VERSION 5.8 ;
BUSBITCHARS "[]" ;
DIVIDERCHAR "/" ;
UNITS
    DATABASE MICRONS 1000 ;
END UNITS

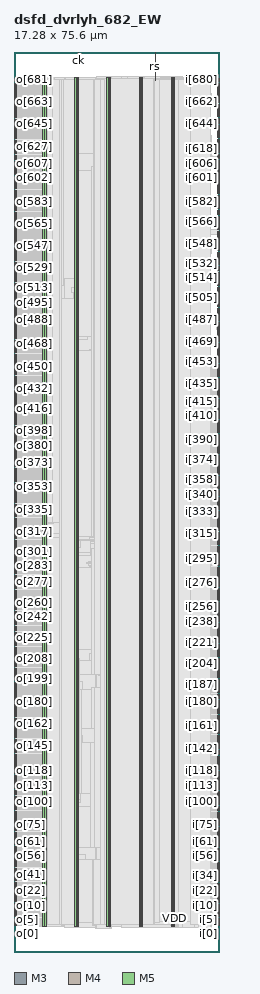
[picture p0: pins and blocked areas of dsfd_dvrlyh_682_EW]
MACRO dsfd_dvrlyh_682_EW
  FOREIGN dsfd_dvrlyh_682_EW 0 0 ;
  CLASS BLOCK ;
  SIZE 17.28 BY 75.6 ;
  PIN ck
    DIRECTION INPUT ;
    USE SIGNAL ;
    PORT
      LAYER M3 ;
        RECT  5.4 75.456 5.418 75.6 ;
    END
    PORT
      LAYER M3 ;
        RECT  5.4 74.683 5.418 75.468 ;
    END
  END ck
  PIN ck_o
    DIRECTION OUTPUT ;
    USE SIGNAL ;
    PORT
      LAYER M4 ;
        RECT  0 73.392 0.192 73.416 ;
    END
  END ck_o
  PIN i[0]
    DIRECTION INPUT ;
    USE SIGNAL ;
    PORT
      LAYER M4 ;
        RECT  17.088 2.208 17.28 2.232 ;
    END
  END i[0]
  PIN i[100]
    DIRECTION INPUT ;
    USE SIGNAL ;
    PORT
      LAYER M4 ;
        RECT  17.088 12.672 17.28 12.696 ;
    END
  END i[100]
  PIN i[101]
    DIRECTION INPUT ;
    USE SIGNAL ;
    PORT
      LAYER M4 ;
        RECT  17.088 12.768 17.28 12.792 ;
    END
  END i[101]
  PIN i[102]
    DIRECTION INPUT ;
    USE SIGNAL ;
    PORT
      LAYER M4 ;
        RECT  17.088 12.864 17.28 12.888 ;
    END
  END i[102]
  PIN i[103]
    DIRECTION INPUT ;
    USE SIGNAL ;
    PORT
      LAYER M4 ;
        RECT  17.088 13.008 17.28 13.032 ;
    END
  END i[103]
  PIN i[104]
    DIRECTION INPUT ;
    USE SIGNAL ;
    PORT
      LAYER M4 ;
        RECT  17.088 13.104 17.28 13.128 ;
    END
  END i[104]
  PIN i[105]
    DIRECTION INPUT ;
    USE SIGNAL ;
    PORT
      LAYER M4 ;
        RECT  17.088 13.2 17.28 13.224 ;
    END
  END i[105]
  PIN i[106]
    DIRECTION INPUT ;
    USE SIGNAL ;
    PORT
      LAYER M4 ;
        RECT  17.088 13.296 17.28 13.32 ;
    END
  END i[106]
  PIN i[107]
    DIRECTION INPUT ;
    USE SIGNAL ;
    PORT
      LAYER M4 ;
        RECT  17.088 13.392 17.28 13.416 ;
    END
  END i[107]
  PIN i[108]
    DIRECTION INPUT ;
    USE SIGNAL ;
    PORT
      LAYER M4 ;
        RECT  17.088 13.488 17.28 13.512 ;
    END
  END i[108]
  PIN i[109]
    DIRECTION INPUT ;
    USE SIGNAL ;
    PORT
      LAYER M4 ;
        RECT  17.088 13.632 17.28 13.656 ;
    END
  END i[109]
  PIN i[10]
    DIRECTION INPUT ;
    USE SIGNAL ;
    PORT
      LAYER M4 ;
        RECT  17.088 3.264 17.28 3.288 ;
    END
  END i[10]
  PIN i[110]
    DIRECTION INPUT ;
    USE SIGNAL ;
    PORT
      LAYER M4 ;
        RECT  17.088 13.728 17.28 13.752 ;
    END
  END i[110]
  PIN i[111]
    DIRECTION INPUT ;
    USE SIGNAL ;
    PORT
      LAYER M4 ;
        RECT  17.088 13.824 17.28 13.848 ;
    END
  END i[111]
  PIN i[112]
    DIRECTION INPUT ;
    USE SIGNAL ;
    PORT
      LAYER M4 ;
        RECT  17.088 13.92 17.28 13.944 ;
    END
  END i[112]
  PIN i[113]
    DIRECTION INPUT ;
    USE SIGNAL ;
    PORT
      LAYER M4 ;
        RECT  17.088 14.016 17.28 14.04 ;
    END
  END i[113]
  PIN i[114]
    DIRECTION INPUT ;
    USE SIGNAL ;
    PORT
      LAYER M4 ;
        RECT  17.088 14.16 17.28 14.184 ;
    END
  END i[114]
  PIN i[115]
    DIRECTION INPUT ;
    USE SIGNAL ;
    PORT
      LAYER M4 ;
        RECT  17.088 14.256 17.28 14.28 ;
    END
  END i[115]
  PIN i[116]
    DIRECTION INPUT ;
    USE SIGNAL ;
    PORT
      LAYER M4 ;
        RECT  17.088 14.352 17.28 14.376 ;
    END
  END i[116]
  PIN i[117]
    DIRECTION INPUT ;
    USE SIGNAL ;
    PORT
      LAYER M4 ;
        RECT  17.088 14.448 17.28 14.472 ;
    END
  END i[117]
  PIN i[118]
    DIRECTION INPUT ;
    USE SIGNAL ;
    PORT
      LAYER M4 ;
        RECT  17.088 14.544 17.28 14.568 ;
    END
  END i[118]
  PIN i[119]
    DIRECTION INPUT ;
    USE SIGNAL ;
    PORT
      LAYER M4 ;
        RECT  17.088 14.64 17.28 14.664 ;
    END
  END i[119]
  PIN i[11]
    DIRECTION INPUT ;
    USE SIGNAL ;
    PORT
      LAYER M4 ;
        RECT  17.088 3.36 17.28 3.384 ;
    END
  END i[11]
  PIN i[120]
    DIRECTION INPUT ;
    USE SIGNAL ;
    PORT
      LAYER M4 ;
        RECT  17.088 14.784 17.28 14.808 ;
    END
  END i[120]
  PIN i[121]
    DIRECTION INPUT ;
    USE SIGNAL ;
    PORT
      LAYER M4 ;
        RECT  17.088 14.88 17.28 14.904 ;
    END
  END i[121]
  PIN i[122]
    DIRECTION INPUT ;
    USE SIGNAL ;
    PORT
      LAYER M4 ;
        RECT  17.088 14.976 17.28 15 ;
    END
  END i[122]
  PIN i[123]
    DIRECTION INPUT ;
    USE SIGNAL ;
    PORT
      LAYER M4 ;
        RECT  17.088 15.072 17.28 15.096 ;
    END
  END i[123]
  PIN i[124]
    DIRECTION INPUT ;
    USE SIGNAL ;
    PORT
      LAYER M4 ;
        RECT  17.088 15.168 17.28 15.192 ;
    END
  END i[124]
  PIN i[125]
    DIRECTION INPUT ;
    USE SIGNAL ;
    PORT
      LAYER M4 ;
        RECT  17.088 15.312 17.28 15.336 ;
    END
  END i[125]
  PIN i[126]
    DIRECTION INPUT ;
    USE SIGNAL ;
    PORT
      LAYER M4 ;
        RECT  17.088 15.408 17.28 15.432 ;
    END
  END i[126]
  PIN i[127]
    DIRECTION INPUT ;
    USE SIGNAL ;
    PORT
      LAYER M4 ;
        RECT  17.088 15.504 17.28 15.528 ;
    END
  END i[127]
  PIN i[128]
    DIRECTION INPUT ;
    USE SIGNAL ;
    PORT
      LAYER M4 ;
        RECT  17.088 15.6 17.28 15.624 ;
    END
  END i[128]
  PIN i[129]
    DIRECTION INPUT ;
    USE SIGNAL ;
    PORT
      LAYER M4 ;
        RECT  17.088 15.696 17.28 15.72 ;
    END
  END i[129]
  PIN i[12]
    DIRECTION INPUT ;
    USE SIGNAL ;
    PORT
      LAYER M4 ;
        RECT  17.088 3.456 17.28 3.48 ;
    END
  END i[12]
  PIN i[130]
    DIRECTION INPUT ;
    USE SIGNAL ;
    PORT
      LAYER M4 ;
        RECT  17.088 15.792 17.28 15.816 ;
    END
  END i[130]
  PIN i[131]
    DIRECTION INPUT ;
    USE SIGNAL ;
    PORT
      LAYER M4 ;
        RECT  17.088 15.936 17.28 15.96 ;
    END
  END i[131]
  PIN i[132]
    DIRECTION INPUT ;
    USE SIGNAL ;
    PORT
      LAYER M4 ;
        RECT  17.088 16.032 17.28 16.056 ;
    END
  END i[132]
  PIN i[133]
    DIRECTION INPUT ;
    USE SIGNAL ;
    PORT
      LAYER M4 ;
        RECT  17.088 16.128 17.28 16.152 ;
    END
  END i[133]
  PIN i[134]
    DIRECTION INPUT ;
    USE SIGNAL ;
    PORT
      LAYER M4 ;
        RECT  17.088 16.224 17.28 16.248 ;
    END
  END i[134]
  PIN i[135]
    DIRECTION INPUT ;
    USE SIGNAL ;
    PORT
      LAYER M4 ;
        RECT  17.088 16.32 17.28 16.344 ;
    END
  END i[135]
  PIN i[136]
    DIRECTION INPUT ;
    USE SIGNAL ;
    PORT
      LAYER M4 ;
        RECT  17.088 16.416 17.28 16.44 ;
    END
  END i[136]
  PIN i[137]
    DIRECTION INPUT ;
    USE SIGNAL ;
    PORT
      LAYER M4 ;
        RECT  17.088 16.56 17.28 16.584 ;
    END
  END i[137]
  PIN i[138]
    DIRECTION INPUT ;
    USE SIGNAL ;
    PORT
      LAYER M4 ;
        RECT  17.088 16.656 17.28 16.68 ;
    END
  END i[138]
  PIN i[139]
    DIRECTION INPUT ;
    USE SIGNAL ;
    PORT
      LAYER M4 ;
        RECT  17.088 16.752 17.28 16.776 ;
    END
  END i[139]
  PIN i[13]
    DIRECTION INPUT ;
    USE SIGNAL ;
    PORT
      LAYER M4 ;
        RECT  17.088 3.6 17.28 3.624 ;
    END
  END i[13]
  PIN i[140]
    DIRECTION INPUT ;
    USE SIGNAL ;
    PORT
      LAYER M4 ;
        RECT  17.088 16.848 17.28 16.872 ;
    END
  END i[140]
  PIN i[141]
    DIRECTION INPUT ;
    USE SIGNAL ;
    PORT
      LAYER M4 ;
        RECT  17.088 16.944 17.28 16.968 ;
    END
  END i[141]
  PIN i[142]
    DIRECTION INPUT ;
    USE SIGNAL ;
    PORT
      LAYER M4 ;
        RECT  17.088 17.088 17.28 17.112 ;
    END
  END i[142]
  PIN i[143]
    DIRECTION INPUT ;
    USE SIGNAL ;
    PORT
      LAYER M4 ;
        RECT  17.088 17.184 17.28 17.208 ;
    END
  END i[143]
  PIN i[144]
    DIRECTION INPUT ;
    USE SIGNAL ;
    PORT
      LAYER M4 ;
        RECT  17.088 17.28 17.28 17.304 ;
    END
  END i[144]
  PIN i[145]
    DIRECTION INPUT ;
    USE SIGNAL ;
    PORT
      LAYER M4 ;
        RECT  17.088 17.376 17.28 17.4 ;
    END
  END i[145]
  PIN i[146]
    DIRECTION INPUT ;
    USE SIGNAL ;
    PORT
      LAYER M4 ;
        RECT  17.088 17.472 17.28 17.496 ;
    END
  END i[146]
  PIN i[147]
    DIRECTION INPUT ;
    USE SIGNAL ;
    PORT
      LAYER M4 ;
        RECT  17.088 17.568 17.28 17.592 ;
    END
  END i[147]
  PIN i[148]
    DIRECTION INPUT ;
    USE SIGNAL ;
    PORT
      LAYER M4 ;
        RECT  17.088 17.712 17.28 17.736 ;
    END
  END i[148]
  PIN i[149]
    DIRECTION INPUT ;
    USE SIGNAL ;
    PORT
      LAYER M4 ;
        RECT  17.088 17.808 17.28 17.832 ;
    END
  END i[149]
  PIN i[14]
    DIRECTION INPUT ;
    USE SIGNAL ;
    PORT
      LAYER M4 ;
        RECT  17.088 3.696 17.28 3.72 ;
    END
  END i[14]
  PIN i[150]
    DIRECTION INPUT ;
    USE SIGNAL ;
    PORT
      LAYER M4 ;
        RECT  17.088 17.904 17.28 17.928 ;
    END
  END i[150]
  PIN i[151]
    DIRECTION INPUT ;
    USE SIGNAL ;
    PORT
      LAYER M4 ;
        RECT  17.088 18 17.28 18.024 ;
    END
  END i[151]
  PIN i[152]
    DIRECTION INPUT ;
    USE SIGNAL ;
    PORT
      LAYER M4 ;
        RECT  17.088 18.096 17.28 18.12 ;
    END
  END i[152]
  PIN i[153]
    DIRECTION INPUT ;
    USE SIGNAL ;
    PORT
      LAYER M4 ;
        RECT  17.088 18.192 17.28 18.216 ;
    END
  END i[153]
  PIN i[154]
    DIRECTION INPUT ;
    USE SIGNAL ;
    PORT
      LAYER M4 ;
        RECT  17.088 18.336 17.28 18.36 ;
    END
  END i[154]
  PIN i[155]
    DIRECTION INPUT ;
    USE SIGNAL ;
    PORT
      LAYER M4 ;
        RECT  17.088 18.432 17.28 18.456 ;
    END
  END i[155]
  PIN i[156]
    DIRECTION INPUT ;
    USE SIGNAL ;
    PORT
      LAYER M4 ;
        RECT  17.088 18.528 17.28 18.552 ;
    END
  END i[156]
  PIN i[157]
    DIRECTION INPUT ;
    USE SIGNAL ;
    PORT
      LAYER M4 ;
        RECT  17.088 18.624 17.28 18.648 ;
    END
  END i[157]
  PIN i[158]
    DIRECTION INPUT ;
    USE SIGNAL ;
    PORT
      LAYER M4 ;
        RECT  17.088 18.72 17.28 18.744 ;
    END
  END i[158]
  PIN i[159]
    DIRECTION INPUT ;
    USE SIGNAL ;
    PORT
      LAYER M4 ;
        RECT  17.088 18.864 17.28 18.888 ;
    END
  END i[159]
  PIN i[15]
    DIRECTION INPUT ;
    USE SIGNAL ;
    PORT
      LAYER M4 ;
        RECT  17.088 3.792 17.28 3.816 ;
    END
  END i[15]
  PIN i[160]
    DIRECTION INPUT ;
    USE SIGNAL ;
    PORT
      LAYER M4 ;
        RECT  17.088 18.96 17.28 18.984 ;
    END
  END i[160]
  PIN i[161]
    DIRECTION INPUT ;
    USE SIGNAL ;
    PORT
      LAYER M4 ;
        RECT  17.088 19.056 17.28 19.08 ;
    END
  END i[161]
  PIN i[162]
    DIRECTION INPUT ;
    USE SIGNAL ;
    PORT
      LAYER M4 ;
        RECT  17.088 19.152 17.28 19.176 ;
    END
  END i[162]
  PIN i[163]
    DIRECTION INPUT ;
    USE SIGNAL ;
    PORT
      LAYER M4 ;
        RECT  17.088 19.248 17.28 19.272 ;
    END
  END i[163]
  PIN i[164]
    DIRECTION INPUT ;
    USE SIGNAL ;
    PORT
      LAYER M4 ;
        RECT  17.088 19.344 17.28 19.368 ;
    END
  END i[164]
  PIN i[165]
    DIRECTION INPUT ;
    USE SIGNAL ;
    PORT
      LAYER M4 ;
        RECT  17.088 19.488 17.28 19.512 ;
    END
  END i[165]
  PIN i[166]
    DIRECTION INPUT ;
    USE SIGNAL ;
    PORT
      LAYER M4 ;
        RECT  17.088 19.584 17.28 19.608 ;
    END
  END i[166]
  PIN i[167]
    DIRECTION INPUT ;
    USE SIGNAL ;
    PORT
      LAYER M4 ;
        RECT  17.088 19.68 17.28 19.704 ;
    END
  END i[167]
  PIN i[168]
    DIRECTION INPUT ;
    USE SIGNAL ;
    PORT
      LAYER M4 ;
        RECT  17.088 19.776 17.28 19.8 ;
    END
  END i[168]
  PIN i[169]
    DIRECTION INPUT ;
    USE SIGNAL ;
    PORT
      LAYER M4 ;
        RECT  17.088 19.872 17.28 19.896 ;
    END
  END i[169]
  PIN i[16]
    DIRECTION INPUT ;
    USE SIGNAL ;
    PORT
      LAYER M4 ;
        RECT  17.088 3.888 17.28 3.912 ;
    END
  END i[16]
  PIN i[170]
    DIRECTION INPUT ;
    USE SIGNAL ;
    PORT
      LAYER M4 ;
        RECT  17.088 20.016 17.28 20.04 ;
    END
  END i[170]
  PIN i[171]
    DIRECTION INPUT ;
    USE SIGNAL ;
    PORT
      LAYER M4 ;
        RECT  17.088 20.112 17.28 20.136 ;
    END
  END i[171]
  PIN i[172]
    DIRECTION INPUT ;
    USE SIGNAL ;
    PORT
      LAYER M4 ;
        RECT  17.088 20.208 17.28 20.232 ;
    END
  END i[172]
  PIN i[173]
    DIRECTION INPUT ;
    USE SIGNAL ;
    PORT
      LAYER M4 ;
        RECT  17.088 20.304 17.28 20.328 ;
    END
  END i[173]
  PIN i[174]
    DIRECTION INPUT ;
    USE SIGNAL ;
    PORT
      LAYER M4 ;
        RECT  17.088 20.4 17.28 20.424 ;
    END
  END i[174]
  PIN i[175]
    DIRECTION INPUT ;
    USE SIGNAL ;
    PORT
      LAYER M4 ;
        RECT  17.088 20.496 17.28 20.52 ;
    END
  END i[175]
  PIN i[176]
    DIRECTION INPUT ;
    USE SIGNAL ;
    PORT
      LAYER M4 ;
        RECT  17.088 20.64 17.28 20.664 ;
    END
  END i[176]
  PIN i[177]
    DIRECTION INPUT ;
    USE SIGNAL ;
    PORT
      LAYER M4 ;
        RECT  17.088 20.736 17.28 20.76 ;
    END
  END i[177]
  PIN i[178]
    DIRECTION INPUT ;
    USE SIGNAL ;
    PORT
      LAYER M4 ;
        RECT  17.088 20.832 17.28 20.856 ;
    END
  END i[178]
  PIN i[179]
    DIRECTION INPUT ;
    USE SIGNAL ;
    PORT
      LAYER M4 ;
        RECT  17.088 20.928 17.28 20.952 ;
    END
  END i[179]
  PIN i[17]
    DIRECTION INPUT ;
    USE SIGNAL ;
    PORT
      LAYER M4 ;
        RECT  17.088 3.984 17.28 4.008 ;
    END
  END i[17]
  PIN i[180]
    DIRECTION INPUT ;
    USE SIGNAL ;
    PORT
      LAYER M4 ;
        RECT  17.088 21.024 17.28 21.048 ;
    END
  END i[180]
  PIN i[181]
    DIRECTION INPUT ;
    USE SIGNAL ;
    PORT
      LAYER M4 ;
        RECT  17.088 21.12 17.28 21.144 ;
    END
  END i[181]
  PIN i[182]
    DIRECTION INPUT ;
    USE SIGNAL ;
    PORT
      LAYER M4 ;
        RECT  17.088 21.264 17.28 21.288 ;
    END
  END i[182]
  PIN i[183]
    DIRECTION INPUT ;
    USE SIGNAL ;
    PORT
      LAYER M4 ;
        RECT  17.088 21.36 17.28 21.384 ;
    END
  END i[183]
  PIN i[184]
    DIRECTION INPUT ;
    USE SIGNAL ;
    PORT
      LAYER M4 ;
        RECT  17.088 21.456 17.28 21.48 ;
    END
  END i[184]
  PIN i[185]
    DIRECTION INPUT ;
    USE SIGNAL ;
    PORT
      LAYER M4 ;
        RECT  17.088 21.552 17.28 21.576 ;
    END
  END i[185]
  PIN i[186]
    DIRECTION INPUT ;
    USE SIGNAL ;
    PORT
      LAYER M4 ;
        RECT  17.088 21.648 17.28 21.672 ;
    END
  END i[186]
  PIN i[187]
    DIRECTION INPUT ;
    USE SIGNAL ;
    PORT
      LAYER M4 ;
        RECT  17.088 21.792 17.28 21.816 ;
    END
  END i[187]
  PIN i[188]
    DIRECTION INPUT ;
    USE SIGNAL ;
    PORT
      LAYER M4 ;
        RECT  17.088 21.888 17.28 21.912 ;
    END
  END i[188]
  PIN i[189]
    DIRECTION INPUT ;
    USE SIGNAL ;
    PORT
      LAYER M4 ;
        RECT  17.088 21.984 17.28 22.008 ;
    END
  END i[189]
  PIN i[18]
    DIRECTION INPUT ;
    USE SIGNAL ;
    PORT
      LAYER M4 ;
        RECT  17.088 4.128 17.28 4.152 ;
    END
  END i[18]
  PIN i[190]
    DIRECTION INPUT ;
    USE SIGNAL ;
    PORT
      LAYER M4 ;
        RECT  17.088 22.08 17.28 22.104 ;
    END
  END i[190]
  PIN i[191]
    DIRECTION INPUT ;
    USE SIGNAL ;
    PORT
      LAYER M4 ;
        RECT  17.088 22.176 17.28 22.2 ;
    END
  END i[191]
  PIN i[192]
    DIRECTION INPUT ;
    USE SIGNAL ;
    PORT
      LAYER M4 ;
        RECT  17.088 22.272 17.28 22.296 ;
    END
  END i[192]
  PIN i[193]
    DIRECTION INPUT ;
    USE SIGNAL ;
    PORT
      LAYER M4 ;
        RECT  17.088 22.416 17.28 22.44 ;
    END
  END i[193]
  PIN i[194]
    DIRECTION INPUT ;
    USE SIGNAL ;
    PORT
      LAYER M4 ;
        RECT  17.088 22.512 17.28 22.536 ;
    END
  END i[194]
  PIN i[195]
    DIRECTION INPUT ;
    USE SIGNAL ;
    PORT
      LAYER M4 ;
        RECT  17.088 22.608 17.28 22.632 ;
    END
  END i[195]
  PIN i[196]
    DIRECTION INPUT ;
    USE SIGNAL ;
    PORT
      LAYER M4 ;
        RECT  17.088 22.704 17.28 22.728 ;
    END
  END i[196]
  PIN i[197]
    DIRECTION INPUT ;
    USE SIGNAL ;
    PORT
      LAYER M4 ;
        RECT  17.088 22.8 17.28 22.824 ;
    END
  END i[197]
  PIN i[198]
    DIRECTION INPUT ;
    USE SIGNAL ;
    PORT
      LAYER M4 ;
        RECT  17.088 22.896 17.28 22.92 ;
    END
  END i[198]
  PIN i[199]
    DIRECTION INPUT ;
    USE SIGNAL ;
    PORT
      LAYER M4 ;
        RECT  17.088 23.04 17.28 23.064 ;
    END
  END i[199]
  PIN i[19]
    DIRECTION INPUT ;
    USE SIGNAL ;
    PORT
      LAYER M4 ;
        RECT  17.088 4.224 17.28 4.248 ;
    END
  END i[19]
  PIN i[1]
    DIRECTION INPUT ;
    USE SIGNAL ;
    PORT
      LAYER M4 ;
        RECT  17.088 2.352 17.28 2.376 ;
    END
  END i[1]
  PIN i[200]
    DIRECTION INPUT ;
    USE SIGNAL ;
    PORT
      LAYER M4 ;
        RECT  17.088 23.136 17.28 23.16 ;
    END
  END i[200]
  PIN i[201]
    DIRECTION INPUT ;
    USE SIGNAL ;
    PORT
      LAYER M4 ;
        RECT  17.088 23.232 17.28 23.256 ;
    END
  END i[201]
  PIN i[202]
    DIRECTION INPUT ;
    USE SIGNAL ;
    PORT
      LAYER M4 ;
        RECT  17.088 23.328 17.28 23.352 ;
    END
  END i[202]
  PIN i[203]
    DIRECTION INPUT ;
    USE SIGNAL ;
    PORT
      LAYER M4 ;
        RECT  17.088 23.424 17.28 23.448 ;
    END
  END i[203]
  PIN i[204]
    DIRECTION INPUT ;
    USE SIGNAL ;
    PORT
      LAYER M4 ;
        RECT  17.088 23.568 17.28 23.592 ;
    END
  END i[204]
  PIN i[205]
    DIRECTION INPUT ;
    USE SIGNAL ;
    PORT
      LAYER M4 ;
        RECT  17.088 23.664 17.28 23.688 ;
    END
  END i[205]
  PIN i[206]
    DIRECTION INPUT ;
    USE SIGNAL ;
    PORT
      LAYER M4 ;
        RECT  17.088 23.76 17.28 23.784 ;
    END
  END i[206]
  PIN i[207]
    DIRECTION INPUT ;
    USE SIGNAL ;
    PORT
      LAYER M4 ;
        RECT  17.088 23.856 17.28 23.88 ;
    END
  END i[207]
  PIN i[208]
    DIRECTION INPUT ;
    USE SIGNAL ;
    PORT
      LAYER M4 ;
        RECT  17.088 23.952 17.28 23.976 ;
    END
  END i[208]
  PIN i[209]
    DIRECTION INPUT ;
    USE SIGNAL ;
    PORT
      LAYER M4 ;
        RECT  17.088 24.048 17.28 24.072 ;
    END
  END i[209]
  PIN i[20]
    DIRECTION INPUT ;
    USE SIGNAL ;
    PORT
      LAYER M4 ;
        RECT  17.088 4.32 17.28 4.344 ;
    END
  END i[20]
  PIN i[210]
    DIRECTION INPUT ;
    USE SIGNAL ;
    PORT
      LAYER M4 ;
        RECT  17.088 24.192 17.28 24.216 ;
    END
  END i[210]
  PIN i[211]
    DIRECTION INPUT ;
    USE SIGNAL ;
    PORT
      LAYER M4 ;
        RECT  17.088 24.288 17.28 24.312 ;
    END
  END i[211]
  PIN i[212]
    DIRECTION INPUT ;
    USE SIGNAL ;
    PORT
      LAYER M4 ;
        RECT  17.088 24.384 17.28 24.408 ;
    END
  END i[212]
  PIN i[213]
    DIRECTION INPUT ;
    USE SIGNAL ;
    PORT
      LAYER M4 ;
        RECT  17.088 24.48 17.28 24.504 ;
    END
  END i[213]
  PIN i[214]
    DIRECTION INPUT ;
    USE SIGNAL ;
    PORT
      LAYER M4 ;
        RECT  17.088 24.576 17.28 24.6 ;
    END
  END i[214]
  PIN i[215]
    DIRECTION INPUT ;
    USE SIGNAL ;
    PORT
      LAYER M4 ;
        RECT  17.088 24.672 17.28 24.696 ;
    END
  END i[215]
  PIN i[216]
    DIRECTION INPUT ;
    USE SIGNAL ;
    PORT
      LAYER M4 ;
        RECT  17.088 24.816 17.28 24.84 ;
    END
  END i[216]
  PIN i[217]
    DIRECTION INPUT ;
    USE SIGNAL ;
    PORT
      LAYER M4 ;
        RECT  17.088 24.912 17.28 24.936 ;
    END
  END i[217]
  PIN i[218]
    DIRECTION INPUT ;
    USE SIGNAL ;
    PORT
      LAYER M4 ;
        RECT  17.088 25.008 17.28 25.032 ;
    END
  END i[218]
  PIN i[219]
    DIRECTION INPUT ;
    USE SIGNAL ;
    PORT
      LAYER M4 ;
        RECT  17.088 25.104 17.28 25.128 ;
    END
  END i[219]
  PIN i[21]
    DIRECTION INPUT ;
    USE SIGNAL ;
    PORT
      LAYER M4 ;
        RECT  17.088 4.416 17.28 4.44 ;
    END
  END i[21]
  PIN i[220]
    DIRECTION INPUT ;
    USE SIGNAL ;
    PORT
      LAYER M4 ;
        RECT  17.088 25.2 17.28 25.224 ;
    END
  END i[220]
  PIN i[221]
    DIRECTION INPUT ;
    USE SIGNAL ;
    PORT
      LAYER M4 ;
        RECT  17.088 25.344 17.28 25.368 ;
    END
  END i[221]
  PIN i[222]
    DIRECTION INPUT ;
    USE SIGNAL ;
    PORT
      LAYER M4 ;
        RECT  17.088 25.44 17.28 25.464 ;
    END
  END i[222]
  PIN i[223]
    DIRECTION INPUT ;
    USE SIGNAL ;
    PORT
      LAYER M4 ;
        RECT  17.088 25.536 17.28 25.56 ;
    END
  END i[223]
  PIN i[224]
    DIRECTION INPUT ;
    USE SIGNAL ;
    PORT
      LAYER M4 ;
        RECT  17.088 25.632 17.28 25.656 ;
    END
  END i[224]
  PIN i[225]
    DIRECTION INPUT ;
    USE SIGNAL ;
    PORT
      LAYER M4 ;
        RECT  17.088 25.728 17.28 25.752 ;
    END
  END i[225]
  PIN i[226]
    DIRECTION INPUT ;
    USE SIGNAL ;
    PORT
      LAYER M4 ;
        RECT  17.088 25.824 17.28 25.848 ;
    END
  END i[226]
  PIN i[227]
    DIRECTION INPUT ;
    USE SIGNAL ;
    PORT
      LAYER M4 ;
        RECT  17.088 25.968 17.28 25.992 ;
    END
  END i[227]
  PIN i[228]
    DIRECTION INPUT ;
    USE SIGNAL ;
    PORT
      LAYER M4 ;
        RECT  17.088 26.064 17.28 26.088 ;
    END
  END i[228]
  PIN i[229]
    DIRECTION INPUT ;
    USE SIGNAL ;
    PORT
      LAYER M4 ;
        RECT  17.088 26.16 17.28 26.184 ;
    END
  END i[229]
  PIN i[22]
    DIRECTION INPUT ;
    USE SIGNAL ;
    PORT
      LAYER M4 ;
        RECT  17.088 4.512 17.28 4.536 ;
    END
  END i[22]
  PIN i[230]
    DIRECTION INPUT ;
    USE SIGNAL ;
    PORT
      LAYER M4 ;
        RECT  17.088 26.256 17.28 26.28 ;
    END
  END i[230]
  PIN i[231]
    DIRECTION INPUT ;
    USE SIGNAL ;
    PORT
      LAYER M4 ;
        RECT  17.088 26.352 17.28 26.376 ;
    END
  END i[231]
  PIN i[232]
    DIRECTION INPUT ;
    USE SIGNAL ;
    PORT
      LAYER M4 ;
        RECT  17.088 26.448 17.28 26.472 ;
    END
  END i[232]
  PIN i[233]
    DIRECTION INPUT ;
    USE SIGNAL ;
    PORT
      LAYER M4 ;
        RECT  17.088 26.592 17.28 26.616 ;
    END
  END i[233]
  PIN i[234]
    DIRECTION INPUT ;
    USE SIGNAL ;
    PORT
      LAYER M4 ;
        RECT  17.088 26.688 17.28 26.712 ;
    END
  END i[234]
  PIN i[235]
    DIRECTION INPUT ;
    USE SIGNAL ;
    PORT
      LAYER M4 ;
        RECT  17.088 26.784 17.28 26.808 ;
    END
  END i[235]
  PIN i[236]
    DIRECTION INPUT ;
    USE SIGNAL ;
    PORT
      LAYER M4 ;
        RECT  17.088 26.88 17.28 26.904 ;
    END
  END i[236]
  PIN i[237]
    DIRECTION INPUT ;
    USE SIGNAL ;
    PORT
      LAYER M4 ;
        RECT  17.088 26.976 17.28 27 ;
    END
  END i[237]
  PIN i[238]
    DIRECTION INPUT ;
    USE SIGNAL ;
    PORT
      LAYER M4 ;
        RECT  17.088 27.12 17.28 27.144 ;
    END
  END i[238]
  PIN i[239]
    DIRECTION INPUT ;
    USE SIGNAL ;
    PORT
      LAYER M4 ;
        RECT  17.088 27.216 17.28 27.24 ;
    END
  END i[239]
  PIN i[23]
    DIRECTION INPUT ;
    USE SIGNAL ;
    PORT
      LAYER M4 ;
        RECT  17.088 4.608 17.28 4.632 ;
    END
  END i[23]
  PIN i[240]
    DIRECTION INPUT ;
    USE SIGNAL ;
    PORT
      LAYER M4 ;
        RECT  17.088 27.312 17.28 27.336 ;
    END
  END i[240]
  PIN i[241]
    DIRECTION INPUT ;
    USE SIGNAL ;
    PORT
      LAYER M4 ;
        RECT  17.088 27.408 17.28 27.432 ;
    END
  END i[241]
  PIN i[242]
    DIRECTION INPUT ;
    USE SIGNAL ;
    PORT
      LAYER M4 ;
        RECT  17.088 27.504 17.28 27.528 ;
    END
  END i[242]
  PIN i[243]
    DIRECTION INPUT ;
    USE SIGNAL ;
    PORT
      LAYER M4 ;
        RECT  17.088 27.6 17.28 27.624 ;
    END
  END i[243]
  PIN i[244]
    DIRECTION INPUT ;
    USE SIGNAL ;
    PORT
      LAYER M4 ;
        RECT  17.088 27.744 17.28 27.768 ;
    END
  END i[244]
  PIN i[245]
    DIRECTION INPUT ;
    USE SIGNAL ;
    PORT
      LAYER M4 ;
        RECT  17.088 27.84 17.28 27.864 ;
    END
  END i[245]
  PIN i[246]
    DIRECTION INPUT ;
    USE SIGNAL ;
    PORT
      LAYER M4 ;
        RECT  17.088 27.936 17.28 27.96 ;
    END
  END i[246]
  PIN i[247]
    DIRECTION INPUT ;
    USE SIGNAL ;
    PORT
      LAYER M4 ;
        RECT  17.088 28.032 17.28 28.056 ;
    END
  END i[247]
  PIN i[248]
    DIRECTION INPUT ;
    USE SIGNAL ;
    PORT
      LAYER M4 ;
        RECT  17.088 28.128 17.28 28.152 ;
    END
  END i[248]
  PIN i[249]
    DIRECTION INPUT ;
    USE SIGNAL ;
    PORT
      LAYER M4 ;
        RECT  17.088 28.272 17.28 28.296 ;
    END
  END i[249]
  PIN i[24]
    DIRECTION INPUT ;
    USE SIGNAL ;
    PORT
      LAYER M4 ;
        RECT  17.088 4.752 17.28 4.776 ;
    END
  END i[24]
  PIN i[250]
    DIRECTION INPUT ;
    USE SIGNAL ;
    PORT
      LAYER M4 ;
        RECT  17.088 28.368 17.28 28.392 ;
    END
  END i[250]
  PIN i[251]
    DIRECTION INPUT ;
    USE SIGNAL ;
    PORT
      LAYER M4 ;
        RECT  17.088 28.464 17.28 28.488 ;
    END
  END i[251]
  PIN i[252]
    DIRECTION INPUT ;
    USE SIGNAL ;
    PORT
      LAYER M4 ;
        RECT  17.088 28.56 17.28 28.584 ;
    END
  END i[252]
  PIN i[253]
    DIRECTION INPUT ;
    USE SIGNAL ;
    PORT
      LAYER M4 ;
        RECT  17.088 28.656 17.28 28.68 ;
    END
  END i[253]
  PIN i[254]
    DIRECTION INPUT ;
    USE SIGNAL ;
    PORT
      LAYER M4 ;
        RECT  17.088 28.752 17.28 28.776 ;
    END
  END i[254]
  PIN i[255]
    DIRECTION INPUT ;
    USE SIGNAL ;
    PORT
      LAYER M4 ;
        RECT  17.088 28.896 17.28 28.92 ;
    END
  END i[255]
  PIN i[256]
    DIRECTION INPUT ;
    USE SIGNAL ;
    PORT
      LAYER M4 ;
        RECT  17.088 28.992 17.28 29.016 ;
    END
  END i[256]
  PIN i[257]
    DIRECTION INPUT ;
    USE SIGNAL ;
    PORT
      LAYER M4 ;
        RECT  17.088 29.088 17.28 29.112 ;
    END
  END i[257]
  PIN i[258]
    DIRECTION INPUT ;
    USE SIGNAL ;
    PORT
      LAYER M4 ;
        RECT  17.088 29.184 17.28 29.208 ;
    END
  END i[258]
  PIN i[259]
    DIRECTION INPUT ;
    USE SIGNAL ;
    PORT
      LAYER M4 ;
        RECT  17.088 29.28 17.28 29.304 ;
    END
  END i[259]
  PIN i[25]
    DIRECTION INPUT ;
    USE SIGNAL ;
    PORT
      LAYER M4 ;
        RECT  17.088 4.848 17.28 4.872 ;
    END
  END i[25]
  PIN i[260]
    DIRECTION INPUT ;
    USE SIGNAL ;
    PORT
      LAYER M4 ;
        RECT  17.088 29.376 17.28 29.4 ;
    END
  END i[260]
  PIN i[261]
    DIRECTION INPUT ;
    USE SIGNAL ;
    PORT
      LAYER M4 ;
        RECT  17.088 29.52 17.28 29.544 ;
    END
  END i[261]
  PIN i[262]
    DIRECTION INPUT ;
    USE SIGNAL ;
    PORT
      LAYER M4 ;
        RECT  17.088 29.616 17.28 29.64 ;
    END
  END i[262]
  PIN i[263]
    DIRECTION INPUT ;
    USE SIGNAL ;
    PORT
      LAYER M4 ;
        RECT  17.088 29.712 17.28 29.736 ;
    END
  END i[263]
  PIN i[264]
    DIRECTION INPUT ;
    USE SIGNAL ;
    PORT
      LAYER M4 ;
        RECT  17.088 29.808 17.28 29.832 ;
    END
  END i[264]
  PIN i[265]
    DIRECTION INPUT ;
    USE SIGNAL ;
    PORT
      LAYER M4 ;
        RECT  17.088 29.904 17.28 29.928 ;
    END
  END i[265]
  PIN i[266]
    DIRECTION INPUT ;
    USE SIGNAL ;
    PORT
      LAYER M4 ;
        RECT  17.088 30.048 17.28 30.072 ;
    END
  END i[266]
  PIN i[267]
    DIRECTION INPUT ;
    USE SIGNAL ;
    PORT
      LAYER M4 ;
        RECT  17.088 30.144 17.28 30.168 ;
    END
  END i[267]
  PIN i[268]
    DIRECTION INPUT ;
    USE SIGNAL ;
    PORT
      LAYER M4 ;
        RECT  17.088 30.24 17.28 30.264 ;
    END
  END i[268]
  PIN i[269]
    DIRECTION INPUT ;
    USE SIGNAL ;
    PORT
      LAYER M4 ;
        RECT  17.088 30.336 17.28 30.36 ;
    END
  END i[269]
  PIN i[26]
    DIRECTION INPUT ;
    USE SIGNAL ;
    PORT
      LAYER M4 ;
        RECT  17.088 4.944 17.28 4.968 ;
    END
  END i[26]
  PIN i[270]
    DIRECTION INPUT ;
    USE SIGNAL ;
    PORT
      LAYER M4 ;
        RECT  17.088 30.432 17.28 30.456 ;
    END
  END i[270]
  PIN i[271]
    DIRECTION INPUT ;
    USE SIGNAL ;
    PORT
      LAYER M4 ;
        RECT  17.088 30.528 17.28 30.552 ;
    END
  END i[271]
  PIN i[272]
    DIRECTION INPUT ;
    USE SIGNAL ;
    PORT
      LAYER M4 ;
        RECT  17.088 30.672 17.28 30.696 ;
    END
  END i[272]
  PIN i[273]
    DIRECTION INPUT ;
    USE SIGNAL ;
    PORT
      LAYER M4 ;
        RECT  17.088 30.768 17.28 30.792 ;
    END
  END i[273]
  PIN i[274]
    DIRECTION INPUT ;
    USE SIGNAL ;
    PORT
      LAYER M4 ;
        RECT  17.088 30.864 17.28 30.888 ;
    END
  END i[274]
  PIN i[275]
    DIRECTION INPUT ;
    USE SIGNAL ;
    PORT
      LAYER M4 ;
        RECT  17.088 30.96 17.28 30.984 ;
    END
  END i[275]
  PIN i[276]
    DIRECTION INPUT ;
    USE SIGNAL ;
    PORT
      LAYER M4 ;
        RECT  17.088 31.056 17.28 31.08 ;
    END
  END i[276]
  PIN i[277]
    DIRECTION INPUT ;
    USE SIGNAL ;
    PORT
      LAYER M4 ;
        RECT  17.088 31.152 17.28 31.176 ;
    END
  END i[277]
  PIN i[278]
    DIRECTION INPUT ;
    USE SIGNAL ;
    PORT
      LAYER M4 ;
        RECT  17.088 31.296 17.28 31.32 ;
    END
  END i[278]
  PIN i[279]
    DIRECTION INPUT ;
    USE SIGNAL ;
    PORT
      LAYER M4 ;
        RECT  17.088 31.392 17.28 31.416 ;
    END
  END i[279]
  PIN i[27]
    DIRECTION INPUT ;
    USE SIGNAL ;
    PORT
      LAYER M4 ;
        RECT  17.088 5.04 17.28 5.064 ;
    END
  END i[27]
  PIN i[280]
    DIRECTION INPUT ;
    USE SIGNAL ;
    PORT
      LAYER M4 ;
        RECT  17.088 31.488 17.28 31.512 ;
    END
  END i[280]
  PIN i[281]
    DIRECTION INPUT ;
    USE SIGNAL ;
    PORT
      LAYER M4 ;
        RECT  17.088 31.584 17.28 31.608 ;
    END
  END i[281]
  PIN i[282]
    DIRECTION INPUT ;
    USE SIGNAL ;
    PORT
      LAYER M4 ;
        RECT  17.088 31.68 17.28 31.704 ;
    END
  END i[282]
  PIN i[283]
    DIRECTION INPUT ;
    USE SIGNAL ;
    PORT
      LAYER M4 ;
        RECT  17.088 31.824 17.28 31.848 ;
    END
  END i[283]
  PIN i[284]
    DIRECTION INPUT ;
    USE SIGNAL ;
    PORT
      LAYER M4 ;
        RECT  17.088 31.92 17.28 31.944 ;
    END
  END i[284]
  PIN i[285]
    DIRECTION INPUT ;
    USE SIGNAL ;
    PORT
      LAYER M4 ;
        RECT  17.088 32.016 17.28 32.04 ;
    END
  END i[285]
  PIN i[286]
    DIRECTION INPUT ;
    USE SIGNAL ;
    PORT
      LAYER M4 ;
        RECT  17.088 32.112 17.28 32.136 ;
    END
  END i[286]
  PIN i[287]
    DIRECTION INPUT ;
    USE SIGNAL ;
    PORT
      LAYER M4 ;
        RECT  17.088 32.208 17.28 32.232 ;
    END
  END i[287]
  PIN i[288]
    DIRECTION INPUT ;
    USE SIGNAL ;
    PORT
      LAYER M4 ;
        RECT  17.088 32.304 17.28 32.328 ;
    END
  END i[288]
  PIN i[289]
    DIRECTION INPUT ;
    USE SIGNAL ;
    PORT
      LAYER M4 ;
        RECT  17.088 32.448 17.28 32.472 ;
    END
  END i[289]
  PIN i[28]
    DIRECTION INPUT ;
    USE SIGNAL ;
    PORT
      LAYER M4 ;
        RECT  17.088 5.136 17.28 5.16 ;
    END
  END i[28]
  PIN i[290]
    DIRECTION INPUT ;
    USE SIGNAL ;
    PORT
      LAYER M4 ;
        RECT  17.088 32.544 17.28 32.568 ;
    END
  END i[290]
  PIN i[291]
    DIRECTION INPUT ;
    USE SIGNAL ;
    PORT
      LAYER M4 ;
        RECT  17.088 32.64 17.28 32.664 ;
    END
  END i[291]
  PIN i[292]
    DIRECTION INPUT ;
    USE SIGNAL ;
    PORT
      LAYER M4 ;
        RECT  17.088 32.736 17.28 32.76 ;
    END
  END i[292]
  PIN i[293]
    DIRECTION INPUT ;
    USE SIGNAL ;
    PORT
      LAYER M4 ;
        RECT  17.088 32.832 17.28 32.856 ;
    END
  END i[293]
  PIN i[294]
    DIRECTION INPUT ;
    USE SIGNAL ;
    PORT
      LAYER M4 ;
        RECT  17.088 32.928 17.28 32.952 ;
    END
  END i[294]
  PIN i[295]
    DIRECTION INPUT ;
    USE SIGNAL ;
    PORT
      LAYER M4 ;
        RECT  17.088 33.072 17.28 33.096 ;
    END
  END i[295]
  PIN i[296]
    DIRECTION INPUT ;
    USE SIGNAL ;
    PORT
      LAYER M4 ;
        RECT  17.088 33.168 17.28 33.192 ;
    END
  END i[296]
  PIN i[297]
    DIRECTION INPUT ;
    USE SIGNAL ;
    PORT
      LAYER M4 ;
        RECT  17.088 33.264 17.28 33.288 ;
    END
  END i[297]
  PIN i[298]
    DIRECTION INPUT ;
    USE SIGNAL ;
    PORT
      LAYER M4 ;
        RECT  17.088 33.36 17.28 33.384 ;
    END
  END i[298]
  PIN i[299]
    DIRECTION INPUT ;
    USE SIGNAL ;
    PORT
      LAYER M4 ;
        RECT  17.088 33.456 17.28 33.48 ;
    END
  END i[299]
  PIN i[29]
    DIRECTION INPUT ;
    USE SIGNAL ;
    PORT
      LAYER M4 ;
        RECT  17.088 5.232 17.28 5.256 ;
    END
  END i[29]
  PIN i[2]
    DIRECTION INPUT ;
    USE SIGNAL ;
    PORT
      LAYER M4 ;
        RECT  17.088 2.448 17.28 2.472 ;
    END
  END i[2]
  PIN i[300]
    DIRECTION INPUT ;
    USE SIGNAL ;
    PORT
      LAYER M4 ;
        RECT  17.088 33.6 17.28 33.624 ;
    END
  END i[300]
  PIN i[301]
    DIRECTION INPUT ;
    USE SIGNAL ;
    PORT
      LAYER M4 ;
        RECT  17.088 33.696 17.28 33.72 ;
    END
  END i[301]
  PIN i[302]
    DIRECTION INPUT ;
    USE SIGNAL ;
    PORT
      LAYER M4 ;
        RECT  17.088 33.792 17.28 33.816 ;
    END
  END i[302]
  PIN i[303]
    DIRECTION INPUT ;
    USE SIGNAL ;
    PORT
      LAYER M4 ;
        RECT  17.088 33.888 17.28 33.912 ;
    END
  END i[303]
  PIN i[304]
    DIRECTION INPUT ;
    USE SIGNAL ;
    PORT
      LAYER M4 ;
        RECT  17.088 33.984 17.28 34.008 ;
    END
  END i[304]
  PIN i[305]
    DIRECTION INPUT ;
    USE SIGNAL ;
    PORT
      LAYER M4 ;
        RECT  17.088 34.08 17.28 34.104 ;
    END
  END i[305]
  PIN i[306]
    DIRECTION INPUT ;
    USE SIGNAL ;
    PORT
      LAYER M4 ;
        RECT  17.088 34.224 17.28 34.248 ;
    END
  END i[306]
  PIN i[307]
    DIRECTION INPUT ;
    USE SIGNAL ;
    PORT
      LAYER M4 ;
        RECT  17.088 34.32 17.28 34.344 ;
    END
  END i[307]
  PIN i[308]
    DIRECTION INPUT ;
    USE SIGNAL ;
    PORT
      LAYER M4 ;
        RECT  17.088 34.416 17.28 34.44 ;
    END
  END i[308]
  PIN i[309]
    DIRECTION INPUT ;
    USE SIGNAL ;
    PORT
      LAYER M4 ;
        RECT  17.088 34.512 17.28 34.536 ;
    END
  END i[309]
  PIN i[30]
    DIRECTION INPUT ;
    USE SIGNAL ;
    PORT
      LAYER M4 ;
        RECT  17.088 5.376 17.28 5.4 ;
    END
  END i[30]
  PIN i[310]
    DIRECTION INPUT ;
    USE SIGNAL ;
    PORT
      LAYER M4 ;
        RECT  17.088 34.608 17.28 34.632 ;
    END
  END i[310]
  PIN i[311]
    DIRECTION INPUT ;
    USE SIGNAL ;
    PORT
      LAYER M4 ;
        RECT  17.088 34.752 17.28 34.776 ;
    END
  END i[311]
  PIN i[312]
    DIRECTION INPUT ;
    USE SIGNAL ;
    PORT
      LAYER M4 ;
        RECT  17.088 34.848 17.28 34.872 ;
    END
  END i[312]
  PIN i[313]
    DIRECTION INPUT ;
    USE SIGNAL ;
    PORT
      LAYER M4 ;
        RECT  17.088 34.944 17.28 34.968 ;
    END
  END i[313]
  PIN i[314]
    DIRECTION INPUT ;
    USE SIGNAL ;
    PORT
      LAYER M4 ;
        RECT  17.088 35.04 17.28 35.064 ;
    END
  END i[314]
  PIN i[315]
    DIRECTION INPUT ;
    USE SIGNAL ;
    PORT
      LAYER M4 ;
        RECT  17.088 35.136 17.28 35.16 ;
    END
  END i[315]
  PIN i[316]
    DIRECTION INPUT ;
    USE SIGNAL ;
    PORT
      LAYER M4 ;
        RECT  17.088 35.232 17.28 35.256 ;
    END
  END i[316]
  PIN i[317]
    DIRECTION INPUT ;
    USE SIGNAL ;
    PORT
      LAYER M4 ;
        RECT  17.088 35.376 17.28 35.4 ;
    END
  END i[317]
  PIN i[318]
    DIRECTION INPUT ;
    USE SIGNAL ;
    PORT
      LAYER M4 ;
        RECT  17.088 35.472 17.28 35.496 ;
    END
  END i[318]
  PIN i[319]
    DIRECTION INPUT ;
    USE SIGNAL ;
    PORT
      LAYER M4 ;
        RECT  17.088 35.568 17.28 35.592 ;
    END
  END i[319]
  PIN i[31]
    DIRECTION INPUT ;
    USE SIGNAL ;
    PORT
      LAYER M4 ;
        RECT  17.088 5.472 17.28 5.496 ;
    END
  END i[31]
  PIN i[320]
    DIRECTION INPUT ;
    USE SIGNAL ;
    PORT
      LAYER M4 ;
        RECT  17.088 35.664 17.28 35.688 ;
    END
  END i[320]
  PIN i[321]
    DIRECTION INPUT ;
    USE SIGNAL ;
    PORT
      LAYER M4 ;
        RECT  17.088 35.76 17.28 35.784 ;
    END
  END i[321]
  PIN i[322]
    DIRECTION INPUT ;
    USE SIGNAL ;
    PORT
      LAYER M4 ;
        RECT  17.088 35.856 17.28 35.88 ;
    END
  END i[322]
  PIN i[323]
    DIRECTION INPUT ;
    USE SIGNAL ;
    PORT
      LAYER M4 ;
        RECT  17.088 36 17.28 36.024 ;
    END
  END i[323]
  PIN i[324]
    DIRECTION INPUT ;
    USE SIGNAL ;
    PORT
      LAYER M4 ;
        RECT  17.088 36.096 17.28 36.12 ;
    END
  END i[324]
  PIN i[325]
    DIRECTION INPUT ;
    USE SIGNAL ;
    PORT
      LAYER M4 ;
        RECT  17.088 36.192 17.28 36.216 ;
    END
  END i[325]
  PIN i[326]
    DIRECTION INPUT ;
    USE SIGNAL ;
    PORT
      LAYER M4 ;
        RECT  17.088 36.288 17.28 36.312 ;
    END
  END i[326]
  PIN i[327]
    DIRECTION INPUT ;
    USE SIGNAL ;
    PORT
      LAYER M4 ;
        RECT  17.088 36.384 17.28 36.408 ;
    END
  END i[327]
  PIN i[328]
    DIRECTION INPUT ;
    USE SIGNAL ;
    PORT
      LAYER M4 ;
        RECT  17.088 36.528 17.28 36.552 ;
    END
  END i[328]
  PIN i[329]
    DIRECTION INPUT ;
    USE SIGNAL ;
    PORT
      LAYER M4 ;
        RECT  17.088 36.624 17.28 36.648 ;
    END
  END i[329]
  PIN i[32]
    DIRECTION INPUT ;
    USE SIGNAL ;
    PORT
      LAYER M4 ;
        RECT  17.088 5.568 17.28 5.592 ;
    END
  END i[32]
  PIN i[330]
    DIRECTION INPUT ;
    USE SIGNAL ;
    PORT
      LAYER M4 ;
        RECT  17.088 36.72 17.28 36.744 ;
    END
  END i[330]
  PIN i[331]
    DIRECTION INPUT ;
    USE SIGNAL ;
    PORT
      LAYER M4 ;
        RECT  17.088 36.816 17.28 36.84 ;
    END
  END i[331]
  PIN i[332]
    DIRECTION INPUT ;
    USE SIGNAL ;
    PORT
      LAYER M4 ;
        RECT  17.088 36.912 17.28 36.936 ;
    END
  END i[332]
  PIN i[333]
    DIRECTION INPUT ;
    USE SIGNAL ;
    PORT
      LAYER M4 ;
        RECT  17.088 37.008 17.28 37.032 ;
    END
  END i[333]
  PIN i[334]
    DIRECTION INPUT ;
    USE SIGNAL ;
    PORT
      LAYER M4 ;
        RECT  17.088 37.152 17.28 37.176 ;
    END
  END i[334]
  PIN i[335]
    DIRECTION INPUT ;
    USE SIGNAL ;
    PORT
      LAYER M4 ;
        RECT  17.088 37.248 17.28 37.272 ;
    END
  END i[335]
  PIN i[336]
    DIRECTION INPUT ;
    USE SIGNAL ;
    PORT
      LAYER M4 ;
        RECT  17.088 37.344 17.28 37.368 ;
    END
  END i[336]
  PIN i[337]
    DIRECTION INPUT ;
    USE SIGNAL ;
    PORT
      LAYER M4 ;
        RECT  17.088 37.44 17.28 37.464 ;
    END
  END i[337]
  PIN i[338]
    DIRECTION INPUT ;
    USE SIGNAL ;
    PORT
      LAYER M4 ;
        RECT  17.088 37.536 17.28 37.56 ;
    END
  END i[338]
  PIN i[339]
    DIRECTION INPUT ;
    USE SIGNAL ;
    PORT
      LAYER M4 ;
        RECT  17.088 37.632 17.28 37.656 ;
    END
  END i[339]
  PIN i[33]
    DIRECTION INPUT ;
    USE SIGNAL ;
    PORT
      LAYER M4 ;
        RECT  17.088 5.664 17.28 5.688 ;
    END
  END i[33]
  PIN i[340]
    DIRECTION INPUT ;
    USE SIGNAL ;
    PORT
      LAYER M4 ;
        RECT  17.088 37.776 17.28 37.8 ;
    END
  END i[340]
  PIN i[341]
    DIRECTION INPUT ;
    USE SIGNAL ;
    PORT
      LAYER M4 ;
        RECT  17.088 37.872 17.28 37.896 ;
    END
  END i[341]
  PIN i[342]
    DIRECTION INPUT ;
    USE SIGNAL ;
    PORT
      LAYER M4 ;
        RECT  17.088 37.968 17.28 37.992 ;
    END
  END i[342]
  PIN i[343]
    DIRECTION INPUT ;
    USE SIGNAL ;
    PORT
      LAYER M4 ;
        RECT  17.088 38.064 17.28 38.088 ;
    END
  END i[343]
  PIN i[344]
    DIRECTION INPUT ;
    USE SIGNAL ;
    PORT
      LAYER M4 ;
        RECT  17.088 38.16 17.28 38.184 ;
    END
  END i[344]
  PIN i[345]
    DIRECTION INPUT ;
    USE SIGNAL ;
    PORT
      LAYER M4 ;
        RECT  17.088 38.304 17.28 38.328 ;
    END
  END i[345]
  PIN i[346]
    DIRECTION INPUT ;
    USE SIGNAL ;
    PORT
      LAYER M4 ;
        RECT  17.088 38.4 17.28 38.424 ;
    END
  END i[346]
  PIN i[347]
    DIRECTION INPUT ;
    USE SIGNAL ;
    PORT
      LAYER M4 ;
        RECT  17.088 38.496 17.28 38.52 ;
    END
  END i[347]
  PIN i[348]
    DIRECTION INPUT ;
    USE SIGNAL ;
    PORT
      LAYER M4 ;
        RECT  17.088 38.592 17.28 38.616 ;
    END
  END i[348]
  PIN i[349]
    DIRECTION INPUT ;
    USE SIGNAL ;
    PORT
      LAYER M4 ;
        RECT  17.088 38.688 17.28 38.712 ;
    END
  END i[349]
  PIN i[34]
    DIRECTION INPUT ;
    USE SIGNAL ;
    PORT
      LAYER M4 ;
        RECT  17.088 5.76 17.28 5.784 ;
    END
  END i[34]
  PIN i[350]
    DIRECTION INPUT ;
    USE SIGNAL ;
    PORT
      LAYER M4 ;
        RECT  17.088 38.784 17.28 38.808 ;
    END
  END i[350]
  PIN i[351]
    DIRECTION INPUT ;
    USE SIGNAL ;
    PORT
      LAYER M4 ;
        RECT  17.088 38.928 17.28 38.952 ;
    END
  END i[351]
  PIN i[352]
    DIRECTION INPUT ;
    USE SIGNAL ;
    PORT
      LAYER M4 ;
        RECT  17.088 39.024 17.28 39.048 ;
    END
  END i[352]
  PIN i[353]
    DIRECTION INPUT ;
    USE SIGNAL ;
    PORT
      LAYER M4 ;
        RECT  17.088 39.12 17.28 39.144 ;
    END
  END i[353]
  PIN i[354]
    DIRECTION INPUT ;
    USE SIGNAL ;
    PORT
      LAYER M4 ;
        RECT  17.088 39.216 17.28 39.24 ;
    END
  END i[354]
  PIN i[355]
    DIRECTION INPUT ;
    USE SIGNAL ;
    PORT
      LAYER M4 ;
        RECT  17.088 39.312 17.28 39.336 ;
    END
  END i[355]
  PIN i[356]
    DIRECTION INPUT ;
    USE SIGNAL ;
    PORT
      LAYER M4 ;
        RECT  17.088 39.408 17.28 39.432 ;
    END
  END i[356]
  PIN i[357]
    DIRECTION INPUT ;
    USE SIGNAL ;
    PORT
      LAYER M4 ;
        RECT  17.088 39.552 17.28 39.576 ;
    END
  END i[357]
  PIN i[358]
    DIRECTION INPUT ;
    USE SIGNAL ;
    PORT
      LAYER M4 ;
        RECT  17.088 39.648 17.28 39.672 ;
    END
  END i[358]
  PIN i[359]
    DIRECTION INPUT ;
    USE SIGNAL ;
    PORT
      LAYER M4 ;
        RECT  17.088 39.744 17.28 39.768 ;
    END
  END i[359]
  PIN i[35]
    DIRECTION INPUT ;
    USE SIGNAL ;
    PORT
      LAYER M4 ;
        RECT  17.088 5.904 17.28 5.928 ;
    END
  END i[35]
  PIN i[360]
    DIRECTION INPUT ;
    USE SIGNAL ;
    PORT
      LAYER M4 ;
        RECT  17.088 39.84 17.28 39.864 ;
    END
  END i[360]
  PIN i[361]
    DIRECTION INPUT ;
    USE SIGNAL ;
    PORT
      LAYER M4 ;
        RECT  17.088 39.936 17.28 39.96 ;
    END
  END i[361]
  PIN i[362]
    DIRECTION INPUT ;
    USE SIGNAL ;
    PORT
      LAYER M4 ;
        RECT  17.088 40.08 17.28 40.104 ;
    END
  END i[362]
  PIN i[363]
    DIRECTION INPUT ;
    USE SIGNAL ;
    PORT
      LAYER M4 ;
        RECT  17.088 40.176 17.28 40.2 ;
    END
  END i[363]
  PIN i[364]
    DIRECTION INPUT ;
    USE SIGNAL ;
    PORT
      LAYER M4 ;
        RECT  17.088 40.272 17.28 40.296 ;
    END
  END i[364]
  PIN i[365]
    DIRECTION INPUT ;
    USE SIGNAL ;
    PORT
      LAYER M4 ;
        RECT  17.088 40.368 17.28 40.392 ;
    END
  END i[365]
  PIN i[366]
    DIRECTION INPUT ;
    USE SIGNAL ;
    PORT
      LAYER M4 ;
        RECT  17.088 40.464 17.28 40.488 ;
    END
  END i[366]
  PIN i[367]
    DIRECTION INPUT ;
    USE SIGNAL ;
    PORT
      LAYER M4 ;
        RECT  17.088 40.56 17.28 40.584 ;
    END
  END i[367]
  PIN i[368]
    DIRECTION INPUT ;
    USE SIGNAL ;
    PORT
      LAYER M4 ;
        RECT  17.088 40.704 17.28 40.728 ;
    END
  END i[368]
  PIN i[369]
    DIRECTION INPUT ;
    USE SIGNAL ;
    PORT
      LAYER M4 ;
        RECT  17.088 40.8 17.28 40.824 ;
    END
  END i[369]
  PIN i[36]
    DIRECTION INPUT ;
    USE SIGNAL ;
    PORT
      LAYER M4 ;
        RECT  17.088 6 17.28 6.024 ;
    END
  END i[36]
  PIN i[370]
    DIRECTION INPUT ;
    USE SIGNAL ;
    PORT
      LAYER M4 ;
        RECT  17.088 40.896 17.28 40.92 ;
    END
  END i[370]
  PIN i[371]
    DIRECTION INPUT ;
    USE SIGNAL ;
    PORT
      LAYER M4 ;
        RECT  17.088 40.992 17.28 41.016 ;
    END
  END i[371]
  PIN i[372]
    DIRECTION INPUT ;
    USE SIGNAL ;
    PORT
      LAYER M4 ;
        RECT  17.088 41.088 17.28 41.112 ;
    END
  END i[372]
  PIN i[373]
    DIRECTION INPUT ;
    USE SIGNAL ;
    PORT
      LAYER M4 ;
        RECT  17.088 41.232 17.28 41.256 ;
    END
  END i[373]
  PIN i[374]
    DIRECTION INPUT ;
    USE SIGNAL ;
    PORT
      LAYER M4 ;
        RECT  17.088 41.328 17.28 41.352 ;
    END
  END i[374]
  PIN i[375]
    DIRECTION INPUT ;
    USE SIGNAL ;
    PORT
      LAYER M4 ;
        RECT  17.088 41.424 17.28 41.448 ;
    END
  END i[375]
  PIN i[376]
    DIRECTION INPUT ;
    USE SIGNAL ;
    PORT
      LAYER M4 ;
        RECT  17.088 41.52 17.28 41.544 ;
    END
  END i[376]
  PIN i[377]
    DIRECTION INPUT ;
    USE SIGNAL ;
    PORT
      LAYER M4 ;
        RECT  17.088 41.616 17.28 41.64 ;
    END
  END i[377]
  PIN i[378]
    DIRECTION INPUT ;
    USE SIGNAL ;
    PORT
      LAYER M4 ;
        RECT  17.088 41.712 17.28 41.736 ;
    END
  END i[378]
  PIN i[379]
    DIRECTION INPUT ;
    USE SIGNAL ;
    PORT
      LAYER M4 ;
        RECT  17.088 41.856 17.28 41.88 ;
    END
  END i[379]
  PIN i[37]
    DIRECTION INPUT ;
    USE SIGNAL ;
    PORT
      LAYER M4 ;
        RECT  17.088 6.096 17.28 6.12 ;
    END
  END i[37]
  PIN i[380]
    DIRECTION INPUT ;
    USE SIGNAL ;
    PORT
      LAYER M4 ;
        RECT  17.088 41.952 17.28 41.976 ;
    END
  END i[380]
  PIN i[381]
    DIRECTION INPUT ;
    USE SIGNAL ;
    PORT
      LAYER M4 ;
        RECT  17.088 42.048 17.28 42.072 ;
    END
  END i[381]
  PIN i[382]
    DIRECTION INPUT ;
    USE SIGNAL ;
    PORT
      LAYER M4 ;
        RECT  17.088 42.144 17.28 42.168 ;
    END
  END i[382]
  PIN i[383]
    DIRECTION INPUT ;
    USE SIGNAL ;
    PORT
      LAYER M4 ;
        RECT  17.088 42.24 17.28 42.264 ;
    END
  END i[383]
  PIN i[384]
    DIRECTION INPUT ;
    USE SIGNAL ;
    PORT
      LAYER M4 ;
        RECT  17.088 42.336 17.28 42.36 ;
    END
  END i[384]
  PIN i[385]
    DIRECTION INPUT ;
    USE SIGNAL ;
    PORT
      LAYER M4 ;
        RECT  17.088 42.48 17.28 42.504 ;
    END
  END i[385]
  PIN i[386]
    DIRECTION INPUT ;
    USE SIGNAL ;
    PORT
      LAYER M4 ;
        RECT  17.088 42.576 17.28 42.6 ;
    END
  END i[386]
  PIN i[387]
    DIRECTION INPUT ;
    USE SIGNAL ;
    PORT
      LAYER M4 ;
        RECT  17.088 42.672 17.28 42.696 ;
    END
  END i[387]
  PIN i[388]
    DIRECTION INPUT ;
    USE SIGNAL ;
    PORT
      LAYER M4 ;
        RECT  17.088 42.768 17.28 42.792 ;
    END
  END i[388]
  PIN i[389]
    DIRECTION INPUT ;
    USE SIGNAL ;
    PORT
      LAYER M4 ;
        RECT  17.088 42.864 17.28 42.888 ;
    END
  END i[389]
  PIN i[38]
    DIRECTION INPUT ;
    USE SIGNAL ;
    PORT
      LAYER M4 ;
        RECT  17.088 6.192 17.28 6.216 ;
    END
  END i[38]
  PIN i[390]
    DIRECTION INPUT ;
    USE SIGNAL ;
    PORT
      LAYER M4 ;
        RECT  17.088 43.008 17.28 43.032 ;
    END
  END i[390]
  PIN i[391]
    DIRECTION INPUT ;
    USE SIGNAL ;
    PORT
      LAYER M4 ;
        RECT  17.088 43.104 17.28 43.128 ;
    END
  END i[391]
  PIN i[392]
    DIRECTION INPUT ;
    USE SIGNAL ;
    PORT
      LAYER M4 ;
        RECT  17.088 43.2 17.28 43.224 ;
    END
  END i[392]
  PIN i[393]
    DIRECTION INPUT ;
    USE SIGNAL ;
    PORT
      LAYER M4 ;
        RECT  17.088 43.296 17.28 43.32 ;
    END
  END i[393]
  PIN i[394]
    DIRECTION INPUT ;
    USE SIGNAL ;
    PORT
      LAYER M4 ;
        RECT  17.088 43.392 17.28 43.416 ;
    END
  END i[394]
  PIN i[395]
    DIRECTION INPUT ;
    USE SIGNAL ;
    PORT
      LAYER M4 ;
        RECT  17.088 43.488 17.28 43.512 ;
    END
  END i[395]
  PIN i[396]
    DIRECTION INPUT ;
    USE SIGNAL ;
    PORT
      LAYER M4 ;
        RECT  17.088 43.632 17.28 43.656 ;
    END
  END i[396]
  PIN i[397]
    DIRECTION INPUT ;
    USE SIGNAL ;
    PORT
      LAYER M4 ;
        RECT  17.088 43.728 17.28 43.752 ;
    END
  END i[397]
  PIN i[398]
    DIRECTION INPUT ;
    USE SIGNAL ;
    PORT
      LAYER M4 ;
        RECT  17.088 43.824 17.28 43.848 ;
    END
  END i[398]
  PIN i[399]
    DIRECTION INPUT ;
    USE SIGNAL ;
    PORT
      LAYER M4 ;
        RECT  17.088 43.92 17.28 43.944 ;
    END
  END i[399]
  PIN i[39]
    DIRECTION INPUT ;
    USE SIGNAL ;
    PORT
      LAYER M4 ;
        RECT  17.088 6.288 17.28 6.312 ;
    END
  END i[39]
  PIN i[3]
    DIRECTION INPUT ;
    USE SIGNAL ;
    PORT
      LAYER M4 ;
        RECT  17.088 2.544 17.28 2.568 ;
    END
  END i[3]
  PIN i[400]
    DIRECTION INPUT ;
    USE SIGNAL ;
    PORT
      LAYER M4 ;
        RECT  17.088 44.016 17.28 44.04 ;
    END
  END i[400]
  PIN i[401]
    DIRECTION INPUT ;
    USE SIGNAL ;
    PORT
      LAYER M4 ;
        RECT  17.088 44.112 17.28 44.136 ;
    END
  END i[401]
  PIN i[402]
    DIRECTION INPUT ;
    USE SIGNAL ;
    PORT
      LAYER M4 ;
        RECT  17.088 44.256 17.28 44.28 ;
    END
  END i[402]
  PIN i[403]
    DIRECTION INPUT ;
    USE SIGNAL ;
    PORT
      LAYER M4 ;
        RECT  17.088 44.352 17.28 44.376 ;
    END
  END i[403]
  PIN i[404]
    DIRECTION INPUT ;
    USE SIGNAL ;
    PORT
      LAYER M4 ;
        RECT  17.088 44.448 17.28 44.472 ;
    END
  END i[404]
  PIN i[405]
    DIRECTION INPUT ;
    USE SIGNAL ;
    PORT
      LAYER M4 ;
        RECT  17.088 44.544 17.28 44.568 ;
    END
  END i[405]
  PIN i[406]
    DIRECTION INPUT ;
    USE SIGNAL ;
    PORT
      LAYER M4 ;
        RECT  17.088 44.64 17.28 44.664 ;
    END
  END i[406]
  PIN i[407]
    DIRECTION INPUT ;
    USE SIGNAL ;
    PORT
      LAYER M4 ;
        RECT  17.088 44.784 17.28 44.808 ;
    END
  END i[407]
  PIN i[408]
    DIRECTION INPUT ;
    USE SIGNAL ;
    PORT
      LAYER M4 ;
        RECT  17.088 44.88 17.28 44.904 ;
    END
  END i[408]
  PIN i[409]
    DIRECTION INPUT ;
    USE SIGNAL ;
    PORT
      LAYER M4 ;
        RECT  17.088 44.976 17.28 45 ;
    END
  END i[409]
  PIN i[40]
    DIRECTION INPUT ;
    USE SIGNAL ;
    PORT
      LAYER M4 ;
        RECT  17.088 6.384 17.28 6.408 ;
    END
  END i[40]
  PIN i[410]
    DIRECTION INPUT ;
    USE SIGNAL ;
    PORT
      LAYER M4 ;
        RECT  17.088 45.072 17.28 45.096 ;
    END
  END i[410]
  PIN i[411]
    DIRECTION INPUT ;
    USE SIGNAL ;
    PORT
      LAYER M4 ;
        RECT  17.088 45.168 17.28 45.192 ;
    END
  END i[411]
  PIN i[412]
    DIRECTION INPUT ;
    USE SIGNAL ;
    PORT
      LAYER M4 ;
        RECT  17.088 45.264 17.28 45.288 ;
    END
  END i[412]
  PIN i[413]
    DIRECTION INPUT ;
    USE SIGNAL ;
    PORT
      LAYER M4 ;
        RECT  17.088 45.408 17.28 45.432 ;
    END
  END i[413]
  PIN i[414]
    DIRECTION INPUT ;
    USE SIGNAL ;
    PORT
      LAYER M4 ;
        RECT  17.088 45.504 17.28 45.528 ;
    END
  END i[414]
  PIN i[415]
    DIRECTION INPUT ;
    USE SIGNAL ;
    PORT
      LAYER M4 ;
        RECT  17.088 45.6 17.28 45.624 ;
    END
  END i[415]
  PIN i[416]
    DIRECTION INPUT ;
    USE SIGNAL ;
    PORT
      LAYER M4 ;
        RECT  17.088 45.696 17.28 45.72 ;
    END
  END i[416]
  PIN i[417]
    DIRECTION INPUT ;
    USE SIGNAL ;
    PORT
      LAYER M4 ;
        RECT  17.088 45.792 17.28 45.816 ;
    END
  END i[417]
  PIN i[418]
    DIRECTION INPUT ;
    USE SIGNAL ;
    PORT
      LAYER M4 ;
        RECT  17.088 45.936 17.28 45.96 ;
    END
  END i[418]
  PIN i[419]
    DIRECTION INPUT ;
    USE SIGNAL ;
    PORT
      LAYER M4 ;
        RECT  17.088 46.032 17.28 46.056 ;
    END
  END i[419]
  PIN i[41]
    DIRECTION INPUT ;
    USE SIGNAL ;
    PORT
      LAYER M4 ;
        RECT  17.088 6.528 17.28 6.552 ;
    END
  END i[41]
  PIN i[420]
    DIRECTION INPUT ;
    USE SIGNAL ;
    PORT
      LAYER M4 ;
        RECT  17.088 46.128 17.28 46.152 ;
    END
  END i[420]
  PIN i[421]
    DIRECTION INPUT ;
    USE SIGNAL ;
    PORT
      LAYER M4 ;
        RECT  17.088 46.224 17.28 46.248 ;
    END
  END i[421]
  PIN i[422]
    DIRECTION INPUT ;
    USE SIGNAL ;
    PORT
      LAYER M4 ;
        RECT  17.088 46.32 17.28 46.344 ;
    END
  END i[422]
  PIN i[423]
    DIRECTION INPUT ;
    USE SIGNAL ;
    PORT
      LAYER M4 ;
        RECT  17.088 46.416 17.28 46.44 ;
    END
  END i[423]
  PIN i[424]
    DIRECTION INPUT ;
    USE SIGNAL ;
    PORT
      LAYER M4 ;
        RECT  17.088 46.56 17.28 46.584 ;
    END
  END i[424]
  PIN i[425]
    DIRECTION INPUT ;
    USE SIGNAL ;
    PORT
      LAYER M4 ;
        RECT  17.088 46.656 17.28 46.68 ;
    END
  END i[425]
  PIN i[426]
    DIRECTION INPUT ;
    USE SIGNAL ;
    PORT
      LAYER M4 ;
        RECT  17.088 46.752 17.28 46.776 ;
    END
  END i[426]
  PIN i[427]
    DIRECTION INPUT ;
    USE SIGNAL ;
    PORT
      LAYER M4 ;
        RECT  17.088 46.848 17.28 46.872 ;
    END
  END i[427]
  PIN i[428]
    DIRECTION INPUT ;
    USE SIGNAL ;
    PORT
      LAYER M4 ;
        RECT  17.088 46.944 17.28 46.968 ;
    END
  END i[428]
  PIN i[429]
    DIRECTION INPUT ;
    USE SIGNAL ;
    PORT
      LAYER M4 ;
        RECT  17.088 47.04 17.28 47.064 ;
    END
  END i[429]
  PIN i[42]
    DIRECTION INPUT ;
    USE SIGNAL ;
    PORT
      LAYER M4 ;
        RECT  17.088 6.624 17.28 6.648 ;
    END
  END i[42]
  PIN i[430]
    DIRECTION INPUT ;
    USE SIGNAL ;
    PORT
      LAYER M4 ;
        RECT  17.088 47.184 17.28 47.208 ;
    END
  END i[430]
  PIN i[431]
    DIRECTION INPUT ;
    USE SIGNAL ;
    PORT
      LAYER M4 ;
        RECT  17.088 47.28 17.28 47.304 ;
    END
  END i[431]
  PIN i[432]
    DIRECTION INPUT ;
    USE SIGNAL ;
    PORT
      LAYER M4 ;
        RECT  17.088 47.376 17.28 47.4 ;
    END
  END i[432]
  PIN i[433]
    DIRECTION INPUT ;
    USE SIGNAL ;
    PORT
      LAYER M4 ;
        RECT  17.088 47.472 17.28 47.496 ;
    END
  END i[433]
  PIN i[434]
    DIRECTION INPUT ;
    USE SIGNAL ;
    PORT
      LAYER M4 ;
        RECT  17.088 47.568 17.28 47.592 ;
    END
  END i[434]
  PIN i[435]
    DIRECTION INPUT ;
    USE SIGNAL ;
    PORT
      LAYER M4 ;
        RECT  17.088 47.712 17.28 47.736 ;
    END
  END i[435]
  PIN i[436]
    DIRECTION INPUT ;
    USE SIGNAL ;
    PORT
      LAYER M4 ;
        RECT  17.088 47.808 17.28 47.832 ;
    END
  END i[436]
  PIN i[437]
    DIRECTION INPUT ;
    USE SIGNAL ;
    PORT
      LAYER M4 ;
        RECT  17.088 47.904 17.28 47.928 ;
    END
  END i[437]
  PIN i[438]
    DIRECTION INPUT ;
    USE SIGNAL ;
    PORT
      LAYER M4 ;
        RECT  17.088 48 17.28 48.024 ;
    END
  END i[438]
  PIN i[439]
    DIRECTION INPUT ;
    USE SIGNAL ;
    PORT
      LAYER M4 ;
        RECT  17.088 48.096 17.28 48.12 ;
    END
  END i[439]
  PIN i[43]
    DIRECTION INPUT ;
    USE SIGNAL ;
    PORT
      LAYER M4 ;
        RECT  17.088 6.72 17.28 6.744 ;
    END
  END i[43]
  PIN i[440]
    DIRECTION INPUT ;
    USE SIGNAL ;
    PORT
      LAYER M4 ;
        RECT  17.088 48.192 17.28 48.216 ;
    END
  END i[440]
  PIN i[441]
    DIRECTION INPUT ;
    USE SIGNAL ;
    PORT
      LAYER M4 ;
        RECT  17.088 48.336 17.28 48.36 ;
    END
  END i[441]
  PIN i[442]
    DIRECTION INPUT ;
    USE SIGNAL ;
    PORT
      LAYER M4 ;
        RECT  17.088 48.432 17.28 48.456 ;
    END
  END i[442]
  PIN i[443]
    DIRECTION INPUT ;
    USE SIGNAL ;
    PORT
      LAYER M4 ;
        RECT  17.088 48.528 17.28 48.552 ;
    END
  END i[443]
  PIN i[444]
    DIRECTION INPUT ;
    USE SIGNAL ;
    PORT
      LAYER M4 ;
        RECT  17.088 48.624 17.28 48.648 ;
    END
  END i[444]
  PIN i[445]
    DIRECTION INPUT ;
    USE SIGNAL ;
    PORT
      LAYER M4 ;
        RECT  17.088 48.72 17.28 48.744 ;
    END
  END i[445]
  PIN i[446]
    DIRECTION INPUT ;
    USE SIGNAL ;
    PORT
      LAYER M4 ;
        RECT  17.088 48.816 17.28 48.84 ;
    END
  END i[446]
  PIN i[447]
    DIRECTION INPUT ;
    USE SIGNAL ;
    PORT
      LAYER M4 ;
        RECT  17.088 48.96 17.28 48.984 ;
    END
  END i[447]
  PIN i[448]
    DIRECTION INPUT ;
    USE SIGNAL ;
    PORT
      LAYER M4 ;
        RECT  17.088 49.056 17.28 49.08 ;
    END
  END i[448]
  PIN i[449]
    DIRECTION INPUT ;
    USE SIGNAL ;
    PORT
      LAYER M4 ;
        RECT  17.088 49.152 17.28 49.176 ;
    END
  END i[449]
  PIN i[44]
    DIRECTION INPUT ;
    USE SIGNAL ;
    PORT
      LAYER M4 ;
        RECT  17.088 6.816 17.28 6.84 ;
    END
  END i[44]
  PIN i[450]
    DIRECTION INPUT ;
    USE SIGNAL ;
    PORT
      LAYER M4 ;
        RECT  17.088 49.248 17.28 49.272 ;
    END
  END i[450]
  PIN i[451]
    DIRECTION INPUT ;
    USE SIGNAL ;
    PORT
      LAYER M4 ;
        RECT  17.088 49.344 17.28 49.368 ;
    END
  END i[451]
  PIN i[452]
    DIRECTION INPUT ;
    USE SIGNAL ;
    PORT
      LAYER M4 ;
        RECT  17.088 49.488 17.28 49.512 ;
    END
  END i[452]
  PIN i[453]
    DIRECTION INPUT ;
    USE SIGNAL ;
    PORT
      LAYER M4 ;
        RECT  17.088 49.584 17.28 49.608 ;
    END
  END i[453]
  PIN i[454]
    DIRECTION INPUT ;
    USE SIGNAL ;
    PORT
      LAYER M4 ;
        RECT  17.088 49.68 17.28 49.704 ;
    END
  END i[454]
  PIN i[455]
    DIRECTION INPUT ;
    USE SIGNAL ;
    PORT
      LAYER M4 ;
        RECT  17.088 49.776 17.28 49.8 ;
    END
  END i[455]
  PIN i[456]
    DIRECTION INPUT ;
    USE SIGNAL ;
    PORT
      LAYER M4 ;
        RECT  17.088 49.872 17.28 49.896 ;
    END
  END i[456]
  PIN i[457]
    DIRECTION INPUT ;
    USE SIGNAL ;
    PORT
      LAYER M4 ;
        RECT  17.088 49.968 17.28 49.992 ;
    END
  END i[457]
  PIN i[458]
    DIRECTION INPUT ;
    USE SIGNAL ;
    PORT
      LAYER M4 ;
        RECT  17.088 50.112 17.28 50.136 ;
    END
  END i[458]
  PIN i[459]
    DIRECTION INPUT ;
    USE SIGNAL ;
    PORT
      LAYER M4 ;
        RECT  17.088 50.208 17.28 50.232 ;
    END
  END i[459]
  PIN i[45]
    DIRECTION INPUT ;
    USE SIGNAL ;
    PORT
      LAYER M4 ;
        RECT  17.088 6.912 17.28 6.936 ;
    END
  END i[45]
  PIN i[460]
    DIRECTION INPUT ;
    USE SIGNAL ;
    PORT
      LAYER M4 ;
        RECT  17.088 50.304 17.28 50.328 ;
    END
  END i[460]
  PIN i[461]
    DIRECTION INPUT ;
    USE SIGNAL ;
    PORT
      LAYER M4 ;
        RECT  17.088 50.4 17.28 50.424 ;
    END
  END i[461]
  PIN i[462]
    DIRECTION INPUT ;
    USE SIGNAL ;
    PORT
      LAYER M4 ;
        RECT  17.088 50.496 17.28 50.52 ;
    END
  END i[462]
  PIN i[463]
    DIRECTION INPUT ;
    USE SIGNAL ;
    PORT
      LAYER M4 ;
        RECT  17.088 50.592 17.28 50.616 ;
    END
  END i[463]
  PIN i[464]
    DIRECTION INPUT ;
    USE SIGNAL ;
    PORT
      LAYER M4 ;
        RECT  17.088 50.736 17.28 50.76 ;
    END
  END i[464]
  PIN i[465]
    DIRECTION INPUT ;
    USE SIGNAL ;
    PORT
      LAYER M4 ;
        RECT  17.088 50.832 17.28 50.856 ;
    END
  END i[465]
  PIN i[466]
    DIRECTION INPUT ;
    USE SIGNAL ;
    PORT
      LAYER M4 ;
        RECT  17.088 50.928 17.28 50.952 ;
    END
  END i[466]
  PIN i[467]
    DIRECTION INPUT ;
    USE SIGNAL ;
    PORT
      LAYER M4 ;
        RECT  17.088 51.024 17.28 51.048 ;
    END
  END i[467]
  PIN i[468]
    DIRECTION INPUT ;
    USE SIGNAL ;
    PORT
      LAYER M4 ;
        RECT  17.088 51.12 17.28 51.144 ;
    END
  END i[468]
  PIN i[469]
    DIRECTION INPUT ;
    USE SIGNAL ;
    PORT
      LAYER M4 ;
        RECT  17.088 51.264 17.28 51.288 ;
    END
  END i[469]
  PIN i[46]
    DIRECTION INPUT ;
    USE SIGNAL ;
    PORT
      LAYER M4 ;
        RECT  17.088 7.056 17.28 7.08 ;
    END
  END i[46]
  PIN i[470]
    DIRECTION INPUT ;
    USE SIGNAL ;
    PORT
      LAYER M4 ;
        RECT  17.088 51.36 17.28 51.384 ;
    END
  END i[470]
  PIN i[471]
    DIRECTION INPUT ;
    USE SIGNAL ;
    PORT
      LAYER M4 ;
        RECT  17.088 51.456 17.28 51.48 ;
    END
  END i[471]
  PIN i[472]
    DIRECTION INPUT ;
    USE SIGNAL ;
    PORT
      LAYER M4 ;
        RECT  17.088 51.552 17.28 51.576 ;
    END
  END i[472]
  PIN i[473]
    DIRECTION INPUT ;
    USE SIGNAL ;
    PORT
      LAYER M4 ;
        RECT  17.088 51.648 17.28 51.672 ;
    END
  END i[473]
  PIN i[474]
    DIRECTION INPUT ;
    USE SIGNAL ;
    PORT
      LAYER M4 ;
        RECT  17.088 51.744 17.28 51.768 ;
    END
  END i[474]
  PIN i[475]
    DIRECTION INPUT ;
    USE SIGNAL ;
    PORT
      LAYER M4 ;
        RECT  17.088 51.888 17.28 51.912 ;
    END
  END i[475]
  PIN i[476]
    DIRECTION INPUT ;
    USE SIGNAL ;
    PORT
      LAYER M4 ;
        RECT  17.088 51.984 17.28 52.008 ;
    END
  END i[476]
  PIN i[477]
    DIRECTION INPUT ;
    USE SIGNAL ;
    PORT
      LAYER M4 ;
        RECT  17.088 52.08 17.28 52.104 ;
    END
  END i[477]
  PIN i[478]
    DIRECTION INPUT ;
    USE SIGNAL ;
    PORT
      LAYER M4 ;
        RECT  17.088 52.176 17.28 52.2 ;
    END
  END i[478]
  PIN i[479]
    DIRECTION INPUT ;
    USE SIGNAL ;
    PORT
      LAYER M4 ;
        RECT  17.088 52.272 17.28 52.296 ;
    END
  END i[479]
  PIN i[47]
    DIRECTION INPUT ;
    USE SIGNAL ;
    PORT
      LAYER M4 ;
        RECT  17.088 7.152 17.28 7.176 ;
    END
  END i[47]
  PIN i[480]
    DIRECTION INPUT ;
    USE SIGNAL ;
    PORT
      LAYER M4 ;
        RECT  17.088 52.416 17.28 52.44 ;
    END
  END i[480]
  PIN i[481]
    DIRECTION INPUT ;
    USE SIGNAL ;
    PORT
      LAYER M4 ;
        RECT  17.088 52.512 17.28 52.536 ;
    END
  END i[481]
  PIN i[482]
    DIRECTION INPUT ;
    USE SIGNAL ;
    PORT
      LAYER M4 ;
        RECT  17.088 52.608 17.28 52.632 ;
    END
  END i[482]
  PIN i[483]
    DIRECTION INPUT ;
    USE SIGNAL ;
    PORT
      LAYER M4 ;
        RECT  17.088 52.704 17.28 52.728 ;
    END
  END i[483]
  PIN i[484]
    DIRECTION INPUT ;
    USE SIGNAL ;
    PORT
      LAYER M4 ;
        RECT  17.088 52.8 17.28 52.824 ;
    END
  END i[484]
  PIN i[485]
    DIRECTION INPUT ;
    USE SIGNAL ;
    PORT
      LAYER M4 ;
        RECT  17.088 52.896 17.28 52.92 ;
    END
  END i[485]
  PIN i[486]
    DIRECTION INPUT ;
    USE SIGNAL ;
    PORT
      LAYER M4 ;
        RECT  17.088 53.04 17.28 53.064 ;
    END
  END i[486]
  PIN i[487]
    DIRECTION INPUT ;
    USE SIGNAL ;
    PORT
      LAYER M4 ;
        RECT  17.088 53.136 17.28 53.16 ;
    END
  END i[487]
  PIN i[488]
    DIRECTION INPUT ;
    USE SIGNAL ;
    PORT
      LAYER M4 ;
        RECT  17.088 53.232 17.28 53.256 ;
    END
  END i[488]
  PIN i[489]
    DIRECTION INPUT ;
    USE SIGNAL ;
    PORT
      LAYER M4 ;
        RECT  17.088 53.328 17.28 53.352 ;
    END
  END i[489]
  PIN i[48]
    DIRECTION INPUT ;
    USE SIGNAL ;
    PORT
      LAYER M4 ;
        RECT  17.088 7.248 17.28 7.272 ;
    END
  END i[48]
  PIN i[490]
    DIRECTION INPUT ;
    USE SIGNAL ;
    PORT
      LAYER M4 ;
        RECT  17.088 53.424 17.28 53.448 ;
    END
  END i[490]
  PIN i[491]
    DIRECTION INPUT ;
    USE SIGNAL ;
    PORT
      LAYER M4 ;
        RECT  17.088 53.52 17.28 53.544 ;
    END
  END i[491]
  PIN i[492]
    DIRECTION INPUT ;
    USE SIGNAL ;
    PORT
      LAYER M4 ;
        RECT  17.088 53.664 17.28 53.688 ;
    END
  END i[492]
  PIN i[493]
    DIRECTION INPUT ;
    USE SIGNAL ;
    PORT
      LAYER M4 ;
        RECT  17.088 53.76 17.28 53.784 ;
    END
  END i[493]
  PIN i[494]
    DIRECTION INPUT ;
    USE SIGNAL ;
    PORT
      LAYER M4 ;
        RECT  17.088 53.856 17.28 53.88 ;
    END
  END i[494]
  PIN i[495]
    DIRECTION INPUT ;
    USE SIGNAL ;
    PORT
      LAYER M4 ;
        RECT  17.088 53.952 17.28 53.976 ;
    END
  END i[495]
  PIN i[496]
    DIRECTION INPUT ;
    USE SIGNAL ;
    PORT
      LAYER M4 ;
        RECT  17.088 54.048 17.28 54.072 ;
    END
  END i[496]
  PIN i[497]
    DIRECTION INPUT ;
    USE SIGNAL ;
    PORT
      LAYER M4 ;
        RECT  17.088 54.192 17.28 54.216 ;
    END
  END i[497]
  PIN i[498]
    DIRECTION INPUT ;
    USE SIGNAL ;
    PORT
      LAYER M4 ;
        RECT  17.088 54.288 17.28 54.312 ;
    END
  END i[498]
  PIN i[499]
    DIRECTION INPUT ;
    USE SIGNAL ;
    PORT
      LAYER M4 ;
        RECT  17.088 54.384 17.28 54.408 ;
    END
  END i[499]
  PIN i[49]
    DIRECTION INPUT ;
    USE SIGNAL ;
    PORT
      LAYER M4 ;
        RECT  17.088 7.344 17.28 7.368 ;
    END
  END i[49]
  PIN i[4]
    DIRECTION INPUT ;
    USE SIGNAL ;
    PORT
      LAYER M4 ;
        RECT  17.088 2.64 17.28 2.664 ;
    END
  END i[4]
  PIN i[500]
    DIRECTION INPUT ;
    USE SIGNAL ;
    PORT
      LAYER M4 ;
        RECT  17.088 54.48 17.28 54.504 ;
    END
  END i[500]
  PIN i[501]
    DIRECTION INPUT ;
    USE SIGNAL ;
    PORT
      LAYER M4 ;
        RECT  17.088 54.576 17.28 54.6 ;
    END
  END i[501]
  PIN i[502]
    DIRECTION INPUT ;
    USE SIGNAL ;
    PORT
      LAYER M4 ;
        RECT  17.088 54.672 17.28 54.696 ;
    END
  END i[502]
  PIN i[503]
    DIRECTION INPUT ;
    USE SIGNAL ;
    PORT
      LAYER M4 ;
        RECT  17.088 54.816 17.28 54.84 ;
    END
  END i[503]
  PIN i[504]
    DIRECTION INPUT ;
    USE SIGNAL ;
    PORT
      LAYER M4 ;
        RECT  17.088 54.912 17.28 54.936 ;
    END
  END i[504]
  PIN i[505]
    DIRECTION INPUT ;
    USE SIGNAL ;
    PORT
      LAYER M4 ;
        RECT  17.088 55.008 17.28 55.032 ;
    END
  END i[505]
  PIN i[506]
    DIRECTION INPUT ;
    USE SIGNAL ;
    PORT
      LAYER M4 ;
        RECT  17.088 55.104 17.28 55.128 ;
    END
  END i[506]
  PIN i[507]
    DIRECTION INPUT ;
    USE SIGNAL ;
    PORT
      LAYER M4 ;
        RECT  17.088 55.2 17.28 55.224 ;
    END
  END i[507]
  PIN i[508]
    DIRECTION INPUT ;
    USE SIGNAL ;
    PORT
      LAYER M4 ;
        RECT  17.088 55.296 17.28 55.32 ;
    END
  END i[508]
  PIN i[509]
    DIRECTION INPUT ;
    USE SIGNAL ;
    PORT
      LAYER M4 ;
        RECT  17.088 55.44 17.28 55.464 ;
    END
  END i[509]
  PIN i[50]
    DIRECTION INPUT ;
    USE SIGNAL ;
    PORT
      LAYER M4 ;
        RECT  17.088 7.44 17.28 7.464 ;
    END
  END i[50]
  PIN i[510]
    DIRECTION INPUT ;
    USE SIGNAL ;
    PORT
      LAYER M4 ;
        RECT  17.088 55.536 17.28 55.56 ;
    END
  END i[510]
  PIN i[511]
    DIRECTION INPUT ;
    USE SIGNAL ;
    PORT
      LAYER M4 ;
        RECT  17.088 55.632 17.28 55.656 ;
    END
  END i[511]
  PIN i[512]
    DIRECTION INPUT ;
    USE SIGNAL ;
    PORT
      LAYER M4 ;
        RECT  17.088 55.728 17.28 55.752 ;
    END
  END i[512]
  PIN i[513]
    DIRECTION INPUT ;
    USE SIGNAL ;
    PORT
      LAYER M4 ;
        RECT  17.088 55.824 17.28 55.848 ;
    END
  END i[513]
  PIN i[514]
    DIRECTION INPUT ;
    USE SIGNAL ;
    PORT
      LAYER M4 ;
        RECT  17.088 55.968 17.28 55.992 ;
    END
  END i[514]
  PIN i[515]
    DIRECTION INPUT ;
    USE SIGNAL ;
    PORT
      LAYER M4 ;
        RECT  17.088 56.064 17.28 56.088 ;
    END
  END i[515]
  PIN i[516]
    DIRECTION INPUT ;
    USE SIGNAL ;
    PORT
      LAYER M4 ;
        RECT  17.088 56.16 17.28 56.184 ;
    END
  END i[516]
  PIN i[517]
    DIRECTION INPUT ;
    USE SIGNAL ;
    PORT
      LAYER M4 ;
        RECT  17.088 56.256 17.28 56.28 ;
    END
  END i[517]
  PIN i[518]
    DIRECTION INPUT ;
    USE SIGNAL ;
    PORT
      LAYER M4 ;
        RECT  17.088 56.352 17.28 56.376 ;
    END
  END i[518]
  PIN i[519]
    DIRECTION INPUT ;
    USE SIGNAL ;
    PORT
      LAYER M4 ;
        RECT  17.088 56.448 17.28 56.472 ;
    END
  END i[519]
  PIN i[51]
    DIRECTION INPUT ;
    USE SIGNAL ;
    PORT
      LAYER M4 ;
        RECT  17.088 7.536 17.28 7.56 ;
    END
  END i[51]
  PIN i[520]
    DIRECTION INPUT ;
    USE SIGNAL ;
    PORT
      LAYER M4 ;
        RECT  17.088 56.592 17.28 56.616 ;
    END
  END i[520]
  PIN i[521]
    DIRECTION INPUT ;
    USE SIGNAL ;
    PORT
      LAYER M4 ;
        RECT  17.088 56.688 17.28 56.712 ;
    END
  END i[521]
  PIN i[522]
    DIRECTION INPUT ;
    USE SIGNAL ;
    PORT
      LAYER M4 ;
        RECT  17.088 56.784 17.28 56.808 ;
    END
  END i[522]
  PIN i[523]
    DIRECTION INPUT ;
    USE SIGNAL ;
    PORT
      LAYER M4 ;
        RECT  17.088 56.88 17.28 56.904 ;
    END
  END i[523]
  PIN i[524]
    DIRECTION INPUT ;
    USE SIGNAL ;
    PORT
      LAYER M4 ;
        RECT  17.088 56.976 17.28 57 ;
    END
  END i[524]
  PIN i[525]
    DIRECTION INPUT ;
    USE SIGNAL ;
    PORT
      LAYER M4 ;
        RECT  17.088 57.072 17.28 57.096 ;
    END
  END i[525]
  PIN i[526]
    DIRECTION INPUT ;
    USE SIGNAL ;
    PORT
      LAYER M4 ;
        RECT  17.088 57.216 17.28 57.24 ;
    END
  END i[526]
  PIN i[527]
    DIRECTION INPUT ;
    USE SIGNAL ;
    PORT
      LAYER M4 ;
        RECT  17.088 57.312 17.28 57.336 ;
    END
  END i[527]
  PIN i[528]
    DIRECTION INPUT ;
    USE SIGNAL ;
    PORT
      LAYER M4 ;
        RECT  17.088 57.408 17.28 57.432 ;
    END
  END i[528]
  PIN i[529]
    DIRECTION INPUT ;
    USE SIGNAL ;
    PORT
      LAYER M4 ;
        RECT  17.088 57.504 17.28 57.528 ;
    END
  END i[529]
  PIN i[52]
    DIRECTION INPUT ;
    USE SIGNAL ;
    PORT
      LAYER M4 ;
        RECT  17.088 7.68 17.28 7.704 ;
    END
  END i[52]
  PIN i[530]
    DIRECTION INPUT ;
    USE SIGNAL ;
    PORT
      LAYER M4 ;
        RECT  17.088 57.6 17.28 57.624 ;
    END
  END i[530]
  PIN i[531]
    DIRECTION INPUT ;
    USE SIGNAL ;
    PORT
      LAYER M4 ;
        RECT  17.088 57.744 17.28 57.768 ;
    END
  END i[531]
  PIN i[532]
    DIRECTION INPUT ;
    USE SIGNAL ;
    PORT
      LAYER M4 ;
        RECT  17.088 57.84 17.28 57.864 ;
    END
  END i[532]
  PIN i[533]
    DIRECTION INPUT ;
    USE SIGNAL ;
    PORT
      LAYER M4 ;
        RECT  17.088 57.936 17.28 57.96 ;
    END
  END i[533]
  PIN i[534]
    DIRECTION INPUT ;
    USE SIGNAL ;
    PORT
      LAYER M4 ;
        RECT  17.088 58.032 17.28 58.056 ;
    END
  END i[534]
  PIN i[535]
    DIRECTION INPUT ;
    USE SIGNAL ;
    PORT
      LAYER M4 ;
        RECT  17.088 58.128 17.28 58.152 ;
    END
  END i[535]
  PIN i[536]
    DIRECTION INPUT ;
    USE SIGNAL ;
    PORT
      LAYER M4 ;
        RECT  17.088 58.224 17.28 58.248 ;
    END
  END i[536]
  PIN i[537]
    DIRECTION INPUT ;
    USE SIGNAL ;
    PORT
      LAYER M4 ;
        RECT  17.088 58.368 17.28 58.392 ;
    END
  END i[537]
  PIN i[538]
    DIRECTION INPUT ;
    USE SIGNAL ;
    PORT
      LAYER M4 ;
        RECT  17.088 58.464 17.28 58.488 ;
    END
  END i[538]
  PIN i[539]
    DIRECTION INPUT ;
    USE SIGNAL ;
    PORT
      LAYER M4 ;
        RECT  17.088 58.56 17.28 58.584 ;
    END
  END i[539]
  PIN i[53]
    DIRECTION INPUT ;
    USE SIGNAL ;
    PORT
      LAYER M4 ;
        RECT  17.088 7.776 17.28 7.8 ;
    END
  END i[53]
  PIN i[540]
    DIRECTION INPUT ;
    USE SIGNAL ;
    PORT
      LAYER M4 ;
        RECT  17.088 58.656 17.28 58.68 ;
    END
  END i[540]
  PIN i[541]
    DIRECTION INPUT ;
    USE SIGNAL ;
    PORT
      LAYER M4 ;
        RECT  17.088 58.752 17.28 58.776 ;
    END
  END i[541]
  PIN i[542]
    DIRECTION INPUT ;
    USE SIGNAL ;
    PORT
      LAYER M4 ;
        RECT  17.088 58.896 17.28 58.92 ;
    END
  END i[542]
  PIN i[543]
    DIRECTION INPUT ;
    USE SIGNAL ;
    PORT
      LAYER M4 ;
        RECT  17.088 58.992 17.28 59.016 ;
    END
  END i[543]
  PIN i[544]
    DIRECTION INPUT ;
    USE SIGNAL ;
    PORT
      LAYER M4 ;
        RECT  17.088 59.088 17.28 59.112 ;
    END
  END i[544]
  PIN i[545]
    DIRECTION INPUT ;
    USE SIGNAL ;
    PORT
      LAYER M4 ;
        RECT  17.088 59.184 17.28 59.208 ;
    END
  END i[545]
  PIN i[546]
    DIRECTION INPUT ;
    USE SIGNAL ;
    PORT
      LAYER M4 ;
        RECT  17.088 59.28 17.28 59.304 ;
    END
  END i[546]
  PIN i[547]
    DIRECTION INPUT ;
    USE SIGNAL ;
    PORT
      LAYER M4 ;
        RECT  17.088 59.376 17.28 59.4 ;
    END
  END i[547]
  PIN i[548]
    DIRECTION INPUT ;
    USE SIGNAL ;
    PORT
      LAYER M4 ;
        RECT  17.088 59.52 17.28 59.544 ;
    END
  END i[548]
  PIN i[549]
    DIRECTION INPUT ;
    USE SIGNAL ;
    PORT
      LAYER M4 ;
        RECT  17.088 59.616 17.28 59.64 ;
    END
  END i[549]
  PIN i[54]
    DIRECTION INPUT ;
    USE SIGNAL ;
    PORT
      LAYER M4 ;
        RECT  17.088 7.872 17.28 7.896 ;
    END
  END i[54]
  PIN i[550]
    DIRECTION INPUT ;
    USE SIGNAL ;
    PORT
      LAYER M4 ;
        RECT  17.088 59.712 17.28 59.736 ;
    END
  END i[550]
  PIN i[551]
    DIRECTION INPUT ;
    USE SIGNAL ;
    PORT
      LAYER M4 ;
        RECT  17.088 59.808 17.28 59.832 ;
    END
  END i[551]
  PIN i[552]
    DIRECTION INPUT ;
    USE SIGNAL ;
    PORT
      LAYER M4 ;
        RECT  17.088 59.904 17.28 59.928 ;
    END
  END i[552]
  PIN i[553]
    DIRECTION INPUT ;
    USE SIGNAL ;
    PORT
      LAYER M4 ;
        RECT  17.088 60 17.28 60.024 ;
    END
  END i[553]
  PIN i[554]
    DIRECTION INPUT ;
    USE SIGNAL ;
    PORT
      LAYER M4 ;
        RECT  17.088 60.144 17.28 60.168 ;
    END
  END i[554]
  PIN i[555]
    DIRECTION INPUT ;
    USE SIGNAL ;
    PORT
      LAYER M4 ;
        RECT  17.088 60.24 17.28 60.264 ;
    END
  END i[555]
  PIN i[556]
    DIRECTION INPUT ;
    USE SIGNAL ;
    PORT
      LAYER M4 ;
        RECT  17.088 60.336 17.28 60.36 ;
    END
  END i[556]
  PIN i[557]
    DIRECTION INPUT ;
    USE SIGNAL ;
    PORT
      LAYER M4 ;
        RECT  17.088 60.432 17.28 60.456 ;
    END
  END i[557]
  PIN i[558]
    DIRECTION INPUT ;
    USE SIGNAL ;
    PORT
      LAYER M4 ;
        RECT  17.088 60.528 17.28 60.552 ;
    END
  END i[558]
  PIN i[559]
    DIRECTION INPUT ;
    USE SIGNAL ;
    PORT
      LAYER M4 ;
        RECT  17.088 60.672 17.28 60.696 ;
    END
  END i[559]
  PIN i[55]
    DIRECTION INPUT ;
    USE SIGNAL ;
    PORT
      LAYER M4 ;
        RECT  17.088 7.968 17.28 7.992 ;
    END
  END i[55]
  PIN i[560]
    DIRECTION INPUT ;
    USE SIGNAL ;
    PORT
      LAYER M4 ;
        RECT  17.088 60.768 17.28 60.792 ;
    END
  END i[560]
  PIN i[561]
    DIRECTION INPUT ;
    USE SIGNAL ;
    PORT
      LAYER M4 ;
        RECT  17.088 60.864 17.28 60.888 ;
    END
  END i[561]
  PIN i[562]
    DIRECTION INPUT ;
    USE SIGNAL ;
    PORT
      LAYER M4 ;
        RECT  17.088 60.96 17.28 60.984 ;
    END
  END i[562]
  PIN i[563]
    DIRECTION INPUT ;
    USE SIGNAL ;
    PORT
      LAYER M4 ;
        RECT  17.088 61.056 17.28 61.08 ;
    END
  END i[563]
  PIN i[564]
    DIRECTION INPUT ;
    USE SIGNAL ;
    PORT
      LAYER M4 ;
        RECT  17.088 61.152 17.28 61.176 ;
    END
  END i[564]
  PIN i[565]
    DIRECTION INPUT ;
    USE SIGNAL ;
    PORT
      LAYER M4 ;
        RECT  17.088 61.296 17.28 61.32 ;
    END
  END i[565]
  PIN i[566]
    DIRECTION INPUT ;
    USE SIGNAL ;
    PORT
      LAYER M4 ;
        RECT  17.088 61.392 17.28 61.416 ;
    END
  END i[566]
  PIN i[567]
    DIRECTION INPUT ;
    USE SIGNAL ;
    PORT
      LAYER M4 ;
        RECT  17.088 61.488 17.28 61.512 ;
    END
  END i[567]
  PIN i[568]
    DIRECTION INPUT ;
    USE SIGNAL ;
    PORT
      LAYER M4 ;
        RECT  17.088 61.584 17.28 61.608 ;
    END
  END i[568]
  PIN i[569]
    DIRECTION INPUT ;
    USE SIGNAL ;
    PORT
      LAYER M4 ;
        RECT  17.088 61.68 17.28 61.704 ;
    END
  END i[569]
  PIN i[56]
    DIRECTION INPUT ;
    USE SIGNAL ;
    PORT
      LAYER M4 ;
        RECT  17.088 8.064 17.28 8.088 ;
    END
  END i[56]
  PIN i[570]
    DIRECTION INPUT ;
    USE SIGNAL ;
    PORT
      LAYER M4 ;
        RECT  17.088 61.776 17.28 61.8 ;
    END
  END i[570]
  PIN i[571]
    DIRECTION INPUT ;
    USE SIGNAL ;
    PORT
      LAYER M4 ;
        RECT  17.088 61.92 17.28 61.944 ;
    END
  END i[571]
  PIN i[572]
    DIRECTION INPUT ;
    USE SIGNAL ;
    PORT
      LAYER M4 ;
        RECT  17.088 62.016 17.28 62.04 ;
    END
  END i[572]
  PIN i[573]
    DIRECTION INPUT ;
    USE SIGNAL ;
    PORT
      LAYER M4 ;
        RECT  17.088 62.112 17.28 62.136 ;
    END
  END i[573]
  PIN i[574]
    DIRECTION INPUT ;
    USE SIGNAL ;
    PORT
      LAYER M4 ;
        RECT  17.088 62.208 17.28 62.232 ;
    END
  END i[574]
  PIN i[575]
    DIRECTION INPUT ;
    USE SIGNAL ;
    PORT
      LAYER M4 ;
        RECT  17.088 62.304 17.28 62.328 ;
    END
  END i[575]
  PIN i[576]
    DIRECTION INPUT ;
    USE SIGNAL ;
    PORT
      LAYER M4 ;
        RECT  17.088 62.448 17.28 62.472 ;
    END
  END i[576]
  PIN i[577]
    DIRECTION INPUT ;
    USE SIGNAL ;
    PORT
      LAYER M4 ;
        RECT  17.088 62.544 17.28 62.568 ;
    END
  END i[577]
  PIN i[578]
    DIRECTION INPUT ;
    USE SIGNAL ;
    PORT
      LAYER M4 ;
        RECT  17.088 62.64 17.28 62.664 ;
    END
  END i[578]
  PIN i[579]
    DIRECTION INPUT ;
    USE SIGNAL ;
    PORT
      LAYER M4 ;
        RECT  17.088 62.736 17.28 62.76 ;
    END
  END i[579]
  PIN i[57]
    DIRECTION INPUT ;
    USE SIGNAL ;
    PORT
      LAYER M4 ;
        RECT  17.088 8.16 17.28 8.184 ;
    END
  END i[57]
  PIN i[580]
    DIRECTION INPUT ;
    USE SIGNAL ;
    PORT
      LAYER M4 ;
        RECT  17.088 62.832 17.28 62.856 ;
    END
  END i[580]
  PIN i[581]
    DIRECTION INPUT ;
    USE SIGNAL ;
    PORT
      LAYER M4 ;
        RECT  17.088 62.928 17.28 62.952 ;
    END
  END i[581]
  PIN i[582]
    DIRECTION INPUT ;
    USE SIGNAL ;
    PORT
      LAYER M4 ;
        RECT  17.088 63.072 17.28 63.096 ;
    END
  END i[582]
  PIN i[583]
    DIRECTION INPUT ;
    USE SIGNAL ;
    PORT
      LAYER M4 ;
        RECT  17.088 63.168 17.28 63.192 ;
    END
  END i[583]
  PIN i[584]
    DIRECTION INPUT ;
    USE SIGNAL ;
    PORT
      LAYER M4 ;
        RECT  17.088 63.264 17.28 63.288 ;
    END
  END i[584]
  PIN i[585]
    DIRECTION INPUT ;
    USE SIGNAL ;
    PORT
      LAYER M4 ;
        RECT  17.088 63.36 17.28 63.384 ;
    END
  END i[585]
  PIN i[586]
    DIRECTION INPUT ;
    USE SIGNAL ;
    PORT
      LAYER M4 ;
        RECT  17.088 63.456 17.28 63.48 ;
    END
  END i[586]
  PIN i[587]
    DIRECTION INPUT ;
    USE SIGNAL ;
    PORT
      LAYER M4 ;
        RECT  17.088 63.552 17.28 63.576 ;
    END
  END i[587]
  PIN i[588]
    DIRECTION INPUT ;
    USE SIGNAL ;
    PORT
      LAYER M4 ;
        RECT  17.088 63.696 17.28 63.72 ;
    END
  END i[588]
  PIN i[589]
    DIRECTION INPUT ;
    USE SIGNAL ;
    PORT
      LAYER M4 ;
        RECT  17.088 63.792 17.28 63.816 ;
    END
  END i[589]
  PIN i[58]
    DIRECTION INPUT ;
    USE SIGNAL ;
    PORT
      LAYER M4 ;
        RECT  17.088 8.304 17.28 8.328 ;
    END
  END i[58]
  PIN i[590]
    DIRECTION INPUT ;
    USE SIGNAL ;
    PORT
      LAYER M4 ;
        RECT  17.088 63.888 17.28 63.912 ;
    END
  END i[590]
  PIN i[591]
    DIRECTION INPUT ;
    USE SIGNAL ;
    PORT
      LAYER M4 ;
        RECT  17.088 63.984 17.28 64.008 ;
    END
  END i[591]
  PIN i[592]
    DIRECTION INPUT ;
    USE SIGNAL ;
    PORT
      LAYER M4 ;
        RECT  17.088 64.08 17.28 64.104 ;
    END
  END i[592]
  PIN i[593]
    DIRECTION INPUT ;
    USE SIGNAL ;
    PORT
      LAYER M4 ;
        RECT  17.088 64.224 17.28 64.248 ;
    END
  END i[593]
  PIN i[594]
    DIRECTION INPUT ;
    USE SIGNAL ;
    PORT
      LAYER M4 ;
        RECT  17.088 64.32 17.28 64.344 ;
    END
  END i[594]
  PIN i[595]
    DIRECTION INPUT ;
    USE SIGNAL ;
    PORT
      LAYER M4 ;
        RECT  17.088 64.416 17.28 64.44 ;
    END
  END i[595]
  PIN i[596]
    DIRECTION INPUT ;
    USE SIGNAL ;
    PORT
      LAYER M4 ;
        RECT  17.088 64.512 17.28 64.536 ;
    END
  END i[596]
  PIN i[597]
    DIRECTION INPUT ;
    USE SIGNAL ;
    PORT
      LAYER M4 ;
        RECT  17.088 64.608 17.28 64.632 ;
    END
  END i[597]
  PIN i[598]
    DIRECTION INPUT ;
    USE SIGNAL ;
    PORT
      LAYER M4 ;
        RECT  17.088 64.704 17.28 64.728 ;
    END
  END i[598]
  PIN i[599]
    DIRECTION INPUT ;
    USE SIGNAL ;
    PORT
      LAYER M4 ;
        RECT  17.088 64.848 17.28 64.872 ;
    END
  END i[599]
  PIN i[59]
    DIRECTION INPUT ;
    USE SIGNAL ;
    PORT
      LAYER M4 ;
        RECT  17.088 8.4 17.28 8.424 ;
    END
  END i[59]
  PIN i[5]
    DIRECTION INPUT ;
    USE SIGNAL ;
    PORT
      LAYER M4 ;
        RECT  17.088 2.736 17.28 2.76 ;
    END
  END i[5]
  PIN i[600]
    DIRECTION INPUT ;
    USE SIGNAL ;
    PORT
      LAYER M4 ;
        RECT  17.088 64.944 17.28 64.968 ;
    END
  END i[600]
  PIN i[601]
    DIRECTION INPUT ;
    USE SIGNAL ;
    PORT
      LAYER M4 ;
        RECT  17.088 65.04 17.28 65.064 ;
    END
  END i[601]
  PIN i[602]
    DIRECTION INPUT ;
    USE SIGNAL ;
    PORT
      LAYER M4 ;
        RECT  17.088 65.136 17.28 65.16 ;
    END
  END i[602]
  PIN i[603]
    DIRECTION INPUT ;
    USE SIGNAL ;
    PORT
      LAYER M4 ;
        RECT  17.088 65.232 17.28 65.256 ;
    END
  END i[603]
  PIN i[604]
    DIRECTION INPUT ;
    USE SIGNAL ;
    PORT
      LAYER M4 ;
        RECT  17.088 65.328 17.28 65.352 ;
    END
  END i[604]
  PIN i[605]
    DIRECTION INPUT ;
    USE SIGNAL ;
    PORT
      LAYER M4 ;
        RECT  17.088 65.472 17.28 65.496 ;
    END
  END i[605]
  PIN i[606]
    DIRECTION INPUT ;
    USE SIGNAL ;
    PORT
      LAYER M4 ;
        RECT  17.088 65.568 17.28 65.592 ;
    END
  END i[606]
  PIN i[607]
    DIRECTION INPUT ;
    USE SIGNAL ;
    PORT
      LAYER M4 ;
        RECT  17.088 65.664 17.28 65.688 ;
    END
  END i[607]
  PIN i[608]
    DIRECTION INPUT ;
    USE SIGNAL ;
    PORT
      LAYER M4 ;
        RECT  17.088 65.76 17.28 65.784 ;
    END
  END i[608]
  PIN i[609]
    DIRECTION INPUT ;
    USE SIGNAL ;
    PORT
      LAYER M4 ;
        RECT  17.088 65.856 17.28 65.88 ;
    END
  END i[609]
  PIN i[60]
    DIRECTION INPUT ;
    USE SIGNAL ;
    PORT
      LAYER M4 ;
        RECT  17.088 8.496 17.28 8.52 ;
    END
  END i[60]
  PIN i[610]
    DIRECTION INPUT ;
    USE SIGNAL ;
    PORT
      LAYER M4 ;
        RECT  17.088 66 17.28 66.024 ;
    END
  END i[610]
  PIN i[611]
    DIRECTION INPUT ;
    USE SIGNAL ;
    PORT
      LAYER M4 ;
        RECT  17.088 66.096 17.28 66.12 ;
    END
  END i[611]
  PIN i[612]
    DIRECTION INPUT ;
    USE SIGNAL ;
    PORT
      LAYER M4 ;
        RECT  17.088 66.192 17.28 66.216 ;
    END
  END i[612]
  PIN i[613]
    DIRECTION INPUT ;
    USE SIGNAL ;
    PORT
      LAYER M4 ;
        RECT  17.088 66.288 17.28 66.312 ;
    END
  END i[613]
  PIN i[614]
    DIRECTION INPUT ;
    USE SIGNAL ;
    PORT
      LAYER M4 ;
        RECT  17.088 66.384 17.28 66.408 ;
    END
  END i[614]
  PIN i[615]
    DIRECTION INPUT ;
    USE SIGNAL ;
    PORT
      LAYER M4 ;
        RECT  17.088 66.48 17.28 66.504 ;
    END
  END i[615]
  PIN i[616]
    DIRECTION INPUT ;
    USE SIGNAL ;
    PORT
      LAYER M4 ;
        RECT  17.088 66.624 17.28 66.648 ;
    END
  END i[616]
  PIN i[617]
    DIRECTION INPUT ;
    USE SIGNAL ;
    PORT
      LAYER M4 ;
        RECT  17.088 66.72 17.28 66.744 ;
    END
  END i[617]
  PIN i[618]
    DIRECTION INPUT ;
    USE SIGNAL ;
    PORT
      LAYER M4 ;
        RECT  17.088 66.816 17.28 66.84 ;
    END
  END i[618]
  PIN i[619]
    DIRECTION INPUT ;
    USE SIGNAL ;
    PORT
      LAYER M4 ;
        RECT  17.088 66.912 17.28 66.936 ;
    END
  END i[619]
  PIN i[61]
    DIRECTION INPUT ;
    USE SIGNAL ;
    PORT
      LAYER M4 ;
        RECT  17.088 8.592 17.28 8.616 ;
    END
  END i[61]
  PIN i[620]
    DIRECTION INPUT ;
    USE SIGNAL ;
    PORT
      LAYER M4 ;
        RECT  17.088 67.008 17.28 67.032 ;
    END
  END i[620]
  PIN i[621]
    DIRECTION INPUT ;
    USE SIGNAL ;
    PORT
      LAYER M4 ;
        RECT  17.088 67.152 17.28 67.176 ;
    END
  END i[621]
  PIN i[622]
    DIRECTION INPUT ;
    USE SIGNAL ;
    PORT
      LAYER M4 ;
        RECT  17.088 67.248 17.28 67.272 ;
    END
  END i[622]
  PIN i[623]
    DIRECTION INPUT ;
    USE SIGNAL ;
    PORT
      LAYER M4 ;
        RECT  17.088 67.344 17.28 67.368 ;
    END
  END i[623]
  PIN i[624]
    DIRECTION INPUT ;
    USE SIGNAL ;
    PORT
      LAYER M4 ;
        RECT  17.088 67.44 17.28 67.464 ;
    END
  END i[624]
  PIN i[625]
    DIRECTION INPUT ;
    USE SIGNAL ;
    PORT
      LAYER M4 ;
        RECT  17.088 67.536 17.28 67.56 ;
    END
  END i[625]
  PIN i[626]
    DIRECTION INPUT ;
    USE SIGNAL ;
    PORT
      LAYER M4 ;
        RECT  17.088 67.632 17.28 67.656 ;
    END
  END i[626]
  PIN i[627]
    DIRECTION INPUT ;
    USE SIGNAL ;
    PORT
      LAYER M4 ;
        RECT  17.088 67.776 17.28 67.8 ;
    END
  END i[627]
  PIN i[628]
    DIRECTION INPUT ;
    USE SIGNAL ;
    PORT
      LAYER M4 ;
        RECT  17.088 67.872 17.28 67.896 ;
    END
  END i[628]
  PIN i[629]
    DIRECTION INPUT ;
    USE SIGNAL ;
    PORT
      LAYER M4 ;
        RECT  17.088 67.968 17.28 67.992 ;
    END
  END i[629]
  PIN i[62]
    DIRECTION INPUT ;
    USE SIGNAL ;
    PORT
      LAYER M4 ;
        RECT  17.088 8.688 17.28 8.712 ;
    END
  END i[62]
  PIN i[630]
    DIRECTION INPUT ;
    USE SIGNAL ;
    PORT
      LAYER M4 ;
        RECT  17.088 68.064 17.28 68.088 ;
    END
  END i[630]
  PIN i[631]
    DIRECTION INPUT ;
    USE SIGNAL ;
    PORT
      LAYER M4 ;
        RECT  17.088 68.16 17.28 68.184 ;
    END
  END i[631]
  PIN i[632]
    DIRECTION INPUT ;
    USE SIGNAL ;
    PORT
      LAYER M4 ;
        RECT  17.088 68.256 17.28 68.28 ;
    END
  END i[632]
  PIN i[633]
    DIRECTION INPUT ;
    USE SIGNAL ;
    PORT
      LAYER M4 ;
        RECT  17.088 68.4 17.28 68.424 ;
    END
  END i[633]
  PIN i[634]
    DIRECTION INPUT ;
    USE SIGNAL ;
    PORT
      LAYER M4 ;
        RECT  17.088 68.496 17.28 68.52 ;
    END
  END i[634]
  PIN i[635]
    DIRECTION INPUT ;
    USE SIGNAL ;
    PORT
      LAYER M4 ;
        RECT  17.088 68.592 17.28 68.616 ;
    END
  END i[635]
  PIN i[636]
    DIRECTION INPUT ;
    USE SIGNAL ;
    PORT
      LAYER M4 ;
        RECT  17.088 68.688 17.28 68.712 ;
    END
  END i[636]
  PIN i[637]
    DIRECTION INPUT ;
    USE SIGNAL ;
    PORT
      LAYER M4 ;
        RECT  17.088 68.784 17.28 68.808 ;
    END
  END i[637]
  PIN i[638]
    DIRECTION INPUT ;
    USE SIGNAL ;
    PORT
      LAYER M4 ;
        RECT  17.088 68.928 17.28 68.952 ;
    END
  END i[638]
  PIN i[639]
    DIRECTION INPUT ;
    USE SIGNAL ;
    PORT
      LAYER M4 ;
        RECT  17.088 69.024 17.28 69.048 ;
    END
  END i[639]
  PIN i[63]
    DIRECTION INPUT ;
    USE SIGNAL ;
    PORT
      LAYER M4 ;
        RECT  17.088 8.832 17.28 8.856 ;
    END
  END i[63]
  PIN i[640]
    DIRECTION INPUT ;
    USE SIGNAL ;
    PORT
      LAYER M4 ;
        RECT  17.088 69.12 17.28 69.144 ;
    END
  END i[640]
  PIN i[641]
    DIRECTION INPUT ;
    USE SIGNAL ;
    PORT
      LAYER M4 ;
        RECT  17.088 69.216 17.28 69.24 ;
    END
  END i[641]
  PIN i[642]
    DIRECTION INPUT ;
    USE SIGNAL ;
    PORT
      LAYER M4 ;
        RECT  17.088 69.312 17.28 69.336 ;
    END
  END i[642]
  PIN i[643]
    DIRECTION INPUT ;
    USE SIGNAL ;
    PORT
      LAYER M4 ;
        RECT  17.088 69.408 17.28 69.432 ;
    END
  END i[643]
  PIN i[644]
    DIRECTION INPUT ;
    USE SIGNAL ;
    PORT
      LAYER M4 ;
        RECT  17.088 69.552 17.28 69.576 ;
    END
  END i[644]
  PIN i[645]
    DIRECTION INPUT ;
    USE SIGNAL ;
    PORT
      LAYER M4 ;
        RECT  17.088 69.648 17.28 69.672 ;
    END
  END i[645]
  PIN i[646]
    DIRECTION INPUT ;
    USE SIGNAL ;
    PORT
      LAYER M4 ;
        RECT  17.088 69.744 17.28 69.768 ;
    END
  END i[646]
  PIN i[647]
    DIRECTION INPUT ;
    USE SIGNAL ;
    PORT
      LAYER M4 ;
        RECT  17.088 69.84 17.28 69.864 ;
    END
  END i[647]
  PIN i[648]
    DIRECTION INPUT ;
    USE SIGNAL ;
    PORT
      LAYER M4 ;
        RECT  17.088 69.936 17.28 69.96 ;
    END
  END i[648]
  PIN i[649]
    DIRECTION INPUT ;
    USE SIGNAL ;
    PORT
      LAYER M4 ;
        RECT  17.088 70.032 17.28 70.056 ;
    END
  END i[649]
  PIN i[64]
    DIRECTION INPUT ;
    USE SIGNAL ;
    PORT
      LAYER M4 ;
        RECT  17.088 8.928 17.28 8.952 ;
    END
  END i[64]
  PIN i[650]
    DIRECTION INPUT ;
    USE SIGNAL ;
    PORT
      LAYER M4 ;
        RECT  17.088 70.176 17.28 70.2 ;
    END
  END i[650]
  PIN i[651]
    DIRECTION INPUT ;
    USE SIGNAL ;
    PORT
      LAYER M4 ;
        RECT  17.088 70.272 17.28 70.296 ;
    END
  END i[651]
  PIN i[652]
    DIRECTION INPUT ;
    USE SIGNAL ;
    PORT
      LAYER M4 ;
        RECT  17.088 70.368 17.28 70.392 ;
    END
  END i[652]
  PIN i[653]
    DIRECTION INPUT ;
    USE SIGNAL ;
    PORT
      LAYER M4 ;
        RECT  17.088 70.464 17.28 70.488 ;
    END
  END i[653]
  PIN i[654]
    DIRECTION INPUT ;
    USE SIGNAL ;
    PORT
      LAYER M4 ;
        RECT  17.088 70.56 17.28 70.584 ;
    END
  END i[654]
  PIN i[655]
    DIRECTION INPUT ;
    USE SIGNAL ;
    PORT
      LAYER M4 ;
        RECT  17.088 70.704 17.28 70.728 ;
    END
  END i[655]
  PIN i[656]
    DIRECTION INPUT ;
    USE SIGNAL ;
    PORT
      LAYER M4 ;
        RECT  17.088 70.8 17.28 70.824 ;
    END
  END i[656]
  PIN i[657]
    DIRECTION INPUT ;
    USE SIGNAL ;
    PORT
      LAYER M4 ;
        RECT  17.088 70.896 17.28 70.92 ;
    END
  END i[657]
  PIN i[658]
    DIRECTION INPUT ;
    USE SIGNAL ;
    PORT
      LAYER M4 ;
        RECT  17.088 70.992 17.28 71.016 ;
    END
  END i[658]
  PIN i[659]
    DIRECTION INPUT ;
    USE SIGNAL ;
    PORT
      LAYER M4 ;
        RECT  17.088 71.088 17.28 71.112 ;
    END
  END i[659]
  PIN i[65]
    DIRECTION INPUT ;
    USE SIGNAL ;
    PORT
      LAYER M4 ;
        RECT  17.088 9.024 17.28 9.048 ;
    END
  END i[65]
  PIN i[660]
    DIRECTION INPUT ;
    USE SIGNAL ;
    PORT
      LAYER M4 ;
        RECT  17.088 71.184 17.28 71.208 ;
    END
  END i[660]
  PIN i[661]
    DIRECTION INPUT ;
    USE SIGNAL ;
    PORT
      LAYER M4 ;
        RECT  17.088 71.328 17.28 71.352 ;
    END
  END i[661]
  PIN i[662]
    DIRECTION INPUT ;
    USE SIGNAL ;
    PORT
      LAYER M4 ;
        RECT  17.088 71.424 17.28 71.448 ;
    END
  END i[662]
  PIN i[663]
    DIRECTION INPUT ;
    USE SIGNAL ;
    PORT
      LAYER M4 ;
        RECT  17.088 71.52 17.28 71.544 ;
    END
  END i[663]
  PIN i[664]
    DIRECTION INPUT ;
    USE SIGNAL ;
    PORT
      LAYER M4 ;
        RECT  17.088 71.616 17.28 71.64 ;
    END
  END i[664]
  PIN i[665]
    DIRECTION INPUT ;
    USE SIGNAL ;
    PORT
      LAYER M4 ;
        RECT  17.088 71.712 17.28 71.736 ;
    END
  END i[665]
  PIN i[666]
    DIRECTION INPUT ;
    USE SIGNAL ;
    PORT
      LAYER M4 ;
        RECT  17.088 71.856 17.28 71.88 ;
    END
  END i[666]
  PIN i[667]
    DIRECTION INPUT ;
    USE SIGNAL ;
    PORT
      LAYER M4 ;
        RECT  17.088 71.952 17.28 71.976 ;
    END
  END i[667]
  PIN i[668]
    DIRECTION INPUT ;
    USE SIGNAL ;
    PORT
      LAYER M4 ;
        RECT  17.088 72.048 17.28 72.072 ;
    END
  END i[668]
  PIN i[669]
    DIRECTION INPUT ;
    USE SIGNAL ;
    PORT
      LAYER M4 ;
        RECT  17.088 72.144 17.28 72.168 ;
    END
  END i[669]
  PIN i[66]
    DIRECTION INPUT ;
    USE SIGNAL ;
    PORT
      LAYER M4 ;
        RECT  17.088 9.12 17.28 9.144 ;
    END
  END i[66]
  PIN i[670]
    DIRECTION INPUT ;
    USE SIGNAL ;
    PORT
      LAYER M4 ;
        RECT  17.088 72.24 17.28 72.264 ;
    END
  END i[670]
  PIN i[671]
    DIRECTION INPUT ;
    USE SIGNAL ;
    PORT
      LAYER M4 ;
        RECT  17.088 72.336 17.28 72.36 ;
    END
  END i[671]
  PIN i[672]
    DIRECTION INPUT ;
    USE SIGNAL ;
    PORT
      LAYER M4 ;
        RECT  17.088 72.48 17.28 72.504 ;
    END
  END i[672]
  PIN i[673]
    DIRECTION INPUT ;
    USE SIGNAL ;
    PORT
      LAYER M4 ;
        RECT  17.088 72.576 17.28 72.6 ;
    END
  END i[673]
  PIN i[674]
    DIRECTION INPUT ;
    USE SIGNAL ;
    PORT
      LAYER M4 ;
        RECT  17.088 72.672 17.28 72.696 ;
    END
  END i[674]
  PIN i[675]
    DIRECTION INPUT ;
    USE SIGNAL ;
    PORT
      LAYER M4 ;
        RECT  17.088 72.768 17.28 72.792 ;
    END
  END i[675]
  PIN i[676]
    DIRECTION INPUT ;
    USE SIGNAL ;
    PORT
      LAYER M4 ;
        RECT  17.088 72.864 17.28 72.888 ;
    END
  END i[676]
  PIN i[677]
    DIRECTION INPUT ;
    USE SIGNAL ;
    PORT
      LAYER M4 ;
        RECT  17.088 72.96 17.28 72.984 ;
    END
  END i[677]
  PIN i[678]
    DIRECTION INPUT ;
    USE SIGNAL ;
    PORT
      LAYER M4 ;
        RECT  17.088 73.104 17.28 73.128 ;
    END
  END i[678]
  PIN i[679]
    DIRECTION INPUT ;
    USE SIGNAL ;
    PORT
      LAYER M4 ;
        RECT  17.088 73.2 17.28 73.224 ;
    END
  END i[679]
  PIN i[67]
    DIRECTION INPUT ;
    USE SIGNAL ;
    PORT
      LAYER M4 ;
        RECT  17.088 9.216 17.28 9.24 ;
    END
  END i[67]
  PIN i[680]
    DIRECTION INPUT ;
    USE SIGNAL ;
    PORT
      LAYER M4 ;
        RECT  17.088 73.296 17.28 73.32 ;
    END
  END i[680]
  PIN i[681]
    DIRECTION INPUT ;
    USE SIGNAL ;
    PORT
      LAYER M4 ;
        RECT  17.088 73.392 17.28 73.416 ;
    END
  END i[681]
  PIN i[68]
    DIRECTION INPUT ;
    USE SIGNAL ;
    PORT
      LAYER M4 ;
        RECT  17.088 9.312 17.28 9.336 ;
    END
  END i[68]
  PIN i[69]
    DIRECTION INPUT ;
    USE SIGNAL ;
    PORT
      LAYER M4 ;
        RECT  17.088 9.456 17.28 9.48 ;
    END
  END i[69]
  PIN i[6]
    DIRECTION INPUT ;
    USE SIGNAL ;
    PORT
      LAYER M4 ;
        RECT  17.088 2.832 17.28 2.856 ;
    END
  END i[6]
  PIN i[70]
    DIRECTION INPUT ;
    USE SIGNAL ;
    PORT
      LAYER M4 ;
        RECT  17.088 9.552 17.28 9.576 ;
    END
  END i[70]
  PIN i[71]
    DIRECTION INPUT ;
    USE SIGNAL ;
    PORT
      LAYER M4 ;
        RECT  17.088 9.648 17.28 9.672 ;
    END
  END i[71]
  PIN i[72]
    DIRECTION INPUT ;
    USE SIGNAL ;
    PORT
      LAYER M4 ;
        RECT  17.088 9.744 17.28 9.768 ;
    END
  END i[72]
  PIN i[73]
    DIRECTION INPUT ;
    USE SIGNAL ;
    PORT
      LAYER M4 ;
        RECT  17.088 9.84 17.28 9.864 ;
    END
  END i[73]
  PIN i[74]
    DIRECTION INPUT ;
    USE SIGNAL ;
    PORT
      LAYER M4 ;
        RECT  17.088 9.936 17.28 9.96 ;
    END
  END i[74]
  PIN i[75]
    DIRECTION INPUT ;
    USE SIGNAL ;
    PORT
      LAYER M4 ;
        RECT  17.088 10.08 17.28 10.104 ;
    END
  END i[75]
  PIN i[76]
    DIRECTION INPUT ;
    USE SIGNAL ;
    PORT
      LAYER M4 ;
        RECT  17.088 10.176 17.28 10.2 ;
    END
  END i[76]
  PIN i[77]
    DIRECTION INPUT ;
    USE SIGNAL ;
    PORT
      LAYER M4 ;
        RECT  17.088 10.272 17.28 10.296 ;
    END
  END i[77]
  PIN i[78]
    DIRECTION INPUT ;
    USE SIGNAL ;
    PORT
      LAYER M4 ;
        RECT  17.088 10.368 17.28 10.392 ;
    END
  END i[78]
  PIN i[79]
    DIRECTION INPUT ;
    USE SIGNAL ;
    PORT
      LAYER M4 ;
        RECT  17.088 10.464 17.28 10.488 ;
    END
  END i[79]
  PIN i[7]
    DIRECTION INPUT ;
    USE SIGNAL ;
    PORT
      LAYER M4 ;
        RECT  17.088 2.976 17.28 3 ;
    END
  END i[7]
  PIN i[80]
    DIRECTION INPUT ;
    USE SIGNAL ;
    PORT
      LAYER M4 ;
        RECT  17.088 10.608 17.28 10.632 ;
    END
  END i[80]
  PIN i[81]
    DIRECTION INPUT ;
    USE SIGNAL ;
    PORT
      LAYER M4 ;
        RECT  17.088 10.704 17.28 10.728 ;
    END
  END i[81]
  PIN i[82]
    DIRECTION INPUT ;
    USE SIGNAL ;
    PORT
      LAYER M4 ;
        RECT  17.088 10.8 17.28 10.824 ;
    END
  END i[82]
  PIN i[83]
    DIRECTION INPUT ;
    USE SIGNAL ;
    PORT
      LAYER M4 ;
        RECT  17.088 10.896 17.28 10.92 ;
    END
  END i[83]
  PIN i[84]
    DIRECTION INPUT ;
    USE SIGNAL ;
    PORT
      LAYER M4 ;
        RECT  17.088 10.992 17.28 11.016 ;
    END
  END i[84]
  PIN i[85]
    DIRECTION INPUT ;
    USE SIGNAL ;
    PORT
      LAYER M4 ;
        RECT  17.088 11.088 17.28 11.112 ;
    END
  END i[85]
  PIN i[86]
    DIRECTION INPUT ;
    USE SIGNAL ;
    PORT
      LAYER M4 ;
        RECT  17.088 11.232 17.28 11.256 ;
    END
  END i[86]
  PIN i[87]
    DIRECTION INPUT ;
    USE SIGNAL ;
    PORT
      LAYER M4 ;
        RECT  17.088 11.328 17.28 11.352 ;
    END
  END i[87]
  PIN i[88]
    DIRECTION INPUT ;
    USE SIGNAL ;
    PORT
      LAYER M4 ;
        RECT  17.088 11.424 17.28 11.448 ;
    END
  END i[88]
  PIN i[89]
    DIRECTION INPUT ;
    USE SIGNAL ;
    PORT
      LAYER M4 ;
        RECT  17.088 11.52 17.28 11.544 ;
    END
  END i[89]
  PIN i[8]
    DIRECTION INPUT ;
    USE SIGNAL ;
    PORT
      LAYER M4 ;
        RECT  17.088 3.072 17.28 3.096 ;
    END
  END i[8]
  PIN i[90]
    DIRECTION INPUT ;
    USE SIGNAL ;
    PORT
      LAYER M4 ;
        RECT  17.088 11.616 17.28 11.64 ;
    END
  END i[90]
  PIN i[91]
    DIRECTION INPUT ;
    USE SIGNAL ;
    PORT
      LAYER M4 ;
        RECT  17.088 11.712 17.28 11.736 ;
    END
  END i[91]
  PIN i[92]
    DIRECTION INPUT ;
    USE SIGNAL ;
    PORT
      LAYER M4 ;
        RECT  17.088 11.856 17.28 11.88 ;
    END
  END i[92]
  PIN i[93]
    DIRECTION INPUT ;
    USE SIGNAL ;
    PORT
      LAYER M4 ;
        RECT  17.088 11.952 17.28 11.976 ;
    END
  END i[93]
  PIN i[94]
    DIRECTION INPUT ;
    USE SIGNAL ;
    PORT
      LAYER M4 ;
        RECT  17.088 12.048 17.28 12.072 ;
    END
  END i[94]
  PIN i[95]
    DIRECTION INPUT ;
    USE SIGNAL ;
    PORT
      LAYER M4 ;
        RECT  17.088 12.144 17.28 12.168 ;
    END
  END i[95]
  PIN i[96]
    DIRECTION INPUT ;
    USE SIGNAL ;
    PORT
      LAYER M4 ;
        RECT  17.088 12.24 17.28 12.264 ;
    END
  END i[96]
  PIN i[97]
    DIRECTION INPUT ;
    USE SIGNAL ;
    PORT
      LAYER M4 ;
        RECT  17.088 12.384 17.28 12.408 ;
    END
  END i[97]
  PIN i[98]
    DIRECTION INPUT ;
    USE SIGNAL ;
    PORT
      LAYER M4 ;
        RECT  17.088 12.48 17.28 12.504 ;
    END
  END i[98]
  PIN i[99]
    DIRECTION INPUT ;
    USE SIGNAL ;
    PORT
      LAYER M4 ;
        RECT  17.088 12.576 17.28 12.6 ;
    END
  END i[99]
  PIN i[9]
    DIRECTION INPUT ;
    USE SIGNAL ;
    PORT
      LAYER M4 ;
        RECT  17.088 3.168 17.28 3.192 ;
    END
  END i[9]
  PIN o[0]
    DIRECTION OUTPUT ;
    USE SIGNAL ;
    PORT
      LAYER M4 ;
        RECT  0 2.208 0.192 2.232 ;
    END
  END o[0]
  PIN o[100]
    DIRECTION OUTPUT ;
    USE SIGNAL ;
    PORT
      LAYER M4 ;
        RECT  0 12.672 0.192 12.696 ;
    END
  END o[100]
  PIN o[101]
    DIRECTION OUTPUT ;
    USE SIGNAL ;
    PORT
      LAYER M4 ;
        RECT  0 12.768 0.192 12.792 ;
    END
  END o[101]
  PIN o[102]
    DIRECTION OUTPUT ;
    USE SIGNAL ;
    PORT
      LAYER M4 ;
        RECT  0 12.864 0.192 12.888 ;
    END
  END o[102]
  PIN o[103]
    DIRECTION OUTPUT ;
    USE SIGNAL ;
    PORT
      LAYER M4 ;
        RECT  0 12.96 0.192 12.984 ;
    END
  END o[103]
  PIN o[104]
    DIRECTION OUTPUT ;
    USE SIGNAL ;
    PORT
      LAYER M4 ;
        RECT  0 13.056 0.192 13.08 ;
    END
  END o[104]
  PIN o[105]
    DIRECTION OUTPUT ;
    USE SIGNAL ;
    PORT
      LAYER M4 ;
        RECT  0 13.2 0.192 13.224 ;
    END
  END o[105]
  PIN o[106]
    DIRECTION OUTPUT ;
    USE SIGNAL ;
    PORT
      LAYER M4 ;
        RECT  0 13.296 0.192 13.32 ;
    END
  END o[106]
  PIN o[107]
    DIRECTION OUTPUT ;
    USE SIGNAL ;
    PORT
      LAYER M4 ;
        RECT  0 13.392 0.192 13.416 ;
    END
  END o[107]
  PIN o[108]
    DIRECTION OUTPUT ;
    USE SIGNAL ;
    PORT
      LAYER M4 ;
        RECT  0 13.488 0.192 13.512 ;
    END
  END o[108]
  PIN o[109]
    DIRECTION OUTPUT ;
    USE SIGNAL ;
    PORT
      LAYER M4 ;
        RECT  0 13.584 0.192 13.608 ;
    END
  END o[109]
  PIN o[10]
    DIRECTION OUTPUT ;
    USE SIGNAL ;
    PORT
      LAYER M4 ;
        RECT  0 3.264 0.192 3.288 ;
    END
  END o[10]
  PIN o[110]
    DIRECTION OUTPUT ;
    USE SIGNAL ;
    PORT
      LAYER M4 ;
        RECT  0 13.728 0.192 13.752 ;
    END
  END o[110]
  PIN o[111]
    DIRECTION OUTPUT ;
    USE SIGNAL ;
    PORT
      LAYER M4 ;
        RECT  0 13.824 0.192 13.848 ;
    END
  END o[111]
  PIN o[112]
    DIRECTION OUTPUT ;
    USE SIGNAL ;
    PORT
      LAYER M4 ;
        RECT  0 13.92 0.192 13.944 ;
    END
  END o[112]
  PIN o[113]
    DIRECTION OUTPUT ;
    USE SIGNAL ;
    PORT
      LAYER M4 ;
        RECT  0 14.016 0.192 14.04 ;
    END
  END o[113]
  PIN o[114]
    DIRECTION OUTPUT ;
    USE SIGNAL ;
    PORT
      LAYER M4 ;
        RECT  0 14.112 0.192 14.136 ;
    END
  END o[114]
  PIN o[115]
    DIRECTION OUTPUT ;
    USE SIGNAL ;
    PORT
      LAYER M4 ;
        RECT  0 14.208 0.192 14.232 ;
    END
  END o[115]
  PIN o[116]
    DIRECTION OUTPUT ;
    USE SIGNAL ;
    PORT
      LAYER M4 ;
        RECT  0 14.352 0.192 14.376 ;
    END
  END o[116]
  PIN o[117]
    DIRECTION OUTPUT ;
    USE SIGNAL ;
    PORT
      LAYER M4 ;
        RECT  0 14.448 0.192 14.472 ;
    END
  END o[117]
  PIN o[118]
    DIRECTION OUTPUT ;
    USE SIGNAL ;
    PORT
      LAYER M4 ;
        RECT  0 14.544 0.192 14.568 ;
    END
  END o[118]
  PIN o[119]
    DIRECTION OUTPUT ;
    USE SIGNAL ;
    PORT
      LAYER M4 ;
        RECT  0 14.64 0.192 14.664 ;
    END
  END o[119]
  PIN o[11]
    DIRECTION OUTPUT ;
    USE SIGNAL ;
    PORT
      LAYER M4 ;
        RECT  0 3.36 0.192 3.384 ;
    END
  END o[11]
  PIN o[120]
    DIRECTION OUTPUT ;
    USE SIGNAL ;
    PORT
      LAYER M4 ;
        RECT  0 14.736 0.192 14.76 ;
    END
  END o[120]
  PIN o[121]
    DIRECTION OUTPUT ;
    USE SIGNAL ;
    PORT
      LAYER M4 ;
        RECT  0 14.832 0.192 14.856 ;
    END
  END o[121]
  PIN o[122]
    DIRECTION OUTPUT ;
    USE SIGNAL ;
    PORT
      LAYER M4 ;
        RECT  0 14.976 0.192 15 ;
    END
  END o[122]
  PIN o[123]
    DIRECTION OUTPUT ;
    USE SIGNAL ;
    PORT
      LAYER M4 ;
        RECT  0 15.072 0.192 15.096 ;
    END
  END o[123]
  PIN o[124]
    DIRECTION OUTPUT ;
    USE SIGNAL ;
    PORT
      LAYER M4 ;
        RECT  0 15.168 0.192 15.192 ;
    END
  END o[124]
  PIN o[125]
    DIRECTION OUTPUT ;
    USE SIGNAL ;
    PORT
      LAYER M4 ;
        RECT  0 15.264 0.192 15.288 ;
    END
  END o[125]
  PIN o[126]
    DIRECTION OUTPUT ;
    USE SIGNAL ;
    PORT
      LAYER M4 ;
        RECT  0 15.36 0.192 15.384 ;
    END
  END o[126]
  PIN o[127]
    DIRECTION OUTPUT ;
    USE SIGNAL ;
    PORT
      LAYER M4 ;
        RECT  0 15.456 0.192 15.48 ;
    END
  END o[127]
  PIN o[128]
    DIRECTION OUTPUT ;
    USE SIGNAL ;
    PORT
      LAYER M4 ;
        RECT  0 15.6 0.192 15.624 ;
    END
  END o[128]
  PIN o[129]
    DIRECTION OUTPUT ;
    USE SIGNAL ;
    PORT
      LAYER M4 ;
        RECT  0 15.696 0.192 15.72 ;
    END
  END o[129]
  PIN o[12]
    DIRECTION OUTPUT ;
    USE SIGNAL ;
    PORT
      LAYER M4 ;
        RECT  0 3.456 0.192 3.48 ;
    END
  END o[12]
  PIN o[130]
    DIRECTION OUTPUT ;
    USE SIGNAL ;
    PORT
      LAYER M4 ;
        RECT  0 15.792 0.192 15.816 ;
    END
  END o[130]
  PIN o[131]
    DIRECTION OUTPUT ;
    USE SIGNAL ;
    PORT
      LAYER M4 ;
        RECT  0 15.888 0.192 15.912 ;
    END
  END o[131]
  PIN o[132]
    DIRECTION OUTPUT ;
    USE SIGNAL ;
    PORT
      LAYER M4 ;
        RECT  0 15.984 0.192 16.008 ;
    END
  END o[132]
  PIN o[133]
    DIRECTION OUTPUT ;
    USE SIGNAL ;
    PORT
      LAYER M4 ;
        RECT  0 16.128 0.192 16.152 ;
    END
  END o[133]
  PIN o[134]
    DIRECTION OUTPUT ;
    USE SIGNAL ;
    PORT
      LAYER M4 ;
        RECT  0 16.224 0.192 16.248 ;
    END
  END o[134]
  PIN o[135]
    DIRECTION OUTPUT ;
    USE SIGNAL ;
    PORT
      LAYER M4 ;
        RECT  0 16.32 0.192 16.344 ;
    END
  END o[135]
  PIN o[136]
    DIRECTION OUTPUT ;
    USE SIGNAL ;
    PORT
      LAYER M4 ;
        RECT  0 16.416 0.192 16.44 ;
    END
  END o[136]
  PIN o[137]
    DIRECTION OUTPUT ;
    USE SIGNAL ;
    PORT
      LAYER M4 ;
        RECT  0 16.512 0.192 16.536 ;
    END
  END o[137]
  PIN o[138]
    DIRECTION OUTPUT ;
    USE SIGNAL ;
    PORT
      LAYER M4 ;
        RECT  0 16.608 0.192 16.632 ;
    END
  END o[138]
  PIN o[139]
    DIRECTION OUTPUT ;
    USE SIGNAL ;
    PORT
      LAYER M4 ;
        RECT  0 16.752 0.192 16.776 ;
    END
  END o[139]
  PIN o[13]
    DIRECTION OUTPUT ;
    USE SIGNAL ;
    PORT
      LAYER M4 ;
        RECT  0 3.6 0.192 3.624 ;
    END
  END o[13]
  PIN o[140]
    DIRECTION OUTPUT ;
    USE SIGNAL ;
    PORT
      LAYER M4 ;
        RECT  0 16.848 0.192 16.872 ;
    END
  END o[140]
  PIN o[141]
    DIRECTION OUTPUT ;
    USE SIGNAL ;
    PORT
      LAYER M4 ;
        RECT  0 16.944 0.192 16.968 ;
    END
  END o[141]
  PIN o[142]
    DIRECTION OUTPUT ;
    USE SIGNAL ;
    PORT
      LAYER M4 ;
        RECT  0 17.04 0.192 17.064 ;
    END
  END o[142]
  PIN o[143]
    DIRECTION OUTPUT ;
    USE SIGNAL ;
    PORT
      LAYER M4 ;
        RECT  0 17.136 0.192 17.16 ;
    END
  END o[143]
  PIN o[144]
    DIRECTION OUTPUT ;
    USE SIGNAL ;
    PORT
      LAYER M4 ;
        RECT  0 17.232 0.192 17.256 ;
    END
  END o[144]
  PIN o[145]
    DIRECTION OUTPUT ;
    USE SIGNAL ;
    PORT
      LAYER M4 ;
        RECT  0 17.376 0.192 17.4 ;
    END
  END o[145]
  PIN o[146]
    DIRECTION OUTPUT ;
    USE SIGNAL ;
    PORT
      LAYER M4 ;
        RECT  0 17.472 0.192 17.496 ;
    END
  END o[146]
  PIN o[147]
    DIRECTION OUTPUT ;
    USE SIGNAL ;
    PORT
      LAYER M4 ;
        RECT  0 17.568 0.192 17.592 ;
    END
  END o[147]
  PIN o[148]
    DIRECTION OUTPUT ;
    USE SIGNAL ;
    PORT
      LAYER M4 ;
        RECT  0 17.664 0.192 17.688 ;
    END
  END o[148]
  PIN o[149]
    DIRECTION OUTPUT ;
    USE SIGNAL ;
    PORT
      LAYER M4 ;
        RECT  0 17.76 0.192 17.784 ;
    END
  END o[149]
  PIN o[14]
    DIRECTION OUTPUT ;
    USE SIGNAL ;
    PORT
      LAYER M4 ;
        RECT  0 3.696 0.192 3.72 ;
    END
  END o[14]
  PIN o[150]
    DIRECTION OUTPUT ;
    USE SIGNAL ;
    PORT
      LAYER M4 ;
        RECT  0 17.856 0.192 17.88 ;
    END
  END o[150]
  PIN o[151]
    DIRECTION OUTPUT ;
    USE SIGNAL ;
    PORT
      LAYER M4 ;
        RECT  0 18 0.192 18.024 ;
    END
  END o[151]
  PIN o[152]
    DIRECTION OUTPUT ;
    USE SIGNAL ;
    PORT
      LAYER M4 ;
        RECT  0 18.096 0.192 18.12 ;
    END
  END o[152]
  PIN o[153]
    DIRECTION OUTPUT ;
    USE SIGNAL ;
    PORT
      LAYER M4 ;
        RECT  0 18.192 0.192 18.216 ;
    END
  END o[153]
  PIN o[154]
    DIRECTION OUTPUT ;
    USE SIGNAL ;
    PORT
      LAYER M4 ;
        RECT  0 18.288 0.192 18.312 ;
    END
  END o[154]
  PIN o[155]
    DIRECTION OUTPUT ;
    USE SIGNAL ;
    PORT
      LAYER M4 ;
        RECT  0 18.384 0.192 18.408 ;
    END
  END o[155]
  PIN o[156]
    DIRECTION OUTPUT ;
    USE SIGNAL ;
    PORT
      LAYER M4 ;
        RECT  0 18.528 0.192 18.552 ;
    END
  END o[156]
  PIN o[157]
    DIRECTION OUTPUT ;
    USE SIGNAL ;
    PORT
      LAYER M4 ;
        RECT  0 18.624 0.192 18.648 ;
    END
  END o[157]
  PIN o[158]
    DIRECTION OUTPUT ;
    USE SIGNAL ;
    PORT
      LAYER M4 ;
        RECT  0 18.72 0.192 18.744 ;
    END
  END o[158]
  PIN o[159]
    DIRECTION OUTPUT ;
    USE SIGNAL ;
    PORT
      LAYER M4 ;
        RECT  0 18.816 0.192 18.84 ;
    END
  END o[159]
  PIN o[15]
    DIRECTION OUTPUT ;
    USE SIGNAL ;
    PORT
      LAYER M4 ;
        RECT  0 3.792 0.192 3.816 ;
    END
  END o[15]
  PIN o[160]
    DIRECTION OUTPUT ;
    USE SIGNAL ;
    PORT
      LAYER M4 ;
        RECT  0 18.912 0.192 18.936 ;
    END
  END o[160]
  PIN o[161]
    DIRECTION OUTPUT ;
    USE SIGNAL ;
    PORT
      LAYER M4 ;
        RECT  0 19.008 0.192 19.032 ;
    END
  END o[161]
  PIN o[162]
    DIRECTION OUTPUT ;
    USE SIGNAL ;
    PORT
      LAYER M4 ;
        RECT  0 19.152 0.192 19.176 ;
    END
  END o[162]
  PIN o[163]
    DIRECTION OUTPUT ;
    USE SIGNAL ;
    PORT
      LAYER M4 ;
        RECT  0 19.248 0.192 19.272 ;
    END
  END o[163]
  PIN o[164]
    DIRECTION OUTPUT ;
    USE SIGNAL ;
    PORT
      LAYER M4 ;
        RECT  0 19.344 0.192 19.368 ;
    END
  END o[164]
  PIN o[165]
    DIRECTION OUTPUT ;
    USE SIGNAL ;
    PORT
      LAYER M4 ;
        RECT  0 19.44 0.192 19.464 ;
    END
  END o[165]
  PIN o[166]
    DIRECTION OUTPUT ;
    USE SIGNAL ;
    PORT
      LAYER M4 ;
        RECT  0 19.536 0.192 19.56 ;
    END
  END o[166]
  PIN o[167]
    DIRECTION OUTPUT ;
    USE SIGNAL ;
    PORT
      LAYER M4 ;
        RECT  0 19.632 0.192 19.656 ;
    END
  END o[167]
  PIN o[168]
    DIRECTION OUTPUT ;
    USE SIGNAL ;
    PORT
      LAYER M4 ;
        RECT  0 19.776 0.192 19.8 ;
    END
  END o[168]
  PIN o[169]
    DIRECTION OUTPUT ;
    USE SIGNAL ;
    PORT
      LAYER M4 ;
        RECT  0 19.872 0.192 19.896 ;
    END
  END o[169]
  PIN o[16]
    DIRECTION OUTPUT ;
    USE SIGNAL ;
    PORT
      LAYER M4 ;
        RECT  0 3.888 0.192 3.912 ;
    END
  END o[16]
  PIN o[170]
    DIRECTION OUTPUT ;
    USE SIGNAL ;
    PORT
      LAYER M4 ;
        RECT  0 19.968 0.192 19.992 ;
    END
  END o[170]
  PIN o[171]
    DIRECTION OUTPUT ;
    USE SIGNAL ;
    PORT
      LAYER M4 ;
        RECT  0 20.064 0.192 20.088 ;
    END
  END o[171]
  PIN o[172]
    DIRECTION OUTPUT ;
    USE SIGNAL ;
    PORT
      LAYER M4 ;
        RECT  0 20.16 0.192 20.184 ;
    END
  END o[172]
  PIN o[173]
    DIRECTION OUTPUT ;
    USE SIGNAL ;
    PORT
      LAYER M4 ;
        RECT  0 20.256 0.192 20.28 ;
    END
  END o[173]
  PIN o[174]
    DIRECTION OUTPUT ;
    USE SIGNAL ;
    PORT
      LAYER M4 ;
        RECT  0 20.4 0.192 20.424 ;
    END
  END o[174]
  PIN o[175]
    DIRECTION OUTPUT ;
    USE SIGNAL ;
    PORT
      LAYER M4 ;
        RECT  0 20.496 0.192 20.52 ;
    END
  END o[175]
  PIN o[176]
    DIRECTION OUTPUT ;
    USE SIGNAL ;
    PORT
      LAYER M4 ;
        RECT  0 20.592 0.192 20.616 ;
    END
  END o[176]
  PIN o[177]
    DIRECTION OUTPUT ;
    USE SIGNAL ;
    PORT
      LAYER M4 ;
        RECT  0 20.688 0.192 20.712 ;
    END
  END o[177]
  PIN o[178]
    DIRECTION OUTPUT ;
    USE SIGNAL ;
    PORT
      LAYER M4 ;
        RECT  0 20.784 0.192 20.808 ;
    END
  END o[178]
  PIN o[179]
    DIRECTION OUTPUT ;
    USE SIGNAL ;
    PORT
      LAYER M4 ;
        RECT  0 20.928 0.192 20.952 ;
    END
  END o[179]
  PIN o[17]
    DIRECTION OUTPUT ;
    USE SIGNAL ;
    PORT
      LAYER M4 ;
        RECT  0 3.984 0.192 4.008 ;
    END
  END o[17]
  PIN o[180]
    DIRECTION OUTPUT ;
    USE SIGNAL ;
    PORT
      LAYER M4 ;
        RECT  0 21.024 0.192 21.048 ;
    END
  END o[180]
  PIN o[181]
    DIRECTION OUTPUT ;
    USE SIGNAL ;
    PORT
      LAYER M4 ;
        RECT  0 21.12 0.192 21.144 ;
    END
  END o[181]
  PIN o[182]
    DIRECTION OUTPUT ;
    USE SIGNAL ;
    PORT
      LAYER M4 ;
        RECT  0 21.216 0.192 21.24 ;
    END
  END o[182]
  PIN o[183]
    DIRECTION OUTPUT ;
    USE SIGNAL ;
    PORT
      LAYER M4 ;
        RECT  0 21.312 0.192 21.336 ;
    END
  END o[183]
  PIN o[184]
    DIRECTION OUTPUT ;
    USE SIGNAL ;
    PORT
      LAYER M4 ;
        RECT  0 21.408 0.192 21.432 ;
    END
  END o[184]
  PIN o[185]
    DIRECTION OUTPUT ;
    USE SIGNAL ;
    PORT
      LAYER M4 ;
        RECT  0 21.552 0.192 21.576 ;
    END
  END o[185]
  PIN o[186]
    DIRECTION OUTPUT ;
    USE SIGNAL ;
    PORT
      LAYER M4 ;
        RECT  0 21.648 0.192 21.672 ;
    END
  END o[186]
  PIN o[187]
    DIRECTION OUTPUT ;
    USE SIGNAL ;
    PORT
      LAYER M4 ;
        RECT  0 21.744 0.192 21.768 ;
    END
  END o[187]
  PIN o[188]
    DIRECTION OUTPUT ;
    USE SIGNAL ;
    PORT
      LAYER M4 ;
        RECT  0 21.84 0.192 21.864 ;
    END
  END o[188]
  PIN o[189]
    DIRECTION OUTPUT ;
    USE SIGNAL ;
    PORT
      LAYER M4 ;
        RECT  0 21.936 0.192 21.96 ;
    END
  END o[189]
  PIN o[18]
    DIRECTION OUTPUT ;
    USE SIGNAL ;
    PORT
      LAYER M4 ;
        RECT  0 4.08 0.192 4.104 ;
    END
  END o[18]
  PIN o[190]
    DIRECTION OUTPUT ;
    USE SIGNAL ;
    PORT
      LAYER M4 ;
        RECT  0 22.032 0.192 22.056 ;
    END
  END o[190]
  PIN o[191]
    DIRECTION OUTPUT ;
    USE SIGNAL ;
    PORT
      LAYER M4 ;
        RECT  0 22.176 0.192 22.2 ;
    END
  END o[191]
  PIN o[192]
    DIRECTION OUTPUT ;
    USE SIGNAL ;
    PORT
      LAYER M4 ;
        RECT  0 22.272 0.192 22.296 ;
    END
  END o[192]
  PIN o[193]
    DIRECTION OUTPUT ;
    USE SIGNAL ;
    PORT
      LAYER M4 ;
        RECT  0 22.368 0.192 22.392 ;
    END
  END o[193]
  PIN o[194]
    DIRECTION OUTPUT ;
    USE SIGNAL ;
    PORT
      LAYER M4 ;
        RECT  0 22.464 0.192 22.488 ;
    END
  END o[194]
  PIN o[195]
    DIRECTION OUTPUT ;
    USE SIGNAL ;
    PORT
      LAYER M4 ;
        RECT  0 22.56 0.192 22.584 ;
    END
  END o[195]
  PIN o[196]
    DIRECTION OUTPUT ;
    USE SIGNAL ;
    PORT
      LAYER M4 ;
        RECT  0 22.656 0.192 22.68 ;
    END
  END o[196]
  PIN o[197]
    DIRECTION OUTPUT ;
    USE SIGNAL ;
    PORT
      LAYER M4 ;
        RECT  0 22.8 0.192 22.824 ;
    END
  END o[197]
  PIN o[198]
    DIRECTION OUTPUT ;
    USE SIGNAL ;
    PORT
      LAYER M4 ;
        RECT  0 22.896 0.192 22.92 ;
    END
  END o[198]
  PIN o[199]
    DIRECTION OUTPUT ;
    USE SIGNAL ;
    PORT
      LAYER M4 ;
        RECT  0 22.992 0.192 23.016 ;
    END
  END o[199]
  PIN o[19]
    DIRECTION OUTPUT ;
    USE SIGNAL ;
    PORT
      LAYER M4 ;
        RECT  0 4.224 0.192 4.248 ;
    END
  END o[19]
  PIN o[1]
    DIRECTION OUTPUT ;
    USE SIGNAL ;
    PORT
      LAYER M4 ;
        RECT  0 2.352 0.192 2.376 ;
    END
  END o[1]
  PIN o[200]
    DIRECTION OUTPUT ;
    USE SIGNAL ;
    PORT
      LAYER M4 ;
        RECT  0 23.088 0.192 23.112 ;
    END
  END o[200]
  PIN o[201]
    DIRECTION OUTPUT ;
    USE SIGNAL ;
    PORT
      LAYER M4 ;
        RECT  0 23.184 0.192 23.208 ;
    END
  END o[201]
  PIN o[202]
    DIRECTION OUTPUT ;
    USE SIGNAL ;
    PORT
      LAYER M4 ;
        RECT  0 23.328 0.192 23.352 ;
    END
  END o[202]
  PIN o[203]
    DIRECTION OUTPUT ;
    USE SIGNAL ;
    PORT
      LAYER M4 ;
        RECT  0 23.424 0.192 23.448 ;
    END
  END o[203]
  PIN o[204]
    DIRECTION OUTPUT ;
    USE SIGNAL ;
    PORT
      LAYER M4 ;
        RECT  0 23.52 0.192 23.544 ;
    END
  END o[204]
  PIN o[205]
    DIRECTION OUTPUT ;
    USE SIGNAL ;
    PORT
      LAYER M4 ;
        RECT  0 23.616 0.192 23.64 ;
    END
  END o[205]
  PIN o[206]
    DIRECTION OUTPUT ;
    USE SIGNAL ;
    PORT
      LAYER M4 ;
        RECT  0 23.712 0.192 23.736 ;
    END
  END o[206]
  PIN o[207]
    DIRECTION OUTPUT ;
    USE SIGNAL ;
    PORT
      LAYER M4 ;
        RECT  0 23.808 0.192 23.832 ;
    END
  END o[207]
  PIN o[208]
    DIRECTION OUTPUT ;
    USE SIGNAL ;
    PORT
      LAYER M4 ;
        RECT  0 23.952 0.192 23.976 ;
    END
  END o[208]
  PIN o[209]
    DIRECTION OUTPUT ;
    USE SIGNAL ;
    PORT
      LAYER M4 ;
        RECT  0 24.048 0.192 24.072 ;
    END
  END o[209]
  PIN o[20]
    DIRECTION OUTPUT ;
    USE SIGNAL ;
    PORT
      LAYER M4 ;
        RECT  0 4.32 0.192 4.344 ;
    END
  END o[20]
  PIN o[210]
    DIRECTION OUTPUT ;
    USE SIGNAL ;
    PORT
      LAYER M4 ;
        RECT  0 24.144 0.192 24.168 ;
    END
  END o[210]
  PIN o[211]
    DIRECTION OUTPUT ;
    USE SIGNAL ;
    PORT
      LAYER M4 ;
        RECT  0 24.24 0.192 24.264 ;
    END
  END o[211]
  PIN o[212]
    DIRECTION OUTPUT ;
    USE SIGNAL ;
    PORT
      LAYER M4 ;
        RECT  0 24.336 0.192 24.36 ;
    END
  END o[212]
  PIN o[213]
    DIRECTION OUTPUT ;
    USE SIGNAL ;
    PORT
      LAYER M4 ;
        RECT  0 24.432 0.192 24.456 ;
    END
  END o[213]
  PIN o[214]
    DIRECTION OUTPUT ;
    USE SIGNAL ;
    PORT
      LAYER M4 ;
        RECT  0 24.576 0.192 24.6 ;
    END
  END o[214]
  PIN o[215]
    DIRECTION OUTPUT ;
    USE SIGNAL ;
    PORT
      LAYER M4 ;
        RECT  0 24.672 0.192 24.696 ;
    END
  END o[215]
  PIN o[216]
    DIRECTION OUTPUT ;
    USE SIGNAL ;
    PORT
      LAYER M4 ;
        RECT  0 24.768 0.192 24.792 ;
    END
  END o[216]
  PIN o[217]
    DIRECTION OUTPUT ;
    USE SIGNAL ;
    PORT
      LAYER M4 ;
        RECT  0 24.864 0.192 24.888 ;
    END
  END o[217]
  PIN o[218]
    DIRECTION OUTPUT ;
    USE SIGNAL ;
    PORT
      LAYER M4 ;
        RECT  0 24.96 0.192 24.984 ;
    END
  END o[218]
  PIN o[219]
    DIRECTION OUTPUT ;
    USE SIGNAL ;
    PORT
      LAYER M4 ;
        RECT  0 25.056 0.192 25.08 ;
    END
  END o[219]
  PIN o[21]
    DIRECTION OUTPUT ;
    USE SIGNAL ;
    PORT
      LAYER M4 ;
        RECT  0 4.416 0.192 4.44 ;
    END
  END o[21]
  PIN o[220]
    DIRECTION OUTPUT ;
    USE SIGNAL ;
    PORT
      LAYER M4 ;
        RECT  0 25.2 0.192 25.224 ;
    END
  END o[220]
  PIN o[221]
    DIRECTION OUTPUT ;
    USE SIGNAL ;
    PORT
      LAYER M4 ;
        RECT  0 25.296 0.192 25.32 ;
    END
  END o[221]
  PIN o[222]
    DIRECTION OUTPUT ;
    USE SIGNAL ;
    PORT
      LAYER M4 ;
        RECT  0 25.392 0.192 25.416 ;
    END
  END o[222]
  PIN o[223]
    DIRECTION OUTPUT ;
    USE SIGNAL ;
    PORT
      LAYER M4 ;
        RECT  0 25.488 0.192 25.512 ;
    END
  END o[223]
  PIN o[224]
    DIRECTION OUTPUT ;
    USE SIGNAL ;
    PORT
      LAYER M4 ;
        RECT  0 25.584 0.192 25.608 ;
    END
  END o[224]
  PIN o[225]
    DIRECTION OUTPUT ;
    USE SIGNAL ;
    PORT
      LAYER M4 ;
        RECT  0 25.728 0.192 25.752 ;
    END
  END o[225]
  PIN o[226]
    DIRECTION OUTPUT ;
    USE SIGNAL ;
    PORT
      LAYER M4 ;
        RECT  0 25.824 0.192 25.848 ;
    END
  END o[226]
  PIN o[227]
    DIRECTION OUTPUT ;
    USE SIGNAL ;
    PORT
      LAYER M4 ;
        RECT  0 25.92 0.192 25.944 ;
    END
  END o[227]
  PIN o[228]
    DIRECTION OUTPUT ;
    USE SIGNAL ;
    PORT
      LAYER M4 ;
        RECT  0 26.016 0.192 26.04 ;
    END
  END o[228]
  PIN o[229]
    DIRECTION OUTPUT ;
    USE SIGNAL ;
    PORT
      LAYER M4 ;
        RECT  0 26.112 0.192 26.136 ;
    END
  END o[229]
  PIN o[22]
    DIRECTION OUTPUT ;
    USE SIGNAL ;
    PORT
      LAYER M4 ;
        RECT  0 4.512 0.192 4.536 ;
    END
  END o[22]
  PIN o[230]
    DIRECTION OUTPUT ;
    USE SIGNAL ;
    PORT
      LAYER M4 ;
        RECT  0 26.208 0.192 26.232 ;
    END
  END o[230]
  PIN o[231]
    DIRECTION OUTPUT ;
    USE SIGNAL ;
    PORT
      LAYER M4 ;
        RECT  0 26.352 0.192 26.376 ;
    END
  END o[231]
  PIN o[232]
    DIRECTION OUTPUT ;
    USE SIGNAL ;
    PORT
      LAYER M4 ;
        RECT  0 26.448 0.192 26.472 ;
    END
  END o[232]
  PIN o[233]
    DIRECTION OUTPUT ;
    USE SIGNAL ;
    PORT
      LAYER M4 ;
        RECT  0 26.544 0.192 26.568 ;
    END
  END o[233]
  PIN o[234]
    DIRECTION OUTPUT ;
    USE SIGNAL ;
    PORT
      LAYER M4 ;
        RECT  0 26.64 0.192 26.664 ;
    END
  END o[234]
  PIN o[235]
    DIRECTION OUTPUT ;
    USE SIGNAL ;
    PORT
      LAYER M4 ;
        RECT  0 26.736 0.192 26.76 ;
    END
  END o[235]
  PIN o[236]
    DIRECTION OUTPUT ;
    USE SIGNAL ;
    PORT
      LAYER M4 ;
        RECT  0 26.832 0.192 26.856 ;
    END
  END o[236]
  PIN o[237]
    DIRECTION OUTPUT ;
    USE SIGNAL ;
    PORT
      LAYER M4 ;
        RECT  0 26.976 0.192 27 ;
    END
  END o[237]
  PIN o[238]
    DIRECTION OUTPUT ;
    USE SIGNAL ;
    PORT
      LAYER M4 ;
        RECT  0 27.072 0.192 27.096 ;
    END
  END o[238]
  PIN o[239]
    DIRECTION OUTPUT ;
    USE SIGNAL ;
    PORT
      LAYER M4 ;
        RECT  0 27.168 0.192 27.192 ;
    END
  END o[239]
  PIN o[23]
    DIRECTION OUTPUT ;
    USE SIGNAL ;
    PORT
      LAYER M4 ;
        RECT  0 4.608 0.192 4.632 ;
    END
  END o[23]
  PIN o[240]
    DIRECTION OUTPUT ;
    USE SIGNAL ;
    PORT
      LAYER M4 ;
        RECT  0 27.264 0.192 27.288 ;
    END
  END o[240]
  PIN o[241]
    DIRECTION OUTPUT ;
    USE SIGNAL ;
    PORT
      LAYER M4 ;
        RECT  0 27.36 0.192 27.384 ;
    END
  END o[241]
  PIN o[242]
    DIRECTION OUTPUT ;
    USE SIGNAL ;
    PORT
      LAYER M4 ;
        RECT  0 27.504 0.192 27.528 ;
    END
  END o[242]
  PIN o[243]
    DIRECTION OUTPUT ;
    USE SIGNAL ;
    PORT
      LAYER M4 ;
        RECT  0 27.6 0.192 27.624 ;
    END
  END o[243]
  PIN o[244]
    DIRECTION OUTPUT ;
    USE SIGNAL ;
    PORT
      LAYER M4 ;
        RECT  0 27.696 0.192 27.72 ;
    END
  END o[244]
  PIN o[245]
    DIRECTION OUTPUT ;
    USE SIGNAL ;
    PORT
      LAYER M4 ;
        RECT  0 27.792 0.192 27.816 ;
    END
  END o[245]
  PIN o[246]
    DIRECTION OUTPUT ;
    USE SIGNAL ;
    PORT
      LAYER M4 ;
        RECT  0 27.888 0.192 27.912 ;
    END
  END o[246]
  PIN o[247]
    DIRECTION OUTPUT ;
    USE SIGNAL ;
    PORT
      LAYER M4 ;
        RECT  0 27.984 0.192 28.008 ;
    END
  END o[247]
  PIN o[248]
    DIRECTION OUTPUT ;
    USE SIGNAL ;
    PORT
      LAYER M4 ;
        RECT  0 28.128 0.192 28.152 ;
    END
  END o[248]
  PIN o[249]
    DIRECTION OUTPUT ;
    USE SIGNAL ;
    PORT
      LAYER M4 ;
        RECT  0 28.224 0.192 28.248 ;
    END
  END o[249]
  PIN o[24]
    DIRECTION OUTPUT ;
    USE SIGNAL ;
    PORT
      LAYER M4 ;
        RECT  0 4.752 0.192 4.776 ;
    END
  END o[24]
  PIN o[250]
    DIRECTION OUTPUT ;
    USE SIGNAL ;
    PORT
      LAYER M4 ;
        RECT  0 28.32 0.192 28.344 ;
    END
  END o[250]
  PIN o[251]
    DIRECTION OUTPUT ;
    USE SIGNAL ;
    PORT
      LAYER M4 ;
        RECT  0 28.416 0.192 28.44 ;
    END
  END o[251]
  PIN o[252]
    DIRECTION OUTPUT ;
    USE SIGNAL ;
    PORT
      LAYER M4 ;
        RECT  0 28.512 0.192 28.536 ;
    END
  END o[252]
  PIN o[253]
    DIRECTION OUTPUT ;
    USE SIGNAL ;
    PORT
      LAYER M4 ;
        RECT  0 28.608 0.192 28.632 ;
    END
  END o[253]
  PIN o[254]
    DIRECTION OUTPUT ;
    USE SIGNAL ;
    PORT
      LAYER M4 ;
        RECT  0 28.752 0.192 28.776 ;
    END
  END o[254]
  PIN o[255]
    DIRECTION OUTPUT ;
    USE SIGNAL ;
    PORT
      LAYER M4 ;
        RECT  0 28.848 0.192 28.872 ;
    END
  END o[255]
  PIN o[256]
    DIRECTION OUTPUT ;
    USE SIGNAL ;
    PORT
      LAYER M4 ;
        RECT  0 28.944 0.192 28.968 ;
    END
  END o[256]
  PIN o[257]
    DIRECTION OUTPUT ;
    USE SIGNAL ;
    PORT
      LAYER M4 ;
        RECT  0 29.04 0.192 29.064 ;
    END
  END o[257]
  PIN o[258]
    DIRECTION OUTPUT ;
    USE SIGNAL ;
    PORT
      LAYER M4 ;
        RECT  0 29.136 0.192 29.16 ;
    END
  END o[258]
  PIN o[259]
    DIRECTION OUTPUT ;
    USE SIGNAL ;
    PORT
      LAYER M4 ;
        RECT  0 29.232 0.192 29.256 ;
    END
  END o[259]
  PIN o[25]
    DIRECTION OUTPUT ;
    USE SIGNAL ;
    PORT
      LAYER M4 ;
        RECT  0 4.848 0.192 4.872 ;
    END
  END o[25]
  PIN o[260]
    DIRECTION OUTPUT ;
    USE SIGNAL ;
    PORT
      LAYER M4 ;
        RECT  0 29.376 0.192 29.4 ;
    END
  END o[260]
  PIN o[261]
    DIRECTION OUTPUT ;
    USE SIGNAL ;
    PORT
      LAYER M4 ;
        RECT  0 29.472 0.192 29.496 ;
    END
  END o[261]
  PIN o[262]
    DIRECTION OUTPUT ;
    USE SIGNAL ;
    PORT
      LAYER M4 ;
        RECT  0 29.568 0.192 29.592 ;
    END
  END o[262]
  PIN o[263]
    DIRECTION OUTPUT ;
    USE SIGNAL ;
    PORT
      LAYER M4 ;
        RECT  0 29.664 0.192 29.688 ;
    END
  END o[263]
  PIN o[264]
    DIRECTION OUTPUT ;
    USE SIGNAL ;
    PORT
      LAYER M4 ;
        RECT  0 29.76 0.192 29.784 ;
    END
  END o[264]
  PIN o[265]
    DIRECTION OUTPUT ;
    USE SIGNAL ;
    PORT
      LAYER M4 ;
        RECT  0 29.904 0.192 29.928 ;
    END
  END o[265]
  PIN o[266]
    DIRECTION OUTPUT ;
    USE SIGNAL ;
    PORT
      LAYER M4 ;
        RECT  0 30 0.192 30.024 ;
    END
  END o[266]
  PIN o[267]
    DIRECTION OUTPUT ;
    USE SIGNAL ;
    PORT
      LAYER M4 ;
        RECT  0 30.096 0.192 30.12 ;
    END
  END o[267]
  PIN o[268]
    DIRECTION OUTPUT ;
    USE SIGNAL ;
    PORT
      LAYER M4 ;
        RECT  0 30.192 0.192 30.216 ;
    END
  END o[268]
  PIN o[269]
    DIRECTION OUTPUT ;
    USE SIGNAL ;
    PORT
      LAYER M4 ;
        RECT  0 30.288 0.192 30.312 ;
    END
  END o[269]
  PIN o[26]
    DIRECTION OUTPUT ;
    USE SIGNAL ;
    PORT
      LAYER M4 ;
        RECT  0 4.944 0.192 4.968 ;
    END
  END o[26]
  PIN o[270]
    DIRECTION OUTPUT ;
    USE SIGNAL ;
    PORT
      LAYER M4 ;
        RECT  0 30.384 0.192 30.408 ;
    END
  END o[270]
  PIN o[271]
    DIRECTION OUTPUT ;
    USE SIGNAL ;
    PORT
      LAYER M4 ;
        RECT  0 30.528 0.192 30.552 ;
    END
  END o[271]
  PIN o[272]
    DIRECTION OUTPUT ;
    USE SIGNAL ;
    PORT
      LAYER M4 ;
        RECT  0 30.624 0.192 30.648 ;
    END
  END o[272]
  PIN o[273]
    DIRECTION OUTPUT ;
    USE SIGNAL ;
    PORT
      LAYER M4 ;
        RECT  0 30.72 0.192 30.744 ;
    END
  END o[273]
  PIN o[274]
    DIRECTION OUTPUT ;
    USE SIGNAL ;
    PORT
      LAYER M4 ;
        RECT  0 30.816 0.192 30.84 ;
    END
  END o[274]
  PIN o[275]
    DIRECTION OUTPUT ;
    USE SIGNAL ;
    PORT
      LAYER M4 ;
        RECT  0 30.912 0.192 30.936 ;
    END
  END o[275]
  PIN o[276]
    DIRECTION OUTPUT ;
    USE SIGNAL ;
    PORT
      LAYER M4 ;
        RECT  0 31.008 0.192 31.032 ;
    END
  END o[276]
  PIN o[277]
    DIRECTION OUTPUT ;
    USE SIGNAL ;
    PORT
      LAYER M4 ;
        RECT  0 31.152 0.192 31.176 ;
    END
  END o[277]
  PIN o[278]
    DIRECTION OUTPUT ;
    USE SIGNAL ;
    PORT
      LAYER M4 ;
        RECT  0 31.248 0.192 31.272 ;
    END
  END o[278]
  PIN o[279]
    DIRECTION OUTPUT ;
    USE SIGNAL ;
    PORT
      LAYER M4 ;
        RECT  0 31.344 0.192 31.368 ;
    END
  END o[279]
  PIN o[27]
    DIRECTION OUTPUT ;
    USE SIGNAL ;
    PORT
      LAYER M4 ;
        RECT  0 5.04 0.192 5.064 ;
    END
  END o[27]
  PIN o[280]
    DIRECTION OUTPUT ;
    USE SIGNAL ;
    PORT
      LAYER M4 ;
        RECT  0 31.44 0.192 31.464 ;
    END
  END o[280]
  PIN o[281]
    DIRECTION OUTPUT ;
    USE SIGNAL ;
    PORT
      LAYER M4 ;
        RECT  0 31.536 0.192 31.56 ;
    END
  END o[281]
  PIN o[282]
    DIRECTION OUTPUT ;
    USE SIGNAL ;
    PORT
      LAYER M4 ;
        RECT  0 31.632 0.192 31.656 ;
    END
  END o[282]
  PIN o[283]
    DIRECTION OUTPUT ;
    USE SIGNAL ;
    PORT
      LAYER M4 ;
        RECT  0 31.776 0.192 31.8 ;
    END
  END o[283]
  PIN o[284]
    DIRECTION OUTPUT ;
    USE SIGNAL ;
    PORT
      LAYER M4 ;
        RECT  0 31.872 0.192 31.896 ;
    END
  END o[284]
  PIN o[285]
    DIRECTION OUTPUT ;
    USE SIGNAL ;
    PORT
      LAYER M4 ;
        RECT  0 31.968 0.192 31.992 ;
    END
  END o[285]
  PIN o[286]
    DIRECTION OUTPUT ;
    USE SIGNAL ;
    PORT
      LAYER M4 ;
        RECT  0 32.064 0.192 32.088 ;
    END
  END o[286]
  PIN o[287]
    DIRECTION OUTPUT ;
    USE SIGNAL ;
    PORT
      LAYER M4 ;
        RECT  0 32.16 0.192 32.184 ;
    END
  END o[287]
  PIN o[288]
    DIRECTION OUTPUT ;
    USE SIGNAL ;
    PORT
      LAYER M4 ;
        RECT  0 32.304 0.192 32.328 ;
    END
  END o[288]
  PIN o[289]
    DIRECTION OUTPUT ;
    USE SIGNAL ;
    PORT
      LAYER M4 ;
        RECT  0 32.4 0.192 32.424 ;
    END
  END o[289]
  PIN o[28]
    DIRECTION OUTPUT ;
    USE SIGNAL ;
    PORT
      LAYER M4 ;
        RECT  0 5.136 0.192 5.16 ;
    END
  END o[28]
  PIN o[290]
    DIRECTION OUTPUT ;
    USE SIGNAL ;
    PORT
      LAYER M4 ;
        RECT  0 32.496 0.192 32.52 ;
    END
  END o[290]
  PIN o[291]
    DIRECTION OUTPUT ;
    USE SIGNAL ;
    PORT
      LAYER M4 ;
        RECT  0 32.592 0.192 32.616 ;
    END
  END o[291]
  PIN o[292]
    DIRECTION OUTPUT ;
    USE SIGNAL ;
    PORT
      LAYER M4 ;
        RECT  0 32.688 0.192 32.712 ;
    END
  END o[292]
  PIN o[293]
    DIRECTION OUTPUT ;
    USE SIGNAL ;
    PORT
      LAYER M4 ;
        RECT  0 32.784 0.192 32.808 ;
    END
  END o[293]
  PIN o[294]
    DIRECTION OUTPUT ;
    USE SIGNAL ;
    PORT
      LAYER M4 ;
        RECT  0 32.928 0.192 32.952 ;
    END
  END o[294]
  PIN o[295]
    DIRECTION OUTPUT ;
    USE SIGNAL ;
    PORT
      LAYER M4 ;
        RECT  0 33.024 0.192 33.048 ;
    END
  END o[295]
  PIN o[296]
    DIRECTION OUTPUT ;
    USE SIGNAL ;
    PORT
      LAYER M4 ;
        RECT  0 33.12 0.192 33.144 ;
    END
  END o[296]
  PIN o[297]
    DIRECTION OUTPUT ;
    USE SIGNAL ;
    PORT
      LAYER M4 ;
        RECT  0 33.216 0.192 33.24 ;
    END
  END o[297]
  PIN o[298]
    DIRECTION OUTPUT ;
    USE SIGNAL ;
    PORT
      LAYER M4 ;
        RECT  0 33.312 0.192 33.336 ;
    END
  END o[298]
  PIN o[299]
    DIRECTION OUTPUT ;
    USE SIGNAL ;
    PORT
      LAYER M4 ;
        RECT  0 33.408 0.192 33.432 ;
    END
  END o[299]
  PIN o[29]
    DIRECTION OUTPUT ;
    USE SIGNAL ;
    PORT
      LAYER M4 ;
        RECT  0 5.232 0.192 5.256 ;
    END
  END o[29]
  PIN o[2]
    DIRECTION OUTPUT ;
    USE SIGNAL ;
    PORT
      LAYER M4 ;
        RECT  0 2.448 0.192 2.472 ;
    END
  END o[2]
  PIN o[300]
    DIRECTION OUTPUT ;
    USE SIGNAL ;
    PORT
      LAYER M4 ;
        RECT  0 33.552 0.192 33.576 ;
    END
  END o[300]
  PIN o[301]
    DIRECTION OUTPUT ;
    USE SIGNAL ;
    PORT
      LAYER M4 ;
        RECT  0 33.648 0.192 33.672 ;
    END
  END o[301]
  PIN o[302]
    DIRECTION OUTPUT ;
    USE SIGNAL ;
    PORT
      LAYER M4 ;
        RECT  0 33.744 0.192 33.768 ;
    END
  END o[302]
  PIN o[303]
    DIRECTION OUTPUT ;
    USE SIGNAL ;
    PORT
      LAYER M4 ;
        RECT  0 33.84 0.192 33.864 ;
    END
  END o[303]
  PIN o[304]
    DIRECTION OUTPUT ;
    USE SIGNAL ;
    PORT
      LAYER M4 ;
        RECT  0 33.936 0.192 33.96 ;
    END
  END o[304]
  PIN o[305]
    DIRECTION OUTPUT ;
    USE SIGNAL ;
    PORT
      LAYER M4 ;
        RECT  0 34.032 0.192 34.056 ;
    END
  END o[305]
  PIN o[306]
    DIRECTION OUTPUT ;
    USE SIGNAL ;
    PORT
      LAYER M4 ;
        RECT  0 34.176 0.192 34.2 ;
    END
  END o[306]
  PIN o[307]
    DIRECTION OUTPUT ;
    USE SIGNAL ;
    PORT
      LAYER M4 ;
        RECT  0 34.272 0.192 34.296 ;
    END
  END o[307]
  PIN o[308]
    DIRECTION OUTPUT ;
    USE SIGNAL ;
    PORT
      LAYER M4 ;
        RECT  0 34.368 0.192 34.392 ;
    END
  END o[308]
  PIN o[309]
    DIRECTION OUTPUT ;
    USE SIGNAL ;
    PORT
      LAYER M4 ;
        RECT  0 34.464 0.192 34.488 ;
    END
  END o[309]
  PIN o[30]
    DIRECTION OUTPUT ;
    USE SIGNAL ;
    PORT
      LAYER M4 ;
        RECT  0 5.376 0.192 5.4 ;
    END
  END o[30]
  PIN o[310]
    DIRECTION OUTPUT ;
    USE SIGNAL ;
    PORT
      LAYER M4 ;
        RECT  0 34.56 0.192 34.584 ;
    END
  END o[310]
  PIN o[311]
    DIRECTION OUTPUT ;
    USE SIGNAL ;
    PORT
      LAYER M4 ;
        RECT  0 34.704 0.192 34.728 ;
    END
  END o[311]
  PIN o[312]
    DIRECTION OUTPUT ;
    USE SIGNAL ;
    PORT
      LAYER M4 ;
        RECT  0 34.8 0.192 34.824 ;
    END
  END o[312]
  PIN o[313]
    DIRECTION OUTPUT ;
    USE SIGNAL ;
    PORT
      LAYER M4 ;
        RECT  0 34.896 0.192 34.92 ;
    END
  END o[313]
  PIN o[314]
    DIRECTION OUTPUT ;
    USE SIGNAL ;
    PORT
      LAYER M4 ;
        RECT  0 34.992 0.192 35.016 ;
    END
  END o[314]
  PIN o[315]
    DIRECTION OUTPUT ;
    USE SIGNAL ;
    PORT
      LAYER M4 ;
        RECT  0 35.088 0.192 35.112 ;
    END
  END o[315]
  PIN o[316]
    DIRECTION OUTPUT ;
    USE SIGNAL ;
    PORT
      LAYER M4 ;
        RECT  0 35.184 0.192 35.208 ;
    END
  END o[316]
  PIN o[317]
    DIRECTION OUTPUT ;
    USE SIGNAL ;
    PORT
      LAYER M4 ;
        RECT  0 35.328 0.192 35.352 ;
    END
  END o[317]
  PIN o[318]
    DIRECTION OUTPUT ;
    USE SIGNAL ;
    PORT
      LAYER M4 ;
        RECT  0 35.424 0.192 35.448 ;
    END
  END o[318]
  PIN o[319]
    DIRECTION OUTPUT ;
    USE SIGNAL ;
    PORT
      LAYER M4 ;
        RECT  0 35.52 0.192 35.544 ;
    END
  END o[319]
  PIN o[31]
    DIRECTION OUTPUT ;
    USE SIGNAL ;
    PORT
      LAYER M4 ;
        RECT  0 5.472 0.192 5.496 ;
    END
  END o[31]
  PIN o[320]
    DIRECTION OUTPUT ;
    USE SIGNAL ;
    PORT
      LAYER M4 ;
        RECT  0 35.616 0.192 35.64 ;
    END
  END o[320]
  PIN o[321]
    DIRECTION OUTPUT ;
    USE SIGNAL ;
    PORT
      LAYER M4 ;
        RECT  0 35.712 0.192 35.736 ;
    END
  END o[321]
  PIN o[322]
    DIRECTION OUTPUT ;
    USE SIGNAL ;
    PORT
      LAYER M4 ;
        RECT  0 35.808 0.192 35.832 ;
    END
  END o[322]
  PIN o[323]
    DIRECTION OUTPUT ;
    USE SIGNAL ;
    PORT
      LAYER M4 ;
        RECT  0 35.952 0.192 35.976 ;
    END
  END o[323]
  PIN o[324]
    DIRECTION OUTPUT ;
    USE SIGNAL ;
    PORT
      LAYER M4 ;
        RECT  0 36.048 0.192 36.072 ;
    END
  END o[324]
  PIN o[325]
    DIRECTION OUTPUT ;
    USE SIGNAL ;
    PORT
      LAYER M4 ;
        RECT  0 36.144 0.192 36.168 ;
    END
  END o[325]
  PIN o[326]
    DIRECTION OUTPUT ;
    USE SIGNAL ;
    PORT
      LAYER M4 ;
        RECT  0 36.24 0.192 36.264 ;
    END
  END o[326]
  PIN o[327]
    DIRECTION OUTPUT ;
    USE SIGNAL ;
    PORT
      LAYER M4 ;
        RECT  0 36.336 0.192 36.36 ;
    END
  END o[327]
  PIN o[328]
    DIRECTION OUTPUT ;
    USE SIGNAL ;
    PORT
      LAYER M4 ;
        RECT  0 36.432 0.192 36.456 ;
    END
  END o[328]
  PIN o[329]
    DIRECTION OUTPUT ;
    USE SIGNAL ;
    PORT
      LAYER M4 ;
        RECT  0 36.576 0.192 36.6 ;
    END
  END o[329]
  PIN o[32]
    DIRECTION OUTPUT ;
    USE SIGNAL ;
    PORT
      LAYER M4 ;
        RECT  0 5.568 0.192 5.592 ;
    END
  END o[32]
  PIN o[330]
    DIRECTION OUTPUT ;
    USE SIGNAL ;
    PORT
      LAYER M4 ;
        RECT  0 36.672 0.192 36.696 ;
    END
  END o[330]
  PIN o[331]
    DIRECTION OUTPUT ;
    USE SIGNAL ;
    PORT
      LAYER M4 ;
        RECT  0 36.768 0.192 36.792 ;
    END
  END o[331]
  PIN o[332]
    DIRECTION OUTPUT ;
    USE SIGNAL ;
    PORT
      LAYER M4 ;
        RECT  0 36.864 0.192 36.888 ;
    END
  END o[332]
  PIN o[333]
    DIRECTION OUTPUT ;
    USE SIGNAL ;
    PORT
      LAYER M4 ;
        RECT  0 36.96 0.192 36.984 ;
    END
  END o[333]
  PIN o[334]
    DIRECTION OUTPUT ;
    USE SIGNAL ;
    PORT
      LAYER M4 ;
        RECT  0 37.104 0.192 37.128 ;
    END
  END o[334]
  PIN o[335]
    DIRECTION OUTPUT ;
    USE SIGNAL ;
    PORT
      LAYER M4 ;
        RECT  0 37.2 0.192 37.224 ;
    END
  END o[335]
  PIN o[336]
    DIRECTION OUTPUT ;
    USE SIGNAL ;
    PORT
      LAYER M4 ;
        RECT  0 37.296 0.192 37.32 ;
    END
  END o[336]
  PIN o[337]
    DIRECTION OUTPUT ;
    USE SIGNAL ;
    PORT
      LAYER M4 ;
        RECT  0 37.392 0.192 37.416 ;
    END
  END o[337]
  PIN o[338]
    DIRECTION OUTPUT ;
    USE SIGNAL ;
    PORT
      LAYER M4 ;
        RECT  0 37.488 0.192 37.512 ;
    END
  END o[338]
  PIN o[339]
    DIRECTION OUTPUT ;
    USE SIGNAL ;
    PORT
      LAYER M4 ;
        RECT  0 37.584 0.192 37.608 ;
    END
  END o[339]
  PIN o[33]
    DIRECTION OUTPUT ;
    USE SIGNAL ;
    PORT
      LAYER M4 ;
        RECT  0 5.664 0.192 5.688 ;
    END
  END o[33]
  PIN o[340]
    DIRECTION OUTPUT ;
    USE SIGNAL ;
    PORT
      LAYER M4 ;
        RECT  0 37.728 0.192 37.752 ;
    END
  END o[340]
  PIN o[341]
    DIRECTION OUTPUT ;
    USE SIGNAL ;
    PORT
      LAYER M4 ;
        RECT  0 37.824 0.192 37.848 ;
    END
  END o[341]
  PIN o[342]
    DIRECTION OUTPUT ;
    USE SIGNAL ;
    PORT
      LAYER M4 ;
        RECT  0 37.92 0.192 37.944 ;
    END
  END o[342]
  PIN o[343]
    DIRECTION OUTPUT ;
    USE SIGNAL ;
    PORT
      LAYER M4 ;
        RECT  0 38.016 0.192 38.04 ;
    END
  END o[343]
  PIN o[344]
    DIRECTION OUTPUT ;
    USE SIGNAL ;
    PORT
      LAYER M4 ;
        RECT  0 38.112 0.192 38.136 ;
    END
  END o[344]
  PIN o[345]
    DIRECTION OUTPUT ;
    USE SIGNAL ;
    PORT
      LAYER M4 ;
        RECT  0 38.208 0.192 38.232 ;
    END
  END o[345]
  PIN o[346]
    DIRECTION OUTPUT ;
    USE SIGNAL ;
    PORT
      LAYER M4 ;
        RECT  0 38.352 0.192 38.376 ;
    END
  END o[346]
  PIN o[347]
    DIRECTION OUTPUT ;
    USE SIGNAL ;
    PORT
      LAYER M4 ;
        RECT  0 38.448 0.192 38.472 ;
    END
  END o[347]
  PIN o[348]
    DIRECTION OUTPUT ;
    USE SIGNAL ;
    PORT
      LAYER M4 ;
        RECT  0 38.544 0.192 38.568 ;
    END
  END o[348]
  PIN o[349]
    DIRECTION OUTPUT ;
    USE SIGNAL ;
    PORT
      LAYER M4 ;
        RECT  0 38.64 0.192 38.664 ;
    END
  END o[349]
  PIN o[34]
    DIRECTION OUTPUT ;
    USE SIGNAL ;
    PORT
      LAYER M4 ;
        RECT  0 5.76 0.192 5.784 ;
    END
  END o[34]
  PIN o[350]
    DIRECTION OUTPUT ;
    USE SIGNAL ;
    PORT
      LAYER M4 ;
        RECT  0 38.736 0.192 38.76 ;
    END
  END o[350]
  PIN o[351]
    DIRECTION OUTPUT ;
    USE SIGNAL ;
    PORT
      LAYER M4 ;
        RECT  0 38.832 0.192 38.856 ;
    END
  END o[351]
  PIN o[352]
    DIRECTION OUTPUT ;
    USE SIGNAL ;
    PORT
      LAYER M4 ;
        RECT  0 38.976 0.192 39 ;
    END
  END o[352]
  PIN o[353]
    DIRECTION OUTPUT ;
    USE SIGNAL ;
    PORT
      LAYER M4 ;
        RECT  0 39.072 0.192 39.096 ;
    END
  END o[353]
  PIN o[354]
    DIRECTION OUTPUT ;
    USE SIGNAL ;
    PORT
      LAYER M4 ;
        RECT  0 39.168 0.192 39.192 ;
    END
  END o[354]
  PIN o[355]
    DIRECTION OUTPUT ;
    USE SIGNAL ;
    PORT
      LAYER M4 ;
        RECT  0 39.264 0.192 39.288 ;
    END
  END o[355]
  PIN o[356]
    DIRECTION OUTPUT ;
    USE SIGNAL ;
    PORT
      LAYER M4 ;
        RECT  0 39.36 0.192 39.384 ;
    END
  END o[356]
  PIN o[357]
    DIRECTION OUTPUT ;
    USE SIGNAL ;
    PORT
      LAYER M4 ;
        RECT  0 39.504 0.192 39.528 ;
    END
  END o[357]
  PIN o[358]
    DIRECTION OUTPUT ;
    USE SIGNAL ;
    PORT
      LAYER M4 ;
        RECT  0 39.6 0.192 39.624 ;
    END
  END o[358]
  PIN o[359]
    DIRECTION OUTPUT ;
    USE SIGNAL ;
    PORT
      LAYER M4 ;
        RECT  0 39.696 0.192 39.72 ;
    END
  END o[359]
  PIN o[35]
    DIRECTION OUTPUT ;
    USE SIGNAL ;
    PORT
      LAYER M4 ;
        RECT  0 5.856 0.192 5.88 ;
    END
  END o[35]
  PIN o[360]
    DIRECTION OUTPUT ;
    USE SIGNAL ;
    PORT
      LAYER M4 ;
        RECT  0 39.792 0.192 39.816 ;
    END
  END o[360]
  PIN o[361]
    DIRECTION OUTPUT ;
    USE SIGNAL ;
    PORT
      LAYER M4 ;
        RECT  0 39.888 0.192 39.912 ;
    END
  END o[361]
  PIN o[362]
    DIRECTION OUTPUT ;
    USE SIGNAL ;
    PORT
      LAYER M4 ;
        RECT  0 39.984 0.192 40.008 ;
    END
  END o[362]
  PIN o[363]
    DIRECTION OUTPUT ;
    USE SIGNAL ;
    PORT
      LAYER M4 ;
        RECT  0 40.128 0.192 40.152 ;
    END
  END o[363]
  PIN o[364]
    DIRECTION OUTPUT ;
    USE SIGNAL ;
    PORT
      LAYER M4 ;
        RECT  0 40.224 0.192 40.248 ;
    END
  END o[364]
  PIN o[365]
    DIRECTION OUTPUT ;
    USE SIGNAL ;
    PORT
      LAYER M4 ;
        RECT  0 40.32 0.192 40.344 ;
    END
  END o[365]
  PIN o[366]
    DIRECTION OUTPUT ;
    USE SIGNAL ;
    PORT
      LAYER M4 ;
        RECT  0 40.416 0.192 40.44 ;
    END
  END o[366]
  PIN o[367]
    DIRECTION OUTPUT ;
    USE SIGNAL ;
    PORT
      LAYER M4 ;
        RECT  0 40.512 0.192 40.536 ;
    END
  END o[367]
  PIN o[368]
    DIRECTION OUTPUT ;
    USE SIGNAL ;
    PORT
      LAYER M4 ;
        RECT  0 40.608 0.192 40.632 ;
    END
  END o[368]
  PIN o[369]
    DIRECTION OUTPUT ;
    USE SIGNAL ;
    PORT
      LAYER M4 ;
        RECT  0 40.752 0.192 40.776 ;
    END
  END o[369]
  PIN o[36]
    DIRECTION OUTPUT ;
    USE SIGNAL ;
    PORT
      LAYER M4 ;
        RECT  0 6 0.192 6.024 ;
    END
  END o[36]
  PIN o[370]
    DIRECTION OUTPUT ;
    USE SIGNAL ;
    PORT
      LAYER M4 ;
        RECT  0 40.848 0.192 40.872 ;
    END
  END o[370]
  PIN o[371]
    DIRECTION OUTPUT ;
    USE SIGNAL ;
    PORT
      LAYER M4 ;
        RECT  0 40.944 0.192 40.968 ;
    END
  END o[371]
  PIN o[372]
    DIRECTION OUTPUT ;
    USE SIGNAL ;
    PORT
      LAYER M4 ;
        RECT  0 41.04 0.192 41.064 ;
    END
  END o[372]
  PIN o[373]
    DIRECTION OUTPUT ;
    USE SIGNAL ;
    PORT
      LAYER M4 ;
        RECT  0 41.136 0.192 41.16 ;
    END
  END o[373]
  PIN o[374]
    DIRECTION OUTPUT ;
    USE SIGNAL ;
    PORT
      LAYER M4 ;
        RECT  0 41.232 0.192 41.256 ;
    END
  END o[374]
  PIN o[375]
    DIRECTION OUTPUT ;
    USE SIGNAL ;
    PORT
      LAYER M4 ;
        RECT  0 41.376 0.192 41.4 ;
    END
  END o[375]
  PIN o[376]
    DIRECTION OUTPUT ;
    USE SIGNAL ;
    PORT
      LAYER M4 ;
        RECT  0 41.472 0.192 41.496 ;
    END
  END o[376]
  PIN o[377]
    DIRECTION OUTPUT ;
    USE SIGNAL ;
    PORT
      LAYER M4 ;
        RECT  0 41.568 0.192 41.592 ;
    END
  END o[377]
  PIN o[378]
    DIRECTION OUTPUT ;
    USE SIGNAL ;
    PORT
      LAYER M4 ;
        RECT  0 41.664 0.192 41.688 ;
    END
  END o[378]
  PIN o[379]
    DIRECTION OUTPUT ;
    USE SIGNAL ;
    PORT
      LAYER M4 ;
        RECT  0 41.76 0.192 41.784 ;
    END
  END o[379]
  PIN o[37]
    DIRECTION OUTPUT ;
    USE SIGNAL ;
    PORT
      LAYER M4 ;
        RECT  0 6.096 0.192 6.12 ;
    END
  END o[37]
  PIN o[380]
    DIRECTION OUTPUT ;
    USE SIGNAL ;
    PORT
      LAYER M4 ;
        RECT  0 41.904 0.192 41.928 ;
    END
  END o[380]
  PIN o[381]
    DIRECTION OUTPUT ;
    USE SIGNAL ;
    PORT
      LAYER M4 ;
        RECT  0 42 0.192 42.024 ;
    END
  END o[381]
  PIN o[382]
    DIRECTION OUTPUT ;
    USE SIGNAL ;
    PORT
      LAYER M4 ;
        RECT  0 42.096 0.192 42.12 ;
    END
  END o[382]
  PIN o[383]
    DIRECTION OUTPUT ;
    USE SIGNAL ;
    PORT
      LAYER M4 ;
        RECT  0 42.192 0.192 42.216 ;
    END
  END o[383]
  PIN o[384]
    DIRECTION OUTPUT ;
    USE SIGNAL ;
    PORT
      LAYER M4 ;
        RECT  0 42.288 0.192 42.312 ;
    END
  END o[384]
  PIN o[385]
    DIRECTION OUTPUT ;
    USE SIGNAL ;
    PORT
      LAYER M4 ;
        RECT  0 42.384 0.192 42.408 ;
    END
  END o[385]
  PIN o[386]
    DIRECTION OUTPUT ;
    USE SIGNAL ;
    PORT
      LAYER M4 ;
        RECT  0 42.528 0.192 42.552 ;
    END
  END o[386]
  PIN o[387]
    DIRECTION OUTPUT ;
    USE SIGNAL ;
    PORT
      LAYER M4 ;
        RECT  0 42.624 0.192 42.648 ;
    END
  END o[387]
  PIN o[388]
    DIRECTION OUTPUT ;
    USE SIGNAL ;
    PORT
      LAYER M4 ;
        RECT  0 42.72 0.192 42.744 ;
    END
  END o[388]
  PIN o[389]
    DIRECTION OUTPUT ;
    USE SIGNAL ;
    PORT
      LAYER M4 ;
        RECT  0 42.816 0.192 42.84 ;
    END
  END o[389]
  PIN o[38]
    DIRECTION OUTPUT ;
    USE SIGNAL ;
    PORT
      LAYER M4 ;
        RECT  0 6.192 0.192 6.216 ;
    END
  END o[38]
  PIN o[390]
    DIRECTION OUTPUT ;
    USE SIGNAL ;
    PORT
      LAYER M4 ;
        RECT  0 42.912 0.192 42.936 ;
    END
  END o[390]
  PIN o[391]
    DIRECTION OUTPUT ;
    USE SIGNAL ;
    PORT
      LAYER M4 ;
        RECT  0 43.008 0.192 43.032 ;
    END
  END o[391]
  PIN o[392]
    DIRECTION OUTPUT ;
    USE SIGNAL ;
    PORT
      LAYER M4 ;
        RECT  0 43.152 0.192 43.176 ;
    END
  END o[392]
  PIN o[393]
    DIRECTION OUTPUT ;
    USE SIGNAL ;
    PORT
      LAYER M4 ;
        RECT  0 43.248 0.192 43.272 ;
    END
  END o[393]
  PIN o[394]
    DIRECTION OUTPUT ;
    USE SIGNAL ;
    PORT
      LAYER M4 ;
        RECT  0 43.344 0.192 43.368 ;
    END
  END o[394]
  PIN o[395]
    DIRECTION OUTPUT ;
    USE SIGNAL ;
    PORT
      LAYER M4 ;
        RECT  0 43.44 0.192 43.464 ;
    END
  END o[395]
  PIN o[396]
    DIRECTION OUTPUT ;
    USE SIGNAL ;
    PORT
      LAYER M4 ;
        RECT  0 43.536 0.192 43.56 ;
    END
  END o[396]
  PIN o[397]
    DIRECTION OUTPUT ;
    USE SIGNAL ;
    PORT
      LAYER M4 ;
        RECT  0 43.68 0.192 43.704 ;
    END
  END o[397]
  PIN o[398]
    DIRECTION OUTPUT ;
    USE SIGNAL ;
    PORT
      LAYER M4 ;
        RECT  0 43.776 0.192 43.8 ;
    END
  END o[398]
  PIN o[399]
    DIRECTION OUTPUT ;
    USE SIGNAL ;
    PORT
      LAYER M4 ;
        RECT  0 43.872 0.192 43.896 ;
    END
  END o[399]
  PIN o[39]
    DIRECTION OUTPUT ;
    USE SIGNAL ;
    PORT
      LAYER M4 ;
        RECT  0 6.288 0.192 6.312 ;
    END
  END o[39]
  PIN o[3]
    DIRECTION OUTPUT ;
    USE SIGNAL ;
    PORT
      LAYER M4 ;
        RECT  0 2.544 0.192 2.568 ;
    END
  END o[3]
  PIN o[400]
    DIRECTION OUTPUT ;
    USE SIGNAL ;
    PORT
      LAYER M4 ;
        RECT  0 43.968 0.192 43.992 ;
    END
  END o[400]
  PIN o[401]
    DIRECTION OUTPUT ;
    USE SIGNAL ;
    PORT
      LAYER M4 ;
        RECT  0 44.064 0.192 44.088 ;
    END
  END o[401]
  PIN o[402]
    DIRECTION OUTPUT ;
    USE SIGNAL ;
    PORT
      LAYER M4 ;
        RECT  0 44.16 0.192 44.184 ;
    END
  END o[402]
  PIN o[403]
    DIRECTION OUTPUT ;
    USE SIGNAL ;
    PORT
      LAYER M4 ;
        RECT  0 44.304 0.192 44.328 ;
    END
  END o[403]
  PIN o[404]
    DIRECTION OUTPUT ;
    USE SIGNAL ;
    PORT
      LAYER M4 ;
        RECT  0 44.4 0.192 44.424 ;
    END
  END o[404]
  PIN o[405]
    DIRECTION OUTPUT ;
    USE SIGNAL ;
    PORT
      LAYER M4 ;
        RECT  0 44.496 0.192 44.52 ;
    END
  END o[405]
  PIN o[406]
    DIRECTION OUTPUT ;
    USE SIGNAL ;
    PORT
      LAYER M4 ;
        RECT  0 44.592 0.192 44.616 ;
    END
  END o[406]
  PIN o[407]
    DIRECTION OUTPUT ;
    USE SIGNAL ;
    PORT
      LAYER M4 ;
        RECT  0 44.688 0.192 44.712 ;
    END
  END o[407]
  PIN o[408]
    DIRECTION OUTPUT ;
    USE SIGNAL ;
    PORT
      LAYER M4 ;
        RECT  0 44.784 0.192 44.808 ;
    END
  END o[408]
  PIN o[409]
    DIRECTION OUTPUT ;
    USE SIGNAL ;
    PORT
      LAYER M4 ;
        RECT  0 44.928 0.192 44.952 ;
    END
  END o[409]
  PIN o[40]
    DIRECTION OUTPUT ;
    USE SIGNAL ;
    PORT
      LAYER M4 ;
        RECT  0 6.384 0.192 6.408 ;
    END
  END o[40]
  PIN o[410]
    DIRECTION OUTPUT ;
    USE SIGNAL ;
    PORT
      LAYER M4 ;
        RECT  0 45.024 0.192 45.048 ;
    END
  END o[410]
  PIN o[411]
    DIRECTION OUTPUT ;
    USE SIGNAL ;
    PORT
      LAYER M4 ;
        RECT  0 45.12 0.192 45.144 ;
    END
  END o[411]
  PIN o[412]
    DIRECTION OUTPUT ;
    USE SIGNAL ;
    PORT
      LAYER M4 ;
        RECT  0 45.216 0.192 45.24 ;
    END
  END o[412]
  PIN o[413]
    DIRECTION OUTPUT ;
    USE SIGNAL ;
    PORT
      LAYER M4 ;
        RECT  0 45.312 0.192 45.336 ;
    END
  END o[413]
  PIN o[414]
    DIRECTION OUTPUT ;
    USE SIGNAL ;
    PORT
      LAYER M4 ;
        RECT  0 45.408 0.192 45.432 ;
    END
  END o[414]
  PIN o[415]
    DIRECTION OUTPUT ;
    USE SIGNAL ;
    PORT
      LAYER M4 ;
        RECT  0 45.552 0.192 45.576 ;
    END
  END o[415]
  PIN o[416]
    DIRECTION OUTPUT ;
    USE SIGNAL ;
    PORT
      LAYER M4 ;
        RECT  0 45.648 0.192 45.672 ;
    END
  END o[416]
  PIN o[417]
    DIRECTION OUTPUT ;
    USE SIGNAL ;
    PORT
      LAYER M4 ;
        RECT  0 45.744 0.192 45.768 ;
    END
  END o[417]
  PIN o[418]
    DIRECTION OUTPUT ;
    USE SIGNAL ;
    PORT
      LAYER M4 ;
        RECT  0 45.84 0.192 45.864 ;
    END
  END o[418]
  PIN o[419]
    DIRECTION OUTPUT ;
    USE SIGNAL ;
    PORT
      LAYER M4 ;
        RECT  0 45.936 0.192 45.96 ;
    END
  END o[419]
  PIN o[41]
    DIRECTION OUTPUT ;
    USE SIGNAL ;
    PORT
      LAYER M4 ;
        RECT  0 6.48 0.192 6.504 ;
    END
  END o[41]
  PIN o[420]
    DIRECTION OUTPUT ;
    USE SIGNAL ;
    PORT
      LAYER M4 ;
        RECT  0 46.08 0.192 46.104 ;
    END
  END o[420]
  PIN o[421]
    DIRECTION OUTPUT ;
    USE SIGNAL ;
    PORT
      LAYER M4 ;
        RECT  0 46.176 0.192 46.2 ;
    END
  END o[421]
  PIN o[422]
    DIRECTION OUTPUT ;
    USE SIGNAL ;
    PORT
      LAYER M4 ;
        RECT  0 46.272 0.192 46.296 ;
    END
  END o[422]
  PIN o[423]
    DIRECTION OUTPUT ;
    USE SIGNAL ;
    PORT
      LAYER M4 ;
        RECT  0 46.368 0.192 46.392 ;
    END
  END o[423]
  PIN o[424]
    DIRECTION OUTPUT ;
    USE SIGNAL ;
    PORT
      LAYER M4 ;
        RECT  0 46.464 0.192 46.488 ;
    END
  END o[424]
  PIN o[425]
    DIRECTION OUTPUT ;
    USE SIGNAL ;
    PORT
      LAYER M4 ;
        RECT  0 46.56 0.192 46.584 ;
    END
  END o[425]
  PIN o[426]
    DIRECTION OUTPUT ;
    USE SIGNAL ;
    PORT
      LAYER M4 ;
        RECT  0 46.704 0.192 46.728 ;
    END
  END o[426]
  PIN o[427]
    DIRECTION OUTPUT ;
    USE SIGNAL ;
    PORT
      LAYER M4 ;
        RECT  0 46.8 0.192 46.824 ;
    END
  END o[427]
  PIN o[428]
    DIRECTION OUTPUT ;
    USE SIGNAL ;
    PORT
      LAYER M4 ;
        RECT  0 46.896 0.192 46.92 ;
    END
  END o[428]
  PIN o[429]
    DIRECTION OUTPUT ;
    USE SIGNAL ;
    PORT
      LAYER M4 ;
        RECT  0 46.992 0.192 47.016 ;
    END
  END o[429]
  PIN o[42]
    DIRECTION OUTPUT ;
    USE SIGNAL ;
    PORT
      LAYER M4 ;
        RECT  0 6.624 0.192 6.648 ;
    END
  END o[42]
  PIN o[430]
    DIRECTION OUTPUT ;
    USE SIGNAL ;
    PORT
      LAYER M4 ;
        RECT  0 47.088 0.192 47.112 ;
    END
  END o[430]
  PIN o[431]
    DIRECTION OUTPUT ;
    USE SIGNAL ;
    PORT
      LAYER M4 ;
        RECT  0 47.184 0.192 47.208 ;
    END
  END o[431]
  PIN o[432]
    DIRECTION OUTPUT ;
    USE SIGNAL ;
    PORT
      LAYER M4 ;
        RECT  0 47.328 0.192 47.352 ;
    END
  END o[432]
  PIN o[433]
    DIRECTION OUTPUT ;
    USE SIGNAL ;
    PORT
      LAYER M4 ;
        RECT  0 47.424 0.192 47.448 ;
    END
  END o[433]
  PIN o[434]
    DIRECTION OUTPUT ;
    USE SIGNAL ;
    PORT
      LAYER M4 ;
        RECT  0 47.52 0.192 47.544 ;
    END
  END o[434]
  PIN o[435]
    DIRECTION OUTPUT ;
    USE SIGNAL ;
    PORT
      LAYER M4 ;
        RECT  0 47.616 0.192 47.64 ;
    END
  END o[435]
  PIN o[436]
    DIRECTION OUTPUT ;
    USE SIGNAL ;
    PORT
      LAYER M4 ;
        RECT  0 47.712 0.192 47.736 ;
    END
  END o[436]
  PIN o[437]
    DIRECTION OUTPUT ;
    USE SIGNAL ;
    PORT
      LAYER M4 ;
        RECT  0 47.808 0.192 47.832 ;
    END
  END o[437]
  PIN o[438]
    DIRECTION OUTPUT ;
    USE SIGNAL ;
    PORT
      LAYER M4 ;
        RECT  0 47.952 0.192 47.976 ;
    END
  END o[438]
  PIN o[439]
    DIRECTION OUTPUT ;
    USE SIGNAL ;
    PORT
      LAYER M4 ;
        RECT  0 48.048 0.192 48.072 ;
    END
  END o[439]
  PIN o[43]
    DIRECTION OUTPUT ;
    USE SIGNAL ;
    PORT
      LAYER M4 ;
        RECT  0 6.72 0.192 6.744 ;
    END
  END o[43]
  PIN o[440]
    DIRECTION OUTPUT ;
    USE SIGNAL ;
    PORT
      LAYER M4 ;
        RECT  0 48.144 0.192 48.168 ;
    END
  END o[440]
  PIN o[441]
    DIRECTION OUTPUT ;
    USE SIGNAL ;
    PORT
      LAYER M4 ;
        RECT  0 48.24 0.192 48.264 ;
    END
  END o[441]
  PIN o[442]
    DIRECTION OUTPUT ;
    USE SIGNAL ;
    PORT
      LAYER M4 ;
        RECT  0 48.336 0.192 48.36 ;
    END
  END o[442]
  PIN o[443]
    DIRECTION OUTPUT ;
    USE SIGNAL ;
    PORT
      LAYER M4 ;
        RECT  0 48.48 0.192 48.504 ;
    END
  END o[443]
  PIN o[444]
    DIRECTION OUTPUT ;
    USE SIGNAL ;
    PORT
      LAYER M4 ;
        RECT  0 48.576 0.192 48.6 ;
    END
  END o[444]
  PIN o[445]
    DIRECTION OUTPUT ;
    USE SIGNAL ;
    PORT
      LAYER M4 ;
        RECT  0 48.672 0.192 48.696 ;
    END
  END o[445]
  PIN o[446]
    DIRECTION OUTPUT ;
    USE SIGNAL ;
    PORT
      LAYER M4 ;
        RECT  0 48.768 0.192 48.792 ;
    END
  END o[446]
  PIN o[447]
    DIRECTION OUTPUT ;
    USE SIGNAL ;
    PORT
      LAYER M4 ;
        RECT  0 48.864 0.192 48.888 ;
    END
  END o[447]
  PIN o[448]
    DIRECTION OUTPUT ;
    USE SIGNAL ;
    PORT
      LAYER M4 ;
        RECT  0 48.96 0.192 48.984 ;
    END
  END o[448]
  PIN o[449]
    DIRECTION OUTPUT ;
    USE SIGNAL ;
    PORT
      LAYER M4 ;
        RECT  0 49.104 0.192 49.128 ;
    END
  END o[449]
  PIN o[44]
    DIRECTION OUTPUT ;
    USE SIGNAL ;
    PORT
      LAYER M4 ;
        RECT  0 6.816 0.192 6.84 ;
    END
  END o[44]
  PIN o[450]
    DIRECTION OUTPUT ;
    USE SIGNAL ;
    PORT
      LAYER M4 ;
        RECT  0 49.2 0.192 49.224 ;
    END
  END o[450]
  PIN o[451]
    DIRECTION OUTPUT ;
    USE SIGNAL ;
    PORT
      LAYER M4 ;
        RECT  0 49.296 0.192 49.32 ;
    END
  END o[451]
  PIN o[452]
    DIRECTION OUTPUT ;
    USE SIGNAL ;
    PORT
      LAYER M4 ;
        RECT  0 49.392 0.192 49.416 ;
    END
  END o[452]
  PIN o[453]
    DIRECTION OUTPUT ;
    USE SIGNAL ;
    PORT
      LAYER M4 ;
        RECT  0 49.488 0.192 49.512 ;
    END
  END o[453]
  PIN o[454]
    DIRECTION OUTPUT ;
    USE SIGNAL ;
    PORT
      LAYER M4 ;
        RECT  0 49.584 0.192 49.608 ;
    END
  END o[454]
  PIN o[455]
    DIRECTION OUTPUT ;
    USE SIGNAL ;
    PORT
      LAYER M4 ;
        RECT  0 49.728 0.192 49.752 ;
    END
  END o[455]
  PIN o[456]
    DIRECTION OUTPUT ;
    USE SIGNAL ;
    PORT
      LAYER M4 ;
        RECT  0 49.824 0.192 49.848 ;
    END
  END o[456]
  PIN o[457]
    DIRECTION OUTPUT ;
    USE SIGNAL ;
    PORT
      LAYER M4 ;
        RECT  0 49.92 0.192 49.944 ;
    END
  END o[457]
  PIN o[458]
    DIRECTION OUTPUT ;
    USE SIGNAL ;
    PORT
      LAYER M4 ;
        RECT  0 50.016 0.192 50.04 ;
    END
  END o[458]
  PIN o[459]
    DIRECTION OUTPUT ;
    USE SIGNAL ;
    PORT
      LAYER M4 ;
        RECT  0 50.112 0.192 50.136 ;
    END
  END o[459]
  PIN o[45]
    DIRECTION OUTPUT ;
    USE SIGNAL ;
    PORT
      LAYER M4 ;
        RECT  0 6.912 0.192 6.936 ;
    END
  END o[45]
  PIN o[460]
    DIRECTION OUTPUT ;
    USE SIGNAL ;
    PORT
      LAYER M4 ;
        RECT  0 50.208 0.192 50.232 ;
    END
  END o[460]
  PIN o[461]
    DIRECTION OUTPUT ;
    USE SIGNAL ;
    PORT
      LAYER M4 ;
        RECT  0 50.352 0.192 50.376 ;
    END
  END o[461]
  PIN o[462]
    DIRECTION OUTPUT ;
    USE SIGNAL ;
    PORT
      LAYER M4 ;
        RECT  0 50.448 0.192 50.472 ;
    END
  END o[462]
  PIN o[463]
    DIRECTION OUTPUT ;
    USE SIGNAL ;
    PORT
      LAYER M4 ;
        RECT  0 50.544 0.192 50.568 ;
    END
  END o[463]
  PIN o[464]
    DIRECTION OUTPUT ;
    USE SIGNAL ;
    PORT
      LAYER M4 ;
        RECT  0 50.64 0.192 50.664 ;
    END
  END o[464]
  PIN o[465]
    DIRECTION OUTPUT ;
    USE SIGNAL ;
    PORT
      LAYER M4 ;
        RECT  0 50.736 0.192 50.76 ;
    END
  END o[465]
  PIN o[466]
    DIRECTION OUTPUT ;
    USE SIGNAL ;
    PORT
      LAYER M4 ;
        RECT  0 50.88 0.192 50.904 ;
    END
  END o[466]
  PIN o[467]
    DIRECTION OUTPUT ;
    USE SIGNAL ;
    PORT
      LAYER M4 ;
        RECT  0 50.976 0.192 51 ;
    END
  END o[467]
  PIN o[468]
    DIRECTION OUTPUT ;
    USE SIGNAL ;
    PORT
      LAYER M4 ;
        RECT  0 51.072 0.192 51.096 ;
    END
  END o[468]
  PIN o[469]
    DIRECTION OUTPUT ;
    USE SIGNAL ;
    PORT
      LAYER M4 ;
        RECT  0 51.168 0.192 51.192 ;
    END
  END o[469]
  PIN o[46]
    DIRECTION OUTPUT ;
    USE SIGNAL ;
    PORT
      LAYER M4 ;
        RECT  0 7.008 0.192 7.032 ;
    END
  END o[46]
  PIN o[470]
    DIRECTION OUTPUT ;
    USE SIGNAL ;
    PORT
      LAYER M4 ;
        RECT  0 51.264 0.192 51.288 ;
    END
  END o[470]
  PIN o[471]
    DIRECTION OUTPUT ;
    USE SIGNAL ;
    PORT
      LAYER M4 ;
        RECT  0 51.36 0.192 51.384 ;
    END
  END o[471]
  PIN o[472]
    DIRECTION OUTPUT ;
    USE SIGNAL ;
    PORT
      LAYER M4 ;
        RECT  0 51.504 0.192 51.528 ;
    END
  END o[472]
  PIN o[473]
    DIRECTION OUTPUT ;
    USE SIGNAL ;
    PORT
      LAYER M4 ;
        RECT  0 51.6 0.192 51.624 ;
    END
  END o[473]
  PIN o[474]
    DIRECTION OUTPUT ;
    USE SIGNAL ;
    PORT
      LAYER M4 ;
        RECT  0 51.696 0.192 51.72 ;
    END
  END o[474]
  PIN o[475]
    DIRECTION OUTPUT ;
    USE SIGNAL ;
    PORT
      LAYER M4 ;
        RECT  0 51.792 0.192 51.816 ;
    END
  END o[475]
  PIN o[476]
    DIRECTION OUTPUT ;
    USE SIGNAL ;
    PORT
      LAYER M4 ;
        RECT  0 51.888 0.192 51.912 ;
    END
  END o[476]
  PIN o[477]
    DIRECTION OUTPUT ;
    USE SIGNAL ;
    PORT
      LAYER M4 ;
        RECT  0 51.984 0.192 52.008 ;
    END
  END o[477]
  PIN o[478]
    DIRECTION OUTPUT ;
    USE SIGNAL ;
    PORT
      LAYER M4 ;
        RECT  0 52.128 0.192 52.152 ;
    END
  END o[478]
  PIN o[479]
    DIRECTION OUTPUT ;
    USE SIGNAL ;
    PORT
      LAYER M4 ;
        RECT  0 52.224 0.192 52.248 ;
    END
  END o[479]
  PIN o[47]
    DIRECTION OUTPUT ;
    USE SIGNAL ;
    PORT
      LAYER M4 ;
        RECT  0 7.152 0.192 7.176 ;
    END
  END o[47]
  PIN o[480]
    DIRECTION OUTPUT ;
    USE SIGNAL ;
    PORT
      LAYER M4 ;
        RECT  0 52.32 0.192 52.344 ;
    END
  END o[480]
  PIN o[481]
    DIRECTION OUTPUT ;
    USE SIGNAL ;
    PORT
      LAYER M4 ;
        RECT  0 52.416 0.192 52.44 ;
    END
  END o[481]
  PIN o[482]
    DIRECTION OUTPUT ;
    USE SIGNAL ;
    PORT
      LAYER M4 ;
        RECT  0 52.512 0.192 52.536 ;
    END
  END o[482]
  PIN o[483]
    DIRECTION OUTPUT ;
    USE SIGNAL ;
    PORT
      LAYER M4 ;
        RECT  0 52.608 0.192 52.632 ;
    END
  END o[483]
  PIN o[484]
    DIRECTION OUTPUT ;
    USE SIGNAL ;
    PORT
      LAYER M4 ;
        RECT  0 52.752 0.192 52.776 ;
    END
  END o[484]
  PIN o[485]
    DIRECTION OUTPUT ;
    USE SIGNAL ;
    PORT
      LAYER M4 ;
        RECT  0 52.848 0.192 52.872 ;
    END
  END o[485]
  PIN o[486]
    DIRECTION OUTPUT ;
    USE SIGNAL ;
    PORT
      LAYER M4 ;
        RECT  0 52.944 0.192 52.968 ;
    END
  END o[486]
  PIN o[487]
    DIRECTION OUTPUT ;
    USE SIGNAL ;
    PORT
      LAYER M4 ;
        RECT  0 53.04 0.192 53.064 ;
    END
  END o[487]
  PIN o[488]
    DIRECTION OUTPUT ;
    USE SIGNAL ;
    PORT
      LAYER M4 ;
        RECT  0 53.136 0.192 53.16 ;
    END
  END o[488]
  PIN o[489]
    DIRECTION OUTPUT ;
    USE SIGNAL ;
    PORT
      LAYER M4 ;
        RECT  0 53.28 0.192 53.304 ;
    END
  END o[489]
  PIN o[48]
    DIRECTION OUTPUT ;
    USE SIGNAL ;
    PORT
      LAYER M4 ;
        RECT  0 7.248 0.192 7.272 ;
    END
  END o[48]
  PIN o[490]
    DIRECTION OUTPUT ;
    USE SIGNAL ;
    PORT
      LAYER M4 ;
        RECT  0 53.376 0.192 53.4 ;
    END
  END o[490]
  PIN o[491]
    DIRECTION OUTPUT ;
    USE SIGNAL ;
    PORT
      LAYER M4 ;
        RECT  0 53.472 0.192 53.496 ;
    END
  END o[491]
  PIN o[492]
    DIRECTION OUTPUT ;
    USE SIGNAL ;
    PORT
      LAYER M4 ;
        RECT  0 53.568 0.192 53.592 ;
    END
  END o[492]
  PIN o[493]
    DIRECTION OUTPUT ;
    USE SIGNAL ;
    PORT
      LAYER M4 ;
        RECT  0 53.664 0.192 53.688 ;
    END
  END o[493]
  PIN o[494]
    DIRECTION OUTPUT ;
    USE SIGNAL ;
    PORT
      LAYER M4 ;
        RECT  0 53.76 0.192 53.784 ;
    END
  END o[494]
  PIN o[495]
    DIRECTION OUTPUT ;
    USE SIGNAL ;
    PORT
      LAYER M4 ;
        RECT  0 53.904 0.192 53.928 ;
    END
  END o[495]
  PIN o[496]
    DIRECTION OUTPUT ;
    USE SIGNAL ;
    PORT
      LAYER M4 ;
        RECT  0 54 0.192 54.024 ;
    END
  END o[496]
  PIN o[497]
    DIRECTION OUTPUT ;
    USE SIGNAL ;
    PORT
      LAYER M4 ;
        RECT  0 54.096 0.192 54.12 ;
    END
  END o[497]
  PIN o[498]
    DIRECTION OUTPUT ;
    USE SIGNAL ;
    PORT
      LAYER M4 ;
        RECT  0 54.192 0.192 54.216 ;
    END
  END o[498]
  PIN o[499]
    DIRECTION OUTPUT ;
    USE SIGNAL ;
    PORT
      LAYER M4 ;
        RECT  0 54.288 0.192 54.312 ;
    END
  END o[499]
  PIN o[49]
    DIRECTION OUTPUT ;
    USE SIGNAL ;
    PORT
      LAYER M4 ;
        RECT  0 7.344 0.192 7.368 ;
    END
  END o[49]
  PIN o[4]
    DIRECTION OUTPUT ;
    USE SIGNAL ;
    PORT
      LAYER M4 ;
        RECT  0 2.64 0.192 2.664 ;
    END
  END o[4]
  PIN o[500]
    DIRECTION OUTPUT ;
    USE SIGNAL ;
    PORT
      LAYER M4 ;
        RECT  0 54.384 0.192 54.408 ;
    END
  END o[500]
  PIN o[501]
    DIRECTION OUTPUT ;
    USE SIGNAL ;
    PORT
      LAYER M4 ;
        RECT  0 54.528 0.192 54.552 ;
    END
  END o[501]
  PIN o[502]
    DIRECTION OUTPUT ;
    USE SIGNAL ;
    PORT
      LAYER M4 ;
        RECT  0 54.624 0.192 54.648 ;
    END
  END o[502]
  PIN o[503]
    DIRECTION OUTPUT ;
    USE SIGNAL ;
    PORT
      LAYER M4 ;
        RECT  0 54.72 0.192 54.744 ;
    END
  END o[503]
  PIN o[504]
    DIRECTION OUTPUT ;
    USE SIGNAL ;
    PORT
      LAYER M4 ;
        RECT  0 54.816 0.192 54.84 ;
    END
  END o[504]
  PIN o[505]
    DIRECTION OUTPUT ;
    USE SIGNAL ;
    PORT
      LAYER M4 ;
        RECT  0 54.912 0.192 54.936 ;
    END
  END o[505]
  PIN o[506]
    DIRECTION OUTPUT ;
    USE SIGNAL ;
    PORT
      LAYER M4 ;
        RECT  0 55.008 0.192 55.032 ;
    END
  END o[506]
  PIN o[507]
    DIRECTION OUTPUT ;
    USE SIGNAL ;
    PORT
      LAYER M4 ;
        RECT  0 55.152 0.192 55.176 ;
    END
  END o[507]
  PIN o[508]
    DIRECTION OUTPUT ;
    USE SIGNAL ;
    PORT
      LAYER M4 ;
        RECT  0 55.248 0.192 55.272 ;
    END
  END o[508]
  PIN o[509]
    DIRECTION OUTPUT ;
    USE SIGNAL ;
    PORT
      LAYER M4 ;
        RECT  0 55.344 0.192 55.368 ;
    END
  END o[509]
  PIN o[50]
    DIRECTION OUTPUT ;
    USE SIGNAL ;
    PORT
      LAYER M4 ;
        RECT  0 7.44 0.192 7.464 ;
    END
  END o[50]
  PIN o[510]
    DIRECTION OUTPUT ;
    USE SIGNAL ;
    PORT
      LAYER M4 ;
        RECT  0 55.44 0.192 55.464 ;
    END
  END o[510]
  PIN o[511]
    DIRECTION OUTPUT ;
    USE SIGNAL ;
    PORT
      LAYER M4 ;
        RECT  0 55.536 0.192 55.56 ;
    END
  END o[511]
  PIN o[512]
    DIRECTION OUTPUT ;
    USE SIGNAL ;
    PORT
      LAYER M4 ;
        RECT  0 55.68 0.192 55.704 ;
    END
  END o[512]
  PIN o[513]
    DIRECTION OUTPUT ;
    USE SIGNAL ;
    PORT
      LAYER M4 ;
        RECT  0 55.776 0.192 55.8 ;
    END
  END o[513]
  PIN o[514]
    DIRECTION OUTPUT ;
    USE SIGNAL ;
    PORT
      LAYER M4 ;
        RECT  0 55.872 0.192 55.896 ;
    END
  END o[514]
  PIN o[515]
    DIRECTION OUTPUT ;
    USE SIGNAL ;
    PORT
      LAYER M4 ;
        RECT  0 55.968 0.192 55.992 ;
    END
  END o[515]
  PIN o[516]
    DIRECTION OUTPUT ;
    USE SIGNAL ;
    PORT
      LAYER M4 ;
        RECT  0 56.064 0.192 56.088 ;
    END
  END o[516]
  PIN o[517]
    DIRECTION OUTPUT ;
    USE SIGNAL ;
    PORT
      LAYER M4 ;
        RECT  0 56.16 0.192 56.184 ;
    END
  END o[517]
  PIN o[518]
    DIRECTION OUTPUT ;
    USE SIGNAL ;
    PORT
      LAYER M4 ;
        RECT  0 56.304 0.192 56.328 ;
    END
  END o[518]
  PIN o[519]
    DIRECTION OUTPUT ;
    USE SIGNAL ;
    PORT
      LAYER M4 ;
        RECT  0 56.4 0.192 56.424 ;
    END
  END o[519]
  PIN o[51]
    DIRECTION OUTPUT ;
    USE SIGNAL ;
    PORT
      LAYER M4 ;
        RECT  0 7.536 0.192 7.56 ;
    END
  END o[51]
  PIN o[520]
    DIRECTION OUTPUT ;
    USE SIGNAL ;
    PORT
      LAYER M4 ;
        RECT  0 56.496 0.192 56.52 ;
    END
  END o[520]
  PIN o[521]
    DIRECTION OUTPUT ;
    USE SIGNAL ;
    PORT
      LAYER M4 ;
        RECT  0 56.592 0.192 56.616 ;
    END
  END o[521]
  PIN o[522]
    DIRECTION OUTPUT ;
    USE SIGNAL ;
    PORT
      LAYER M4 ;
        RECT  0 56.688 0.192 56.712 ;
    END
  END o[522]
  PIN o[523]
    DIRECTION OUTPUT ;
    USE SIGNAL ;
    PORT
      LAYER M4 ;
        RECT  0 56.784 0.192 56.808 ;
    END
  END o[523]
  PIN o[524]
    DIRECTION OUTPUT ;
    USE SIGNAL ;
    PORT
      LAYER M4 ;
        RECT  0 56.928 0.192 56.952 ;
    END
  END o[524]
  PIN o[525]
    DIRECTION OUTPUT ;
    USE SIGNAL ;
    PORT
      LAYER M4 ;
        RECT  0 57.024 0.192 57.048 ;
    END
  END o[525]
  PIN o[526]
    DIRECTION OUTPUT ;
    USE SIGNAL ;
    PORT
      LAYER M4 ;
        RECT  0 57.12 0.192 57.144 ;
    END
  END o[526]
  PIN o[527]
    DIRECTION OUTPUT ;
    USE SIGNAL ;
    PORT
      LAYER M4 ;
        RECT  0 57.216 0.192 57.24 ;
    END
  END o[527]
  PIN o[528]
    DIRECTION OUTPUT ;
    USE SIGNAL ;
    PORT
      LAYER M4 ;
        RECT  0 57.312 0.192 57.336 ;
    END
  END o[528]
  PIN o[529]
    DIRECTION OUTPUT ;
    USE SIGNAL ;
    PORT
      LAYER M4 ;
        RECT  0 57.456 0.192 57.48 ;
    END
  END o[529]
  PIN o[52]
    DIRECTION OUTPUT ;
    USE SIGNAL ;
    PORT
      LAYER M4 ;
        RECT  0 7.632 0.192 7.656 ;
    END
  END o[52]
  PIN o[530]
    DIRECTION OUTPUT ;
    USE SIGNAL ;
    PORT
      LAYER M4 ;
        RECT  0 57.552 0.192 57.576 ;
    END
  END o[530]
  PIN o[531]
    DIRECTION OUTPUT ;
    USE SIGNAL ;
    PORT
      LAYER M4 ;
        RECT  0 57.648 0.192 57.672 ;
    END
  END o[531]
  PIN o[532]
    DIRECTION OUTPUT ;
    USE SIGNAL ;
    PORT
      LAYER M4 ;
        RECT  0 57.744 0.192 57.768 ;
    END
  END o[532]
  PIN o[533]
    DIRECTION OUTPUT ;
    USE SIGNAL ;
    PORT
      LAYER M4 ;
        RECT  0 57.84 0.192 57.864 ;
    END
  END o[533]
  PIN o[534]
    DIRECTION OUTPUT ;
    USE SIGNAL ;
    PORT
      LAYER M4 ;
        RECT  0 57.936 0.192 57.96 ;
    END
  END o[534]
  PIN o[535]
    DIRECTION OUTPUT ;
    USE SIGNAL ;
    PORT
      LAYER M4 ;
        RECT  0 58.08 0.192 58.104 ;
    END
  END o[535]
  PIN o[536]
    DIRECTION OUTPUT ;
    USE SIGNAL ;
    PORT
      LAYER M4 ;
        RECT  0 58.176 0.192 58.2 ;
    END
  END o[536]
  PIN o[537]
    DIRECTION OUTPUT ;
    USE SIGNAL ;
    PORT
      LAYER M4 ;
        RECT  0 58.272 0.192 58.296 ;
    END
  END o[537]
  PIN o[538]
    DIRECTION OUTPUT ;
    USE SIGNAL ;
    PORT
      LAYER M4 ;
        RECT  0 58.368 0.192 58.392 ;
    END
  END o[538]
  PIN o[539]
    DIRECTION OUTPUT ;
    USE SIGNAL ;
    PORT
      LAYER M4 ;
        RECT  0 58.464 0.192 58.488 ;
    END
  END o[539]
  PIN o[53]
    DIRECTION OUTPUT ;
    USE SIGNAL ;
    PORT
      LAYER M4 ;
        RECT  0 7.776 0.192 7.8 ;
    END
  END o[53]
  PIN o[540]
    DIRECTION OUTPUT ;
    USE SIGNAL ;
    PORT
      LAYER M4 ;
        RECT  0 58.56 0.192 58.584 ;
    END
  END o[540]
  PIN o[541]
    DIRECTION OUTPUT ;
    USE SIGNAL ;
    PORT
      LAYER M4 ;
        RECT  0 58.704 0.192 58.728 ;
    END
  END o[541]
  PIN o[542]
    DIRECTION OUTPUT ;
    USE SIGNAL ;
    PORT
      LAYER M4 ;
        RECT  0 58.8 0.192 58.824 ;
    END
  END o[542]
  PIN o[543]
    DIRECTION OUTPUT ;
    USE SIGNAL ;
    PORT
      LAYER M4 ;
        RECT  0 58.896 0.192 58.92 ;
    END
  END o[543]
  PIN o[544]
    DIRECTION OUTPUT ;
    USE SIGNAL ;
    PORT
      LAYER M4 ;
        RECT  0 58.992 0.192 59.016 ;
    END
  END o[544]
  PIN o[545]
    DIRECTION OUTPUT ;
    USE SIGNAL ;
    PORT
      LAYER M4 ;
        RECT  0 59.088 0.192 59.112 ;
    END
  END o[545]
  PIN o[546]
    DIRECTION OUTPUT ;
    USE SIGNAL ;
    PORT
      LAYER M4 ;
        RECT  0 59.184 0.192 59.208 ;
    END
  END o[546]
  PIN o[547]
    DIRECTION OUTPUT ;
    USE SIGNAL ;
    PORT
      LAYER M4 ;
        RECT  0 59.328 0.192 59.352 ;
    END
  END o[547]
  PIN o[548]
    DIRECTION OUTPUT ;
    USE SIGNAL ;
    PORT
      LAYER M4 ;
        RECT  0 59.424 0.192 59.448 ;
    END
  END o[548]
  PIN o[549]
    DIRECTION OUTPUT ;
    USE SIGNAL ;
    PORT
      LAYER M4 ;
        RECT  0 59.52 0.192 59.544 ;
    END
  END o[549]
  PIN o[54]
    DIRECTION OUTPUT ;
    USE SIGNAL ;
    PORT
      LAYER M4 ;
        RECT  0 7.872 0.192 7.896 ;
    END
  END o[54]
  PIN o[550]
    DIRECTION OUTPUT ;
    USE SIGNAL ;
    PORT
      LAYER M4 ;
        RECT  0 59.616 0.192 59.64 ;
    END
  END o[550]
  PIN o[551]
    DIRECTION OUTPUT ;
    USE SIGNAL ;
    PORT
      LAYER M4 ;
        RECT  0 59.712 0.192 59.736 ;
    END
  END o[551]
  PIN o[552]
    DIRECTION OUTPUT ;
    USE SIGNAL ;
    PORT
      LAYER M4 ;
        RECT  0 59.856 0.192 59.88 ;
    END
  END o[552]
  PIN o[553]
    DIRECTION OUTPUT ;
    USE SIGNAL ;
    PORT
      LAYER M4 ;
        RECT  0 59.952 0.192 59.976 ;
    END
  END o[553]
  PIN o[554]
    DIRECTION OUTPUT ;
    USE SIGNAL ;
    PORT
      LAYER M4 ;
        RECT  0 60.048 0.192 60.072 ;
    END
  END o[554]
  PIN o[555]
    DIRECTION OUTPUT ;
    USE SIGNAL ;
    PORT
      LAYER M4 ;
        RECT  0 60.144 0.192 60.168 ;
    END
  END o[555]
  PIN o[556]
    DIRECTION OUTPUT ;
    USE SIGNAL ;
    PORT
      LAYER M4 ;
        RECT  0 60.24 0.192 60.264 ;
    END
  END o[556]
  PIN o[557]
    DIRECTION OUTPUT ;
    USE SIGNAL ;
    PORT
      LAYER M4 ;
        RECT  0 60.336 0.192 60.36 ;
    END
  END o[557]
  PIN o[558]
    DIRECTION OUTPUT ;
    USE SIGNAL ;
    PORT
      LAYER M4 ;
        RECT  0 60.48 0.192 60.504 ;
    END
  END o[558]
  PIN o[559]
    DIRECTION OUTPUT ;
    USE SIGNAL ;
    PORT
      LAYER M4 ;
        RECT  0 60.576 0.192 60.6 ;
    END
  END o[559]
  PIN o[55]
    DIRECTION OUTPUT ;
    USE SIGNAL ;
    PORT
      LAYER M4 ;
        RECT  0 7.968 0.192 7.992 ;
    END
  END o[55]
  PIN o[560]
    DIRECTION OUTPUT ;
    USE SIGNAL ;
    PORT
      LAYER M4 ;
        RECT  0 60.672 0.192 60.696 ;
    END
  END o[560]
  PIN o[561]
    DIRECTION OUTPUT ;
    USE SIGNAL ;
    PORT
      LAYER M4 ;
        RECT  0 60.768 0.192 60.792 ;
    END
  END o[561]
  PIN o[562]
    DIRECTION OUTPUT ;
    USE SIGNAL ;
    PORT
      LAYER M4 ;
        RECT  0 60.864 0.192 60.888 ;
    END
  END o[562]
  PIN o[563]
    DIRECTION OUTPUT ;
    USE SIGNAL ;
    PORT
      LAYER M4 ;
        RECT  0 60.96 0.192 60.984 ;
    END
  END o[563]
  PIN o[564]
    DIRECTION OUTPUT ;
    USE SIGNAL ;
    PORT
      LAYER M4 ;
        RECT  0 61.104 0.192 61.128 ;
    END
  END o[564]
  PIN o[565]
    DIRECTION OUTPUT ;
    USE SIGNAL ;
    PORT
      LAYER M4 ;
        RECT  0 61.2 0.192 61.224 ;
    END
  END o[565]
  PIN o[566]
    DIRECTION OUTPUT ;
    USE SIGNAL ;
    PORT
      LAYER M4 ;
        RECT  0 61.296 0.192 61.32 ;
    END
  END o[566]
  PIN o[567]
    DIRECTION OUTPUT ;
    USE SIGNAL ;
    PORT
      LAYER M4 ;
        RECT  0 61.392 0.192 61.416 ;
    END
  END o[567]
  PIN o[568]
    DIRECTION OUTPUT ;
    USE SIGNAL ;
    PORT
      LAYER M4 ;
        RECT  0 61.488 0.192 61.512 ;
    END
  END o[568]
  PIN o[569]
    DIRECTION OUTPUT ;
    USE SIGNAL ;
    PORT
      LAYER M4 ;
        RECT  0 61.584 0.192 61.608 ;
    END
  END o[569]
  PIN o[56]
    DIRECTION OUTPUT ;
    USE SIGNAL ;
    PORT
      LAYER M4 ;
        RECT  0 8.064 0.192 8.088 ;
    END
  END o[56]
  PIN o[570]
    DIRECTION OUTPUT ;
    USE SIGNAL ;
    PORT
      LAYER M4 ;
        RECT  0 61.728 0.192 61.752 ;
    END
  END o[570]
  PIN o[571]
    DIRECTION OUTPUT ;
    USE SIGNAL ;
    PORT
      LAYER M4 ;
        RECT  0 61.824 0.192 61.848 ;
    END
  END o[571]
  PIN o[572]
    DIRECTION OUTPUT ;
    USE SIGNAL ;
    PORT
      LAYER M4 ;
        RECT  0 61.92 0.192 61.944 ;
    END
  END o[572]
  PIN o[573]
    DIRECTION OUTPUT ;
    USE SIGNAL ;
    PORT
      LAYER M4 ;
        RECT  0 62.016 0.192 62.04 ;
    END
  END o[573]
  PIN o[574]
    DIRECTION OUTPUT ;
    USE SIGNAL ;
    PORT
      LAYER M4 ;
        RECT  0 62.112 0.192 62.136 ;
    END
  END o[574]
  PIN o[575]
    DIRECTION OUTPUT ;
    USE SIGNAL ;
    PORT
      LAYER M4 ;
        RECT  0 62.256 0.192 62.28 ;
    END
  END o[575]
  PIN o[576]
    DIRECTION OUTPUT ;
    USE SIGNAL ;
    PORT
      LAYER M4 ;
        RECT  0 62.352 0.192 62.376 ;
    END
  END o[576]
  PIN o[577]
    DIRECTION OUTPUT ;
    USE SIGNAL ;
    PORT
      LAYER M4 ;
        RECT  0 62.448 0.192 62.472 ;
    END
  END o[577]
  PIN o[578]
    DIRECTION OUTPUT ;
    USE SIGNAL ;
    PORT
      LAYER M4 ;
        RECT  0 62.544 0.192 62.568 ;
    END
  END o[578]
  PIN o[579]
    DIRECTION OUTPUT ;
    USE SIGNAL ;
    PORT
      LAYER M4 ;
        RECT  0 62.64 0.192 62.664 ;
    END
  END o[579]
  PIN o[57]
    DIRECTION OUTPUT ;
    USE SIGNAL ;
    PORT
      LAYER M4 ;
        RECT  0 8.16 0.192 8.184 ;
    END
  END o[57]
  PIN o[580]
    DIRECTION OUTPUT ;
    USE SIGNAL ;
    PORT
      LAYER M4 ;
        RECT  0 62.736 0.192 62.76 ;
    END
  END o[580]
  PIN o[581]
    DIRECTION OUTPUT ;
    USE SIGNAL ;
    PORT
      LAYER M4 ;
        RECT  0 62.88 0.192 62.904 ;
    END
  END o[581]
  PIN o[582]
    DIRECTION OUTPUT ;
    USE SIGNAL ;
    PORT
      LAYER M4 ;
        RECT  0 62.976 0.192 63 ;
    END
  END o[582]
  PIN o[583]
    DIRECTION OUTPUT ;
    USE SIGNAL ;
    PORT
      LAYER M4 ;
        RECT  0 63.072 0.192 63.096 ;
    END
  END o[583]
  PIN o[584]
    DIRECTION OUTPUT ;
    USE SIGNAL ;
    PORT
      LAYER M4 ;
        RECT  0 63.168 0.192 63.192 ;
    END
  END o[584]
  PIN o[585]
    DIRECTION OUTPUT ;
    USE SIGNAL ;
    PORT
      LAYER M4 ;
        RECT  0 63.264 0.192 63.288 ;
    END
  END o[585]
  PIN o[586]
    DIRECTION OUTPUT ;
    USE SIGNAL ;
    PORT
      LAYER M4 ;
        RECT  0 63.36 0.192 63.384 ;
    END
  END o[586]
  PIN o[587]
    DIRECTION OUTPUT ;
    USE SIGNAL ;
    PORT
      LAYER M4 ;
        RECT  0 63.504 0.192 63.528 ;
    END
  END o[587]
  PIN o[588]
    DIRECTION OUTPUT ;
    USE SIGNAL ;
    PORT
      LAYER M4 ;
        RECT  0 63.6 0.192 63.624 ;
    END
  END o[588]
  PIN o[589]
    DIRECTION OUTPUT ;
    USE SIGNAL ;
    PORT
      LAYER M4 ;
        RECT  0 63.696 0.192 63.72 ;
    END
  END o[589]
  PIN o[58]
    DIRECTION OUTPUT ;
    USE SIGNAL ;
    PORT
      LAYER M4 ;
        RECT  0 8.256 0.192 8.28 ;
    END
  END o[58]
  PIN o[590]
    DIRECTION OUTPUT ;
    USE SIGNAL ;
    PORT
      LAYER M4 ;
        RECT  0 63.792 0.192 63.816 ;
    END
  END o[590]
  PIN o[591]
    DIRECTION OUTPUT ;
    USE SIGNAL ;
    PORT
      LAYER M4 ;
        RECT  0 63.888 0.192 63.912 ;
    END
  END o[591]
  PIN o[592]
    DIRECTION OUTPUT ;
    USE SIGNAL ;
    PORT
      LAYER M4 ;
        RECT  0 63.984 0.192 64.008 ;
    END
  END o[592]
  PIN o[593]
    DIRECTION OUTPUT ;
    USE SIGNAL ;
    PORT
      LAYER M4 ;
        RECT  0 64.128 0.192 64.152 ;
    END
  END o[593]
  PIN o[594]
    DIRECTION OUTPUT ;
    USE SIGNAL ;
    PORT
      LAYER M4 ;
        RECT  0 64.224 0.192 64.248 ;
    END
  END o[594]
  PIN o[595]
    DIRECTION OUTPUT ;
    USE SIGNAL ;
    PORT
      LAYER M4 ;
        RECT  0 64.32 0.192 64.344 ;
    END
  END o[595]
  PIN o[596]
    DIRECTION OUTPUT ;
    USE SIGNAL ;
    PORT
      LAYER M4 ;
        RECT  0 64.416 0.192 64.44 ;
    END
  END o[596]
  PIN o[597]
    DIRECTION OUTPUT ;
    USE SIGNAL ;
    PORT
      LAYER M4 ;
        RECT  0 64.512 0.192 64.536 ;
    END
  END o[597]
  PIN o[598]
    DIRECTION OUTPUT ;
    USE SIGNAL ;
    PORT
      LAYER M4 ;
        RECT  0 64.656 0.192 64.68 ;
    END
  END o[598]
  PIN o[599]
    DIRECTION OUTPUT ;
    USE SIGNAL ;
    PORT
      LAYER M4 ;
        RECT  0 64.752 0.192 64.776 ;
    END
  END o[599]
  PIN o[59]
    DIRECTION OUTPUT ;
    USE SIGNAL ;
    PORT
      LAYER M4 ;
        RECT  0 8.4 0.192 8.424 ;
    END
  END o[59]
  PIN o[5]
    DIRECTION OUTPUT ;
    USE SIGNAL ;
    PORT
      LAYER M4 ;
        RECT  0 2.736 0.192 2.76 ;
    END
  END o[5]
  PIN o[600]
    DIRECTION OUTPUT ;
    USE SIGNAL ;
    PORT
      LAYER M4 ;
        RECT  0 64.848 0.192 64.872 ;
    END
  END o[600]
  PIN o[601]
    DIRECTION OUTPUT ;
    USE SIGNAL ;
    PORT
      LAYER M4 ;
        RECT  0 64.944 0.192 64.968 ;
    END
  END o[601]
  PIN o[602]
    DIRECTION OUTPUT ;
    USE SIGNAL ;
    PORT
      LAYER M4 ;
        RECT  0 65.04 0.192 65.064 ;
    END
  END o[602]
  PIN o[603]
    DIRECTION OUTPUT ;
    USE SIGNAL ;
    PORT
      LAYER M4 ;
        RECT  0 65.136 0.192 65.16 ;
    END
  END o[603]
  PIN o[604]
    DIRECTION OUTPUT ;
    USE SIGNAL ;
    PORT
      LAYER M4 ;
        RECT  0 65.28 0.192 65.304 ;
    END
  END o[604]
  PIN o[605]
    DIRECTION OUTPUT ;
    USE SIGNAL ;
    PORT
      LAYER M4 ;
        RECT  0 65.376 0.192 65.4 ;
    END
  END o[605]
  PIN o[606]
    DIRECTION OUTPUT ;
    USE SIGNAL ;
    PORT
      LAYER M4 ;
        RECT  0 65.472 0.192 65.496 ;
    END
  END o[606]
  PIN o[607]
    DIRECTION OUTPUT ;
    USE SIGNAL ;
    PORT
      LAYER M4 ;
        RECT  0 65.568 0.192 65.592 ;
    END
  END o[607]
  PIN o[608]
    DIRECTION OUTPUT ;
    USE SIGNAL ;
    PORT
      LAYER M4 ;
        RECT  0 65.664 0.192 65.688 ;
    END
  END o[608]
  PIN o[609]
    DIRECTION OUTPUT ;
    USE SIGNAL ;
    PORT
      LAYER M4 ;
        RECT  0 65.76 0.192 65.784 ;
    END
  END o[609]
  PIN o[60]
    DIRECTION OUTPUT ;
    USE SIGNAL ;
    PORT
      LAYER M4 ;
        RECT  0 8.496 0.192 8.52 ;
    END
  END o[60]
  PIN o[610]
    DIRECTION OUTPUT ;
    USE SIGNAL ;
    PORT
      LAYER M4 ;
        RECT  0 65.904 0.192 65.928 ;
    END
  END o[610]
  PIN o[611]
    DIRECTION OUTPUT ;
    USE SIGNAL ;
    PORT
      LAYER M4 ;
        RECT  0 66 0.192 66.024 ;
    END
  END o[611]
  PIN o[612]
    DIRECTION OUTPUT ;
    USE SIGNAL ;
    PORT
      LAYER M4 ;
        RECT  0 66.096 0.192 66.12 ;
    END
  END o[612]
  PIN o[613]
    DIRECTION OUTPUT ;
    USE SIGNAL ;
    PORT
      LAYER M4 ;
        RECT  0 66.192 0.192 66.216 ;
    END
  END o[613]
  PIN o[614]
    DIRECTION OUTPUT ;
    USE SIGNAL ;
    PORT
      LAYER M4 ;
        RECT  0 66.288 0.192 66.312 ;
    END
  END o[614]
  PIN o[615]
    DIRECTION OUTPUT ;
    USE SIGNAL ;
    PORT
      LAYER M4 ;
        RECT  0 66.384 0.192 66.408 ;
    END
  END o[615]
  PIN o[616]
    DIRECTION OUTPUT ;
    USE SIGNAL ;
    PORT
      LAYER M4 ;
        RECT  0 66.528 0.192 66.552 ;
    END
  END o[616]
  PIN o[617]
    DIRECTION OUTPUT ;
    USE SIGNAL ;
    PORT
      LAYER M4 ;
        RECT  0 66.624 0.192 66.648 ;
    END
  END o[617]
  PIN o[618]
    DIRECTION OUTPUT ;
    USE SIGNAL ;
    PORT
      LAYER M4 ;
        RECT  0 66.72 0.192 66.744 ;
    END
  END o[618]
  PIN o[619]
    DIRECTION OUTPUT ;
    USE SIGNAL ;
    PORT
      LAYER M4 ;
        RECT  0 66.816 0.192 66.84 ;
    END
  END o[619]
  PIN o[61]
    DIRECTION OUTPUT ;
    USE SIGNAL ;
    PORT
      LAYER M4 ;
        RECT  0 8.592 0.192 8.616 ;
    END
  END o[61]
  PIN o[620]
    DIRECTION OUTPUT ;
    USE SIGNAL ;
    PORT
      LAYER M4 ;
        RECT  0 66.912 0.192 66.936 ;
    END
  END o[620]
  PIN o[621]
    DIRECTION OUTPUT ;
    USE SIGNAL ;
    PORT
      LAYER M4 ;
        RECT  0 67.056 0.192 67.08 ;
    END
  END o[621]
  PIN o[622]
    DIRECTION OUTPUT ;
    USE SIGNAL ;
    PORT
      LAYER M4 ;
        RECT  0 67.152 0.192 67.176 ;
    END
  END o[622]
  PIN o[623]
    DIRECTION OUTPUT ;
    USE SIGNAL ;
    PORT
      LAYER M4 ;
        RECT  0 67.248 0.192 67.272 ;
    END
  END o[623]
  PIN o[624]
    DIRECTION OUTPUT ;
    USE SIGNAL ;
    PORT
      LAYER M4 ;
        RECT  0 67.344 0.192 67.368 ;
    END
  END o[624]
  PIN o[625]
    DIRECTION OUTPUT ;
    USE SIGNAL ;
    PORT
      LAYER M4 ;
        RECT  0 67.44 0.192 67.464 ;
    END
  END o[625]
  PIN o[626]
    DIRECTION OUTPUT ;
    USE SIGNAL ;
    PORT
      LAYER M4 ;
        RECT  0 67.536 0.192 67.56 ;
    END
  END o[626]
  PIN o[627]
    DIRECTION OUTPUT ;
    USE SIGNAL ;
    PORT
      LAYER M4 ;
        RECT  0 67.68 0.192 67.704 ;
    END
  END o[627]
  PIN o[628]
    DIRECTION OUTPUT ;
    USE SIGNAL ;
    PORT
      LAYER M4 ;
        RECT  0 67.776 0.192 67.8 ;
    END
  END o[628]
  PIN o[629]
    DIRECTION OUTPUT ;
    USE SIGNAL ;
    PORT
      LAYER M4 ;
        RECT  0 67.872 0.192 67.896 ;
    END
  END o[629]
  PIN o[62]
    DIRECTION OUTPUT ;
    USE SIGNAL ;
    PORT
      LAYER M4 ;
        RECT  0 8.688 0.192 8.712 ;
    END
  END o[62]
  PIN o[630]
    DIRECTION OUTPUT ;
    USE SIGNAL ;
    PORT
      LAYER M4 ;
        RECT  0 67.968 0.192 67.992 ;
    END
  END o[630]
  PIN o[631]
    DIRECTION OUTPUT ;
    USE SIGNAL ;
    PORT
      LAYER M4 ;
        RECT  0 68.064 0.192 68.088 ;
    END
  END o[631]
  PIN o[632]
    DIRECTION OUTPUT ;
    USE SIGNAL ;
    PORT
      LAYER M4 ;
        RECT  0 68.16 0.192 68.184 ;
    END
  END o[632]
  PIN o[633]
    DIRECTION OUTPUT ;
    USE SIGNAL ;
    PORT
      LAYER M4 ;
        RECT  0 68.304 0.192 68.328 ;
    END
  END o[633]
  PIN o[634]
    DIRECTION OUTPUT ;
    USE SIGNAL ;
    PORT
      LAYER M4 ;
        RECT  0 68.4 0.192 68.424 ;
    END
  END o[634]
  PIN o[635]
    DIRECTION OUTPUT ;
    USE SIGNAL ;
    PORT
      LAYER M4 ;
        RECT  0 68.496 0.192 68.52 ;
    END
  END o[635]
  PIN o[636]
    DIRECTION OUTPUT ;
    USE SIGNAL ;
    PORT
      LAYER M4 ;
        RECT  0 68.592 0.192 68.616 ;
    END
  END o[636]
  PIN o[637]
    DIRECTION OUTPUT ;
    USE SIGNAL ;
    PORT
      LAYER M4 ;
        RECT  0 68.688 0.192 68.712 ;
    END
  END o[637]
  PIN o[638]
    DIRECTION OUTPUT ;
    USE SIGNAL ;
    PORT
      LAYER M4 ;
        RECT  0 68.784 0.192 68.808 ;
    END
  END o[638]
  PIN o[639]
    DIRECTION OUTPUT ;
    USE SIGNAL ;
    PORT
      LAYER M4 ;
        RECT  0 68.928 0.192 68.952 ;
    END
  END o[639]
  PIN o[63]
    DIRECTION OUTPUT ;
    USE SIGNAL ;
    PORT
      LAYER M4 ;
        RECT  0 8.784 0.192 8.808 ;
    END
  END o[63]
  PIN o[640]
    DIRECTION OUTPUT ;
    USE SIGNAL ;
    PORT
      LAYER M4 ;
        RECT  0 69.024 0.192 69.048 ;
    END
  END o[640]
  PIN o[641]
    DIRECTION OUTPUT ;
    USE SIGNAL ;
    PORT
      LAYER M4 ;
        RECT  0 69.12 0.192 69.144 ;
    END
  END o[641]
  PIN o[642]
    DIRECTION OUTPUT ;
    USE SIGNAL ;
    PORT
      LAYER M4 ;
        RECT  0 69.216 0.192 69.24 ;
    END
  END o[642]
  PIN o[643]
    DIRECTION OUTPUT ;
    USE SIGNAL ;
    PORT
      LAYER M4 ;
        RECT  0 69.312 0.192 69.336 ;
    END
  END o[643]
  PIN o[644]
    DIRECTION OUTPUT ;
    USE SIGNAL ;
    PORT
      LAYER M4 ;
        RECT  0 69.456 0.192 69.48 ;
    END
  END o[644]
  PIN o[645]
    DIRECTION OUTPUT ;
    USE SIGNAL ;
    PORT
      LAYER M4 ;
        RECT  0 69.552 0.192 69.576 ;
    END
  END o[645]
  PIN o[646]
    DIRECTION OUTPUT ;
    USE SIGNAL ;
    PORT
      LAYER M4 ;
        RECT  0 69.648 0.192 69.672 ;
    END
  END o[646]
  PIN o[647]
    DIRECTION OUTPUT ;
    USE SIGNAL ;
    PORT
      LAYER M4 ;
        RECT  0 69.744 0.192 69.768 ;
    END
  END o[647]
  PIN o[648]
    DIRECTION OUTPUT ;
    USE SIGNAL ;
    PORT
      LAYER M4 ;
        RECT  0 69.84 0.192 69.864 ;
    END
  END o[648]
  PIN o[649]
    DIRECTION OUTPUT ;
    USE SIGNAL ;
    PORT
      LAYER M4 ;
        RECT  0 69.936 0.192 69.96 ;
    END
  END o[649]
  PIN o[64]
    DIRECTION OUTPUT ;
    USE SIGNAL ;
    PORT
      LAYER M4 ;
        RECT  0 8.88 0.192 8.904 ;
    END
  END o[64]
  PIN o[650]
    DIRECTION OUTPUT ;
    USE SIGNAL ;
    PORT
      LAYER M4 ;
        RECT  0 70.08 0.192 70.104 ;
    END
  END o[650]
  PIN o[651]
    DIRECTION OUTPUT ;
    USE SIGNAL ;
    PORT
      LAYER M4 ;
        RECT  0 70.176 0.192 70.2 ;
    END
  END o[651]
  PIN o[652]
    DIRECTION OUTPUT ;
    USE SIGNAL ;
    PORT
      LAYER M4 ;
        RECT  0 70.272 0.192 70.296 ;
    END
  END o[652]
  PIN o[653]
    DIRECTION OUTPUT ;
    USE SIGNAL ;
    PORT
      LAYER M4 ;
        RECT  0 70.368 0.192 70.392 ;
    END
  END o[653]
  PIN o[654]
    DIRECTION OUTPUT ;
    USE SIGNAL ;
    PORT
      LAYER M4 ;
        RECT  0 70.464 0.192 70.488 ;
    END
  END o[654]
  PIN o[655]
    DIRECTION OUTPUT ;
    USE SIGNAL ;
    PORT
      LAYER M4 ;
        RECT  0 70.56 0.192 70.584 ;
    END
  END o[655]
  PIN o[656]
    DIRECTION OUTPUT ;
    USE SIGNAL ;
    PORT
      LAYER M4 ;
        RECT  0 70.704 0.192 70.728 ;
    END
  END o[656]
  PIN o[657]
    DIRECTION OUTPUT ;
    USE SIGNAL ;
    PORT
      LAYER M4 ;
        RECT  0 70.8 0.192 70.824 ;
    END
  END o[657]
  PIN o[658]
    DIRECTION OUTPUT ;
    USE SIGNAL ;
    PORT
      LAYER M4 ;
        RECT  0 70.896 0.192 70.92 ;
    END
  END o[658]
  PIN o[659]
    DIRECTION OUTPUT ;
    USE SIGNAL ;
    PORT
      LAYER M4 ;
        RECT  0 70.992 0.192 71.016 ;
    END
  END o[659]
  PIN o[65]
    DIRECTION OUTPUT ;
    USE SIGNAL ;
    PORT
      LAYER M4 ;
        RECT  0 9.024 0.192 9.048 ;
    END
  END o[65]
  PIN o[660]
    DIRECTION OUTPUT ;
    USE SIGNAL ;
    PORT
      LAYER M4 ;
        RECT  0 71.088 0.192 71.112 ;
    END
  END o[660]
  PIN o[661]
    DIRECTION OUTPUT ;
    USE SIGNAL ;
    PORT
      LAYER M4 ;
        RECT  0 71.232 0.192 71.256 ;
    END
  END o[661]
  PIN o[662]
    DIRECTION OUTPUT ;
    USE SIGNAL ;
    PORT
      LAYER M4 ;
        RECT  0 71.328 0.192 71.352 ;
    END
  END o[662]
  PIN o[663]
    DIRECTION OUTPUT ;
    USE SIGNAL ;
    PORT
      LAYER M4 ;
        RECT  0 71.424 0.192 71.448 ;
    END
  END o[663]
  PIN o[664]
    DIRECTION OUTPUT ;
    USE SIGNAL ;
    PORT
      LAYER M4 ;
        RECT  0 71.52 0.192 71.544 ;
    END
  END o[664]
  PIN o[665]
    DIRECTION OUTPUT ;
    USE SIGNAL ;
    PORT
      LAYER M4 ;
        RECT  0 71.616 0.192 71.64 ;
    END
  END o[665]
  PIN o[666]
    DIRECTION OUTPUT ;
    USE SIGNAL ;
    PORT
      LAYER M4 ;
        RECT  0 71.712 0.192 71.736 ;
    END
  END o[666]
  PIN o[667]
    DIRECTION OUTPUT ;
    USE SIGNAL ;
    PORT
      LAYER M4 ;
        RECT  0 71.856 0.192 71.88 ;
    END
  END o[667]
  PIN o[668]
    DIRECTION OUTPUT ;
    USE SIGNAL ;
    PORT
      LAYER M4 ;
        RECT  0 71.952 0.192 71.976 ;
    END
  END o[668]
  PIN o[669]
    DIRECTION OUTPUT ;
    USE SIGNAL ;
    PORT
      LAYER M4 ;
        RECT  0 72.048 0.192 72.072 ;
    END
  END o[669]
  PIN o[66]
    DIRECTION OUTPUT ;
    USE SIGNAL ;
    PORT
      LAYER M4 ;
        RECT  0 9.12 0.192 9.144 ;
    END
  END o[66]
  PIN o[670]
    DIRECTION OUTPUT ;
    USE SIGNAL ;
    PORT
      LAYER M4 ;
        RECT  0 72.144 0.192 72.168 ;
    END
  END o[670]
  PIN o[671]
    DIRECTION OUTPUT ;
    USE SIGNAL ;
    PORT
      LAYER M4 ;
        RECT  0 72.24 0.192 72.264 ;
    END
  END o[671]
  PIN o[672]
    DIRECTION OUTPUT ;
    USE SIGNAL ;
    PORT
      LAYER M4 ;
        RECT  0 72.336 0.192 72.36 ;
    END
  END o[672]
  PIN o[673]
    DIRECTION OUTPUT ;
    USE SIGNAL ;
    PORT
      LAYER M4 ;
        RECT  0 72.48 0.192 72.504 ;
    END
  END o[673]
  PIN o[674]
    DIRECTION OUTPUT ;
    USE SIGNAL ;
    PORT
      LAYER M4 ;
        RECT  0 72.576 0.192 72.6 ;
    END
  END o[674]
  PIN o[675]
    DIRECTION OUTPUT ;
    USE SIGNAL ;
    PORT
      LAYER M4 ;
        RECT  0 72.672 0.192 72.696 ;
    END
  END o[675]
  PIN o[676]
    DIRECTION OUTPUT ;
    USE SIGNAL ;
    PORT
      LAYER M4 ;
        RECT  0 72.768 0.192 72.792 ;
    END
  END o[676]
  PIN o[677]
    DIRECTION OUTPUT ;
    USE SIGNAL ;
    PORT
      LAYER M4 ;
        RECT  0 72.864 0.192 72.888 ;
    END
  END o[677]
  PIN o[678]
    DIRECTION OUTPUT ;
    USE SIGNAL ;
    PORT
      LAYER M4 ;
        RECT  0 72.96 0.192 72.984 ;
    END
  END o[678]
  PIN o[679]
    DIRECTION OUTPUT ;
    USE SIGNAL ;
    PORT
      LAYER M4 ;
        RECT  0 73.104 0.192 73.128 ;
    END
  END o[679]
  PIN o[67]
    DIRECTION OUTPUT ;
    USE SIGNAL ;
    PORT
      LAYER M4 ;
        RECT  0 9.216 0.192 9.24 ;
    END
  END o[67]
  PIN o[680]
    DIRECTION OUTPUT ;
    USE SIGNAL ;
    PORT
      LAYER M4 ;
        RECT  0 73.2 0.192 73.224 ;
    END
  END o[680]
  PIN o[681]
    DIRECTION OUTPUT ;
    USE SIGNAL ;
    PORT
      LAYER M4 ;
        RECT  0 73.296 0.192 73.32 ;
    END
  END o[681]
  PIN o[68]
    DIRECTION OUTPUT ;
    USE SIGNAL ;
    PORT
      LAYER M4 ;
        RECT  0 9.312 0.192 9.336 ;
    END
  END o[68]
  PIN o[69]
    DIRECTION OUTPUT ;
    USE SIGNAL ;
    PORT
      LAYER M4 ;
        RECT  0 9.408 0.192 9.432 ;
    END
  END o[69]
  PIN o[6]
    DIRECTION OUTPUT ;
    USE SIGNAL ;
    PORT
      LAYER M4 ;
        RECT  0 2.832 0.192 2.856 ;
    END
  END o[6]
  PIN o[70]
    DIRECTION OUTPUT ;
    USE SIGNAL ;
    PORT
      LAYER M4 ;
        RECT  0 9.552 0.192 9.576 ;
    END
  END o[70]
  PIN o[71]
    DIRECTION OUTPUT ;
    USE SIGNAL ;
    PORT
      LAYER M4 ;
        RECT  0 9.648 0.192 9.672 ;
    END
  END o[71]
  PIN o[72]
    DIRECTION OUTPUT ;
    USE SIGNAL ;
    PORT
      LAYER M4 ;
        RECT  0 9.744 0.192 9.768 ;
    END
  END o[72]
  PIN o[73]
    DIRECTION OUTPUT ;
    USE SIGNAL ;
    PORT
      LAYER M4 ;
        RECT  0 9.84 0.192 9.864 ;
    END
  END o[73]
  PIN o[74]
    DIRECTION OUTPUT ;
    USE SIGNAL ;
    PORT
      LAYER M4 ;
        RECT  0 9.936 0.192 9.96 ;
    END
  END o[74]
  PIN o[75]
    DIRECTION OUTPUT ;
    USE SIGNAL ;
    PORT
      LAYER M4 ;
        RECT  0 10.032 0.192 10.056 ;
    END
  END o[75]
  PIN o[76]
    DIRECTION OUTPUT ;
    USE SIGNAL ;
    PORT
      LAYER M4 ;
        RECT  0 10.176 0.192 10.2 ;
    END
  END o[76]
  PIN o[77]
    DIRECTION OUTPUT ;
    USE SIGNAL ;
    PORT
      LAYER M4 ;
        RECT  0 10.272 0.192 10.296 ;
    END
  END o[77]
  PIN o[78]
    DIRECTION OUTPUT ;
    USE SIGNAL ;
    PORT
      LAYER M4 ;
        RECT  0 10.368 0.192 10.392 ;
    END
  END o[78]
  PIN o[79]
    DIRECTION OUTPUT ;
    USE SIGNAL ;
    PORT
      LAYER M4 ;
        RECT  0 10.464 0.192 10.488 ;
    END
  END o[79]
  PIN o[7]
    DIRECTION OUTPUT ;
    USE SIGNAL ;
    PORT
      LAYER M4 ;
        RECT  0 2.976 0.192 3 ;
    END
  END o[7]
  PIN o[80]
    DIRECTION OUTPUT ;
    USE SIGNAL ;
    PORT
      LAYER M4 ;
        RECT  0 10.56 0.192 10.584 ;
    END
  END o[80]
  PIN o[81]
    DIRECTION OUTPUT ;
    USE SIGNAL ;
    PORT
      LAYER M4 ;
        RECT  0 10.656 0.192 10.68 ;
    END
  END o[81]
  PIN o[82]
    DIRECTION OUTPUT ;
    USE SIGNAL ;
    PORT
      LAYER M4 ;
        RECT  0 10.8 0.192 10.824 ;
    END
  END o[82]
  PIN o[83]
    DIRECTION OUTPUT ;
    USE SIGNAL ;
    PORT
      LAYER M4 ;
        RECT  0 10.896 0.192 10.92 ;
    END
  END o[83]
  PIN o[84]
    DIRECTION OUTPUT ;
    USE SIGNAL ;
    PORT
      LAYER M4 ;
        RECT  0 10.992 0.192 11.016 ;
    END
  END o[84]
  PIN o[85]
    DIRECTION OUTPUT ;
    USE SIGNAL ;
    PORT
      LAYER M4 ;
        RECT  0 11.088 0.192 11.112 ;
    END
  END o[85]
  PIN o[86]
    DIRECTION OUTPUT ;
    USE SIGNAL ;
    PORT
      LAYER M4 ;
        RECT  0 11.184 0.192 11.208 ;
    END
  END o[86]
  PIN o[87]
    DIRECTION OUTPUT ;
    USE SIGNAL ;
    PORT
      LAYER M4 ;
        RECT  0 11.28 0.192 11.304 ;
    END
  END o[87]
  PIN o[88]
    DIRECTION OUTPUT ;
    USE SIGNAL ;
    PORT
      LAYER M4 ;
        RECT  0 11.424 0.192 11.448 ;
    END
  END o[88]
  PIN o[89]
    DIRECTION OUTPUT ;
    USE SIGNAL ;
    PORT
      LAYER M4 ;
        RECT  0 11.52 0.192 11.544 ;
    END
  END o[89]
  PIN o[8]
    DIRECTION OUTPUT ;
    USE SIGNAL ;
    PORT
      LAYER M4 ;
        RECT  0 3.072 0.192 3.096 ;
    END
  END o[8]
  PIN o[90]
    DIRECTION OUTPUT ;
    USE SIGNAL ;
    PORT
      LAYER M4 ;
        RECT  0 11.616 0.192 11.64 ;
    END
  END o[90]
  PIN o[91]
    DIRECTION OUTPUT ;
    USE SIGNAL ;
    PORT
      LAYER M4 ;
        RECT  0 11.712 0.192 11.736 ;
    END
  END o[91]
  PIN o[92]
    DIRECTION OUTPUT ;
    USE SIGNAL ;
    PORT
      LAYER M4 ;
        RECT  0 11.808 0.192 11.832 ;
    END
  END o[92]
  PIN o[93]
    DIRECTION OUTPUT ;
    USE SIGNAL ;
    PORT
      LAYER M4 ;
        RECT  0 11.952 0.192 11.976 ;
    END
  END o[93]
  PIN o[94]
    DIRECTION OUTPUT ;
    USE SIGNAL ;
    PORT
      LAYER M4 ;
        RECT  0 12.048 0.192 12.072 ;
    END
  END o[94]
  PIN o[95]
    DIRECTION OUTPUT ;
    USE SIGNAL ;
    PORT
      LAYER M4 ;
        RECT  0 12.144 0.192 12.168 ;
    END
  END o[95]
  PIN o[96]
    DIRECTION OUTPUT ;
    USE SIGNAL ;
    PORT
      LAYER M4 ;
        RECT  0 12.24 0.192 12.264 ;
    END
  END o[96]
  PIN o[97]
    DIRECTION OUTPUT ;
    USE SIGNAL ;
    PORT
      LAYER M4 ;
        RECT  0 12.336 0.192 12.36 ;
    END
  END o[97]
  PIN o[98]
    DIRECTION OUTPUT ;
    USE SIGNAL ;
    PORT
      LAYER M4 ;
        RECT  0 12.432 0.192 12.456 ;
    END
  END o[98]
  PIN o[99]
    DIRECTION OUTPUT ;
    USE SIGNAL ;
    PORT
      LAYER M4 ;
        RECT  0 12.576 0.192 12.6 ;
    END
  END o[99]
  PIN o[9]
    DIRECTION OUTPUT ;
    USE SIGNAL ;
    PORT
      LAYER M4 ;
        RECT  0 3.168 0.192 3.192 ;
    END
  END o[9]
  PIN rs
    DIRECTION INPUT ;
    USE SIGNAL ;
    PORT
      LAYER M5 ;
        RECT  11.856 75.408 11.88 75.6 ;
    END
    PORT
      LAYER M5 ;
        RECT  11.856 73.237 11.88 75.472 ;
    END
  END rs
  PIN VDD
    DIRECTION INOUT ;
    USE POWER ;
    PORT
      LAYER M5 ;
        RECT  13.392 2.151 13.512 73.449 ;
        RECT  10.692 2.151 10.812 73.449 ;
        RECT  7.992 2.151 8.112 73.449 ;
        RECT  5.292 2.151 5.412 73.449 ;
        RECT  2.592 2.151 2.712 73.449 ;
    END
  END VDD
  PIN VSS
    DIRECTION INOUT ;
    USE GROUND ;
    PORT
      LAYER M5 ;
        RECT  13.2 2.137 13.32 73.463 ;
        RECT  10.5 2.137 10.62 73.463 ;
        RECT  7.8 2.137 7.92 73.463 ;
        RECT  5.1 2.137 5.22 73.463 ;
        RECT  2.4 2.137 2.52 73.463 ;
    END
  END VSS
  # OT_OBS_CLOSED layer=M5 d_um=1.536 added=100
  OBS
    LAYER RVTN ;
     RECT  2.16 2.16 15.12 2.295 ;
     RECT  2.16 2.565 15.12 2.835 ;
     RECT  2.16 3.105 15.12 3.375 ;
     RECT  2.16 3.645 15.12 3.915 ;
     RECT  2.16 4.185 15.12 4.455 ;
     RECT  2.16 4.725 15.12 4.995 ;
     RECT  2.16 5.265 15.12 5.535 ;
     RECT  2.16 5.805 15.12 6.075 ;
     RECT  2.16 6.345 15.12 6.615 ;
     RECT  2.16 6.885 15.12 7.155 ;
     RECT  2.16 7.425 15.12 7.695 ;
     RECT  2.16 7.965 15.12 8.235 ;
     RECT  2.16 8.505 15.12 8.775 ;
     RECT  2.16 9.045 15.12 9.315 ;
     RECT  2.16 9.585 15.12 9.855 ;
     RECT  2.16 10.125 15.12 10.395 ;
     RECT  2.16 10.665 15.12 10.935 ;
     RECT  2.16 11.205 15.12 11.475 ;
     RECT  2.16 11.745 15.12 12.015 ;
     RECT  2.16 12.285 15.12 12.555 ;
     RECT  2.16 12.825 15.12 13.095 ;
     RECT  2.16 13.365 15.12 13.635 ;
     RECT  2.16 13.905 15.12 14.175 ;
     RECT  2.16 14.445 15.12 14.715 ;
     RECT  2.16 14.985 15.12 15.255 ;
     RECT  2.16 15.525 15.12 15.795 ;
     RECT  2.16 16.065 15.12 16.335 ;
     RECT  2.16 16.605 15.12 16.875 ;
     RECT  2.16 17.145 15.12 17.415 ;
     RECT  2.16 17.685 15.12 17.955 ;
     RECT  2.16 18.225 15.12 18.495 ;
     RECT  2.16 18.765 15.12 19.035 ;
     RECT  2.16 19.305 15.12 19.575 ;
     RECT  2.16 19.845 15.12 20.115 ;
     RECT  2.16 20.385 15.12 20.655 ;
     RECT  2.16 20.925 15.12 21.195 ;
     RECT  2.16 21.465 15.12 21.735 ;
     RECT  2.16 22.005 15.12 22.275 ;
     RECT  2.16 22.545 15.12 22.815 ;
     RECT  2.16 23.085 15.12 23.355 ;
     RECT  2.16 23.625 15.12 23.895 ;
     RECT  2.16 24.165 15.12 24.435 ;
     RECT  2.16 24.705 15.12 24.975 ;
     RECT  2.16 25.245 15.12 25.515 ;
     RECT  2.16 25.785 15.12 26.055 ;
     RECT  2.16 26.325 15.12 26.595 ;
     RECT  2.16 26.865 15.12 27.135 ;
     RECT  2.16 27.405 15.12 27.675 ;
     RECT  2.16 27.945 15.12 28.215 ;
     RECT  2.16 28.485 15.12 28.755 ;
     RECT  2.16 29.025 15.12 29.295 ;
     RECT  2.16 29.565 15.12 29.835 ;
     RECT  2.16 30.105 15.12 30.375 ;
     RECT  2.16 30.645 15.12 30.915 ;
     RECT  2.16 31.185 15.12 31.455 ;
     RECT  2.16 31.725 15.12 31.995 ;
     RECT  2.16 32.265 15.12 32.535 ;
     RECT  2.16 32.805 15.12 33.075 ;
     RECT  2.16 33.345 15.12 33.615 ;
     RECT  2.16 33.885 15.12 34.155 ;
     RECT  2.16 34.425 15.12 34.695 ;
     RECT  2.16 34.965 15.12 35.235 ;
     RECT  2.16 35.505 15.12 35.775 ;
     RECT  2.16 36.045 15.12 36.315 ;
     RECT  2.16 36.585 15.12 36.855 ;
     RECT  2.16 37.125 15.12 37.395 ;
     RECT  2.16 37.665 15.12 37.935 ;
     RECT  2.16 38.205 15.12 38.475 ;
     RECT  2.16 38.745 15.12 39.015 ;
     RECT  2.16 39.285 15.12 39.555 ;
     RECT  2.16 39.825 15.12 40.095 ;
     RECT  2.16 40.365 15.12 40.635 ;
     RECT  2.16 40.905 15.12 41.175 ;
     RECT  2.16 41.445 15.12 41.715 ;
     RECT  2.16 41.985 15.12 42.255 ;
     RECT  2.16 42.525 15.12 42.795 ;
     RECT  2.16 43.065 15.12 43.335 ;
     RECT  2.16 43.605 15.12 43.875 ;
     RECT  2.16 44.145 15.12 44.415 ;
     RECT  2.16 44.685 15.12 44.955 ;
     RECT  2.16 45.225 15.12 45.495 ;
     RECT  2.16 45.765 15.12 46.035 ;
     RECT  2.16 46.305 15.12 46.575 ;
     RECT  2.16 46.845 15.12 47.115 ;
     RECT  2.16 47.385 15.12 47.655 ;
     RECT  2.16 47.925 15.12 48.195 ;
     RECT  2.16 48.465 15.12 48.735 ;
     RECT  2.16 49.005 15.12 49.275 ;
     RECT  2.16 49.545 15.12 49.815 ;
     RECT  2.16 50.085 15.12 50.355 ;
     RECT  2.16 50.625 15.12 50.895 ;
     RECT  2.16 51.165 15.12 51.435 ;
     RECT  2.16 51.705 15.12 51.975 ;
     RECT  2.16 52.245 15.12 52.515 ;
     RECT  2.16 52.785 15.12 53.055 ;
     RECT  2.16 53.325 15.12 53.595 ;
     RECT  2.16 53.865 15.12 54.135 ;
     RECT  2.16 54.405 15.12 54.675 ;
     RECT  2.16 54.945 15.12 55.215 ;
     RECT  2.16 55.485 15.12 55.755 ;
     RECT  2.16 56.025 15.12 56.295 ;
     RECT  2.16 56.565 15.12 56.835 ;
     RECT  2.16 57.105 15.12 57.375 ;
     RECT  2.16 57.645 15.12 57.915 ;
     RECT  2.16 58.185 15.12 58.455 ;
     RECT  2.16 58.725 15.12 58.995 ;
     RECT  2.16 59.265 15.12 59.535 ;
     RECT  2.16 59.805 15.12 60.075 ;
     RECT  2.16 60.345 15.12 60.615 ;
     RECT  2.16 60.885 15.12 61.155 ;
     RECT  2.16 61.425 15.12 61.695 ;
     RECT  2.16 61.965 15.12 62.235 ;
     RECT  2.16 62.505 15.12 62.775 ;
     RECT  2.16 63.045 15.12 63.315 ;
     RECT  2.16 63.585 15.12 63.855 ;
     RECT  2.16 64.125 15.12 64.395 ;
     RECT  2.16 64.665 15.12 64.935 ;
     RECT  2.16 65.205 15.12 65.475 ;
     RECT  2.16 65.745 15.12 66.015 ;
     RECT  2.16 66.285 15.12 66.555 ;
     RECT  2.16 66.825 15.12 67.095 ;
     RECT  2.16 67.365 15.12 67.635 ;
     RECT  2.16 67.905 15.12 68.175 ;
     RECT  2.16 68.445 15.12 68.715 ;
     RECT  2.16 68.985 15.12 69.255 ;
     RECT  2.16 69.525 15.12 69.795 ;
     RECT  2.16 70.065 15.12 70.335 ;
     RECT  2.16 70.605 15.12 70.875 ;
     RECT  2.16 71.145 15.12 71.415 ;
     RECT  2.16 71.685 15.12 71.955 ;
     RECT  2.16 72.225 15.12 72.495 ;
     RECT  2.16 72.765 15.12 73.035 ;
     RECT  2.16 73.305 15.12 73.44 ;
    LAYER RVTP ;
     RECT  2.16 2.295 15.12 2.565 ;
     RECT  2.16 2.835 15.12 3.105 ;
     RECT  2.16 3.375 15.12 3.645 ;
     RECT  2.16 3.915 15.12 4.185 ;
     RECT  2.16 4.455 15.12 4.725 ;
     RECT  2.16 4.995 15.12 5.265 ;
     RECT  2.16 5.535 15.12 5.805 ;
     RECT  2.16 6.075 15.12 6.345 ;
     RECT  2.16 6.615 15.12 6.885 ;
     RECT  2.16 7.155 15.12 7.425 ;
     RECT  2.16 7.695 15.12 7.965 ;
     RECT  2.16 8.235 15.12 8.505 ;
     RECT  2.16 8.775 15.12 9.045 ;
     RECT  2.16 9.315 15.12 9.585 ;
     RECT  2.16 9.855 15.12 10.125 ;
     RECT  2.16 10.395 15.12 10.665 ;
     RECT  2.16 10.935 15.12 11.205 ;
     RECT  2.16 11.475 15.12 11.745 ;
     RECT  2.16 12.015 15.12 12.285 ;
     RECT  2.16 12.555 15.12 12.825 ;
     RECT  2.16 13.095 15.12 13.365 ;
     RECT  2.16 13.635 15.12 13.905 ;
     RECT  2.16 14.175 15.12 14.445 ;
     RECT  2.16 14.715 15.12 14.985 ;
     RECT  2.16 15.255 15.12 15.525 ;
     RECT  2.16 15.795 15.12 16.065 ;
     RECT  2.16 16.335 15.12 16.605 ;
     RECT  2.16 16.875 15.12 17.145 ;
     RECT  2.16 17.415 15.12 17.685 ;
     RECT  2.16 17.955 15.12 18.225 ;
     RECT  2.16 18.495 15.12 18.765 ;
     RECT  2.16 19.035 15.12 19.305 ;
     RECT  2.16 19.575 15.12 19.845 ;
     RECT  2.16 20.115 15.12 20.385 ;
     RECT  2.16 20.655 15.12 20.925 ;
     RECT  2.16 21.195 15.12 21.465 ;
     RECT  2.16 21.735 15.12 22.005 ;
     RECT  2.16 22.275 15.12 22.545 ;
     RECT  2.16 22.815 15.12 23.085 ;
     RECT  2.16 23.355 15.12 23.625 ;
     RECT  2.16 23.895 15.12 24.165 ;
     RECT  2.16 24.435 15.12 24.705 ;
     RECT  2.16 24.975 15.12 25.245 ;
     RECT  2.16 25.515 15.12 25.785 ;
     RECT  2.16 26.055 15.12 26.325 ;
     RECT  2.16 26.595 15.12 26.865 ;
     RECT  2.16 27.135 15.12 27.405 ;
     RECT  2.16 27.675 15.12 27.945 ;
     RECT  2.16 28.215 15.12 28.485 ;
     RECT  2.16 28.755 15.12 29.025 ;
     RECT  2.16 29.295 15.12 29.565 ;
     RECT  2.16 29.835 15.12 30.105 ;
     RECT  2.16 30.375 15.12 30.645 ;
     RECT  2.16 30.915 15.12 31.185 ;
     RECT  2.16 31.455 15.12 31.725 ;
     RECT  2.16 31.995 15.12 32.265 ;
     RECT  2.16 32.535 15.12 32.805 ;
     RECT  2.16 33.075 15.12 33.345 ;
     RECT  2.16 33.615 15.12 33.885 ;
     RECT  2.16 34.155 15.12 34.425 ;
     RECT  2.16 34.695 15.12 34.965 ;
     RECT  2.16 35.235 15.12 35.505 ;
     RECT  2.16 35.775 15.12 36.045 ;
     RECT  2.16 36.315 15.12 36.585 ;
     RECT  2.16 36.855 15.12 37.125 ;
     RECT  2.16 37.395 15.12 37.665 ;
     RECT  2.16 37.935 15.12 38.205 ;
     RECT  2.16 38.475 15.12 38.745 ;
     RECT  2.16 39.015 15.12 39.285 ;
     RECT  2.16 39.555 15.12 39.825 ;
     RECT  2.16 40.095 15.12 40.365 ;
     RECT  2.16 40.635 15.12 40.905 ;
     RECT  2.16 41.175 15.12 41.445 ;
     RECT  2.16 41.715 15.12 41.985 ;
     RECT  2.16 42.255 15.12 42.525 ;
     RECT  2.16 42.795 15.12 43.065 ;
     RECT  2.16 43.335 15.12 43.605 ;
     RECT  2.16 43.875 15.12 44.145 ;
     RECT  2.16 44.415 15.12 44.685 ;
     RECT  2.16 44.955 15.12 45.225 ;
     RECT  2.16 45.495 15.12 45.765 ;
     RECT  2.16 46.035 15.12 46.305 ;
     RECT  2.16 46.575 15.12 46.845 ;
     RECT  2.16 47.115 15.12 47.385 ;
     RECT  2.16 47.655 15.12 47.925 ;
     RECT  2.16 48.195 15.12 48.465 ;
     RECT  2.16 48.735 15.12 49.005 ;
     RECT  2.16 49.275 15.12 49.545 ;
     RECT  2.16 49.815 15.12 50.085 ;
     RECT  2.16 50.355 15.12 50.625 ;
     RECT  2.16 50.895 15.12 51.165 ;
     RECT  2.16 51.435 15.12 51.705 ;
     RECT  2.16 51.975 15.12 52.245 ;
     RECT  2.16 52.515 15.12 52.785 ;
     RECT  2.16 53.055 15.12 53.325 ;
     RECT  2.16 53.595 15.12 53.865 ;
     RECT  2.16 54.135 15.12 54.405 ;
     RECT  2.16 54.675 15.12 54.945 ;
     RECT  2.16 55.215 15.12 55.485 ;
     RECT  2.16 55.755 15.12 56.025 ;
     RECT  2.16 56.295 15.12 56.565 ;
     RECT  2.16 56.835 15.12 57.105 ;
     RECT  2.16 57.375 15.12 57.645 ;
     RECT  2.16 57.915 15.12 58.185 ;
     RECT  2.16 58.455 15.12 58.725 ;
     RECT  2.16 58.995 15.12 59.265 ;
     RECT  2.16 59.535 15.12 59.805 ;
     RECT  2.16 60.075 15.12 60.345 ;
     RECT  2.16 60.615 15.12 60.885 ;
     RECT  2.16 61.155 15.12 61.425 ;
     RECT  2.16 61.695 15.12 61.965 ;
     RECT  2.16 62.235 15.12 62.505 ;
     RECT  2.16 62.775 15.12 63.045 ;
     RECT  2.16 63.315 15.12 63.585 ;
     RECT  2.16 63.855 15.12 64.125 ;
     RECT  2.16 64.395 15.12 64.665 ;
     RECT  2.16 64.935 15.12 65.205 ;
     RECT  2.16 65.475 15.12 65.745 ;
     RECT  2.16 66.015 15.12 66.285 ;
     RECT  2.16 66.555 15.12 66.825 ;
     RECT  2.16 67.095 15.12 67.365 ;
     RECT  2.16 67.635 15.12 67.905 ;
     RECT  2.16 68.175 15.12 68.445 ;
     RECT  2.16 68.715 15.12 68.985 ;
     RECT  2.16 69.255 15.12 69.525 ;
     RECT  2.16 69.795 15.12 70.065 ;
     RECT  2.16 70.335 15.12 70.605 ;
     RECT  2.16 70.875 15.12 71.145 ;
     RECT  2.16 71.415 15.12 71.685 ;
     RECT  2.16 71.955 15.12 72.225 ;
     RECT  2.16 72.495 15.12 72.765 ;
     RECT  2.16 73.035 15.12 73.305 ;
    LAYER M1 ;
     RECT  2.16 2.151 15.12 73.449 ;
    LAYER M2 ;
     RECT  0.211 7.866 0.311 8.064 ;
     RECT  0.211 14.958 0.311 14.976 ;
     RECT  0.211 18.666 0.311 18.684 ;
     RECT  0.211 26.496 0.311 26.514 ;
     RECT  0.211 33.084 0.311 33.102 ;
     RECT  0.211 72.936 0.311 73.332 ;
     RECT  0.311 73.314 0.347 73.332 ;
     RECT  0.283 20.286 0.383 20.304 ;
     RECT  0.319 59.076 0.419 59.094 ;
     RECT  0.211 17.046 0.535 17.064 ;
     RECT  0.499 21.438 0.535 21.834 ;
     RECT  0.499 33.318 0.535 33.336 ;
     RECT  0.211 37.026 0.535 37.044 ;
     RECT  0.211 42.606 0.535 42.624 ;
     RECT  0.535 63.252 0.571 63.27 ;
     RECT  0.535 21.366 0.635 22.914 ;
     RECT  0.535 52.182 0.635 52.614 ;
     RECT  0.535 28.386 1.147 28.404 ;
     RECT  0.535 32.076 1.147 32.094 ;
     RECT  0.635 22.824 1.175 22.914 ;
     RECT  1.147 28.386 1.175 28.476 ;
     RECT  1.147 32.004 1.175 32.094 ;
     RECT  0.535 33.318 1.175 33.606 ;
     RECT  1.147 40.338 1.283 40.464 ;
     RECT  0.535 6.048 2.16 6.066 ;
     RECT  0.311 7.866 2.16 7.884 ;
     RECT  2.047 9.9 2.16 9.918 ;
     RECT  0.535 11.718 2.16 11.736 ;
     RECT  0.535 12.528 2.16 12.546 ;
     RECT  0.535 16.506 2.16 17.064 ;
     RECT  0.635 21.366 2.16 21.996 ;
     RECT  1.175 22.824 2.16 22.842 ;
     RECT  0.535 26.64 2.16 26.658 ;
     RECT  1.175 28.458 2.16 28.476 ;
     RECT  1.175 32.004 2.16 32.022 ;
     RECT  1.175 33.39 2.16 33.606 ;
     RECT  0.535 37.026 2.16 38.124 ;
     RECT  1.283 40.446 2.16 40.464 ;
     RECT  0.535 42.03 2.16 42.624 ;
     RECT  0.535 45.504 2.16 45.522 ;
     RECT  0.535 47.286 2.16 47.304 ;
     RECT  0.635 52.182 2.16 52.2 ;
     RECT  0.535 57.186 2.16 57.204 ;
     RECT  0.535 58.626 2.16 58.644 ;
     RECT  0.571 63.216 2.16 63.27 ;
     RECT  0.535 64.296 2.16 64.314 ;
     RECT  0.535 65.448 2.16 65.466 ;
     RECT  0.535 67.806 2.16 68.364 ;
     RECT  0.535 69.498 2.16 69.516 ;
     RECT  2.16 2.151 4.243 73.449 ;
     RECT  4.243 2.034 4.279 73.449 ;
     RECT  4.279 2.034 6.835 73.494 ;
     RECT  6.835 1.962 6.907 73.494 ;
     RECT  6.907 1.962 8.159 73.53 ;
     RECT  8.159 2.106 9.031 73.53 ;
     RECT  9.031 2.07 14.171 73.53 ;
     RECT  14.171 2.07 15.12 73.449 ;
     RECT  15.12 5.58 15.431 31.482 ;
     RECT  15.12 32.238 15.431 33.606 ;
     RECT  15.12 34.668 15.431 36.378 ;
     RECT  15.12 37.134 15.431 39.312 ;
     RECT  15.12 46.584 15.431 48.456 ;
     RECT  15.12 49.284 15.431 70.596 ;
     RECT  15.12 71.424 15.431 73.296 ;
     RECT  15.12 2.07 15.467 4.716 ;
     RECT  15.431 5.58 15.467 6.444 ;
     RECT  15.431 9.558 15.467 11.196 ;
     RECT  15.431 23.67 15.467 26.892 ;
     RECT  15.431 27.72 15.467 27.936 ;
     RECT  15.431 28.998 15.467 31.482 ;
     RECT  15.431 33.156 15.467 33.336 ;
     RECT  15.431 34.74 15.467 35.604 ;
     RECT  15.431 38.988 15.467 39.312 ;
     RECT  15.12 40.104 15.467 45.756 ;
     RECT  15.431 50.13 15.467 51.534 ;
     RECT  15.431 67.644 15.467 68.238 ;
     RECT  15.431 71.424 15.467 72.99 ;
     RECT  15.431 7.398 15.503 8.298 ;
     RECT  15.431 32.238 15.503 32.364 ;
     RECT  15.467 39.06 15.503 39.312 ;
     RECT  15.467 50.67 15.503 51.534 ;
     RECT  15.467 67.644 15.503 67.896 ;
     RECT  15.431 46.584 15.971 46.638 ;
     RECT  15.467 4.662 16.007 4.716 ;
     RECT  15.467 9.792 16.007 11.196 ;
     RECT  15.431 12.636 16.007 13.014 ;
     RECT  15.431 13.914 16.007 18.216 ;
     RECT  15.467 28.998 16.007 29.016 ;
     RECT  15.467 30.42 16.007 31.482 ;
     RECT  15.467 35.316 16.007 35.604 ;
     RECT  15.467 42.732 16.007 45.324 ;
     RECT  15.971 46.62 16.007 46.638 ;
     RECT  15.431 54.108 16.007 54.126 ;
     RECT  15.431 54.99 16.007 57.708 ;
     RECT  15.431 62.01 16.007 66.618 ;
     RECT  15.467 2.07 16.547 3.474 ;
     RECT  16.007 4.698 16.547 4.716 ;
     RECT  15.467 5.58 16.547 6.336 ;
     RECT  15.503 7.398 16.547 8.028 ;
     RECT  16.007 9.792 16.547 10.422 ;
     RECT  16.007 11.178 16.547 11.196 ;
     RECT  16.007 12.87 16.547 13.014 ;
     RECT  16.007 14.76 16.547 18.216 ;
     RECT  15.431 19.278 16.547 20.484 ;
     RECT  15.431 21.51 16.547 22.914 ;
     RECT  15.467 23.67 16.547 23.688 ;
     RECT  15.467 24.75 16.547 26.892 ;
     RECT  15.467 27.918 16.547 27.936 ;
     RECT  16.007 30.42 16.547 30.942 ;
     RECT  15.503 32.238 16.547 32.256 ;
     RECT  15.431 37.134 16.547 37.728 ;
     RECT  15.503 39.06 16.547 39.078 ;
     RECT  15.467 40.104 16.547 40.932 ;
     RECT  15.467 41.76 16.547 41.778 ;
     RECT  16.007 43.416 16.547 45.324 ;
     RECT  15.431 49.284 16.547 49.302 ;
     RECT  15.503 51.246 16.547 51.534 ;
     RECT  15.431 52.722 16.547 52.929 ;
     RECT  16.007 56.232 16.547 56.25 ;
     RECT  15.431 59.202 16.547 60.678 ;
     RECT  16.007 62.01 16.547 62.766 ;
     RECT  16.007 63.63 16.547 66.618 ;
     RECT  15.503 67.644 16.547 67.698 ;
     RECT  15.467 71.46 16.547 72.99 ;
     RECT  16.547 2.07 16.583 2.088 ;
     RECT  16.547 2.88 16.583 2.898 ;
     RECT  16.547 5.58 16.583 5.598 ;
     RECT  16.547 15.03 16.583 15.624 ;
     RECT  16.547 16.884 16.583 16.902 ;
     RECT  16.547 17.928 16.583 18.054 ;
     RECT  16.547 19.278 16.583 19.296 ;
     RECT  16.547 20.196 16.583 20.214 ;
     RECT  16.547 25.146 16.583 26.892 ;
     RECT  16.547 37.404 16.583 37.728 ;
     RECT  16.547 44.118 16.583 45.288 ;
     RECT  15.431 48.132 16.583 48.456 ;
     RECT  16.007 54.99 16.583 55.278 ;
     RECT  16.547 71.46 16.583 71.946 ;
     RECT  16.583 18.036 16.619 18.054 ;
     RECT  16.583 45.27 16.619 45.288 ;
     RECT  16.583 48.438 16.619 48.456 ;
     RECT  16.007 57.384 16.619 57.708 ;
     RECT  16.547 67.644 16.619 67.662 ;
     RECT  16.547 7.938 17.059 8.028 ;
     RECT  16.547 9.9 17.059 10.422 ;
     RECT  16.583 26.802 17.059 26.892 ;
     RECT  15.467 33.156 17.059 33.174 ;
     RECT  16.007 35.586 17.059 35.604 ;
     RECT  17.023 52.29 17.059 52.506 ;
     RECT  16.583 54.99 17.059 55.242 ;
     RECT  16.547 60.282 17.059 60.678 ;
     RECT  16.583 71.46 17.059 71.514 ;
     RECT  17.059 54.414 17.123 55.242 ;
     RECT  17.059 7.938 17.159 8.298 ;
     RECT  17.059 9.9 17.159 10.458 ;
     RECT  17.059 12.186 17.159 12.204 ;
     RECT  17.059 18.846 17.159 18.864 ;
     RECT  17.059 23.058 17.159 23.076 ;
     RECT  16.583 25.146 17.159 25.776 ;
     RECT  17.059 26.802 17.159 27.198 ;
     RECT  17.059 28.692 17.159 28.71 ;
     RECT  17.059 30.114 17.159 30.132 ;
     RECT  17.059 31.194 17.159 31.68 ;
     RECT  17.059 33.048 17.159 33.444 ;
     RECT  17.059 35.172 17.159 35.838 ;
     RECT  16.583 37.404 17.159 37.422 ;
     RECT  17.059 47.592 17.159 47.61 ;
     RECT  17.059 50.211 17.159 51.084 ;
     RECT  17.059 52.218 17.159 52.506 ;
     RECT  17.123 54.414 17.159 55.17 ;
     RECT  17.059 56.034 17.159 56.052 ;
     RECT  17.059 57.186 17.159 57.204 ;
     RECT  17.059 60.282 17.159 61.11 ;
     RECT  17.059 63.054 17.159 63.072 ;
     RECT  17.059 66.87 17.159 66.888 ;
     RECT  17.059 70.884 17.159 71.514 ;
     RECT  17.059 73.242 17.159 73.26 ;
    LAYER M3 ;
     RECT  8.136 1.957 8.154 2.029 ;
     RECT  8.028 2.029 8.154 2.101 ;
     RECT  5.364 2.101 5.382 2.143 ;
     RECT  7.956 2.101 8.154 2.143 ;
     RECT  13.824 2.101 13.842 2.143 ;
     RECT  2.415 2.143 2.505 2.191 ;
     RECT  13.215 2.143 13.842 2.191 ;
     RECT  16.56 2.065 16.578 2.203 ;
     RECT  4.248 2.029 4.266 2.219 ;
     RECT  6.84 1.957 6.858 2.251 ;
     RECT  7.815 2.143 8.154 2.299 ;
     RECT  9.036 2.065 9.054 2.299 ;
     RECT  6.66 2.251 6.858 2.335 ;
     RECT  7.632 2.299 8.154 2.335 ;
     RECT  12.276 2.299 12.294 2.335 ;
     RECT  13.104 2.191 13.842 2.335 ;
     RECT  10.515 2.143 10.605 2.371 ;
     RECT  2.304 2.191 2.505 2.413 ;
     RECT  5.115 2.143 5.382 2.413 ;
     RECT  9.036 2.299 9.126 2.443 ;
     RECT  10.515 2.371 10.854 2.443 ;
     RECT  14.832 2.347 14.85 2.443 ;
     RECT  3.996 2.263 4.23 2.461 ;
     RECT  0.252 2.299 0.27 2.477 ;
     RECT  3.924 2.461 4.23 2.489 ;
     RECT  6.66 2.335 8.154 2.489 ;
     RECT  7.416 2.489 8.154 2.497 ;
     RECT  7.416 2.497 8.226 2.533 ;
     RECT  9.036 2.443 10.854 2.533 ;
     RECT  11.7 2.335 13.842 2.533 ;
     RECT  2.304 2.413 2.697 2.569 ;
     RECT  3.924 2.489 4.086 2.569 ;
     RECT  7.416 2.533 10.854 2.569 ;
     RECT  11.7 2.533 13.95 2.569 ;
     RECT  6.336 2.533 6.354 2.587 ;
     RECT  16.524 2.203 16.578 2.633 ;
     RECT  2.304 2.569 2.934 2.641 ;
     RECT  6.264 2.587 6.354 2.669 ;
     RECT  0.288 2.587 0.306 2.731 ;
     RECT  7.416 2.569 13.95 2.731 ;
     RECT  14.832 2.443 14.886 2.731 ;
     RECT  7.416 2.731 14.886 2.759 ;
     RECT  16.56 2.633 16.578 2.779 ;
     RECT  14.616 2.759 14.886 2.831 ;
     RECT  0.288 2.731 0.414 2.861 ;
     RECT  2.304 2.641 3.042 2.875 ;
     RECT  3.816 2.569 4.086 2.875 ;
     RECT  16.56 2.779 16.614 3.005 ;
     RECT  14.688 2.831 14.886 3.067 ;
     RECT  5.115 2.413 5.397 3.073 ;
     RECT  14.688 3.067 15.426 3.101 ;
     RECT  5.115 3.073 6.066 3.181 ;
     RECT  2.304 2.875 4.086 3.271 ;
     RECT  4.896 3.181 6.066 3.271 ;
     RECT  7.416 2.759 13.878 3.307 ;
     RECT  2.304 3.271 6.066 3.335 ;
     RECT  6.84 3.307 13.878 3.451 ;
     RECT  6.768 3.451 13.878 3.691 ;
     RECT  14.832 3.101 15.426 3.691 ;
     RECT  16.524 3.451 16.542 3.821 ;
     RECT  6.768 3.691 13.914 4.117 ;
     RECT  14.832 3.691 15.462 4.189 ;
     RECT  6.408 4.117 13.914 4.261 ;
     RECT  14.796 4.189 15.462 4.451 ;
     RECT  6.264 4.261 13.914 4.487 ;
     RECT  6.3 4.487 13.914 4.493 ;
     RECT  7.488 4.493 13.914 4.541 ;
     RECT  2.304 3.335 5.397 4.559 ;
     RECT  7.596 4.541 13.914 4.603 ;
     RECT  14.796 4.451 14.886 4.603 ;
     RECT  15.984 4.507 16.002 4.685 ;
     RECT  0.252 4.603 0.27 4.733 ;
     RECT  16.524 4.693 16.542 4.781 ;
     RECT  7.596 4.603 14.886 4.919 ;
     RECT  0.288 4.843 0.414 4.973 ;
     RECT  14.832 4.919 14.886 5.027 ;
     RECT  0.288 4.973 0.306 5.069 ;
     RECT  6.3 4.493 6.498 5.261 ;
     RECT  2.304 4.559 4.05 5.371 ;
     RECT  2.232 5.371 4.05 5.459 ;
     RECT  7.596 4.919 13.914 5.503 ;
     RECT  16.524 5.563 16.542 5.575 ;
     RECT  7.416 5.503 13.914 5.611 ;
     RECT  0.252 5.515 0.27 5.693 ;
     RECT  2.304 5.459 4.05 5.701 ;
     RECT  5.115 4.559 5.397 5.701 ;
     RECT  5.115 5.701 5.454 5.707 ;
     RECT  2.304 5.701 4.086 5.773 ;
     RECT  5.115 5.707 5.49 5.773 ;
     RECT  16.524 5.575 16.578 5.789 ;
     RECT  2.304 5.773 5.49 5.845 ;
     RECT  14.832 5.027 14.85 5.995 ;
     RECT  2.304 5.845 5.886 6.035 ;
     RECT  6.84 5.611 13.914 6.091 ;
     RECT  2.304 6.035 5.49 6.269 ;
     RECT  16.524 5.789 16.542 6.341 ;
     RECT  6.264 6.091 13.914 6.385 ;
     RECT  14.832 5.995 15.426 6.385 ;
     RECT  6.264 6.385 15.426 6.421 ;
     RECT  0.54 6.043 0.558 6.509 ;
     RECT  6.264 6.421 15.462 6.749 ;
     RECT  6.264 6.749 15.426 6.845 ;
     RECT  14.832 6.845 15.426 6.851 ;
     RECT  2.412 6.269 5.49 6.907 ;
     RECT  6.264 6.845 13.626 6.907 ;
     RECT  2.412 6.907 13.626 7.003 ;
     RECT  2.304 7.003 13.626 7.115 ;
     RECT  2.304 7.115 13.554 7.349 ;
     RECT  2.304 7.349 6.426 7.385 ;
     RECT  7.2 7.349 13.497 7.385 ;
     RECT  2.304 7.385 6.318 7.531 ;
     RECT  14.832 6.851 14.85 7.675 ;
     RECT  2.232 7.531 6.318 7.799 ;
     RECT  2.232 7.799 4.23 7.867 ;
     RECT  16.524 7.243 16.542 7.915 ;
     RECT  2.16 7.867 4.23 7.997 ;
     RECT  0.216 7.861 0.234 8.011 ;
     RECT  14.832 7.675 14.886 8.041 ;
     RECT  14.58 8.041 14.886 8.059 ;
     RECT  0.216 8.011 0.306 8.069 ;
     RECT  0.216 8.069 0.234 8.093 ;
     RECT  14.58 8.059 15.426 8.155 ;
     RECT  5.115 7.799 6.03 8.159 ;
     RECT  14.58 8.155 15.498 8.159 ;
     RECT  7.308 7.385 13.497 8.189 ;
     RECT  15.408 8.159 15.498 8.303 ;
     RECT  16.524 7.915 17.154 8.303 ;
     RECT  7.344 8.189 13.497 8.311 ;
     RECT  16.524 8.303 17.082 8.333 ;
     RECT  16.524 8.333 16.542 8.429 ;
     RECT  7.344 8.311 13.842 8.545 ;
     RECT  2.304 7.997 4.23 8.587 ;
     RECT  7.344 8.545 14.49 8.699 ;
     RECT  15.408 8.303 15.426 8.941 ;
     RECT  2.304 8.587 4.302 9.013 ;
     RECT  5.115 8.159 5.397 9.013 ;
     RECT  14.688 8.941 15.426 9.041 ;
     RECT  2.304 9.013 5.397 9.049 ;
     RECT  7.344 8.699 13.842 9.067 ;
     RECT  2.304 9.049 5.598 9.113 ;
     RECT  6.84 9.067 13.842 9.113 ;
     RECT  2.304 9.113 2.697 9.211 ;
     RECT  3.492 9.113 5.598 9.239 ;
     RECT  14.724 9.041 15.426 9.239 ;
     RECT  6.84 9.113 11.394 9.259 ;
     RECT  14.832 9.239 15.426 9.341 ;
     RECT  3.492 9.239 5.397 9.509 ;
     RECT  12.24 9.113 13.842 9.509 ;
     RECT  12.24 9.509 13.734 9.533 ;
     RECT  6.336 9.259 11.394 9.545 ;
     RECT  14.868 9.341 15.426 9.553 ;
     RECT  6.804 9.545 11.394 9.689 ;
     RECT  2.268 9.211 2.697 9.739 ;
     RECT  14.868 9.553 15.462 9.869 ;
     RECT  16.524 9.739 16.542 9.883 ;
     RECT  2.052 9.739 2.697 9.923 ;
     RECT  7.092 9.689 11.394 10.049 ;
     RECT  7.344 10.049 11.394 10.121 ;
     RECT  14.868 9.869 15.426 10.165 ;
     RECT  7.416 10.121 11.394 10.267 ;
     RECT  3.78 9.509 5.397 10.291 ;
     RECT  3.78 10.291 5.886 10.315 ;
     RECT  2.304 9.923 2.697 10.319 ;
     RECT  2.415 10.319 2.697 10.327 ;
     RECT  3.528 10.315 5.886 10.327 ;
     RECT  2.415 10.327 5.886 10.363 ;
     RECT  0.252 10.267 0.27 10.445 ;
     RECT  16.524 9.883 17.154 10.463 ;
     RECT  16.524 10.463 17.082 10.493 ;
     RECT  2.415 10.363 6.354 10.499 ;
     RECT  12.24 9.533 13.698 10.561 ;
     RECT  0.288 10.555 0.45 10.603 ;
     RECT  0.288 10.603 1.17 10.685 ;
     RECT  2.415 10.499 6.282 10.697 ;
     RECT  14.832 10.165 15.426 10.699 ;
     RECT  16.524 10.493 16.542 10.699 ;
     RECT  0.288 10.685 0.378 10.781 ;
     RECT  1.152 10.685 1.17 10.781 ;
     RECT  7.416 10.267 11.502 10.795 ;
     RECT  12.24 10.561 13.734 10.795 ;
     RECT  0.36 10.781 0.378 10.829 ;
     RECT  14.832 10.699 16.542 10.867 ;
     RECT  7.416 10.795 13.734 10.891 ;
     RECT  14.724 10.867 16.542 10.895 ;
     RECT  6.264 10.697 6.282 10.973 ;
     RECT  7.02 10.891 13.734 11.011 ;
     RECT  2.415 10.697 5.397 11.083 ;
     RECT  2.376 11.083 5.397 11.101 ;
     RECT  7.02 11.011 13.878 11.101 ;
     RECT  14.724 10.895 15.426 11.101 ;
     RECT  16.524 10.895 16.542 11.201 ;
     RECT  7.02 11.101 15.426 11.227 ;
     RECT  6.336 11.227 15.426 11.309 ;
     RECT  6.408 11.309 15.426 11.399 ;
     RECT  0.54 11.713 0.558 11.803 ;
     RECT  6.768 11.399 15.426 11.813 ;
     RECT  6.804 11.813 15.426 11.849 ;
     RECT  17.064 12.139 17.082 12.181 ;
     RECT  17.064 12.181 17.154 12.221 ;
     RECT  2.304 11.101 5.397 12.515 ;
     RECT  3.492 12.515 5.397 12.595 ;
     RECT  0.54 11.803 1.278 12.605 ;
     RECT  7.02 11.849 15.426 12.631 ;
     RECT  16.524 12.283 16.542 12.631 ;
     RECT  7.02 12.631 16.542 12.757 ;
     RECT  3.492 12.595 5.598 12.797 ;
     RECT  6.66 12.757 16.542 12.811 ;
     RECT  6.552 12.811 16.542 12.857 ;
     RECT  7.272 12.857 16.542 12.893 ;
     RECT  6.48 12.859 6.498 12.899 ;
     RECT  7.272 12.893 15.426 12.929 ;
     RECT  1.152 12.605 1.278 12.941 ;
     RECT  7.308 12.929 15.426 13.019 ;
     RECT  1.26 12.941 1.278 13.085 ;
     RECT  7.344 13.019 15.426 13.091 ;
     RECT  3.492 12.797 4.302 13.289 ;
     RECT  2.304 12.515 2.697 13.297 ;
     RECT  3.924 13.289 4.194 13.325 ;
     RECT  5.076 12.797 5.598 13.333 ;
     RECT  2.304 13.297 3.15 13.433 ;
     RECT  0.252 13.339 0.27 13.483 ;
     RECT  0.252 13.483 0.414 13.517 ;
     RECT  0.396 13.517 0.414 13.613 ;
     RECT  5.076 13.333 5.85 13.667 ;
     RECT  7.38 13.091 15.426 13.667 ;
     RECT  7.38 13.667 14.886 13.901 ;
     RECT  16.524 12.893 16.542 13.909 ;
     RECT  6.228 13.819 6.246 13.915 ;
     RECT  7.38 13.901 13.986 13.915 ;
     RECT  6.228 13.915 13.986 13.973 ;
     RECT  1.368 14.011 1.386 14.059 ;
     RECT  3.924 13.325 4.014 14.071 ;
     RECT  5.076 13.667 5.49 14.071 ;
     RECT  1.152 14.059 1.386 14.141 ;
     RECT  6.228 13.973 6.246 14.171 ;
     RECT  7.236 13.973 13.986 14.189 ;
     RECT  3.924 14.071 5.49 14.215 ;
     RECT  1.152 14.141 1.17 14.237 ;
     RECT  7.236 14.189 13.59 14.243 ;
     RECT  14.832 13.901 14.886 14.243 ;
     RECT  3.852 14.215 5.49 14.369 ;
     RECT  7.236 14.243 11.214 14.441 ;
     RECT  3.852 14.369 5.397 14.477 ;
     RECT  15.984 13.909 16.542 14.483 ;
     RECT  2.304 13.433 2.934 14.485 ;
     RECT  2.304 14.485 3.006 14.611 ;
     RECT  16.524 14.483 16.542 14.779 ;
     RECT  0.252 14.827 0.27 14.953 ;
     RECT  2.304 14.611 3.078 14.971 ;
     RECT  3.852 14.477 4.194 14.971 ;
     RECT  11.952 14.243 13.59 14.971 ;
     RECT  0.216 14.953 0.306 15.053 ;
     RECT  11.952 14.971 13.734 15.061 ;
     RECT  0.216 15.053 0.234 15.101 ;
     RECT  2.304 14.971 4.194 15.179 ;
     RECT  7.416 14.441 11.214 15.187 ;
     RECT  3.888 15.179 4.194 15.259 ;
     RECT  7.128 15.187 11.214 15.295 ;
     RECT  11.952 15.061 13.986 15.295 ;
     RECT  15.408 14.875 15.426 15.307 ;
     RECT  7.128 15.295 13.986 15.341 ;
     RECT  3.888 15.259 4.302 15.355 ;
     RECT  5.112 14.477 5.397 15.355 ;
     RECT  7.128 15.341 13.914 15.421 ;
     RECT  6.912 15.421 13.914 15.451 ;
     RECT  14.832 15.307 15.426 15.529 ;
     RECT  16.524 14.779 16.578 15.629 ;
     RECT  1.26 15.691 1.278 15.787 ;
     RECT  1.152 15.787 1.278 15.821 ;
     RECT  14.832 15.529 15.462 15.863 ;
     RECT  6.228 15.451 13.914 15.899 ;
     RECT  1.152 15.821 1.17 15.965 ;
     RECT  2.304 15.179 2.754 16.069 ;
     RECT  3.888 15.355 5.397 16.075 ;
     RECT  2.304 16.069 3.114 16.141 ;
     RECT  3.888 16.075 5.706 16.141 ;
     RECT  6.516 15.899 13.914 16.141 ;
     RECT  6.516 16.141 14.598 16.259 ;
     RECT  15.408 15.863 15.462 16.331 ;
     RECT  16.524 15.629 16.542 16.411 ;
     RECT  2.304 16.141 5.706 16.501 ;
     RECT  6.516 16.259 14.202 16.589 ;
     RECT  0.54 16.501 0.558 16.637 ;
     RECT  15.984 16.411 16.542 16.651 ;
     RECT  2.232 16.501 5.706 16.709 ;
     RECT  6.84 16.589 14.202 16.709 ;
     RECT  15.984 16.651 16.578 16.795 ;
     RECT  6.912 16.709 14.202 17.041 ;
     RECT  15.984 16.795 17.01 17.117 ;
     RECT  2.304 16.709 5.706 17.149 ;
     RECT  0.216 17.041 0.234 17.165 ;
     RECT  6.912 17.041 14.706 17.177 ;
     RECT  6.912 17.177 13.95 17.213 ;
     RECT  14.688 17.177 14.706 17.213 ;
     RECT  15.984 17.117 16.542 17.309 ;
     RECT  14.832 17.371 14.85 17.447 ;
     RECT  15.408 17.455 15.426 17.501 ;
     RECT  2.304 17.149 5.778 17.681 ;
     RECT  2.304 17.681 4.23 17.879 ;
     RECT  16.524 17.309 16.542 17.899 ;
     RECT  1.152 17.755 1.17 17.933 ;
     RECT  4.032 17.879 4.23 17.933 ;
     RECT  16.524 17.899 16.578 17.947 ;
     RECT  6.984 17.213 13.95 18.121 ;
     RECT  6.984 18.121 14.202 18.139 ;
     RECT  5.112 17.681 5.778 18.149 ;
     RECT  6.804 18.139 14.202 18.221 ;
     RECT  16.524 17.947 16.65 18.221 ;
     RECT  16.632 18.221 16.65 18.365 ;
     RECT  2.304 17.879 3.186 18.379 ;
     RECT  2.268 18.379 3.186 18.419 ;
     RECT  4.212 17.933 4.23 18.475 ;
     RECT  7.308 18.221 14.202 18.499 ;
     RECT  7.308 18.499 14.598 18.571 ;
     RECT  15.408 18.523 15.426 18.571 ;
     RECT  0.252 18.475 0.27 18.652 ;
     RECT  2.304 18.419 3.186 18.661 ;
     RECT  7.308 18.571 15.426 18.725 ;
     RECT  4.212 18.475 4.374 18.769 ;
     RECT  5.112 18.149 5.67 18.769 ;
     RECT  2.304 18.661 3.258 18.805 ;
     RECT  4.212 18.769 5.67 18.805 ;
     RECT  17.064 18.811 17.154 18.869 ;
     RECT  2.304 18.805 5.67 18.893 ;
     RECT  17.064 18.869 17.082 18.893 ;
     RECT  0.216 18.652 0.306 18.941 ;
     RECT  7.308 18.725 13.842 18.955 ;
     RECT  0.288 18.941 0.306 18.989 ;
     RECT  2.304 18.893 5.418 19.103 ;
     RECT  1.152 19.099 1.17 19.147 ;
     RECT  1.152 19.147 1.278 19.277 ;
     RECT  6.804 18.955 13.842 19.277 ;
     RECT  16.56 19.273 16.578 19.339 ;
     RECT  2.304 19.103 5.397 19.373 ;
     RECT  7.272 19.277 13.842 19.421 ;
     RECT  14.832 18.725 15.426 19.57 ;
     RECT  14.832 19.57 15.462 19.643 ;
     RECT  10.515 19.421 13.842 19.651 ;
     RECT  14.832 19.643 15.426 19.651 ;
     RECT  16.524 19.339 16.578 19.819 ;
     RECT  6.156 19.507 6.174 19.949 ;
     RECT  16.524 19.819 16.65 20.045 ;
     RECT  1.26 19.277 1.278 20.059 ;
     RECT  7.272 19.421 9.378 20.083 ;
     RECT  1.152 20.059 1.278 20.093 ;
     RECT  3.78 19.373 5.397 20.111 ;
     RECT  7.02 20.083 9.378 20.191 ;
     RECT  1.152 20.093 1.17 20.237 ;
     RECT  2.304 19.373 2.697 20.237 ;
     RECT  0.288 20.251 0.306 20.281 ;
     RECT  2.415 20.237 2.697 20.281 ;
     RECT  0.288 20.281 0.378 20.333 ;
     RECT  2.415 20.281 3.042 20.347 ;
     RECT  3.996 20.111 5.397 20.381 ;
     RECT  6.372 20.191 9.63 20.389 ;
     RECT  10.515 19.651 15.426 20.389 ;
     RECT  16.524 20.045 16.578 20.429 ;
     RECT  16.524 20.429 16.542 20.489 ;
     RECT  0.288 20.333 0.306 20.525 ;
     RECT  5.112 20.381 5.397 20.651 ;
     RECT  5.115 20.651 5.397 20.857 ;
     RECT  6.372 20.389 15.426 20.857 ;
     RECT  2.415 20.347 3.258 20.893 ;
     RECT  3.996 20.381 4.122 20.893 ;
     RECT  2.415 20.893 4.122 21.001 ;
     RECT  5.115 20.857 15.426 21.029 ;
     RECT  2.304 21.001 4.122 21.155 ;
     RECT  2.304 21.155 3.006 21.245 ;
     RECT  1.152 21.307 1.17 21.361 ;
     RECT  3.744 21.155 4.122 21.361 ;
     RECT  0.54 21.361 1.17 21.403 ;
     RECT  0.252 21.403 1.17 21.437 ;
     RECT  3.744 21.361 4.158 21.451 ;
     RECT  5.115 21.029 5.397 21.451 ;
     RECT  0.252 21.437 0.594 21.533 ;
     RECT  6.192 21.029 15.426 21.547 ;
     RECT  16.524 21.451 16.542 21.547 ;
     RECT  0.324 21.533 0.594 21.581 ;
     RECT  3.744 21.451 5.397 21.659 ;
     RECT  6.192 21.547 16.542 21.731 ;
     RECT  5.115 21.659 5.397 21.775 ;
     RECT  6.192 21.731 15.426 21.775 ;
     RECT  5.115 21.775 15.426 21.803 ;
     RECT  5.115 21.803 14.85 21.821 ;
     RECT  0.504 21.581 0.594 21.869 ;
     RECT  3.744 21.659 4.122 21.965 ;
     RECT  2.415 21.245 3.006 21.973 ;
     RECT  3.744 21.965 3.942 21.973 ;
     RECT  2.415 21.973 3.942 22.009 ;
     RECT  5.115 21.821 14.742 22.073 ;
     RECT  2.304 22.009 3.942 22.081 ;
     RECT  6.552 22.073 14.742 22.109 ;
     RECT  2.268 22.081 3.942 22.205 ;
     RECT  6.66 22.109 14.742 22.253 ;
     RECT  0.54 21.869 0.594 22.315 ;
     RECT  7.272 22.253 14.742 22.621 ;
     RECT  2.304 22.205 3.942 22.711 ;
     RECT  5.115 22.073 5.778 22.711 ;
     RECT  5.076 22.711 5.778 22.739 ;
     RECT  5.076 22.739 5.454 22.781 ;
     RECT  16.524 21.731 16.542 22.783 ;
     RECT  0.54 22.315 0.63 22.819 ;
     RECT  15.984 22.783 16.542 22.829 ;
     RECT  7.272 22.621 14.85 22.891 ;
     RECT  0.54 22.819 1.17 22.919 ;
     RECT  16.524 22.829 16.542 23.035 ;
     RECT  16.524 23.035 17.082 23.053 ;
     RECT  16.524 23.053 17.154 23.117 ;
     RECT  2.304 22.711 4.014 23.161 ;
     RECT  5.076 22.781 5.397 23.161 ;
     RECT  7.272 22.891 15.426 23.251 ;
     RECT  2.304 23.161 5.397 23.309 ;
     RECT  2.304 23.309 3.546 23.315 ;
     RECT  7.092 23.251 15.426 23.371 ;
     RECT  0.54 22.919 0.558 23.549 ;
     RECT  4.356 23.309 5.397 23.611 ;
     RECT  2.304 23.315 3.294 23.645 ;
     RECT  4.356 23.611 5.742 23.657 ;
     RECT  16.524 23.117 16.542 23.693 ;
     RECT  2.304 23.645 2.97 23.791 ;
     RECT  6.516 23.371 15.426 24.043 ;
     RECT  6.3 24.043 15.426 24.089 ;
     RECT  4.356 23.657 5.454 24.173 ;
     RECT  14.832 24.089 15.426 24.187 ;
     RECT  14.832 24.187 15.462 24.233 ;
     RECT  3.996 24.331 4.194 24.461 ;
     RECT  6.3 24.089 13.842 24.461 ;
     RECT  5.115 24.173 5.454 24.475 ;
     RECT  6.3 24.461 13.734 24.503 ;
     RECT  2.268 23.791 2.97 24.511 ;
     RECT  5.115 24.475 5.49 24.629 ;
     RECT  2.268 24.511 3.006 24.893 ;
     RECT  14.832 24.233 14.85 25.003 ;
     RECT  4.104 24.461 4.194 25.007 ;
     RECT  6.3 24.503 13.497 25.043 ;
     RECT  16.524 24.475 16.542 25.099 ;
     RECT  4.176 25.007 4.194 25.141 ;
     RECT  5.115 24.629 5.397 25.141 ;
     RECT  16.524 25.099 17.082 25.141 ;
     RECT  14.832 25.003 15.426 25.195 ;
     RECT  14.832 25.195 15.498 25.313 ;
     RECT  2.304 24.893 3.006 25.321 ;
     RECT  7.164 25.043 13.497 25.321 ;
     RECT  14.832 25.313 14.922 25.321 ;
     RECT  4.176 25.141 5.397 25.435 ;
     RECT  2.304 25.321 3.33 25.439 ;
     RECT  7.164 25.321 14.922 25.439 ;
     RECT  4.176 25.435 6.102 25.475 ;
     RECT  14.724 25.439 14.922 25.511 ;
     RECT  14.796 25.511 14.922 25.547 ;
     RECT  1.152 25.435 1.17 25.613 ;
     RECT  4.176 25.475 5.397 25.789 ;
     RECT  16.524 25.141 17.154 25.805 ;
     RECT  2.304 25.439 3.114 25.915 ;
     RECT  6.192 25.771 6.426 26.189 ;
     RECT  7.164 25.439 13.842 26.221 ;
     RECT  14.832 25.547 14.922 26.251 ;
     RECT  6.516 26.221 13.914 26.285 ;
     RECT  2.268 25.915 3.114 26.329 ;
     RECT  3.888 25.789 5.397 26.329 ;
     RECT  6.516 26.285 13.842 26.333 ;
     RECT  0.252 26.299 0.27 26.476 ;
     RECT  0.216 26.476 0.306 26.573 ;
     RECT  6.516 26.333 13.698 26.573 ;
     RECT  2.268 26.329 5.397 26.587 ;
     RECT  0.288 26.573 0.306 26.621 ;
     RECT  6.804 26.573 13.698 26.627 ;
     RECT  2.232 26.587 5.397 26.635 ;
     RECT  2.232 26.635 5.706 26.699 ;
     RECT  16.524 25.805 16.578 26.779 ;
     RECT  2.304 26.699 5.706 26.789 ;
     RECT  16.524 26.779 17.082 26.797 ;
     RECT  0.54 26.635 0.558 26.861 ;
     RECT  2.304 26.789 5.634 26.861 ;
     RECT  16.524 26.797 17.154 26.897 ;
     RECT  1.152 26.971 1.278 27.101 ;
     RECT  2.304 26.861 5.397 27.101 ;
     RECT  14.832 26.251 15.426 27.175 ;
     RECT  16.56 26.897 17.154 27.203 ;
     RECT  4.788 27.101 5.397 27.239 ;
     RECT  1.152 27.101 1.17 27.245 ;
     RECT  16.56 27.203 17.082 27.245 ;
     RECT  2.304 27.101 4.05 27.329 ;
     RECT  4.932 27.239 5.397 27.329 ;
     RECT  7.272 26.627 13.698 27.355 ;
     RECT  6.804 27.355 13.698 27.409 ;
     RECT  14.544 27.175 15.426 27.409 ;
     RECT  6.804 27.409 15.426 27.499 ;
     RECT  16.56 27.245 16.578 27.739 ;
     RECT  6.804 27.499 15.462 27.743 ;
     RECT  5.115 27.329 5.397 27.751 ;
     RECT  5.115 27.751 5.922 27.869 ;
     RECT  16.524 27.739 16.578 27.941 ;
     RECT  3.6 27.329 4.05 27.949 ;
     RECT  3.6 27.949 4.086 27.985 ;
     RECT  6.804 27.743 15.426 28.049 ;
     RECT  16.56 27.941 16.578 28.061 ;
     RECT  2.304 27.329 2.79 28.111 ;
     RECT  3.6 27.985 4.266 28.111 ;
     RECT  5.115 27.869 5.397 28.111 ;
     RECT  2.304 28.111 4.266 28.123 ;
     RECT  2.268 28.123 4.266 28.247 ;
     RECT  2.304 28.247 4.266 28.256 ;
     RECT  3.708 28.256 4.266 28.291 ;
     RECT  5.076 28.111 5.397 28.291 ;
     RECT  6.804 28.049 11.754 28.445 ;
     RECT  0.54 28.381 1.17 28.541 ;
     RECT  6.804 28.445 9.414 28.687 ;
     RECT  17.064 28.651 17.082 28.687 ;
     RECT  17.064 28.687 17.154 28.715 ;
     RECT  6.3 28.687 9.414 28.733 ;
     RECT  17.136 28.715 17.154 28.733 ;
     RECT  6.84 28.733 9.414 28.829 ;
     RECT  10.188 28.445 11.754 28.831 ;
     RECT  12.492 28.049 15.426 28.831 ;
     RECT  10.188 28.831 15.426 28.987 ;
     RECT  10.188 28.987 16.002 29.027 ;
     RECT  3.708 28.291 5.397 29.219 ;
     RECT  6.984 28.829 9.414 29.255 ;
     RECT  7.308 29.255 9.414 29.335 ;
     RECT  10.188 29.027 15.462 29.335 ;
     RECT  2.304 28.256 2.826 29.371 ;
     RECT  1.152 28.541 1.17 29.467 ;
     RECT  7.308 29.335 15.462 29.489 ;
     RECT  1.152 29.467 1.278 29.597 ;
     RECT  7.308 29.489 13.914 29.597 ;
     RECT  2.304 29.371 3.51 30.001 ;
     RECT  4.464 29.219 5.397 30.001 ;
     RECT  17.136 30.091 17.154 30.109 ;
     RECT  17.064 30.109 17.154 30.137 ;
     RECT  14.832 29.489 15.462 30.173 ;
     RECT  17.064 30.137 17.082 30.173 ;
     RECT  2.304 30.001 5.397 30.271 ;
     RECT  2.304 30.271 5.598 30.283 ;
     RECT  15.984 30.235 16.002 30.331 ;
     RECT  2.268 30.283 5.598 30.371 ;
     RECT  2.304 30.371 5.598 30.379 ;
     RECT  2.304 30.379 6.21 30.416 ;
     RECT  4.428 30.416 6.21 30.443 ;
     RECT  6.192 30.443 6.21 30.451 ;
     RECT  6.192 30.451 6.282 30.479 ;
     RECT  15.984 30.331 17.01 30.479 ;
     RECT  1.152 29.597 1.17 30.523 ;
     RECT  2.304 30.416 3.474 30.641 ;
     RECT  1.152 30.523 1.278 30.653 ;
     RECT  4.428 30.443 5.397 30.653 ;
     RECT  6.264 30.479 6.282 30.667 ;
     RECT  7.416 29.597 13.914 30.685 ;
     RECT  14.832 30.173 14.886 30.701 ;
     RECT  1.152 30.653 1.17 30.749 ;
     RECT  7.272 30.685 13.914 30.749 ;
     RECT  2.304 30.641 3.258 30.839 ;
     RECT  14.832 30.701 14.85 30.859 ;
     RECT  7.344 30.749 13.914 30.991 ;
     RECT  14.724 30.859 14.85 30.991 ;
     RECT  2.304 30.839 2.754 31.109 ;
     RECT  6.264 30.667 6.354 31.145 ;
     RECT  16.524 30.479 17.01 31.147 ;
     RECT  16.524 31.147 17.082 31.189 ;
     RECT  6.264 31.145 6.318 31.253 ;
     RECT  16.524 31.189 17.154 31.291 ;
     RECT  7.344 30.991 14.85 31.483 ;
     RECT  15.984 31.291 17.154 31.487 ;
     RECT  0.252 30.427 0.27 31.517 ;
     RECT  6.264 31.253 6.282 31.517 ;
     RECT  4.5 30.653 5.397 31.525 ;
     RECT  4.5 31.525 5.49 31.531 ;
     RECT  4.5 31.531 5.562 31.661 ;
     RECT  16.56 31.487 17.154 31.685 ;
     RECT  0.324 31.531 0.342 31.709 ;
     RECT  16.56 31.685 17.082 31.709 ;
     RECT  7.344 31.483 14.886 31.723 ;
     RECT  3.636 31.693 3.654 31.729 ;
     RECT  3.528 31.729 3.654 31.771 ;
     RECT  4.5 31.661 5.49 31.771 ;
     RECT  3.528 31.771 5.49 31.793 ;
     RECT  2.304 31.109 2.697 31.999 ;
     RECT  3.528 31.793 5.397 31.999 ;
     RECT  1.152 31.999 1.17 32.071 ;
     RECT  0.54 32.071 1.17 32.099 ;
     RECT  7.344 31.723 14.922 32.107 ;
     RECT  6.3 32.035 6.318 32.197 ;
     RECT  7.344 32.107 15.498 32.197 ;
     RECT  16.56 31.709 16.578 32.233 ;
     RECT  16.524 32.233 16.578 32.333 ;
     RECT  6.3 32.197 15.498 32.369 ;
     RECT  6.3 32.369 15.426 32.467 ;
     RECT  6.264 32.467 15.426 32.495 ;
     RECT  0.54 32.099 0.558 32.525 ;
     RECT  6.264 32.495 13.842 32.611 ;
     RECT  6.12 32.611 13.842 32.729 ;
     RECT  6.264 32.729 13.842 32.765 ;
     RECT  6.624 32.765 13.842 32.813 ;
     RECT  6.84 32.813 13.842 32.861 ;
     RECT  16.56 32.333 16.578 33.019 ;
     RECT  0.396 32.923 0.414 33.079 ;
     RECT  2.304 31.999 5.397 33.115 ;
     RECT  16.56 33.019 17.154 33.151 ;
     RECT  0.216 33.079 0.414 33.245 ;
     RECT  14.616 32.495 15.426 33.259 ;
     RECT  14.616 33.259 15.462 33.269 ;
     RECT  0.288 33.245 0.414 33.293 ;
     RECT  0.396 33.293 0.414 33.313 ;
     RECT  14.832 33.269 15.462 33.341 ;
     RECT  16.524 33.151 17.154 33.389 ;
     RECT  0.396 33.313 1.17 33.413 ;
     RECT  17.064 33.389 17.154 33.449 ;
     RECT  17.064 33.449 17.082 33.485 ;
     RECT  7.272 32.861 13.842 33.511 ;
     RECT  0.396 33.413 0.558 33.581 ;
     RECT  2.304 33.115 5.454 33.629 ;
     RECT  14.832 33.341 15.426 33.629 ;
     RECT  0.504 33.581 0.558 33.677 ;
     RECT  7.272 33.511 13.986 33.691 ;
     RECT  0.504 33.677 0.522 33.773 ;
     RECT  3.6 33.629 5.454 33.809 ;
     RECT  7.02 33.691 13.986 33.835 ;
     RECT  5.115 33.809 5.454 33.961 ;
     RECT  6.444 33.835 13.986 34.321 ;
     RECT  14.832 33.629 14.958 34.321 ;
     RECT  6.444 34.321 14.958 34.507 ;
     RECT  5.115 33.961 5.562 34.591 ;
     RECT  6.444 34.507 15.426 34.591 ;
     RECT  5.115 34.591 15.426 34.603 ;
     RECT  5.115 34.603 15.462 34.691 ;
     RECT  2.304 33.629 2.697 34.771 ;
     RECT  3.6 33.809 4.158 34.771 ;
     RECT  6.372 34.691 15.462 34.781 ;
     RECT  2.304 34.771 4.158 34.795 ;
     RECT  2.304 34.795 4.266 35.159 ;
     RECT  17.064 35.131 17.082 35.167 ;
     RECT  2.304 35.159 2.826 35.213 ;
     RECT  7.344 34.781 15.462 35.311 ;
     RECT  3.816 35.159 4.266 35.401 ;
     RECT  5.115 34.691 5.397 35.401 ;
     RECT  6.372 34.781 6.39 35.419 ;
     RECT  6.192 35.419 6.39 35.465 ;
     RECT  7.344 35.311 16.002 35.501 ;
     RECT  3.816 35.401 5.397 35.507 ;
     RECT  4.032 35.507 5.397 35.537 ;
     RECT  17.064 35.167 17.154 35.563 ;
     RECT  16.524 35.563 17.154 35.609 ;
     RECT  6.372 35.465 6.39 35.699 ;
     RECT  4.068 35.537 5.397 35.744 ;
     RECT  4.14 35.744 5.397 35.771 ;
     RECT  17.064 35.609 17.154 35.843 ;
     RECT  17.064 35.843 17.082 35.885 ;
     RECT  2.304 35.213 2.697 36.013 ;
     RECT  2.268 36.013 3.294 36.173 ;
     RECT  7.344 35.501 15.426 36.239 ;
     RECT  14.832 36.239 15.426 36.383 ;
     RECT  7.344 36.239 14.094 36.619 ;
     RECT  2.304 36.173 3.294 36.661 ;
     RECT  4.248 35.771 5.397 36.661 ;
     RECT  0.252 36.283 0.27 36.763 ;
     RECT  6.804 36.619 14.094 36.787 ;
     RECT  14.832 36.383 15.066 36.851 ;
     RECT  6.408 36.787 14.094 36.923 ;
     RECT  0.252 36.763 0.414 37.021 ;
     RECT  2.304 36.661 5.397 37.049 ;
     RECT  0.216 37.021 0.414 37.133 ;
     RECT  4.932 37.049 5.397 37.165 ;
     RECT  6.408 36.923 14.058 37.165 ;
     RECT  0.396 37.133 0.414 37.229 ;
     RECT  14.868 36.851 15.066 37.339 ;
     RECT  16.524 36.907 16.542 37.387 ;
     RECT  16.524 37.387 17.154 37.427 ;
     RECT  16.524 37.427 17.082 37.469 ;
     RECT  4.932 37.165 14.058 37.499 ;
     RECT  2.304 37.049 2.898 37.589 ;
     RECT  4.932 37.499 6.426 37.589 ;
     RECT  6.192 37.589 6.426 37.625 ;
     RECT  16.524 37.469 16.578 37.625 ;
     RECT  16.56 37.625 16.578 37.733 ;
     RECT  14.868 37.339 15.426 37.771 ;
     RECT  3.816 37.049 3.834 37.939 ;
     RECT  0.54 37.471 0.558 37.963 ;
     RECT  3.816 37.939 4.086 37.963 ;
     RECT  4.932 37.589 5.454 37.963 ;
     RECT  3.816 37.963 5.454 37.975 ;
     RECT  3.528 37.975 5.454 38.129 ;
     RECT  0.54 37.963 1.17 38.141 ;
     RECT  7.272 37.499 14.058 38.155 ;
     RECT  14.832 37.771 15.426 38.155 ;
     RECT  0.54 38.141 0.558 38.381 ;
     RECT  6.336 37.625 6.426 38.395 ;
     RECT  7.272 38.155 15.426 38.395 ;
     RECT  6.336 38.395 15.426 38.435 ;
     RECT  2.304 37.589 2.79 38.443 ;
     RECT  3.528 38.129 5.397 38.443 ;
     RECT  6.408 38.435 15.426 38.543 ;
     RECT  2.304 38.443 5.397 38.705 ;
     RECT  6.408 38.543 13.914 38.705 ;
     RECT  6.516 38.705 13.914 38.717 ;
     RECT  2.304 38.705 2.934 38.827 ;
     RECT  14.832 38.543 15.426 38.983 ;
     RECT  2.196 38.827 2.934 39.053 ;
     RECT  16.524 38.779 16.542 39.083 ;
     RECT  14.832 38.983 15.462 39.211 ;
     RECT  14.832 39.211 15.498 39.317 ;
     RECT  14.832 39.317 15.462 39.341 ;
     RECT  2.304 39.053 2.934 39.479 ;
     RECT  2.34 39.479 2.934 39.523 ;
     RECT  3.708 38.705 5.397 39.523 ;
     RECT  6.516 38.717 13.698 39.547 ;
     RECT  2.34 39.523 5.397 39.551 ;
     RECT  6.516 39.547 13.842 39.631 ;
     RECT  2.412 39.551 5.397 39.749 ;
     RECT  6.516 39.631 14.094 39.749 ;
     RECT  6.516 39.749 6.57 39.784 ;
     RECT  7.416 39.749 14.094 39.785 ;
     RECT  6.444 39.784 6.57 39.821 ;
     RECT  7.632 39.785 14.094 39.821 ;
     RECT  2.412 39.749 2.934 39.893 ;
     RECT  3.852 39.749 5.397 39.991 ;
     RECT  0.252 39.979 0.27 40.109 ;
     RECT  1.368 39.883 1.386 40.109 ;
     RECT  3.852 39.991 5.634 40.109 ;
     RECT  6.552 39.821 6.57 40.109 ;
     RECT  14.832 39.341 15.03 40.109 ;
     RECT  7.632 39.821 13.914 40.289 ;
     RECT  14.868 40.109 15.03 40.333 ;
     RECT  1.152 40.315 1.278 40.445 ;
     RECT  1.152 40.445 1.17 40.469 ;
     RECT  2.412 39.893 2.898 40.507 ;
     RECT  7.632 40.289 11.178 40.531 ;
     RECT  2.304 40.507 2.898 40.651 ;
     RECT  3.852 40.109 4.014 40.651 ;
     RECT  5.04 40.109 5.634 40.675 ;
     RECT  5.04 40.675 6.138 40.829 ;
     RECT  0.396 40.747 0.414 40.843 ;
     RECT  0.288 40.843 0.414 40.877 ;
     RECT  6.12 40.829 6.138 40.909 ;
     RECT  6.948 40.531 11.178 40.909 ;
     RECT  0.288 40.877 0.306 40.973 ;
     RECT  2.304 40.651 4.014 41.071 ;
     RECT  5.04 40.829 5.397 41.071 ;
     RECT  14.868 40.333 15.426 41.083 ;
     RECT  2.304 41.071 5.397 41.099 ;
     RECT  14.868 41.083 15.462 41.143 ;
     RECT  14.688 41.143 15.462 41.171 ;
     RECT  6.12 40.909 11.178 41.179 ;
     RECT  12.096 40.289 13.914 41.179 ;
     RECT  0.252 41.035 0.27 41.213 ;
     RECT  6.12 41.179 13.914 41.251 ;
     RECT  14.688 41.171 15.426 41.251 ;
     RECT  6.12 41.251 15.426 41.513 ;
     RECT  3.96 41.099 5.397 41.683 ;
     RECT  3.96 41.683 6.03 41.783 ;
     RECT  16.524 39.835 16.542 41.783 ;
     RECT  2.304 41.099 3.114 41.881 ;
     RECT  3.96 41.783 4.302 41.881 ;
     RECT  6.804 41.513 15.426 42.043 ;
     RECT  6.804 42.043 15.462 42.179 ;
     RECT  0.54 42.025 0.558 42.221 ;
     RECT  14.688 42.179 15.462 42.251 ;
     RECT  5.115 41.783 6.03 42.259 ;
     RECT  6.804 42.179 13.914 42.259 ;
     RECT  14.832 42.251 15.462 42.557 ;
     RECT  0.216 42.601 0.234 42.653 ;
     RECT  2.304 41.881 4.302 42.691 ;
     RECT  5.115 42.259 13.914 42.691 ;
     RECT  2.304 42.691 13.914 43.061 ;
     RECT  3.924 43.061 13.914 43.141 ;
     RECT  14.832 42.557 14.85 43.141 ;
     RECT  15.984 42.727 16.002 43.295 ;
     RECT  3.924 43.141 14.85 43.325 ;
     RECT  6.264 43.325 14.85 43.573 ;
     RECT  0.252 43.579 0.27 43.709 ;
     RECT  6.264 43.573 14.886 43.709 ;
     RECT  2.304 43.061 3.186 43.771 ;
     RECT  6.408 43.709 14.886 43.799 ;
     RECT  6.696 43.799 13.95 43.871 ;
     RECT  14.832 43.799 14.886 43.871 ;
     RECT  16.524 43.411 16.542 44.107 ;
     RECT  2.196 43.771 3.186 44.221 ;
     RECT  3.924 43.325 5.397 44.221 ;
     RECT  2.196 44.221 5.397 44.429 ;
     RECT  2.304 44.429 5.397 44.491 ;
     RECT  2.304 44.491 5.49 44.609 ;
     RECT  7.344 43.871 13.95 44.681 ;
     RECT  15.408 44.251 15.426 44.681 ;
     RECT  2.304 44.609 2.934 44.789 ;
     RECT  2.304 44.789 2.862 44.909 ;
     RECT  3.816 44.609 5.397 45.005 ;
     RECT  6.588 44.581 6.606 45.019 ;
     RECT  6.516 45.019 6.606 45.115 ;
     RECT  7.344 44.681 13.914 45.115 ;
     RECT  16.524 44.107 16.578 45.163 ;
     RECT  6.516 45.115 13.914 45.259 ;
     RECT  16.524 45.163 16.614 45.293 ;
     RECT  14.832 44.875 14.886 45.403 ;
     RECT  6.444 45.259 13.914 45.427 ;
     RECT  0.252 44.491 0.27 45.485 ;
     RECT  14.832 45.403 15.426 45.499 ;
     RECT  2.304 44.909 2.826 45.527 ;
     RECT  6.372 45.427 13.914 45.581 ;
     RECT  6.444 45.581 13.914 45.599 ;
     RECT  16.524 45.293 16.542 45.629 ;
     RECT  3.816 45.005 4.158 45.661 ;
     RECT  0.54 45.499 0.558 45.677 ;
     RECT  3.636 45.661 4.158 45.733 ;
     RECT  14.832 45.499 15.462 45.761 ;
     RECT  2.304 45.527 2.79 45.835 ;
     RECT  6.804 45.599 13.914 45.869 ;
     RECT  6.804 45.869 13.842 45.959 ;
     RECT  3.6 45.733 4.158 45.979 ;
     RECT  5.115 45.005 5.397 45.979 ;
     RECT  6.804 45.959 11.358 46.067 ;
     RECT  3.6 45.979 5.397 46.229 ;
     RECT  12.384 45.959 13.842 46.253 ;
     RECT  2.268 45.835 2.79 46.471 ;
     RECT  3.6 46.229 4.086 46.471 ;
     RECT  15.984 46.315 16.002 46.555 ;
     RECT  15.948 46.555 16.002 46.643 ;
     RECT  12.492 46.253 13.842 46.651 ;
     RECT  14.832 45.761 14.886 46.651 ;
     RECT  2.268 46.471 4.086 46.679 ;
     RECT  7.056 46.067 11.358 46.813 ;
     RECT  7.056 46.813 11.61 46.885 ;
     RECT  12.492 46.651 13.914 46.885 ;
     RECT  14.832 46.651 15.426 46.885 ;
     RECT  5.076 46.229 5.397 46.921 ;
     RECT  5.076 46.921 5.454 47.011 ;
     RECT  0.252 46.843 0.27 47.021 ;
     RECT  6.804 46.885 11.61 47.155 ;
     RECT  6.804 47.155 11.718 47.191 ;
     RECT  12.492 46.885 15.426 47.191 ;
     RECT  0.54 47.281 0.558 47.357 ;
     RECT  6.804 47.191 15.426 47.419 ;
     RECT  5.076 47.011 5.742 47.425 ;
     RECT  6.768 47.419 15.426 47.579 ;
     RECT  4.932 47.425 5.742 47.587 ;
     RECT  6.768 47.579 13.842 47.587 ;
     RECT  17.064 47.563 17.082 47.587 ;
     RECT  17.064 47.587 17.154 47.645 ;
     RECT  2.304 46.679 4.086 47.707 ;
     RECT  4.932 47.587 13.842 47.707 ;
     RECT  14.832 47.579 15.426 47.723 ;
     RECT  2.304 47.707 13.842 47.759 ;
     RECT  15.408 47.723 15.426 47.885 ;
     RECT  2.304 47.759 13.806 48.317 ;
     RECT  16.524 47.995 16.578 48.427 ;
     RECT  2.304 48.317 6.354 48.461 ;
     RECT  16.524 48.427 16.614 48.467 ;
     RECT  7.2 48.317 13.806 48.541 ;
     RECT  2.304 48.461 5.814 48.571 ;
     RECT  2.268 48.571 5.814 48.659 ;
     RECT  7.2 48.541 14.058 48.701 ;
     RECT  14.832 48.619 14.85 48.715 ;
     RECT  7.236 48.701 14.058 48.811 ;
     RECT  14.796 48.715 14.85 48.811 ;
     RECT  7.236 48.811 14.85 48.901 ;
     RECT  7.236 48.901 14.958 48.965 ;
     RECT  16.524 48.467 16.542 49.307 ;
     RECT  2.304 48.659 5.454 49.379 ;
     RECT  14.832 48.965 14.958 49.483 ;
     RECT  7.236 48.965 13.914 49.585 ;
     RECT  6.624 49.585 13.914 49.621 ;
     RECT  6.552 49.621 13.914 49.711 ;
     RECT  14.832 49.483 15.426 49.711 ;
     RECT  6.552 49.711 15.426 49.867 ;
     RECT  6.552 49.867 15.462 49.963 ;
     RECT  2.304 49.379 5.397 50.045 ;
     RECT  6.48 49.963 15.462 50.125 ;
     RECT  17.136 50.155 17.154 50.2 ;
     RECT  6.336 50.125 15.462 50.491 ;
     RECT  6.336 50.491 15.498 50.549 ;
     RECT  6.336 50.549 11.574 50.573 ;
     RECT  6.48 50.573 11.574 50.585 ;
     RECT  2.304 50.045 3.798 50.657 ;
     RECT  12.42 50.549 15.498 50.693 ;
     RECT  0.252 50.731 0.27 50.861 ;
     RECT  12.42 50.693 15.426 50.861 ;
     RECT  17.064 50.2 17.154 50.923 ;
     RECT  3.78 50.657 3.798 50.927 ;
     RECT  16.524 50.923 17.154 51.101 ;
     RECT  4.644 50.045 5.397 51.163 ;
     RECT  6.48 50.585 11.466 51.293 ;
     RECT  6.984 51.293 11.466 51.331 ;
     RECT  12.42 50.861 13.806 51.331 ;
     RECT  4.212 51.163 5.397 51.439 ;
     RECT  2.304 50.657 2.934 51.475 ;
     RECT  4.212 51.439 5.706 51.475 ;
     RECT  16.524 51.101 16.542 51.539 ;
     RECT  4.212 51.475 6.138 51.673 ;
     RECT  6.984 51.331 13.806 51.691 ;
     RECT  6.984 51.691 13.842 51.739 ;
     RECT  2.304 51.475 3.186 51.787 ;
     RECT  3.96 51.673 6.138 51.965 ;
     RECT  2.232 51.787 3.186 51.979 ;
     RECT  6.984 51.739 13.914 52.015 ;
     RECT  2.196 51.979 3.186 52.016 ;
     RECT  6.912 52.015 13.914 52.027 ;
     RECT  2.304 52.016 3.186 52.051 ;
     RECT  3.96 51.965 5.397 52.051 ;
     RECT  17.064 52.171 17.082 52.213 ;
     RECT  0.54 52.177 0.558 52.267 ;
     RECT  17.064 52.213 17.154 52.267 ;
     RECT  6.228 52.027 13.914 52.286 ;
     RECT  6.264 52.286 13.914 52.313 ;
     RECT  0.252 52.267 0.558 52.445 ;
     RECT  6.264 52.313 6.354 52.493 ;
     RECT  17.028 52.267 17.154 52.511 ;
     RECT  6.264 52.493 6.282 52.541 ;
     RECT  17.028 52.511 17.082 52.541 ;
     RECT  0.54 52.445 0.558 52.555 ;
     RECT  0.54 52.555 0.63 52.619 ;
     RECT  0.54 52.619 0.558 52.637 ;
     RECT  7.344 52.313 13.914 52.789 ;
     RECT  14.832 50.861 15.426 52.789 ;
     RECT  7.344 52.789 15.462 52.925 ;
     RECT  16.524 52.603 16.542 53.069 ;
     RECT  7.344 52.925 15.426 53.083 ;
     RECT  7.2 53.083 15.426 53.293 ;
     RECT  6.12 53.095 6.138 53.32 ;
     RECT  6.876 53.293 15.426 53.32 ;
     RECT  2.304 52.051 5.397 53.519 ;
     RECT  2.304 53.519 3.258 53.563 ;
     RECT  6.12 53.32 15.426 53.597 ;
     RECT  2.196 53.563 3.258 53.627 ;
     RECT  6.12 53.597 6.354 53.789 ;
     RECT  3.996 53.519 5.397 53.941 ;
     RECT  6.12 53.789 6.174 53.941 ;
     RECT  3.996 53.941 6.174 54.029 ;
     RECT  2.304 53.627 3.258 54.059 ;
     RECT  4.032 54.029 6.174 54.059 ;
     RECT  7.2 53.597 15.426 54.103 ;
     RECT  7.2 54.103 16.002 54.131 ;
     RECT  14.832 54.131 16.002 54.221 ;
     RECT  17.064 54.379 17.082 54.409 ;
     RECT  2.304 54.059 3.186 54.481 ;
     RECT  2.268 54.481 3.186 54.557 ;
     RECT  4.212 54.059 5.814 54.599 ;
     RECT  7.2 54.131 14.094 54.599 ;
     RECT  7.2 54.599 13.77 54.607 ;
     RECT  2.304 54.557 3.186 54.841 ;
     RECT  2.304 54.841 3.474 54.904 ;
     RECT  17.064 54.409 17.154 54.907 ;
     RECT  6.984 54.607 13.77 54.955 ;
     RECT  4.968 54.599 5.814 54.977 ;
     RECT  6.912 54.955 13.77 55.139 ;
     RECT  16.524 54.907 17.154 55.184 ;
     RECT  12.528 55.139 13.77 55.211 ;
     RECT  16.524 55.184 17.118 55.277 ;
     RECT  16.524 55.277 16.578 55.283 ;
     RECT  14.832 54.221 15.426 55.291 ;
     RECT  2.304 54.904 3.69 55.381 ;
     RECT  4.968 54.977 5.397 55.381 ;
     RECT  6.912 55.139 11.718 55.381 ;
     RECT  14.58 55.291 15.426 55.453 ;
     RECT  12.564 55.211 13.77 55.483 ;
     RECT  6.768 55.381 11.718 55.525 ;
     RECT  12.564 55.483 13.842 55.561 ;
     RECT  14.58 55.453 15.498 55.561 ;
     RECT  2.304 55.381 3.798 55.589 ;
     RECT  6.696 55.525 11.718 55.709 ;
     RECT  12.564 55.561 15.498 55.723 ;
     RECT  4.788 55.381 5.397 55.787 ;
     RECT  12.564 55.723 16.002 55.859 ;
     RECT  5.115 55.787 5.397 55.915 ;
     RECT  2.304 55.589 3.078 55.949 ;
     RECT  3.96 55.651 4.014 55.963 ;
     RECT  7.344 55.709 11.718 56.011 ;
     RECT  12.564 55.859 13.734 56.011 ;
     RECT  17.136 56.011 17.154 56.029 ;
     RECT  17.064 56.029 17.154 56.057 ;
     RECT  17.064 56.057 17.082 56.093 ;
     RECT  5.115 55.915 5.49 56.129 ;
     RECT  14.58 55.859 16.002 56.155 ;
     RECT  14.58 56.155 16.542 56.255 ;
     RECT  6.264 55.993 6.426 56.381 ;
     RECT  7.344 56.011 13.734 56.641 ;
     RECT  14.58 56.255 16.002 56.641 ;
     RECT  3.96 55.963 4.266 56.731 ;
     RECT  5.115 56.129 5.397 56.731 ;
     RECT  2.304 55.949 2.862 56.779 ;
     RECT  3.96 56.731 5.397 56.779 ;
     RECT  2.304 56.779 5.397 56.939 ;
     RECT  6.192 56.827 6.21 57.065 ;
     RECT  7.344 56.641 16.002 57.101 ;
     RECT  0.252 56.251 0.27 57.181 ;
     RECT  17.136 57.163 17.154 57.181 ;
     RECT  2.304 56.939 4.338 57.209 ;
     RECT  17.064 57.181 17.154 57.209 ;
     RECT  17.064 57.209 17.082 57.245 ;
     RECT  2.304 57.209 4.23 57.299 ;
     RECT  5.076 56.939 5.397 57.299 ;
     RECT  7.344 57.101 14.922 57.343 ;
     RECT  5.115 57.299 5.397 57.415 ;
     RECT  0.252 57.181 0.558 57.437 ;
     RECT  6.732 57.343 14.922 57.443 ;
     RECT  5.115 57.415 5.67 57.605 ;
     RECT  0.54 57.437 0.558 57.677 ;
     RECT  16.524 57.379 16.614 57.677 ;
     RECT  16.596 57.677 16.614 57.713 ;
     RECT  6.804 57.443 14.922 57.835 ;
     RECT  2.304 57.299 4.014 58.153 ;
     RECT  2.304 58.153 4.122 58.351 ;
     RECT  5.115 57.605 5.397 58.351 ;
     RECT  6.804 57.835 15.426 58.379 ;
     RECT  14.832 58.379 15.426 58.487 ;
     RECT  14.832 58.487 15.39 58.493 ;
     RECT  6.804 58.379 13.914 58.699 ;
     RECT  0.54 58.621 0.558 58.733 ;
     RECT  6.552 58.699 13.914 58.765 ;
     RECT  2.304 58.351 5.397 58.919 ;
     RECT  6.48 58.765 13.914 58.927 ;
     RECT  6.3 58.927 13.914 58.955 ;
     RECT  4.14 58.919 5.397 58.963 ;
     RECT  6.3 58.955 6.318 58.963 ;
     RECT  7.272 58.955 13.914 58.973 ;
     RECT  0.468 58.891 0.486 58.987 ;
     RECT  0.288 58.987 0.486 59.021 ;
     RECT  4.14 58.963 6.318 59.069 ;
     RECT  16.56 58.699 16.578 59.083 ;
     RECT  0.288 59.021 0.414 59.099 ;
     RECT  0.288 59.099 0.342 59.117 ;
     RECT  4.14 59.069 5.958 59.189 ;
     RECT  0.288 59.117 0.306 59.261 ;
     RECT  7.308 58.973 13.914 59.261 ;
     RECT  7.452 59.261 13.914 59.341 ;
     RECT  16.524 59.083 16.578 59.405 ;
     RECT  4.14 59.189 5.598 59.459 ;
     RECT  7.452 59.341 14.058 59.611 ;
     RECT  14.832 58.493 15.03 59.611 ;
     RECT  7.452 59.611 15.03 59.801 ;
     RECT  2.304 58.919 2.97 59.881 ;
     RECT  4.14 59.459 5.397 59.881 ;
     RECT  7.452 59.801 12.186 60.007 ;
     RECT  7.344 60.007 12.186 60.043 ;
     RECT  16.524 59.405 16.542 60.235 ;
     RECT  6.804 60.043 12.186 60.241 ;
     RECT  6.48 60.241 12.186 60.277 ;
     RECT  16.524 60.235 17.082 60.277 ;
     RECT  12.96 59.801 15.03 60.313 ;
     RECT  6.3 60.277 12.186 60.317 ;
     RECT  2.304 59.881 5.397 60.539 ;
     RECT  6.408 60.317 12.186 60.583 ;
     RECT  12.96 60.313 15.426 60.583 ;
     RECT  6.408 60.583 15.426 60.653 ;
     RECT  16.524 60.277 17.154 60.683 ;
     RECT  4.608 60.539 5.397 60.809 ;
     RECT  7.344 60.653 15.426 60.809 ;
     RECT  6.408 60.653 6.426 60.893 ;
     RECT  17.064 60.683 17.154 61.133 ;
     RECT  7.344 60.809 14.094 61.349 ;
     RECT  2.304 60.539 3.87 61.465 ;
     RECT  5.115 60.809 5.397 61.627 ;
     RECT  7.344 61.349 14.058 61.675 ;
     RECT  2.304 61.465 4.266 61.699 ;
     RECT  5.04 61.627 5.397 61.699 ;
     RECT  2.304 61.699 5.397 61.723 ;
     RECT  6.876 61.675 14.058 61.735 ;
     RECT  6.732 61.735 14.058 61.961 ;
     RECT  14.832 60.809 15.426 62.107 ;
     RECT  14.832 62.107 15.462 62.303 ;
     RECT  2.304 61.723 5.922 62.509 ;
     RECT  6.732 61.961 13.914 62.509 ;
     RECT  2.304 62.509 13.914 62.573 ;
     RECT  0.252 60.811 0.27 62.669 ;
     RECT  2.304 62.573 5.814 62.699 ;
     RECT  6.804 62.573 13.914 62.779 ;
     RECT  14.832 62.303 14.886 62.779 ;
     RECT  16.524 61.771 16.542 63.019 ;
     RECT  6.804 62.779 14.886 63.041 ;
     RECT  16.524 63.019 17.154 63.077 ;
     RECT  2.304 62.699 5.742 63.101 ;
     RECT  16.524 63.077 17.082 63.101 ;
     RECT  16.524 63.101 16.542 63.247 ;
     RECT  2.304 63.101 5.49 63.275 ;
     RECT  0.54 63.211 0.594 63.293 ;
     RECT  15.984 63.247 16.542 63.293 ;
     RECT  0.576 63.293 0.594 63.389 ;
     RECT  6.804 63.041 14.85 63.499 ;
     RECT  6.228 63.499 14.85 63.779 ;
     RECT  6.228 63.779 13.95 63.821 ;
     RECT  6.228 63.821 13.842 63.851 ;
     RECT  5.115 63.275 5.49 63.859 ;
     RECT  14.688 63.779 14.85 63.883 ;
     RECT  14.688 63.883 15.426 64.075 ;
     RECT  14.688 64.075 15.462 64.121 ;
     RECT  2.304 63.275 4.266 64.123 ;
     RECT  5.115 63.859 5.814 64.123 ;
     RECT  2.304 64.123 5.814 64.319 ;
     RECT  0.54 64.291 0.558 64.445 ;
     RECT  14.688 64.121 15.426 64.697 ;
     RECT  2.304 64.319 5.397 64.747 ;
     RECT  2.268 64.747 5.397 64.859 ;
     RECT  6.804 63.851 13.842 64.939 ;
     RECT  15.408 64.697 15.426 65.035 ;
     RECT  2.304 64.859 5.397 65.131 ;
     RECT  2.304 65.131 5.778 65.201 ;
     RECT  15.408 65.035 15.462 65.201 ;
     RECT  6.804 64.939 14.274 65.399 ;
     RECT  6.804 65.399 13.914 65.453 ;
     RECT  15.408 65.201 15.426 65.507 ;
     RECT  0.54 65.443 0.558 65.597 ;
     RECT  6.804 65.453 13.497 65.821 ;
     RECT  2.304 65.201 5.397 65.947 ;
     RECT  6.768 65.821 13.497 65.947 ;
     RECT  6.552 65.947 13.497 65.984 ;
     RECT  2.016 65.947 5.397 66.125 ;
     RECT  14.832 65.563 15.03 66.125 ;
     RECT  6.66 65.984 13.497 66.283 ;
     RECT  6.66 66.283 13.842 66.361 ;
     RECT  14.832 66.125 14.994 66.361 ;
     RECT  2.268 66.125 5.397 66.389 ;
     RECT  2.268 66.389 3.438 66.413 ;
     RECT  2.304 66.413 3.438 66.479 ;
     RECT  0.252 66.475 0.27 66.653 ;
     RECT  16.524 63.293 16.542 66.856 ;
     RECT  16.524 66.856 17.154 66.893 ;
     RECT  16.524 66.893 17.082 66.941 ;
     RECT  6.66 66.361 14.994 67.003 ;
     RECT  6.66 67.003 15.426 67.019 ;
     RECT  4.212 66.389 5.397 67.261 ;
     RECT  4.14 67.261 5.397 67.297 ;
     RECT  4.14 67.297 5.706 67.333 ;
     RECT  6.66 67.019 13.914 67.333 ;
     RECT  2.304 66.479 3.402 67.441 ;
     RECT  4.14 67.333 13.914 67.441 ;
     RECT  16.524 66.941 16.614 67.667 ;
     RECT  2.304 67.441 13.914 67.709 ;
     RECT  2.304 67.709 5.742 67.739 ;
     RECT  14.832 67.019 15.426 67.867 ;
     RECT  6.768 67.709 13.914 67.873 ;
     RECT  14.832 67.867 15.462 67.873 ;
     RECT  3.42 67.739 5.742 67.901 ;
     RECT  2.304 67.739 2.697 68.059 ;
     RECT  6.768 67.873 15.498 68.093 ;
     RECT  2.268 68.059 2.697 68.171 ;
     RECT  6.768 68.093 15.462 68.243 ;
     RECT  16.524 67.667 16.578 68.429 ;
     RECT  2.304 68.171 2.697 68.521 ;
     RECT  3.42 67.901 5.454 68.521 ;
     RECT  0.54 67.801 0.558 68.525 ;
     RECT  16.56 68.429 16.578 68.621 ;
     RECT  2.304 68.521 5.454 68.639 ;
     RECT  6.768 68.243 15.426 69.025 ;
     RECT  6.48 69.025 15.426 69.061 ;
     RECT  2.304 68.639 5.397 69.115 ;
     RECT  6.444 69.061 15.426 69.179 ;
     RECT  2.268 69.115 5.397 69.287 ;
     RECT  6.444 69.179 13.842 69.307 ;
     RECT  6.228 69.307 13.842 69.449 ;
     RECT  6.228 69.449 6.246 69.521 ;
     RECT  0.54 69.493 0.558 69.677 ;
     RECT  2.304 69.287 5.397 69.835 ;
     RECT  6.984 69.449 13.842 69.961 ;
     RECT  2.304 69.835 5.814 70.025 ;
     RECT  6.984 69.961 13.914 70.109 ;
     RECT  3.708 70.025 5.814 70.303 ;
     RECT  14.832 69.179 15.426 70.363 ;
     RECT  2.304 70.025 2.862 70.501 ;
     RECT  14.436 70.363 15.426 70.529 ;
     RECT  6.984 70.109 13.698 70.555 ;
     RECT  2.196 70.501 2.862 70.589 ;
     RECT  14.832 70.529 15.426 70.601 ;
     RECT  0.252 70.699 0.27 70.877 ;
     RECT  17.136 70.843 17.154 70.879 ;
     RECT  3.708 70.303 6.03 70.915 ;
     RECT  6.804 70.555 13.698 70.915 ;
     RECT  3.708 70.915 13.698 70.951 ;
     RECT  3.708 70.951 13.734 71.069 ;
     RECT  4.788 71.069 13.734 71.105 ;
     RECT  0.288 70.987 0.45 71.117 ;
     RECT  2.304 70.589 2.862 71.131 ;
     RECT  3.708 71.069 4.014 71.131 ;
     RECT  17.064 70.879 17.154 71.179 ;
     RECT  0.288 71.117 0.378 71.213 ;
     RECT  0.36 71.213 0.378 71.261 ;
     RECT  14.832 70.601 14.886 71.323 ;
     RECT  14.832 71.323 15.426 71.413 ;
     RECT  16.524 71.179 17.154 71.519 ;
     RECT  16.524 71.519 17.082 71.549 ;
     RECT  6.12 71.105 13.734 71.581 ;
     RECT  14.832 71.413 15.462 71.681 ;
     RECT  14.868 71.681 15.462 71.707 ;
     RECT  16.524 71.549 16.578 71.707 ;
     RECT  6.12 71.581 13.842 71.717 ;
     RECT  14.868 71.707 16.578 71.987 ;
     RECT  2.304 71.131 4.014 71.995 ;
     RECT  4.788 71.105 5.397 71.995 ;
     RECT  16.524 71.987 16.578 72.077 ;
     RECT  14.868 71.987 15.426 72.523 ;
     RECT  2.304 71.995 5.397 72.535 ;
     RECT  6.228 71.717 13.842 72.535 ;
     RECT  2.304 72.535 13.842 72.763 ;
     RECT  14.832 72.523 15.426 72.763 ;
     RECT  2.304 72.763 15.426 72.833 ;
     RECT  0.288 72.811 0.306 72.859 ;
     RECT  5.115 72.833 15.426 72.959 ;
     RECT  16.524 72.077 16.542 72.995 ;
     RECT  0.216 72.859 0.306 73.195 ;
     RECT  5.115 72.959 6.138 73.229 ;
     RECT  17.064 73.195 17.082 73.237 ;
     RECT  17.064 73.237 17.154 73.265 ;
     RECT  17.136 73.265 17.154 73.277 ;
     RECT  6.876 72.959 15.426 73.301 ;
     RECT  0.216 73.195 0.414 73.325 ;
     RECT  2.304 72.833 4.302 73.325 ;
     RECT  9.036 73.301 15.426 73.325 ;
     RECT  0.216 73.325 0.342 73.337 ;
     RECT  9.036 73.325 14.886 73.337 ;
     RECT  0.324 73.337 0.342 73.373 ;
     RECT  2.304 73.325 3.402 73.373 ;
     RECT  9.036 73.337 14.85 73.373 ;
     RECT  6.876 73.301 8.262 73.379 ;
     RECT  6.876 73.379 6.93 73.382 ;
     RECT  2.304 73.373 3.186 73.409 ;
     RECT  7.815 73.379 8.262 73.409 ;
     RECT  10.515 73.373 14.85 73.409 ;
     RECT  2.304 73.409 2.505 73.421 ;
     RECT  12.276 73.409 14.85 73.421 ;
     RECT  2.415 73.421 2.505 73.457 ;
     RECT  5.115 73.229 5.205 73.457 ;
     RECT  7.815 73.409 7.905 73.457 ;
     RECT  10.515 73.409 10.926 73.457 ;
     RECT  12.276 73.421 14.166 73.457 ;
     RECT  4.284 73.325 4.302 73.499 ;
     RECT  10.656 73.457 10.926 73.499 ;
     RECT  12.276 73.457 12.726 73.499 ;
     RECT  13.716 73.457 14.166 73.499 ;
     RECT  6.912 73.382 6.93 73.535 ;
     RECT  9.036 73.373 9.558 73.535 ;
     RECT  14.148 73.499 14.166 73.535 ;
    LAYER M4 ;
     RECT  0.192 2.208 2.408 2.232 ;
     RECT  0.156 2.232 2.408 2.352 ;
     RECT  0.192 2.352 2.408 2.376 ;
     RECT  0.156 2.376 2.408 2.448 ;
     RECT  0.192 2.448 2.408 2.472 ;
     RECT  0.156 2.472 2.408 2.544 ;
     RECT  0.192 2.544 2.408 2.568 ;
     RECT  0.156 2.568 2.408 2.64 ;
     RECT  0.192 2.64 2.408 2.664 ;
     RECT  0.156 2.664 2.408 2.736 ;
     RECT  0.192 2.736 2.408 2.76 ;
     RECT  0.156 2.76 2.408 2.832 ;
     RECT  0.192 2.832 2.408 2.856 ;
     RECT  0.156 2.856 2.408 2.976 ;
     RECT  0.192 2.976 2.408 3 ;
     RECT  0.156 3 2.408 3.072 ;
     RECT  0.192 3.072 2.408 3.096 ;
     RECT  0.156 3.096 2.408 3.168 ;
     RECT  0.192 3.168 2.408 3.192 ;
     RECT  0.156 3.192 2.408 3.264 ;
     RECT  0.192 3.264 2.408 3.288 ;
     RECT  0.156 3.288 2.408 3.36 ;
     RECT  0.192 3.36 2.408 3.384 ;
     RECT  0.156 3.384 2.408 3.456 ;
     RECT  0.192 3.456 2.408 3.48 ;
     RECT  0.156 3.48 2.408 3.6 ;
     RECT  0.192 3.6 2.408 3.624 ;
     RECT  0.156 3.624 2.408 3.696 ;
     RECT  0.192 3.696 2.408 3.72 ;
     RECT  0.156 3.72 2.408 3.792 ;
     RECT  0.192 3.792 2.408 3.816 ;
     RECT  0.156 3.816 2.408 3.888 ;
     RECT  0.192 3.888 2.408 3.912 ;
     RECT  0.156 3.912 2.408 3.984 ;
     RECT  0.192 3.984 2.408 4.008 ;
     RECT  0.156 4.008 2.408 4.08 ;
     RECT  0.192 4.08 2.408 4.104 ;
     RECT  0.156 4.104 2.408 4.224 ;
     RECT  0.192 4.224 2.408 4.248 ;
     RECT  0.156 4.248 2.408 4.32 ;
     RECT  0.192 4.32 2.408 4.344 ;
     RECT  0.156 4.344 2.408 4.416 ;
     RECT  0.192 4.416 2.408 4.44 ;
     RECT  0.156 4.44 2.408 4.512 ;
     RECT  0.192 4.512 2.408 4.536 ;
     RECT  0.156 4.536 2.408 4.608 ;
     RECT  0.192 4.608 2.408 4.632 ;
     RECT  0.156 4.632 2.408 4.752 ;
     RECT  0.192 4.752 2.408 4.776 ;
     RECT  0.156 4.776 2.408 4.848 ;
     RECT  0.192 4.848 2.408 4.872 ;
     RECT  0.156 4.872 2.408 4.944 ;
     RECT  0.192 4.944 2.408 4.968 ;
     RECT  0.156 4.968 2.408 5.04 ;
     RECT  0.192 5.04 2.408 5.064 ;
     RECT  0.156 5.064 2.408 5.136 ;
     RECT  0.192 5.136 2.408 5.16 ;
     RECT  0.156 5.16 2.408 5.232 ;
     RECT  0.192 5.232 2.408 5.256 ;
     RECT  0.156 5.256 2.408 5.376 ;
     RECT  0.192 5.376 2.408 5.4 ;
     RECT  0.156 5.4 2.408 5.472 ;
     RECT  0.192 5.472 2.408 5.496 ;
     RECT  0.156 5.496 2.408 5.568 ;
     RECT  0.192 5.568 2.408 5.592 ;
     RECT  0.156 5.592 2.408 5.664 ;
     RECT  0.192 5.664 2.408 5.688 ;
     RECT  0.156 5.688 2.408 5.76 ;
     RECT  0.192 5.76 2.408 5.784 ;
     RECT  0.156 5.784 2.408 5.856 ;
     RECT  0.192 5.856 2.408 5.88 ;
     RECT  0.156 5.88 2.408 6 ;
     RECT  0.192 6 2.408 6.024 ;
     RECT  0.156 6.024 2.408 6.096 ;
     RECT  0.192 6.096 2.408 6.12 ;
     RECT  0.156 6.12 2.408 6.192 ;
     RECT  0.192 6.192 2.408 6.216 ;
     RECT  0.156 6.216 2.408 6.288 ;
     RECT  0.192 6.288 2.408 6.312 ;
     RECT  0.156 6.312 2.408 6.384 ;
     RECT  0.192 6.384 2.408 6.408 ;
     RECT  0.156 6.408 2.408 6.48 ;
     RECT  0.192 6.48 2.408 6.504 ;
     RECT  0.156 6.504 2.408 6.624 ;
     RECT  0.192 6.624 2.408 6.648 ;
     RECT  0.156 6.648 2.408 6.72 ;
     RECT  0.192 6.72 2.408 6.744 ;
     RECT  0.156 6.744 2.408 6.816 ;
     RECT  0.192 6.816 2.408 6.84 ;
     RECT  0.156 6.84 2.408 6.912 ;
     RECT  0.192 6.912 2.408 6.936 ;
     RECT  0.156 6.936 2.408 7.008 ;
     RECT  0.192 7.008 2.408 7.032 ;
     RECT  0.156 7.032 2.408 7.152 ;
     RECT  0.192 7.152 2.408 7.176 ;
     RECT  0.156 7.176 2.408 7.248 ;
     RECT  0.192 7.248 2.408 7.272 ;
     RECT  0.156 7.272 2.408 7.344 ;
     RECT  0.192 7.344 2.408 7.368 ;
     RECT  0.156 7.368 2.408 7.44 ;
     RECT  0.192 7.44 2.408 7.464 ;
     RECT  0.156 7.464 2.408 7.536 ;
     RECT  0.192 7.536 2.408 7.56 ;
     RECT  0.156 7.56 2.408 7.632 ;
     RECT  0.192 7.632 2.408 7.656 ;
     RECT  0.156 7.656 2.408 7.776 ;
     RECT  0.192 7.776 2.408 7.8 ;
     RECT  0.156 7.8 2.408 7.872 ;
     RECT  0.192 7.872 2.408 7.896 ;
     RECT  0.156 7.896 2.408 7.968 ;
     RECT  0.192 7.968 2.408 7.992 ;
     RECT  0.156 7.992 2.408 8.064 ;
     RECT  0.192 8.064 2.408 8.088 ;
     RECT  0.156 8.088 2.408 8.16 ;
     RECT  0.192 8.16 2.408 8.184 ;
     RECT  0.156 8.184 2.408 8.256 ;
     RECT  0.192 8.256 2.408 8.28 ;
     RECT  0.156 8.28 2.408 8.4 ;
     RECT  0.192 8.4 2.408 8.424 ;
     RECT  0.156 8.424 2.408 8.496 ;
     RECT  0.192 8.496 2.408 8.52 ;
     RECT  0.156 8.52 2.408 8.592 ;
     RECT  0.192 8.592 2.408 8.616 ;
     RECT  0.156 8.616 2.408 8.688 ;
     RECT  0.192 8.688 2.408 8.712 ;
     RECT  0.156 8.712 2.408 8.784 ;
     RECT  0.192 8.784 2.408 8.808 ;
     RECT  0.156 8.808 2.408 8.88 ;
     RECT  0.192 8.88 2.408 8.904 ;
     RECT  0.156 8.904 2.408 9.024 ;
     RECT  0.192 9.024 2.408 9.048 ;
     RECT  0.156 9.048 2.408 9.12 ;
     RECT  0.192 9.12 2.408 9.144 ;
     RECT  0.156 9.144 2.408 9.216 ;
     RECT  0.192 9.216 2.408 9.24 ;
     RECT  0.156 9.24 2.408 9.312 ;
     RECT  0.192 9.312 2.408 9.336 ;
     RECT  0.156 9.336 2.408 9.408 ;
     RECT  0.192 9.408 2.408 9.432 ;
     RECT  0.156 9.432 2.408 9.552 ;
     RECT  0.192 9.552 2.408 9.576 ;
     RECT  0.156 9.576 2.408 9.648 ;
     RECT  0.192 9.648 2.408 9.672 ;
     RECT  0.156 9.672 2.408 9.744 ;
     RECT  0.192 9.744 2.408 9.768 ;
     RECT  0.156 9.768 2.408 9.84 ;
     RECT  0.192 9.84 2.408 9.864 ;
     RECT  0.156 9.864 2.408 9.936 ;
     RECT  0.192 9.936 2.408 9.96 ;
     RECT  0.156 9.96 2.408 10.032 ;
     RECT  0.192 10.032 2.408 10.056 ;
     RECT  0.156 10.056 2.408 10.176 ;
     RECT  0.192 10.176 2.408 10.2 ;
     RECT  0.156 10.2 2.408 10.272 ;
     RECT  0.192 10.272 2.408 10.296 ;
     RECT  0.156 10.296 2.408 10.368 ;
     RECT  0.192 10.368 2.408 10.392 ;
     RECT  0.156 10.392 2.408 10.464 ;
     RECT  0.192 10.464 2.408 10.488 ;
     RECT  0.156 10.488 2.408 10.56 ;
     RECT  0.192 10.56 2.408 10.584 ;
     RECT  0.156 10.584 2.408 10.656 ;
     RECT  0.192 10.656 2.408 10.68 ;
     RECT  0.156 10.68 2.408 10.8 ;
     RECT  0.192 10.8 2.408 10.824 ;
     RECT  0.156 10.824 2.408 10.896 ;
     RECT  0.192 10.896 2.408 10.92 ;
     RECT  0.156 10.92 2.408 10.992 ;
     RECT  0.192 10.992 2.408 11.016 ;
     RECT  0.156 11.016 2.408 11.088 ;
     RECT  0.192 11.088 2.408 11.112 ;
     RECT  0.156 11.112 2.408 11.184 ;
     RECT  0.192 11.184 2.408 11.208 ;
     RECT  0.156 11.208 2.408 11.28 ;
     RECT  0.192 11.28 2.408 11.304 ;
     RECT  0.156 11.304 2.408 11.424 ;
     RECT  0.192 11.424 2.408 11.448 ;
     RECT  0.156 11.448 2.408 11.52 ;
     RECT  0.192 11.52 2.408 11.544 ;
     RECT  0.156 11.544 2.408 11.616 ;
     RECT  0.192 11.616 2.408 11.64 ;
     RECT  0.156 11.64 2.408 11.712 ;
     RECT  0.192 11.712 2.408 11.736 ;
     RECT  0.156 11.736 2.408 11.808 ;
     RECT  0.192 11.808 2.408 11.832 ;
     RECT  0.156 11.832 2.408 11.952 ;
     RECT  0.192 11.952 2.408 11.976 ;
     RECT  0.156 11.976 2.408 12.048 ;
     RECT  0.192 12.048 2.408 12.072 ;
     RECT  0.156 12.072 2.408 12.144 ;
     RECT  0.192 12.144 2.408 12.168 ;
     RECT  0.156 12.168 2.408 12.24 ;
     RECT  0.192 12.24 2.408 12.264 ;
     RECT  0.156 12.264 2.408 12.336 ;
     RECT  0.192 12.336 2.408 12.36 ;
     RECT  0.156 12.36 2.408 12.432 ;
     RECT  0.192 12.432 2.408 12.456 ;
     RECT  0.156 12.456 2.408 12.576 ;
     RECT  0.192 12.576 2.408 12.6 ;
     RECT  0.156 12.6 2.408 12.672 ;
     RECT  0.192 12.672 2.408 12.696 ;
     RECT  0.156 12.696 2.408 12.768 ;
     RECT  0.192 12.768 2.408 12.792 ;
     RECT  0.156 12.792 2.408 12.864 ;
     RECT  0.192 12.864 2.408 12.888 ;
     RECT  0.156 12.888 2.408 12.96 ;
     RECT  0.192 12.96 2.408 12.984 ;
     RECT  0.156 12.984 2.408 13.056 ;
     RECT  0.192 13.056 2.408 13.08 ;
     RECT  0.156 13.08 2.408 13.2 ;
     RECT  0.192 13.2 2.408 13.224 ;
     RECT  0.156 13.224 2.408 13.296 ;
     RECT  0.192 13.296 2.408 13.32 ;
     RECT  0.156 13.32 2.408 13.392 ;
     RECT  0.192 13.392 2.408 13.416 ;
     RECT  0.156 13.416 2.408 13.488 ;
     RECT  0.192 13.488 2.408 13.512 ;
     RECT  0.156 13.512 2.408 13.584 ;
     RECT  0.192 13.584 2.408 13.608 ;
     RECT  0.156 13.608 2.408 13.728 ;
     RECT  0.192 13.728 2.408 13.752 ;
     RECT  0.156 13.752 2.408 13.824 ;
     RECT  0.192 13.824 2.408 13.848 ;
     RECT  0.156 13.848 2.408 13.92 ;
     RECT  0.192 13.92 2.408 13.944 ;
     RECT  0.156 13.944 2.408 14.016 ;
     RECT  0.192 14.016 2.408 14.04 ;
     RECT  0.156 14.04 2.408 14.112 ;
     RECT  0.192 14.112 2.408 14.136 ;
     RECT  0.156 14.136 2.408 14.208 ;
     RECT  0.192 14.208 2.408 14.232 ;
     RECT  0.156 14.232 2.408 14.352 ;
     RECT  0.192 14.352 2.408 14.376 ;
     RECT  0.156 14.376 2.408 14.448 ;
     RECT  0.192 14.448 2.408 14.472 ;
     RECT  0.156 14.472 2.408 14.544 ;
     RECT  0.192 14.544 2.408 14.568 ;
     RECT  0.156 14.568 2.408 14.64 ;
     RECT  0.192 14.64 2.408 14.664 ;
     RECT  0.156 14.664 2.408 14.736 ;
     RECT  0.192 14.736 2.408 14.76 ;
     RECT  0.156 14.76 2.408 14.832 ;
     RECT  0.192 14.832 2.408 14.856 ;
     RECT  0.156 14.856 2.408 14.976 ;
     RECT  0.192 14.976 2.408 15 ;
     RECT  0.156 15 2.408 15.072 ;
     RECT  0.192 15.072 2.408 15.096 ;
     RECT  0.156 15.096 2.408 15.168 ;
     RECT  0.192 15.168 2.408 15.192 ;
     RECT  0.156 15.192 2.408 15.264 ;
     RECT  0.192 15.264 2.408 15.288 ;
     RECT  0.156 15.288 2.408 15.36 ;
     RECT  0.192 15.36 2.408 15.384 ;
     RECT  0.156 15.384 2.408 15.456 ;
     RECT  0.192 15.456 2.408 15.48 ;
     RECT  0.156 15.48 2.408 15.6 ;
     RECT  0.192 15.6 2.408 15.624 ;
     RECT  0.156 15.624 2.408 15.696 ;
     RECT  0.192 15.696 2.408 15.72 ;
     RECT  0.156 15.72 2.408 15.792 ;
     RECT  0.192 15.792 2.408 15.816 ;
     RECT  0.156 15.816 2.408 15.888 ;
     RECT  0.192 15.888 2.408 15.912 ;
     RECT  0.156 15.912 2.408 15.984 ;
     RECT  0.192 15.984 2.408 16.008 ;
     RECT  0.156 16.008 2.408 16.128 ;
     RECT  0.192 16.128 2.408 16.152 ;
     RECT  0.156 16.152 2.408 16.224 ;
     RECT  0.192 16.224 2.408 16.248 ;
     RECT  0.156 16.248 2.408 16.32 ;
     RECT  0.192 16.32 2.408 16.344 ;
     RECT  0.156 16.344 2.408 16.416 ;
     RECT  0.192 16.416 2.408 16.44 ;
     RECT  0.156 16.44 2.408 16.512 ;
     RECT  0.192 16.512 2.408 16.536 ;
     RECT  0.156 16.536 2.408 16.608 ;
     RECT  0.192 16.608 2.408 16.632 ;
     RECT  0.156 16.632 2.408 16.752 ;
     RECT  0.192 16.752 2.408 16.776 ;
     RECT  0.156 16.776 2.408 16.848 ;
     RECT  0.192 16.848 2.408 16.872 ;
     RECT  0.156 16.872 2.408 16.944 ;
     RECT  0.192 16.944 2.408 16.968 ;
     RECT  0.156 16.968 2.408 17.04 ;
     RECT  0.192 17.04 2.408 17.064 ;
     RECT  0.156 17.064 2.408 17.136 ;
     RECT  0.192 17.136 2.408 17.16 ;
     RECT  0.156 17.16 2.408 17.232 ;
     RECT  0.192 17.232 2.408 17.256 ;
     RECT  0.156 17.256 2.408 17.376 ;
     RECT  0.192 17.376 2.408 17.4 ;
     RECT  0.156 17.4 2.408 17.472 ;
     RECT  0.192 17.472 2.408 17.496 ;
     RECT  0.156 17.496 2.408 17.568 ;
     RECT  0.192 17.568 2.408 17.592 ;
     RECT  0.156 17.592 2.408 17.664 ;
     RECT  0.192 17.664 2.408 17.688 ;
     RECT  0.156 17.688 2.408 17.76 ;
     RECT  0.192 17.76 2.408 17.784 ;
     RECT  0.156 17.784 2.408 17.856 ;
     RECT  0.192 17.856 2.408 17.88 ;
     RECT  0.156 17.88 2.408 18 ;
     RECT  0.192 18 2.408 18.024 ;
     RECT  0.156 18.024 2.408 18.096 ;
     RECT  0.192 18.096 2.408 18.12 ;
     RECT  0.156 18.12 2.408 18.192 ;
     RECT  0.192 18.192 2.408 18.216 ;
     RECT  0.156 18.216 2.408 18.288 ;
     RECT  0.192 18.288 2.408 18.312 ;
     RECT  0.156 18.312 2.408 18.384 ;
     RECT  0.192 18.384 2.408 18.408 ;
     RECT  0.156 18.408 2.408 18.528 ;
     RECT  0.192 18.528 2.408 18.552 ;
     RECT  0.156 18.552 2.408 18.624 ;
     RECT  0.192 18.624 2.408 18.648 ;
     RECT  0.156 18.648 2.408 18.72 ;
     RECT  0.192 18.72 2.408 18.744 ;
     RECT  0.156 18.744 2.408 18.816 ;
     RECT  0.192 18.816 2.408 18.84 ;
     RECT  0.156 18.84 2.408 18.912 ;
     RECT  0.192 18.912 2.408 18.936 ;
     RECT  0.156 18.936 2.408 19.008 ;
     RECT  0.192 19.008 2.408 19.032 ;
     RECT  0.156 19.032 2.408 19.152 ;
     RECT  0.192 19.152 2.408 19.176 ;
     RECT  0.156 19.176 2.408 19.248 ;
     RECT  0.192 19.248 2.408 19.272 ;
     RECT  0.156 19.272 2.408 19.344 ;
     RECT  0.192 19.344 2.408 19.368 ;
     RECT  0.156 19.368 2.408 19.44 ;
     RECT  0.192 19.44 2.408 19.464 ;
     RECT  0.156 19.464 2.408 19.536 ;
     RECT  0.192 19.536 2.408 19.56 ;
     RECT  0.156 19.56 2.408 19.632 ;
     RECT  0.192 19.632 2.408 19.656 ;
     RECT  0.156 19.656 2.408 19.776 ;
     RECT  0.192 19.776 2.408 19.8 ;
     RECT  0.156 19.8 2.408 19.872 ;
     RECT  0.192 19.872 2.408 19.896 ;
     RECT  0.156 19.896 2.408 19.968 ;
     RECT  0.192 19.968 2.408 19.992 ;
     RECT  0.156 19.992 2.408 20.064 ;
     RECT  0.192 20.064 2.408 20.088 ;
     RECT  0.156 20.088 2.408 20.16 ;
     RECT  0.192 20.16 2.408 20.184 ;
     RECT  0.156 20.184 2.408 20.256 ;
     RECT  0.192 20.256 2.408 20.28 ;
     RECT  0.156 20.28 2.408 20.4 ;
     RECT  0.192 20.4 2.408 20.424 ;
     RECT  0.156 20.424 2.408 20.496 ;
     RECT  0.192 20.496 2.408 20.52 ;
     RECT  0.156 20.52 2.408 20.592 ;
     RECT  0.192 20.592 2.408 20.616 ;
     RECT  0.156 20.616 2.408 20.688 ;
     RECT  0.192 20.688 2.408 20.712 ;
     RECT  0.156 20.712 2.408 20.784 ;
     RECT  0.192 20.784 2.408 20.808 ;
     RECT  0.156 20.808 2.408 20.928 ;
     RECT  0.192 20.928 2.408 20.952 ;
     RECT  0.156 20.952 2.408 21.024 ;
     RECT  0.192 21.024 2.408 21.048 ;
     RECT  0.156 21.048 2.408 21.12 ;
     RECT  0.192 21.12 2.408 21.144 ;
     RECT  0.156 21.144 2.408 21.216 ;
     RECT  0.192 21.216 2.408 21.24 ;
     RECT  0.156 21.24 2.408 21.312 ;
     RECT  0.192 21.312 2.408 21.336 ;
     RECT  0.156 21.336 2.408 21.408 ;
     RECT  0.192 21.408 2.408 21.432 ;
     RECT  0.156 21.432 2.408 21.552 ;
     RECT  0.192 21.552 2.408 21.576 ;
     RECT  0.156 21.576 2.408 21.648 ;
     RECT  0.192 21.648 2.408 21.672 ;
     RECT  0.156 21.672 2.408 21.744 ;
     RECT  0.192 21.744 2.408 21.768 ;
     RECT  0.156 21.768 2.408 21.84 ;
     RECT  0.192 21.84 2.408 21.864 ;
     RECT  0.156 21.864 2.408 21.936 ;
     RECT  0.192 21.936 2.408 21.96 ;
     RECT  0.156 21.96 2.408 22.032 ;
     RECT  0.192 22.032 2.408 22.056 ;
     RECT  0.156 22.056 2.408 22.176 ;
     RECT  0.192 22.176 2.408 22.2 ;
     RECT  0.156 22.2 2.408 22.272 ;
     RECT  0.192 22.272 2.408 22.296 ;
     RECT  0.156 22.296 2.408 22.368 ;
     RECT  0.192 22.368 2.408 22.392 ;
     RECT  0.156 22.392 2.408 22.464 ;
     RECT  0.192 22.464 2.408 22.488 ;
     RECT  0.156 22.488 2.408 22.56 ;
     RECT  0.192 22.56 2.408 22.584 ;
     RECT  0.156 22.584 2.408 22.656 ;
     RECT  0.192 22.656 2.408 22.68 ;
     RECT  0.156 22.68 2.408 22.8 ;
     RECT  0.192 22.8 2.408 22.824 ;
     RECT  0.156 22.824 2.408 22.896 ;
     RECT  0.192 22.896 2.408 22.92 ;
     RECT  0.156 22.92 2.408 22.992 ;
     RECT  0.192 22.992 2.408 23.016 ;
     RECT  0.156 23.016 2.408 23.088 ;
     RECT  0.192 23.088 2.408 23.112 ;
     RECT  0.156 23.112 2.408 23.184 ;
     RECT  0.192 23.184 2.408 23.208 ;
     RECT  0.156 23.208 2.408 23.328 ;
     RECT  0.192 23.328 2.408 23.352 ;
     RECT  0.156 23.352 2.408 23.424 ;
     RECT  0.192 23.424 2.408 23.448 ;
     RECT  0.156 23.448 2.408 23.52 ;
     RECT  0.192 23.52 2.408 23.544 ;
     RECT  0.156 23.544 2.408 23.616 ;
     RECT  0.192 23.616 2.408 23.64 ;
     RECT  0.156 23.64 2.408 23.712 ;
     RECT  0.192 23.712 2.408 23.736 ;
     RECT  0.156 23.736 2.408 23.808 ;
     RECT  0.192 23.808 2.408 23.832 ;
     RECT  0.156 23.832 2.408 23.952 ;
     RECT  0.192 23.952 2.408 23.976 ;
     RECT  0.156 23.976 2.408 24.048 ;
     RECT  0.192 24.048 2.408 24.072 ;
     RECT  0.156 24.072 2.408 24.144 ;
     RECT  0.192 24.144 2.408 24.168 ;
     RECT  0.156 24.168 2.408 24.24 ;
     RECT  0.192 24.24 2.408 24.264 ;
     RECT  0.156 24.264 2.408 24.336 ;
     RECT  0.192 24.336 2.408 24.36 ;
     RECT  0.156 24.36 2.408 24.432 ;
     RECT  0.192 24.432 2.408 24.456 ;
     RECT  0.156 24.456 2.408 24.576 ;
     RECT  0.192 24.576 2.408 24.6 ;
     RECT  0.156 24.6 2.408 24.672 ;
     RECT  0.192 24.672 2.408 24.696 ;
     RECT  0.156 24.696 2.408 24.768 ;
     RECT  0.192 24.768 2.408 24.792 ;
     RECT  0.156 24.792 2.408 24.864 ;
     RECT  0.192 24.864 2.408 24.888 ;
     RECT  0.156 24.888 2.408 24.96 ;
     RECT  0.192 24.96 2.408 24.984 ;
     RECT  0.156 24.984 2.408 25.056 ;
     RECT  0.192 25.056 2.408 25.08 ;
     RECT  0.156 25.08 2.408 25.2 ;
     RECT  0.192 25.2 2.408 25.224 ;
     RECT  0.156 25.224 2.408 25.296 ;
     RECT  0.192 25.296 2.408 25.32 ;
     RECT  0.156 25.32 2.408 25.392 ;
     RECT  0.192 25.392 2.408 25.416 ;
     RECT  0.156 25.416 2.408 25.488 ;
     RECT  0.192 25.488 2.408 25.512 ;
     RECT  0.156 25.512 2.408 25.584 ;
     RECT  0.192 25.584 2.408 25.608 ;
     RECT  0.156 25.608 2.408 25.728 ;
     RECT  0.192 25.728 2.408 25.752 ;
     RECT  0.156 25.752 2.408 25.824 ;
     RECT  0.192 25.824 2.408 25.848 ;
     RECT  0.156 25.848 2.408 25.92 ;
     RECT  0.192 25.92 2.408 25.944 ;
     RECT  0.156 25.944 2.408 26.016 ;
     RECT  0.192 26.016 2.408 26.04 ;
     RECT  0.156 26.04 2.408 26.112 ;
     RECT  0.192 26.112 2.408 26.136 ;
     RECT  0.156 26.136 2.408 26.208 ;
     RECT  0.192 26.208 2.408 26.232 ;
     RECT  0.156 26.232 2.408 26.352 ;
     RECT  0.192 26.352 2.408 26.376 ;
     RECT  0.156 26.376 2.408 26.448 ;
     RECT  0.192 26.448 2.408 26.472 ;
     RECT  0.156 26.472 2.408 26.544 ;
     RECT  0.192 26.544 2.408 26.568 ;
     RECT  0.156 26.568 2.408 26.64 ;
     RECT  0.192 26.64 2.408 26.664 ;
     RECT  0.156 26.664 2.408 26.736 ;
     RECT  0.192 26.736 2.408 26.76 ;
     RECT  0.156 26.76 2.408 26.832 ;
     RECT  0.192 26.832 2.408 26.856 ;
     RECT  0.156 26.856 2.408 26.976 ;
     RECT  0.192 26.976 2.408 27 ;
     RECT  0.156 27 2.408 27.072 ;
     RECT  0.192 27.072 2.408 27.096 ;
     RECT  0.156 27.096 2.408 27.168 ;
     RECT  0.192 27.168 2.408 27.192 ;
     RECT  0.156 27.192 2.408 27.264 ;
     RECT  0.192 27.264 2.408 27.288 ;
     RECT  0.156 27.288 2.408 27.36 ;
     RECT  0.192 27.36 2.408 27.384 ;
     RECT  0.156 27.384 2.408 27.504 ;
     RECT  0.192 27.504 2.408 27.528 ;
     RECT  0.156 27.528 2.408 27.6 ;
     RECT  0.192 27.6 2.408 27.624 ;
     RECT  0.156 27.624 2.408 27.696 ;
     RECT  0.192 27.696 2.408 27.72 ;
     RECT  0.156 27.72 2.408 27.792 ;
     RECT  0.192 27.792 2.408 27.816 ;
     RECT  0.156 27.816 2.408 27.888 ;
     RECT  0.192 27.888 2.408 27.912 ;
     RECT  0.156 27.912 2.408 27.984 ;
     RECT  0.192 27.984 2.408 28.008 ;
     RECT  0.156 28.008 2.408 28.128 ;
     RECT  0.192 28.128 2.408 28.152 ;
     RECT  0.156 28.152 2.408 28.224 ;
     RECT  0.192 28.224 2.408 28.248 ;
     RECT  0.156 28.248 2.408 28.32 ;
     RECT  0.192 28.32 2.408 28.344 ;
     RECT  0.156 28.344 2.408 28.416 ;
     RECT  0.192 28.416 2.408 28.44 ;
     RECT  0.156 28.44 2.408 28.512 ;
     RECT  0.192 28.512 2.408 28.536 ;
     RECT  0.156 28.536 2.408 28.608 ;
     RECT  0.192 28.608 2.408 28.632 ;
     RECT  0.156 28.632 2.408 28.752 ;
     RECT  0.192 28.752 2.408 28.776 ;
     RECT  0.156 28.776 2.408 28.848 ;
     RECT  0.192 28.848 2.408 28.872 ;
     RECT  0.156 28.872 2.408 28.944 ;
     RECT  0.192 28.944 2.408 28.968 ;
     RECT  0.156 28.968 2.408 29.04 ;
     RECT  0.192 29.04 2.408 29.064 ;
     RECT  0.156 29.064 2.408 29.136 ;
     RECT  0.192 29.136 2.408 29.16 ;
     RECT  0.156 29.16 2.408 29.232 ;
     RECT  0.192 29.232 2.408 29.256 ;
     RECT  0.156 29.256 2.408 29.376 ;
     RECT  0.192 29.376 2.408 29.4 ;
     RECT  0.156 29.4 2.408 29.472 ;
     RECT  0.192 29.472 2.408 29.496 ;
     RECT  0.156 29.496 2.408 29.568 ;
     RECT  0.192 29.568 2.408 29.592 ;
     RECT  0.156 29.592 2.408 29.664 ;
     RECT  0.192 29.664 2.408 29.688 ;
     RECT  0.156 29.688 2.408 29.76 ;
     RECT  0.192 29.76 2.408 29.784 ;
     RECT  0.156 29.784 2.408 29.904 ;
     RECT  0.192 29.904 2.408 29.928 ;
     RECT  0.156 29.928 2.408 30 ;
     RECT  0.192 30 2.408 30.024 ;
     RECT  0.156 30.024 2.408 30.096 ;
     RECT  0.192 30.096 2.408 30.12 ;
     RECT  0.156 30.12 2.408 30.192 ;
     RECT  0.192 30.192 2.408 30.216 ;
     RECT  0.156 30.216 2.408 30.288 ;
     RECT  0.192 30.288 2.408 30.312 ;
     RECT  0.156 30.312 2.408 30.384 ;
     RECT  0.192 30.384 2.408 30.408 ;
     RECT  0.156 30.408 2.408 30.528 ;
     RECT  0.192 30.528 2.408 30.552 ;
     RECT  0.156 30.552 2.408 30.624 ;
     RECT  0.192 30.624 2.408 30.648 ;
     RECT  0.156 30.648 2.408 30.72 ;
     RECT  0.192 30.72 2.408 30.744 ;
     RECT  0.156 30.744 2.408 30.816 ;
     RECT  0.192 30.816 2.408 30.84 ;
     RECT  0.156 30.84 2.408 30.912 ;
     RECT  0.192 30.912 2.408 30.936 ;
     RECT  0.156 30.936 2.408 31.008 ;
     RECT  0.192 31.008 2.408 31.032 ;
     RECT  0.156 31.032 2.408 31.152 ;
     RECT  0.192 31.152 2.408 31.176 ;
     RECT  0.156 31.176 2.408 31.248 ;
     RECT  0.192 31.248 2.408 31.272 ;
     RECT  0.156 31.272 2.408 31.344 ;
     RECT  0.192 31.344 2.408 31.368 ;
     RECT  0.156 31.368 2.408 31.44 ;
     RECT  0.192 31.44 2.408 31.464 ;
     RECT  0.156 31.464 2.408 31.536 ;
     RECT  0.192 31.536 2.408 31.56 ;
     RECT  0.156 31.56 2.408 31.632 ;
     RECT  0.192 31.632 2.408 31.656 ;
     RECT  0.156 31.656 2.408 31.776 ;
     RECT  0.192 31.776 2.408 31.8 ;
     RECT  0.156 31.8 2.408 31.872 ;
     RECT  0.192 31.872 2.408 31.896 ;
     RECT  0.156 31.896 2.408 31.968 ;
     RECT  0.192 31.968 2.408 31.992 ;
     RECT  0.156 31.992 2.408 32.064 ;
     RECT  0.192 32.064 2.408 32.088 ;
     RECT  0.156 32.088 2.408 32.16 ;
     RECT  0.192 32.16 2.408 32.184 ;
     RECT  0.156 32.184 2.408 32.304 ;
     RECT  0.192 32.304 2.408 32.328 ;
     RECT  0.156 32.328 2.408 32.4 ;
     RECT  0.192 32.4 2.408 32.424 ;
     RECT  0.156 32.424 2.408 32.496 ;
     RECT  0.192 32.496 2.408 32.52 ;
     RECT  0.156 32.52 2.408 32.592 ;
     RECT  0.192 32.592 2.408 32.616 ;
     RECT  0.156 32.616 2.408 32.688 ;
     RECT  0.192 32.688 2.408 32.712 ;
     RECT  0.156 32.712 2.408 32.784 ;
     RECT  0.192 32.784 2.408 32.808 ;
     RECT  0.156 32.808 2.408 32.928 ;
     RECT  0.192 32.928 2.408 32.952 ;
     RECT  0.156 32.952 2.408 33.024 ;
     RECT  0.192 33.024 2.408 33.048 ;
     RECT  0.156 33.048 2.408 33.12 ;
     RECT  0.192 33.12 2.408 33.144 ;
     RECT  0.156 33.144 2.408 33.216 ;
     RECT  0.192 33.216 2.408 33.24 ;
     RECT  0.156 33.24 2.408 33.312 ;
     RECT  0.192 33.312 2.408 33.336 ;
     RECT  0.156 33.336 2.408 33.408 ;
     RECT  0.192 33.408 2.408 33.432 ;
     RECT  0.156 33.432 2.408 33.552 ;
     RECT  0.192 33.552 2.408 33.576 ;
     RECT  0.156 33.576 2.408 33.648 ;
     RECT  0.192 33.648 2.408 33.672 ;
     RECT  0.156 33.672 2.408 33.744 ;
     RECT  0.192 33.744 2.408 33.768 ;
     RECT  0.156 33.768 2.408 33.84 ;
     RECT  0.192 33.84 2.408 33.864 ;
     RECT  0.156 33.864 2.408 33.936 ;
     RECT  0.192 33.936 2.408 33.96 ;
     RECT  0.156 33.96 2.408 34.032 ;
     RECT  0.192 34.032 2.408 34.056 ;
     RECT  0.156 34.056 2.408 34.176 ;
     RECT  0.192 34.176 2.408 34.2 ;
     RECT  0.156 34.2 2.408 34.272 ;
     RECT  0.192 34.272 2.408 34.296 ;
     RECT  0.156 34.296 2.408 34.368 ;
     RECT  0.192 34.368 2.408 34.392 ;
     RECT  0.156 34.392 2.408 34.464 ;
     RECT  0.192 34.464 2.408 34.488 ;
     RECT  0.156 34.488 2.408 34.56 ;
     RECT  0.192 34.56 2.408 34.584 ;
     RECT  0.156 34.584 2.408 34.704 ;
     RECT  0.192 34.704 2.408 34.728 ;
     RECT  0.156 34.728 2.408 34.8 ;
     RECT  0.192 34.8 2.408 34.824 ;
     RECT  0.156 34.824 2.408 34.896 ;
     RECT  0.192 34.896 2.408 34.92 ;
     RECT  0.156 34.92 2.408 34.992 ;
     RECT  0.192 34.992 2.408 35.016 ;
     RECT  0.156 35.016 2.408 35.088 ;
     RECT  0.192 35.088 2.408 35.112 ;
     RECT  0.156 35.112 2.408 35.184 ;
     RECT  0.192 35.184 2.408 35.208 ;
     RECT  0.156 35.208 2.408 35.328 ;
     RECT  0.192 35.328 2.408 35.352 ;
     RECT  0.156 35.352 2.408 35.424 ;
     RECT  0.192 35.424 2.408 35.448 ;
     RECT  0.156 35.448 2.408 35.52 ;
     RECT  0.192 35.52 2.408 35.544 ;
     RECT  0.156 35.544 2.408 35.616 ;
     RECT  0.192 35.616 2.408 35.64 ;
     RECT  0.156 35.64 2.408 35.712 ;
     RECT  0.192 35.712 2.408 35.736 ;
     RECT  0.156 35.736 2.408 35.808 ;
     RECT  0.192 35.808 2.408 35.832 ;
     RECT  0.156 35.832 2.408 35.952 ;
     RECT  0.192 35.952 2.408 35.976 ;
     RECT  0.156 35.976 2.408 36.048 ;
     RECT  0.192 36.048 2.408 36.072 ;
     RECT  0.156 36.072 2.408 36.144 ;
     RECT  0.192 36.144 2.408 36.168 ;
     RECT  0.156 36.168 2.408 36.24 ;
     RECT  0.192 36.24 2.408 36.264 ;
     RECT  0.156 36.264 2.408 36.336 ;
     RECT  0.192 36.336 2.408 36.36 ;
     RECT  0.156 36.36 2.408 36.432 ;
     RECT  0.192 36.432 2.408 36.456 ;
     RECT  0.156 36.456 2.408 36.576 ;
     RECT  0.192 36.576 2.408 36.6 ;
     RECT  0.156 36.6 2.408 36.672 ;
     RECT  0.192 36.672 2.408 36.696 ;
     RECT  0.156 36.696 2.408 36.768 ;
     RECT  0.192 36.768 2.408 36.792 ;
     RECT  0.156 36.792 2.408 36.864 ;
     RECT  0.192 36.864 2.408 36.888 ;
     RECT  0.156 36.888 2.408 36.96 ;
     RECT  0.192 36.96 2.408 36.984 ;
     RECT  0.156 36.984 2.408 37.104 ;
     RECT  0.192 37.104 2.408 37.128 ;
     RECT  0.156 37.128 2.408 37.2 ;
     RECT  0.192 37.2 2.408 37.224 ;
     RECT  0.156 37.224 2.408 37.296 ;
     RECT  0.192 37.296 2.408 37.32 ;
     RECT  0.156 37.32 2.408 37.392 ;
     RECT  0.192 37.392 2.408 37.416 ;
     RECT  0.156 37.416 2.408 37.488 ;
     RECT  0.192 37.488 2.408 37.512 ;
     RECT  0.156 37.512 2.408 37.584 ;
     RECT  0.192 37.584 2.408 37.608 ;
     RECT  0.156 37.608 2.408 37.728 ;
     RECT  0.192 37.728 2.408 37.752 ;
     RECT  0.156 37.752 2.408 37.824 ;
     RECT  0.192 37.824 2.408 37.848 ;
     RECT  0.156 37.848 2.408 37.92 ;
     RECT  0.192 37.92 2.408 37.944 ;
     RECT  0.156 37.944 2.408 38.016 ;
     RECT  0.192 38.016 2.408 38.04 ;
     RECT  0.156 38.04 2.408 38.112 ;
     RECT  0.192 38.112 2.408 38.136 ;
     RECT  0.156 38.136 2.408 38.208 ;
     RECT  0.192 38.208 2.408 38.232 ;
     RECT  0.156 38.232 2.408 38.352 ;
     RECT  0.192 38.352 2.408 38.376 ;
     RECT  0.156 38.376 2.408 38.448 ;
     RECT  0.192 38.448 2.408 38.472 ;
     RECT  0.156 38.472 2.408 38.544 ;
     RECT  0.192 38.544 2.408 38.568 ;
     RECT  0.156 38.568 2.408 38.64 ;
     RECT  0.192 38.64 2.408 38.664 ;
     RECT  0.156 38.664 2.408 38.736 ;
     RECT  0.192 38.736 2.408 38.76 ;
     RECT  0.156 38.76 2.408 38.832 ;
     RECT  0.192 38.832 2.408 38.856 ;
     RECT  0.156 38.856 2.408 38.976 ;
     RECT  0.192 38.976 2.408 39 ;
     RECT  0.156 39 2.408 39.072 ;
     RECT  0.192 39.072 2.408 39.096 ;
     RECT  0.156 39.096 2.408 39.168 ;
     RECT  0.192 39.168 2.408 39.192 ;
     RECT  0.156 39.192 2.408 39.264 ;
     RECT  0.192 39.264 2.408 39.288 ;
     RECT  0.156 39.288 2.408 39.36 ;
     RECT  0.192 39.36 2.408 39.384 ;
     RECT  0.156 39.384 2.408 39.504 ;
     RECT  0.192 39.504 2.408 39.528 ;
     RECT  0.156 39.528 2.408 39.6 ;
     RECT  0.192 39.6 2.408 39.624 ;
     RECT  0.156 39.624 2.408 39.696 ;
     RECT  0.192 39.696 2.408 39.72 ;
     RECT  0.156 39.72 2.408 39.792 ;
     RECT  0.192 39.792 2.408 39.816 ;
     RECT  0.156 39.816 2.408 39.888 ;
     RECT  0.192 39.888 2.408 39.912 ;
     RECT  0.156 39.912 2.408 39.984 ;
     RECT  0.192 39.984 2.408 40.008 ;
     RECT  0.156 40.008 2.408 40.128 ;
     RECT  0.192 40.128 2.408 40.152 ;
     RECT  0.156 40.152 2.408 40.224 ;
     RECT  0.192 40.224 2.408 40.248 ;
     RECT  0.156 40.248 2.408 40.32 ;
     RECT  0.192 40.32 2.408 40.344 ;
     RECT  0.156 40.344 2.408 40.416 ;
     RECT  0.192 40.416 2.408 40.44 ;
     RECT  0.156 40.44 2.408 40.512 ;
     RECT  0.192 40.512 2.408 40.536 ;
     RECT  0.156 40.536 2.408 40.608 ;
     RECT  0.192 40.608 2.408 40.632 ;
     RECT  0.156 40.632 2.408 40.752 ;
     RECT  0.192 40.752 2.408 40.776 ;
     RECT  0.156 40.776 2.408 40.848 ;
     RECT  0.192 40.848 2.408 40.872 ;
     RECT  0.156 40.872 2.408 40.944 ;
     RECT  0.192 40.944 2.408 40.968 ;
     RECT  0.156 40.968 2.408 41.04 ;
     RECT  0.192 41.04 2.408 41.064 ;
     RECT  0.156 41.064 2.408 41.136 ;
     RECT  0.192 41.136 2.408 41.16 ;
     RECT  0.156 41.16 2.408 41.232 ;
     RECT  0.192 41.232 2.408 41.256 ;
     RECT  0.156 41.256 2.408 41.376 ;
     RECT  0.192 41.376 2.408 41.4 ;
     RECT  0.156 41.4 2.408 41.472 ;
     RECT  0.192 41.472 2.408 41.496 ;
     RECT  0.156 41.496 2.408 41.568 ;
     RECT  0.192 41.568 2.408 41.592 ;
     RECT  0.156 41.592 2.408 41.664 ;
     RECT  0.192 41.664 2.408 41.688 ;
     RECT  0.156 41.688 2.408 41.76 ;
     RECT  0.192 41.76 2.408 41.784 ;
     RECT  0.156 41.784 2.408 41.904 ;
     RECT  0.192 41.904 2.408 41.928 ;
     RECT  0.156 41.928 2.408 42 ;
     RECT  0.192 42 2.408 42.024 ;
     RECT  0.156 42.024 2.408 42.096 ;
     RECT  0.192 42.096 2.408 42.12 ;
     RECT  0.156 42.12 2.408 42.192 ;
     RECT  0.192 42.192 2.408 42.216 ;
     RECT  0.156 42.216 2.408 42.288 ;
     RECT  0.192 42.288 2.408 42.312 ;
     RECT  0.156 42.312 2.408 42.384 ;
     RECT  0.192 42.384 2.408 42.408 ;
     RECT  0.156 42.408 2.408 42.528 ;
     RECT  0.192 42.528 2.408 42.552 ;
     RECT  0.156 42.552 2.408 42.624 ;
     RECT  0.192 42.624 2.408 42.648 ;
     RECT  0.156 42.648 2.408 42.72 ;
     RECT  0.192 42.72 2.408 42.744 ;
     RECT  0.156 42.744 2.408 42.816 ;
     RECT  0.192 42.816 2.408 42.84 ;
     RECT  0.156 42.84 2.408 42.912 ;
     RECT  0.192 42.912 2.408 42.936 ;
     RECT  0.156 42.936 2.408 43.008 ;
     RECT  0.192 43.008 2.408 43.032 ;
     RECT  0.156 43.032 2.408 43.152 ;
     RECT  0.192 43.152 2.408 43.176 ;
     RECT  0.156 43.176 2.408 43.248 ;
     RECT  0.192 43.248 2.408 43.272 ;
     RECT  0.156 43.272 2.408 43.344 ;
     RECT  0.192 43.344 2.408 43.368 ;
     RECT  0.156 43.368 2.408 43.44 ;
     RECT  0.192 43.44 2.408 43.464 ;
     RECT  0.156 43.464 2.408 43.536 ;
     RECT  0.192 43.536 2.408 43.56 ;
     RECT  0.156 43.56 2.408 43.68 ;
     RECT  0.192 43.68 2.408 43.704 ;
     RECT  0.156 43.704 2.408 43.776 ;
     RECT  0.192 43.776 2.408 43.8 ;
     RECT  0.156 43.8 2.408 43.872 ;
     RECT  0.192 43.872 2.408 43.896 ;
     RECT  0.156 43.896 2.408 43.968 ;
     RECT  0.192 43.968 2.408 43.992 ;
     RECT  0.156 43.992 2.408 44.064 ;
     RECT  0.192 44.064 2.408 44.088 ;
     RECT  0.156 44.088 2.408 44.16 ;
     RECT  0.192 44.16 2.408 44.184 ;
     RECT  0.156 44.184 2.408 44.304 ;
     RECT  0.192 44.304 2.408 44.328 ;
     RECT  0.156 44.328 2.408 44.4 ;
     RECT  0.192 44.4 2.408 44.424 ;
     RECT  0.156 44.424 2.408 44.496 ;
     RECT  0.192 44.496 2.408 44.52 ;
     RECT  0.156 44.52 2.408 44.592 ;
     RECT  0.192 44.592 2.408 44.616 ;
     RECT  0.156 44.616 2.408 44.688 ;
     RECT  0.192 44.688 2.408 44.712 ;
     RECT  0.156 44.712 2.408 44.784 ;
     RECT  0.192 44.784 2.408 44.808 ;
     RECT  0.156 44.808 2.408 44.928 ;
     RECT  0.192 44.928 2.408 44.952 ;
     RECT  0.156 44.952 2.408 45.024 ;
     RECT  0.192 45.024 2.408 45.048 ;
     RECT  0.156 45.048 2.408 45.12 ;
     RECT  0.192 45.12 2.408 45.144 ;
     RECT  0.156 45.144 2.408 45.216 ;
     RECT  0.192 45.216 2.408 45.24 ;
     RECT  0.156 45.24 2.408 45.312 ;
     RECT  0.192 45.312 2.408 45.336 ;
     RECT  0.156 45.336 2.408 45.408 ;
     RECT  0.192 45.408 2.408 45.432 ;
     RECT  0.156 45.432 2.408 45.552 ;
     RECT  0.192 45.552 2.408 45.576 ;
     RECT  0.156 45.576 2.408 45.648 ;
     RECT  0.192 45.648 2.408 45.672 ;
     RECT  0.156 45.672 2.408 45.744 ;
     RECT  0.192 45.744 2.408 45.768 ;
     RECT  0.156 45.768 2.408 45.84 ;
     RECT  0.192 45.84 2.408 45.864 ;
     RECT  0.156 45.864 2.408 45.936 ;
     RECT  0.192 45.936 2.408 45.96 ;
     RECT  0.156 45.96 2.408 46.08 ;
     RECT  0.192 46.08 2.408 46.104 ;
     RECT  0.156 46.104 2.408 46.176 ;
     RECT  0.192 46.176 2.408 46.2 ;
     RECT  0.156 46.2 2.408 46.272 ;
     RECT  0.192 46.272 2.408 46.296 ;
     RECT  0.156 46.296 2.408 46.368 ;
     RECT  0.192 46.368 2.408 46.392 ;
     RECT  0.156 46.392 2.408 46.464 ;
     RECT  0.192 46.464 2.408 46.488 ;
     RECT  0.156 46.488 2.408 46.56 ;
     RECT  0.192 46.56 2.408 46.584 ;
     RECT  0.156 46.584 2.408 46.704 ;
     RECT  0.192 46.704 2.408 46.728 ;
     RECT  0.156 46.728 2.408 46.8 ;
     RECT  0.192 46.8 2.408 46.824 ;
     RECT  0.156 46.824 2.408 46.896 ;
     RECT  0.192 46.896 2.408 46.92 ;
     RECT  0.156 46.92 2.408 46.992 ;
     RECT  0.192 46.992 2.408 47.016 ;
     RECT  0.156 47.016 2.408 47.088 ;
     RECT  0.192 47.088 2.408 47.112 ;
     RECT  0.156 47.112 2.408 47.184 ;
     RECT  0.192 47.184 2.408 47.208 ;
     RECT  0.156 47.208 2.408 47.328 ;
     RECT  0.192 47.328 2.408 47.352 ;
     RECT  0.156 47.352 2.408 47.424 ;
     RECT  0.192 47.424 2.408 47.448 ;
     RECT  0.156 47.448 2.408 47.52 ;
     RECT  0.192 47.52 2.408 47.544 ;
     RECT  0.156 47.544 2.408 47.616 ;
     RECT  0.192 47.616 2.408 47.64 ;
     RECT  0.156 47.64 2.408 47.712 ;
     RECT  0.192 47.712 2.408 47.736 ;
     RECT  0.156 47.736 2.408 47.808 ;
     RECT  0.192 47.808 2.408 47.832 ;
     RECT  0.156 47.832 2.408 47.952 ;
     RECT  0.192 47.952 2.408 47.976 ;
     RECT  0.156 47.976 2.408 48.048 ;
     RECT  0.192 48.048 2.408 48.072 ;
     RECT  0.156 48.072 2.408 48.144 ;
     RECT  0.192 48.144 2.408 48.168 ;
     RECT  0.156 48.168 2.408 48.24 ;
     RECT  0.192 48.24 2.408 48.264 ;
     RECT  0.156 48.264 2.408 48.336 ;
     RECT  0.192 48.336 2.408 48.36 ;
     RECT  0.156 48.36 2.408 48.48 ;
     RECT  0.192 48.48 2.408 48.504 ;
     RECT  0.156 48.504 2.408 48.576 ;
     RECT  0.192 48.576 2.408 48.6 ;
     RECT  0.156 48.6 2.408 48.672 ;
     RECT  0.192 48.672 2.408 48.696 ;
     RECT  0.156 48.696 2.408 48.768 ;
     RECT  0.192 48.768 2.408 48.792 ;
     RECT  0.156 48.792 2.408 48.864 ;
     RECT  0.192 48.864 2.408 48.888 ;
     RECT  0.156 48.888 2.408 48.96 ;
     RECT  0.192 48.96 2.408 48.984 ;
     RECT  0.156 48.984 2.408 49.104 ;
     RECT  0.192 49.104 2.408 49.128 ;
     RECT  0.156 49.128 2.408 49.2 ;
     RECT  0.192 49.2 2.408 49.224 ;
     RECT  0.156 49.224 2.408 49.296 ;
     RECT  0.192 49.296 2.408 49.32 ;
     RECT  0.156 49.32 2.408 49.392 ;
     RECT  0.192 49.392 2.408 49.416 ;
     RECT  0.156 49.416 2.408 49.488 ;
     RECT  0.192 49.488 2.408 49.512 ;
     RECT  0.156 49.512 2.408 49.584 ;
     RECT  0.192 49.584 2.408 49.608 ;
     RECT  0.156 49.608 2.408 49.728 ;
     RECT  0.192 49.728 2.408 49.752 ;
     RECT  0.156 49.752 2.408 49.824 ;
     RECT  0.192 49.824 2.408 49.848 ;
     RECT  0.156 49.848 2.408 49.92 ;
     RECT  0.192 49.92 2.408 49.944 ;
     RECT  0.156 49.944 2.408 50.016 ;
     RECT  0.192 50.016 2.408 50.04 ;
     RECT  0.156 50.04 2.408 50.112 ;
     RECT  0.192 50.112 2.408 50.136 ;
     RECT  0.156 50.136 2.408 50.208 ;
     RECT  0.192 50.208 2.408 50.232 ;
     RECT  0.156 50.232 2.408 50.352 ;
     RECT  0.192 50.352 2.408 50.376 ;
     RECT  0.156 50.376 2.408 50.448 ;
     RECT  0.192 50.448 2.408 50.472 ;
     RECT  0.156 50.472 2.408 50.544 ;
     RECT  0.192 50.544 2.408 50.568 ;
     RECT  0.156 50.568 2.408 50.64 ;
     RECT  0.192 50.64 2.408 50.664 ;
     RECT  0.156 50.664 2.408 50.736 ;
     RECT  0.192 50.736 2.408 50.76 ;
     RECT  0.156 50.76 2.408 50.88 ;
     RECT  0.192 50.88 2.408 50.904 ;
     RECT  0.156 50.904 2.408 50.976 ;
     RECT  0.192 50.976 2.408 51 ;
     RECT  0.156 51 2.408 51.072 ;
     RECT  0.192 51.072 2.408 51.096 ;
     RECT  0.156 51.096 2.408 51.168 ;
     RECT  0.192 51.168 2.408 51.192 ;
     RECT  0.156 51.192 2.408 51.264 ;
     RECT  0.192 51.264 2.408 51.288 ;
     RECT  0.156 51.288 2.408 51.36 ;
     RECT  0.192 51.36 2.408 51.384 ;
     RECT  0.156 51.384 2.408 51.504 ;
     RECT  0.192 51.504 2.408 51.528 ;
     RECT  0.156 51.528 2.408 51.6 ;
     RECT  0.192 51.6 2.408 51.624 ;
     RECT  0.156 51.624 2.408 51.696 ;
     RECT  0.192 51.696 2.408 51.72 ;
     RECT  0.156 51.72 2.408 51.792 ;
     RECT  0.192 51.792 2.408 51.816 ;
     RECT  0.156 51.816 2.408 51.888 ;
     RECT  0.192 51.888 2.408 51.912 ;
     RECT  0.156 51.912 2.408 51.984 ;
     RECT  0.192 51.984 2.408 52.008 ;
     RECT  0.156 52.008 2.408 52.128 ;
     RECT  0.192 52.128 2.408 52.152 ;
     RECT  0.156 52.152 2.408 52.224 ;
     RECT  0.192 52.224 2.408 52.248 ;
     RECT  0.156 52.248 2.408 52.32 ;
     RECT  0.192 52.32 2.408 52.344 ;
     RECT  0.156 52.344 2.408 52.416 ;
     RECT  0.192 52.416 2.408 52.44 ;
     RECT  0.156 52.44 2.408 52.512 ;
     RECT  0.192 52.512 2.408 52.536 ;
     RECT  0.156 52.536 2.408 52.608 ;
     RECT  0.192 52.608 2.408 52.632 ;
     RECT  0.156 52.632 2.408 52.752 ;
     RECT  0.192 52.752 2.408 52.776 ;
     RECT  0.156 52.776 2.408 52.848 ;
     RECT  0.192 52.848 2.408 52.872 ;
     RECT  0.156 52.872 2.408 52.944 ;
     RECT  0.192 52.944 2.408 52.968 ;
     RECT  0.156 52.968 2.408 53.04 ;
     RECT  0.192 53.04 2.408 53.064 ;
     RECT  0.156 53.064 2.408 53.136 ;
     RECT  0.192 53.136 2.408 53.16 ;
     RECT  0.156 53.16 2.408 53.28 ;
     RECT  0.192 53.28 2.408 53.304 ;
     RECT  0.156 53.304 2.408 53.376 ;
     RECT  0.192 53.376 2.408 53.4 ;
     RECT  0.156 53.4 2.408 53.472 ;
     RECT  0.192 53.472 2.408 53.496 ;
     RECT  0.156 53.496 2.408 53.568 ;
     RECT  0.192 53.568 2.408 53.592 ;
     RECT  0.156 53.592 2.408 53.664 ;
     RECT  0.192 53.664 2.408 53.688 ;
     RECT  0.156 53.688 2.408 53.76 ;
     RECT  0.192 53.76 2.408 53.784 ;
     RECT  0.156 53.784 2.408 53.904 ;
     RECT  0.192 53.904 2.408 53.928 ;
     RECT  0.156 53.928 2.408 54 ;
     RECT  0.192 54 2.408 54.024 ;
     RECT  0.156 54.024 2.408 54.096 ;
     RECT  0.192 54.096 2.408 54.12 ;
     RECT  0.156 54.12 2.408 54.192 ;
     RECT  0.192 54.192 2.408 54.216 ;
     RECT  0.156 54.216 2.408 54.288 ;
     RECT  0.192 54.288 2.408 54.312 ;
     RECT  0.156 54.312 2.408 54.384 ;
     RECT  0.192 54.384 2.408 54.408 ;
     RECT  0.156 54.408 2.408 54.528 ;
     RECT  0.192 54.528 2.408 54.552 ;
     RECT  0.156 54.552 2.408 54.624 ;
     RECT  0.192 54.624 2.408 54.648 ;
     RECT  0.156 54.648 2.408 54.72 ;
     RECT  0.192 54.72 2.408 54.744 ;
     RECT  0.156 54.744 2.408 54.816 ;
     RECT  0.192 54.816 2.408 54.84 ;
     RECT  0.156 54.84 2.408 54.912 ;
     RECT  0.192 54.912 2.408 54.936 ;
     RECT  0.156 54.936 2.408 55.008 ;
     RECT  0.192 55.008 2.408 55.032 ;
     RECT  0.156 55.032 2.408 55.152 ;
     RECT  0.192 55.152 2.408 55.176 ;
     RECT  0.156 55.176 2.408 55.248 ;
     RECT  0.192 55.248 2.408 55.272 ;
     RECT  0.156 55.272 2.408 55.344 ;
     RECT  0.192 55.344 2.408 55.368 ;
     RECT  0.156 55.368 2.408 55.44 ;
     RECT  0.192 55.44 2.408 55.464 ;
     RECT  0.156 55.464 2.408 55.536 ;
     RECT  0.192 55.536 2.408 55.56 ;
     RECT  0.156 55.56 2.408 55.68 ;
     RECT  0.192 55.68 2.408 55.704 ;
     RECT  0.156 55.704 2.408 55.776 ;
     RECT  0.192 55.776 2.408 55.8 ;
     RECT  0.156 55.8 2.408 55.872 ;
     RECT  0.192 55.872 2.408 55.896 ;
     RECT  0.156 55.896 2.408 55.968 ;
     RECT  0.192 55.968 2.408 55.992 ;
     RECT  0.156 55.992 2.408 56.064 ;
     RECT  0.192 56.064 2.408 56.088 ;
     RECT  0.156 56.088 2.408 56.16 ;
     RECT  0.192 56.16 2.408 56.184 ;
     RECT  0.156 56.184 2.408 56.304 ;
     RECT  0.192 56.304 2.408 56.328 ;
     RECT  0.156 56.328 2.408 56.4 ;
     RECT  0.192 56.4 2.408 56.424 ;
     RECT  0.156 56.424 2.408 56.496 ;
     RECT  0.192 56.496 2.408 56.52 ;
     RECT  0.156 56.52 2.408 56.592 ;
     RECT  0.192 56.592 2.408 56.616 ;
     RECT  0.156 56.616 2.408 56.688 ;
     RECT  0.192 56.688 2.408 56.712 ;
     RECT  0.156 56.712 2.408 56.784 ;
     RECT  0.192 56.784 2.408 56.808 ;
     RECT  0.156 56.808 2.408 56.928 ;
     RECT  0.192 56.928 2.408 56.952 ;
     RECT  0.156 56.952 2.408 57.024 ;
     RECT  0.192 57.024 2.408 57.048 ;
     RECT  0.156 57.048 2.408 57.12 ;
     RECT  0.192 57.12 2.408 57.144 ;
     RECT  0.156 57.144 2.408 57.216 ;
     RECT  0.192 57.216 2.408 57.24 ;
     RECT  0.156 57.24 2.408 57.312 ;
     RECT  0.192 57.312 2.408 57.336 ;
     RECT  0.156 57.336 2.408 57.456 ;
     RECT  0.192 57.456 2.408 57.48 ;
     RECT  0.156 57.48 2.408 57.552 ;
     RECT  0.192 57.552 2.408 57.576 ;
     RECT  0.156 57.576 2.408 57.648 ;
     RECT  0.192 57.648 2.408 57.672 ;
     RECT  0.156 57.672 2.408 57.744 ;
     RECT  0.192 57.744 2.408 57.768 ;
     RECT  0.156 57.768 2.408 57.84 ;
     RECT  0.192 57.84 2.408 57.864 ;
     RECT  0.156 57.864 2.408 57.936 ;
     RECT  0.192 57.936 2.408 57.96 ;
     RECT  0.156 57.96 2.408 58.08 ;
     RECT  0.192 58.08 2.408 58.104 ;
     RECT  0.156 58.104 2.408 58.176 ;
     RECT  0.192 58.176 2.408 58.2 ;
     RECT  0.156 58.2 2.408 58.272 ;
     RECT  0.192 58.272 2.408 58.296 ;
     RECT  0.156 58.296 2.408 58.368 ;
     RECT  0.192 58.368 2.408 58.392 ;
     RECT  0.156 58.392 2.408 58.464 ;
     RECT  0.192 58.464 2.408 58.488 ;
     RECT  0.156 58.488 2.408 58.56 ;
     RECT  0.192 58.56 2.408 58.584 ;
     RECT  0.156 58.584 2.408 58.704 ;
     RECT  0.192 58.704 2.408 58.728 ;
     RECT  0.156 58.728 2.408 58.8 ;
     RECT  0.192 58.8 2.408 58.824 ;
     RECT  0.156 58.824 2.408 58.896 ;
     RECT  0.192 58.896 2.408 58.92 ;
     RECT  0.156 58.92 2.408 58.992 ;
     RECT  0.192 58.992 2.408 59.016 ;
     RECT  0.156 59.016 2.408 59.088 ;
     RECT  0.192 59.088 2.408 59.112 ;
     RECT  0.156 59.112 2.408 59.184 ;
     RECT  0.192 59.184 2.408 59.208 ;
     RECT  0.156 59.208 2.408 59.328 ;
     RECT  0.192 59.328 2.408 59.352 ;
     RECT  0.156 59.352 2.408 59.424 ;
     RECT  0.192 59.424 2.408 59.448 ;
     RECT  0.156 59.448 2.408 59.52 ;
     RECT  0.192 59.52 2.408 59.544 ;
     RECT  0.156 59.544 2.408 59.616 ;
     RECT  0.192 59.616 2.408 59.64 ;
     RECT  0.156 59.64 2.408 59.712 ;
     RECT  0.192 59.712 2.408 59.736 ;
     RECT  0.156 59.736 2.408 59.856 ;
     RECT  0.192 59.856 2.408 59.88 ;
     RECT  0.156 59.88 2.408 59.952 ;
     RECT  0.192 59.952 2.408 59.976 ;
     RECT  0.156 59.976 2.408 60.048 ;
     RECT  0.192 60.048 2.408 60.072 ;
     RECT  0.156 60.072 2.408 60.144 ;
     RECT  0.192 60.144 2.408 60.168 ;
     RECT  0.156 60.168 2.408 60.24 ;
     RECT  0.192 60.24 2.408 60.264 ;
     RECT  0.156 60.264 2.408 60.336 ;
     RECT  0.192 60.336 2.408 60.36 ;
     RECT  0.156 60.36 2.408 60.48 ;
     RECT  0.192 60.48 2.408 60.504 ;
     RECT  0.156 60.504 2.408 60.576 ;
     RECT  0.192 60.576 2.408 60.6 ;
     RECT  0.156 60.6 2.408 60.672 ;
     RECT  0.192 60.672 2.408 60.696 ;
     RECT  0.156 60.696 2.408 60.768 ;
     RECT  0.192 60.768 2.408 60.792 ;
     RECT  0.156 60.792 2.408 60.864 ;
     RECT  0.192 60.864 2.408 60.888 ;
     RECT  0.156 60.888 2.408 60.96 ;
     RECT  0.192 60.96 2.408 60.984 ;
     RECT  0.156 60.984 2.408 61.104 ;
     RECT  0.192 61.104 2.408 61.128 ;
     RECT  0.156 61.128 2.408 61.2 ;
     RECT  0.192 61.2 2.408 61.224 ;
     RECT  0.156 61.224 2.408 61.296 ;
     RECT  0.192 61.296 2.408 61.32 ;
     RECT  0.156 61.32 2.408 61.392 ;
     RECT  0.192 61.392 2.408 61.416 ;
     RECT  0.156 61.416 2.408 61.488 ;
     RECT  0.192 61.488 2.408 61.512 ;
     RECT  0.156 61.512 2.408 61.584 ;
     RECT  0.192 61.584 2.408 61.608 ;
     RECT  0.156 61.608 2.408 61.728 ;
     RECT  0.192 61.728 2.408 61.752 ;
     RECT  0.156 61.752 2.408 61.824 ;
     RECT  0.192 61.824 2.408 61.848 ;
     RECT  0.156 61.848 2.408 61.92 ;
     RECT  0.192 61.92 2.408 61.944 ;
     RECT  0.156 61.944 2.408 62.016 ;
     RECT  0.192 62.016 2.408 62.04 ;
     RECT  0.156 62.04 2.408 62.112 ;
     RECT  0.192 62.112 2.408 62.136 ;
     RECT  0.156 62.136 2.408 62.256 ;
     RECT  0.192 62.256 2.408 62.28 ;
     RECT  0.156 62.28 2.408 62.352 ;
     RECT  0.192 62.352 2.408 62.376 ;
     RECT  0.156 62.376 2.408 62.448 ;
     RECT  0.192 62.448 2.408 62.472 ;
     RECT  0.156 62.472 2.408 62.544 ;
     RECT  0.192 62.544 2.408 62.568 ;
     RECT  0.156 62.568 2.408 62.64 ;
     RECT  0.192 62.64 2.408 62.664 ;
     RECT  0.156 62.664 2.408 62.736 ;
     RECT  0.192 62.736 2.408 62.76 ;
     RECT  0.156 62.76 2.408 62.88 ;
     RECT  0.192 62.88 2.408 62.904 ;
     RECT  0.156 62.904 2.408 62.976 ;
     RECT  0.192 62.976 2.408 63 ;
     RECT  0.156 63 2.408 63.072 ;
     RECT  0.192 63.072 2.408 63.096 ;
     RECT  0.156 63.096 2.408 63.168 ;
     RECT  0.192 63.168 2.408 63.192 ;
     RECT  0.156 63.192 2.408 63.264 ;
     RECT  0.192 63.264 2.408 63.288 ;
     RECT  0.156 63.288 2.408 63.36 ;
     RECT  0.192 63.36 2.408 63.384 ;
     RECT  0.156 63.384 2.408 63.504 ;
     RECT  0.192 63.504 2.408 63.528 ;
     RECT  0.156 63.528 2.408 63.6 ;
     RECT  0.192 63.6 2.408 63.624 ;
     RECT  0.156 63.624 2.408 63.696 ;
     RECT  0.192 63.696 2.408 63.72 ;
     RECT  0.156 63.72 2.408 63.792 ;
     RECT  0.192 63.792 2.408 63.816 ;
     RECT  0.156 63.816 2.408 63.888 ;
     RECT  0.192 63.888 2.408 63.912 ;
     RECT  0.156 63.912 2.408 63.984 ;
     RECT  0.192 63.984 2.408 64.008 ;
     RECT  0.156 64.008 2.408 64.128 ;
     RECT  0.192 64.128 2.408 64.152 ;
     RECT  0.156 64.152 2.408 64.224 ;
     RECT  0.192 64.224 2.408 64.248 ;
     RECT  0.156 64.248 2.408 64.32 ;
     RECT  0.192 64.32 2.408 64.344 ;
     RECT  0.156 64.344 2.408 64.416 ;
     RECT  0.192 64.416 2.408 64.44 ;
     RECT  0.156 64.44 2.408 64.512 ;
     RECT  0.192 64.512 2.408 64.536 ;
     RECT  0.156 64.536 2.408 64.656 ;
     RECT  0.192 64.656 2.408 64.68 ;
     RECT  0.156 64.68 2.408 64.752 ;
     RECT  0.192 64.752 2.408 64.776 ;
     RECT  0.156 64.776 2.408 64.848 ;
     RECT  0.192 64.848 2.408 64.872 ;
     RECT  0.156 64.872 2.408 64.944 ;
     RECT  0.192 64.944 2.408 64.968 ;
     RECT  0.156 64.968 2.408 65.04 ;
     RECT  0.192 65.04 2.408 65.064 ;
     RECT  0.156 65.064 2.408 65.136 ;
     RECT  0.192 65.136 2.408 65.16 ;
     RECT  0.156 65.16 2.408 65.28 ;
     RECT  0.192 65.28 2.408 65.304 ;
     RECT  0.156 65.304 2.408 65.376 ;
     RECT  0.192 65.376 2.408 65.4 ;
     RECT  0.156 65.4 2.408 65.472 ;
     RECT  0.192 65.472 2.408 65.496 ;
     RECT  0.156 65.496 2.408 65.568 ;
     RECT  0.192 65.568 2.408 65.592 ;
     RECT  0.156 65.592 2.408 65.664 ;
     RECT  0.192 65.664 2.408 65.688 ;
     RECT  0.156 65.688 2.408 65.76 ;
     RECT  0.192 65.76 2.408 65.784 ;
     RECT  0.156 65.784 2.408 65.904 ;
     RECT  0.192 65.904 2.408 65.928 ;
     RECT  0.156 65.928 2.408 66 ;
     RECT  0.192 66 2.408 66.024 ;
     RECT  0.156 66.024 2.408 66.096 ;
     RECT  0.192 66.096 2.408 66.12 ;
     RECT  0.156 66.12 2.408 66.192 ;
     RECT  0.192 66.192 2.408 66.216 ;
     RECT  0.156 66.216 2.408 66.288 ;
     RECT  0.192 66.288 2.408 66.312 ;
     RECT  0.156 66.312 2.408 66.384 ;
     RECT  0.192 66.384 2.408 66.408 ;
     RECT  0.156 66.408 2.408 66.528 ;
     RECT  0.192 66.528 2.408 66.552 ;
     RECT  0.156 66.552 2.408 66.624 ;
     RECT  0.192 66.624 2.408 66.648 ;
     RECT  0.156 66.648 2.408 66.72 ;
     RECT  0.192 66.72 2.408 66.744 ;
     RECT  0.156 66.744 2.408 66.816 ;
     RECT  0.192 66.816 2.408 66.84 ;
     RECT  0.156 66.84 2.408 66.912 ;
     RECT  0.192 66.912 2.408 66.936 ;
     RECT  0.156 66.936 2.408 67.056 ;
     RECT  0.192 67.056 2.408 67.08 ;
     RECT  0.156 67.08 2.408 67.152 ;
     RECT  0.192 67.152 2.408 67.176 ;
     RECT  0.156 67.176 2.408 67.248 ;
     RECT  0.192 67.248 2.408 67.272 ;
     RECT  0.156 67.272 2.408 67.344 ;
     RECT  0.192 67.344 2.408 67.368 ;
     RECT  0.156 67.368 2.408 67.44 ;
     RECT  0.192 67.44 2.408 67.464 ;
     RECT  0.156 67.464 2.408 67.536 ;
     RECT  0.192 67.536 2.408 67.56 ;
     RECT  0.156 67.56 2.408 67.68 ;
     RECT  0.192 67.68 2.408 67.704 ;
     RECT  0.156 67.704 2.408 67.776 ;
     RECT  0.192 67.776 2.408 67.8 ;
     RECT  0.156 67.8 2.408 67.872 ;
     RECT  0.192 67.872 2.408 67.896 ;
     RECT  0.156 67.896 2.408 67.968 ;
     RECT  0.192 67.968 2.408 67.992 ;
     RECT  0.156 67.992 2.408 68.064 ;
     RECT  0.192 68.064 2.408 68.088 ;
     RECT  0.156 68.088 2.408 68.16 ;
     RECT  0.192 68.16 2.408 68.184 ;
     RECT  0.156 68.184 2.408 68.304 ;
     RECT  0.192 68.304 2.408 68.328 ;
     RECT  0.156 68.328 2.408 68.4 ;
     RECT  0.192 68.4 2.408 68.424 ;
     RECT  0.156 68.424 2.408 68.496 ;
     RECT  0.192 68.496 2.408 68.52 ;
     RECT  0.156 68.52 2.408 68.592 ;
     RECT  0.192 68.592 2.408 68.616 ;
     RECT  0.156 68.616 2.408 68.688 ;
     RECT  0.192 68.688 2.408 68.712 ;
     RECT  0.156 68.712 2.408 68.784 ;
     RECT  0.192 68.784 2.408 68.808 ;
     RECT  0.156 68.808 2.408 68.928 ;
     RECT  0.192 68.928 2.408 68.952 ;
     RECT  0.156 68.952 2.408 69.024 ;
     RECT  0.192 69.024 2.408 69.048 ;
     RECT  0.156 69.048 2.408 69.12 ;
     RECT  0.192 69.12 2.408 69.144 ;
     RECT  0.156 69.144 2.408 69.216 ;
     RECT  0.192 69.216 2.408 69.24 ;
     RECT  0.156 69.24 2.408 69.312 ;
     RECT  0.192 69.312 2.408 69.336 ;
     RECT  0.156 69.336 2.408 69.456 ;
     RECT  0.192 69.456 2.408 69.48 ;
     RECT  0.156 69.48 2.408 69.552 ;
     RECT  0.192 69.552 2.408 69.576 ;
     RECT  0.156 69.576 2.408 69.648 ;
     RECT  0.192 69.648 2.408 69.672 ;
     RECT  0.156 69.672 2.408 69.744 ;
     RECT  0.192 69.744 2.408 69.768 ;
     RECT  0.156 69.768 2.408 69.84 ;
     RECT  0.192 69.84 2.408 69.864 ;
     RECT  0.156 69.864 2.408 69.936 ;
     RECT  0.192 69.936 2.408 69.96 ;
     RECT  0.156 69.96 2.408 70.08 ;
     RECT  0.192 70.08 2.408 70.104 ;
     RECT  0.156 70.104 2.408 70.176 ;
     RECT  0.192 70.176 2.408 70.2 ;
     RECT  0.156 70.2 2.408 70.272 ;
     RECT  0.192 70.272 2.408 70.296 ;
     RECT  0.156 70.296 2.408 70.368 ;
     RECT  0.192 70.368 2.408 70.392 ;
     RECT  0.156 70.392 2.408 70.464 ;
     RECT  0.192 70.464 2.408 70.488 ;
     RECT  0.156 70.488 2.408 70.56 ;
     RECT  0.192 70.56 2.408 70.584 ;
     RECT  0.156 70.584 2.408 70.704 ;
     RECT  0.192 70.704 2.408 70.728 ;
     RECT  0.156 70.728 2.408 70.8 ;
     RECT  0.192 70.8 2.408 70.824 ;
     RECT  0.156 70.824 2.408 70.896 ;
     RECT  0.192 70.896 2.408 70.92 ;
     RECT  0.156 70.92 2.408 70.992 ;
     RECT  0.192 70.992 2.408 71.016 ;
     RECT  0.156 71.016 2.408 71.088 ;
     RECT  0.192 71.088 2.408 71.112 ;
     RECT  0.156 71.112 2.408 71.232 ;
     RECT  0.192 71.232 2.408 71.256 ;
     RECT  0.156 71.256 2.408 71.328 ;
     RECT  0.192 71.328 2.408 71.352 ;
     RECT  0.156 71.352 2.408 71.424 ;
     RECT  0.192 71.424 2.408 71.448 ;
     RECT  0.156 71.448 2.408 71.52 ;
     RECT  0.192 71.52 2.408 71.544 ;
     RECT  0.156 71.544 2.408 71.616 ;
     RECT  0.192 71.616 2.408 71.64 ;
     RECT  0.156 71.64 2.408 71.712 ;
     RECT  0.192 71.712 2.408 71.736 ;
     RECT  0.156 71.736 2.408 71.856 ;
     RECT  0.192 71.856 2.408 71.88 ;
     RECT  0.156 71.88 2.408 71.952 ;
     RECT  0.192 71.952 2.408 71.976 ;
     RECT  0.156 71.976 2.408 72.048 ;
     RECT  0.192 72.048 2.408 72.072 ;
     RECT  0.156 72.072 2.408 72.144 ;
     RECT  0.192 72.144 2.408 72.168 ;
     RECT  0.156 72.168 2.408 72.24 ;
     RECT  0.192 72.24 2.408 72.264 ;
     RECT  0.156 72.264 2.408 72.336 ;
     RECT  0.192 72.336 2.408 72.36 ;
     RECT  0.156 72.36 2.408 72.48 ;
     RECT  0.192 72.48 2.408 72.504 ;
     RECT  0.156 72.504 2.408 72.576 ;
     RECT  0.192 72.576 2.408 72.6 ;
     RECT  0.156 72.6 2.408 72.672 ;
     RECT  0.192 72.672 2.408 72.696 ;
     RECT  0.156 72.696 2.408 72.768 ;
     RECT  0.192 72.768 2.408 72.792 ;
     RECT  0.156 72.792 2.408 72.864 ;
     RECT  0.192 72.864 2.408 72.888 ;
     RECT  0.156 72.888 2.408 72.96 ;
     RECT  0.192 72.96 2.408 72.984 ;
     RECT  0.156 72.984 2.408 73.104 ;
     RECT  0.192 73.104 2.408 73.128 ;
     RECT  0.156 73.128 2.408 73.2 ;
     RECT  0.192 73.2 2.408 73.224 ;
     RECT  0.156 73.224 2.408 73.296 ;
     RECT  0.192 73.296 2.408 73.32 ;
     RECT  0.156 73.32 2.408 73.392 ;
     RECT  0.192 73.392 2.408 73.416 ;
     RECT  2.408 2.148 2.512 73.452 ;
     RECT  2.512 2.304 2.837 73.368 ;
     RECT  2.837 36.048 3.233 73.368 ;
     RECT  2.837 2.304 3.805 34.824 ;
     RECT  3.233 36.048 3.805 73.32 ;
     RECT  3.805 2.304 4.025 73.32 ;
     RECT  4.025 55.968 4.133 73.32 ;
     RECT  4.025 2.304 5.108 54.936 ;
     RECT  4.133 56.544 5.108 73.32 ;
     RECT  5.108 2.148 5.212 73.452 ;
     RECT  5.212 2.418 5.404 73.32 ;
     RECT  5.404 13.296 5.537 24.456 ;
     RECT  5.389 74.688 5.603 74.712 ;
     RECT  5.537 13.296 5.645 22.056 ;
     RECT  5.404 8.784 6.421 12.264 ;
     RECT  5.645 13.296 6.421 17.64 ;
     RECT  5.404 33.312 6.433 33.576 ;
     RECT  5.404 25.44 6.469 32.328 ;
     RECT  6.433 33.312 6.469 33.864 ;
     RECT  5.404 34.896 6.469 50.568 ;
     RECT  5.404 51.696 6.469 65.688 ;
     RECT  5.645 18.768 6.517 22.056 ;
     RECT  5.537 23.28 6.517 24.456 ;
     RECT  6.469 25.44 6.517 33.864 ;
     RECT  6.469 34.896 6.541 65.688 ;
     RECT  5.404 2.496 6.62 7.752 ;
     RECT  6.541 34.896 6.649 65.976 ;
     RECT  5.404 67.104 6.649 73.32 ;
     RECT  6.62 2.256 6.707 7.752 ;
     RECT  6.421 8.784 6.793 17.64 ;
     RECT  6.517 18.768 6.793 22.248 ;
     RECT  6.517 23.28 6.793 33.864 ;
     RECT  6.649 34.896 6.793 73.32 ;
     RECT  6.793 8.784 7.261 22.248 ;
     RECT  6.793 23.28 7.261 73.32 ;
     RECT  6.707 2.352 7.297 7.752 ;
     RECT  7.261 8.784 7.297 73.32 ;
     RECT  7.297 2.352 7.621 73.32 ;
     RECT  7.621 2.352 7.808 73.368 ;
     RECT  7.808 2.148 7.912 73.452 ;
     RECT  7.912 2.352 10.508 73.368 ;
     RECT  10.508 2.148 10.612 73.452 ;
     RECT  10.612 2.352 11.729 73.368 ;
     RECT  11.729 2.352 11.765 73.32 ;
     RECT  11.765 2.496 12.197 73.32 ;
     RECT  12.197 2.544 13.208 73.32 ;
     RECT  13.208 2.148 13.312 73.452 ;
     RECT  13.312 2.418 13.504 73.32 ;
     RECT  13.504 2.544 13.853 73.32 ;
     RECT  13.853 2.544 14.821 73.272 ;
     RECT  14.821 2.352 16.513 73.416 ;
     RECT  16.513 2.208 17.088 2.232 ;
     RECT  16.513 2.232 17.1 2.352 ;
     RECT  16.513 2.352 17.088 2.376 ;
     RECT  16.513 2.376 17.1 2.448 ;
     RECT  16.513 2.448 17.088 2.472 ;
     RECT  16.513 2.472 17.1 2.544 ;
     RECT  16.513 2.544 17.088 2.568 ;
     RECT  16.513 2.568 17.1 2.64 ;
     RECT  16.513 2.64 17.088 2.664 ;
     RECT  16.513 2.664 17.1 2.736 ;
     RECT  16.513 2.736 17.088 2.76 ;
     RECT  16.513 2.76 17.1 2.832 ;
     RECT  16.513 2.832 17.088 2.856 ;
     RECT  16.513 2.856 17.1 2.976 ;
     RECT  16.513 2.976 17.088 3 ;
     RECT  16.513 3 17.1 3.072 ;
     RECT  16.513 3.072 17.088 3.096 ;
     RECT  16.513 3.096 17.1 3.168 ;
     RECT  16.513 3.168 17.088 3.192 ;
     RECT  16.513 3.192 17.1 3.264 ;
     RECT  16.513 3.264 17.088 3.288 ;
     RECT  16.513 3.288 17.1 3.36 ;
     RECT  16.513 3.36 17.088 3.384 ;
     RECT  16.513 3.384 17.1 3.456 ;
     RECT  16.513 3.456 17.088 3.48 ;
     RECT  16.513 3.48 17.1 3.6 ;
     RECT  16.513 3.6 17.088 3.624 ;
     RECT  16.513 3.624 17.1 3.696 ;
     RECT  16.513 3.696 17.088 3.72 ;
     RECT  16.513 3.72 17.1 3.792 ;
     RECT  16.513 3.792 17.088 3.816 ;
     RECT  16.513 3.816 17.1 3.888 ;
     RECT  16.513 3.888 17.088 3.912 ;
     RECT  16.513 3.912 17.1 3.984 ;
     RECT  16.513 3.984 17.088 4.008 ;
     RECT  16.513 4.008 17.1 4.128 ;
     RECT  16.513 4.128 17.088 4.152 ;
     RECT  16.513 4.152 17.1 4.224 ;
     RECT  16.513 4.224 17.088 4.248 ;
     RECT  16.513 4.248 17.1 4.32 ;
     RECT  16.513 4.32 17.088 4.344 ;
     RECT  16.513 4.344 17.1 4.416 ;
     RECT  16.513 4.416 17.088 4.44 ;
     RECT  16.513 4.44 17.1 4.512 ;
     RECT  16.513 4.512 17.088 4.536 ;
     RECT  16.513 4.536 17.1 4.608 ;
     RECT  16.513 4.608 17.088 4.632 ;
     RECT  16.513 4.632 17.1 4.752 ;
     RECT  16.513 4.752 17.088 4.776 ;
     RECT  16.513 4.776 17.1 4.848 ;
     RECT  16.513 4.848 17.088 4.872 ;
     RECT  16.513 4.872 17.1 4.944 ;
     RECT  16.513 4.944 17.088 4.968 ;
     RECT  16.513 4.968 17.1 5.04 ;
     RECT  16.513 5.04 17.088 5.064 ;
     RECT  16.513 5.064 17.1 5.136 ;
     RECT  16.513 5.136 17.088 5.16 ;
     RECT  16.513 5.16 17.1 5.232 ;
     RECT  16.513 5.232 17.088 5.256 ;
     RECT  16.513 5.256 17.1 5.376 ;
     RECT  16.513 5.376 17.088 5.4 ;
     RECT  16.513 5.4 17.1 5.472 ;
     RECT  16.513 5.472 17.088 5.496 ;
     RECT  16.513 5.496 17.1 5.568 ;
     RECT  16.513 5.568 17.088 5.592 ;
     RECT  16.513 5.592 17.1 5.664 ;
     RECT  16.513 5.664 17.088 5.688 ;
     RECT  16.513 5.688 17.1 5.76 ;
     RECT  16.513 5.76 17.088 5.784 ;
     RECT  16.513 5.784 17.1 5.904 ;
     RECT  16.513 5.904 17.088 5.928 ;
     RECT  16.513 5.928 17.1 6 ;
     RECT  16.513 6 17.088 6.024 ;
     RECT  16.513 6.024 17.1 6.096 ;
     RECT  16.513 6.096 17.088 6.12 ;
     RECT  16.513 6.12 17.1 6.192 ;
     RECT  16.513 6.192 17.088 6.216 ;
     RECT  16.513 6.216 17.1 6.288 ;
     RECT  16.513 6.288 17.088 6.312 ;
     RECT  16.513 6.312 17.1 6.384 ;
     RECT  16.513 6.384 17.088 6.408 ;
     RECT  16.513 6.408 17.1 6.528 ;
     RECT  16.513 6.528 17.088 6.552 ;
     RECT  16.513 6.552 17.1 6.624 ;
     RECT  16.513 6.624 17.088 6.648 ;
     RECT  16.513 6.648 17.1 6.72 ;
     RECT  16.513 6.72 17.088 6.744 ;
     RECT  16.513 6.744 17.1 6.816 ;
     RECT  16.513 6.816 17.088 6.84 ;
     RECT  16.513 6.84 17.1 6.912 ;
     RECT  16.513 6.912 17.088 6.936 ;
     RECT  16.513 6.936 17.1 7.056 ;
     RECT  16.513 7.056 17.088 7.08 ;
     RECT  16.513 7.08 17.1 7.152 ;
     RECT  16.513 7.152 17.088 7.176 ;
     RECT  16.513 7.176 17.1 7.248 ;
     RECT  16.513 7.248 17.088 7.272 ;
     RECT  16.513 7.272 17.1 7.344 ;
     RECT  16.513 7.344 17.088 7.368 ;
     RECT  16.513 7.368 17.1 7.44 ;
     RECT  16.513 7.44 17.088 7.464 ;
     RECT  16.513 7.464 17.1 7.536 ;
     RECT  16.513 7.536 17.088 7.56 ;
     RECT  16.513 7.56 17.1 7.68 ;
     RECT  16.513 7.68 17.088 7.704 ;
     RECT  16.513 7.704 17.1 7.776 ;
     RECT  16.513 7.776 17.088 7.8 ;
     RECT  16.513 7.8 17.1 7.872 ;
     RECT  16.513 7.872 17.088 7.896 ;
     RECT  16.513 7.896 17.1 7.968 ;
     RECT  16.513 7.968 17.088 7.992 ;
     RECT  16.513 7.992 17.1 8.064 ;
     RECT  16.513 8.064 17.088 8.088 ;
     RECT  16.513 8.088 17.1 8.16 ;
     RECT  16.513 8.16 17.088 8.184 ;
     RECT  16.513 8.184 17.1 8.304 ;
     RECT  16.513 8.304 17.088 8.328 ;
     RECT  16.513 8.328 17.1 8.4 ;
     RECT  16.513 8.4 17.088 8.424 ;
     RECT  16.513 8.424 17.1 8.496 ;
     RECT  16.513 8.496 17.088 8.52 ;
     RECT  16.513 8.52 17.1 8.592 ;
     RECT  16.513 8.592 17.088 8.616 ;
     RECT  16.513 8.616 17.1 8.688 ;
     RECT  16.513 8.688 17.088 8.712 ;
     RECT  16.513 8.712 17.1 8.832 ;
     RECT  16.513 8.832 17.088 8.856 ;
     RECT  16.513 8.856 17.1 8.928 ;
     RECT  16.513 8.928 17.088 8.952 ;
     RECT  16.513 8.952 17.1 9.024 ;
     RECT  16.513 9.024 17.088 9.048 ;
     RECT  16.513 9.048 17.1 9.12 ;
     RECT  16.513 9.12 17.088 9.144 ;
     RECT  16.513 9.144 17.1 9.216 ;
     RECT  16.513 9.216 17.088 9.24 ;
     RECT  16.513 9.24 17.1 9.312 ;
     RECT  16.513 9.312 17.088 9.336 ;
     RECT  16.513 9.336 17.1 9.456 ;
     RECT  16.513 9.456 17.088 9.48 ;
     RECT  16.513 9.48 17.1 9.552 ;
     RECT  16.513 9.552 17.088 9.576 ;
     RECT  16.513 9.576 17.1 9.648 ;
     RECT  16.513 9.648 17.088 9.672 ;
     RECT  16.513 9.672 17.1 9.744 ;
     RECT  16.513 9.744 17.088 9.768 ;
     RECT  16.513 9.768 17.1 9.84 ;
     RECT  16.513 9.84 17.088 9.864 ;
     RECT  16.513 9.864 17.1 9.936 ;
     RECT  16.513 9.936 17.088 9.96 ;
     RECT  16.513 9.96 17.1 10.08 ;
     RECT  16.513 10.08 17.088 10.104 ;
     RECT  16.513 10.104 17.1 10.176 ;
     RECT  16.513 10.176 17.088 10.2 ;
     RECT  16.513 10.2 17.1 10.272 ;
     RECT  16.513 10.272 17.088 10.296 ;
     RECT  16.513 10.296 17.1 10.368 ;
     RECT  16.513 10.368 17.088 10.392 ;
     RECT  16.513 10.392 17.1 10.464 ;
     RECT  16.513 10.464 17.088 10.488 ;
     RECT  16.513 10.488 17.1 10.608 ;
     RECT  16.513 10.608 17.088 10.632 ;
     RECT  16.513 10.632 17.1 10.704 ;
     RECT  16.513 10.704 17.088 10.728 ;
     RECT  16.513 10.728 17.1 10.8 ;
     RECT  16.513 10.8 17.088 10.824 ;
     RECT  16.513 10.824 17.1 10.896 ;
     RECT  16.513 10.896 17.088 10.92 ;
     RECT  16.513 10.92 17.1 10.992 ;
     RECT  16.513 10.992 17.088 11.016 ;
     RECT  16.513 11.016 17.1 11.088 ;
     RECT  16.513 11.088 17.088 11.112 ;
     RECT  16.513 11.112 17.1 11.232 ;
     RECT  16.513 11.232 17.088 11.256 ;
     RECT  16.513 11.256 17.1 11.328 ;
     RECT  16.513 11.328 17.088 11.352 ;
     RECT  16.513 11.352 17.1 11.424 ;
     RECT  16.513 11.424 17.088 11.448 ;
     RECT  16.513 11.448 17.1 11.52 ;
     RECT  16.513 11.52 17.088 11.544 ;
     RECT  16.513 11.544 17.1 11.616 ;
     RECT  16.513 11.616 17.088 11.64 ;
     RECT  16.513 11.64 17.1 11.712 ;
     RECT  16.513 11.712 17.088 11.736 ;
     RECT  16.513 11.736 17.1 11.856 ;
     RECT  16.513 11.856 17.088 11.88 ;
     RECT  16.513 11.88 17.1 11.952 ;
     RECT  16.513 11.952 17.088 11.976 ;
     RECT  16.513 11.976 17.1 12.048 ;
     RECT  16.513 12.048 17.088 12.072 ;
     RECT  16.513 12.072 17.1 12.144 ;
     RECT  16.513 12.144 17.088 12.168 ;
     RECT  16.513 12.168 17.1 12.24 ;
     RECT  16.513 12.24 17.088 12.264 ;
     RECT  16.513 12.264 17.1 12.384 ;
     RECT  16.513 12.384 17.088 12.408 ;
     RECT  16.513 12.408 17.1 12.48 ;
     RECT  16.513 12.48 17.088 12.504 ;
     RECT  16.513 12.504 17.1 12.576 ;
     RECT  16.513 12.576 17.088 12.6 ;
     RECT  16.513 12.6 17.1 12.672 ;
     RECT  16.513 12.672 17.088 12.696 ;
     RECT  16.513 12.696 17.1 12.768 ;
     RECT  16.513 12.768 17.088 12.792 ;
     RECT  16.513 12.792 17.1 12.864 ;
     RECT  16.513 12.864 17.088 12.888 ;
     RECT  16.513 12.888 17.1 13.008 ;
     RECT  16.513 13.008 17.088 13.032 ;
     RECT  16.513 13.032 17.1 13.104 ;
     RECT  16.513 13.104 17.088 13.128 ;
     RECT  16.513 13.128 17.1 13.2 ;
     RECT  16.513 13.2 17.088 13.224 ;
     RECT  16.513 13.224 17.1 13.296 ;
     RECT  16.513 13.296 17.088 13.32 ;
     RECT  16.513 13.32 17.1 13.392 ;
     RECT  16.513 13.392 17.088 13.416 ;
     RECT  16.513 13.416 17.1 13.488 ;
     RECT  16.513 13.488 17.088 13.512 ;
     RECT  16.513 13.512 17.1 13.632 ;
     RECT  16.513 13.632 17.088 13.656 ;
     RECT  16.513 13.656 17.1 13.728 ;
     RECT  16.513 13.728 17.088 13.752 ;
     RECT  16.513 13.752 17.1 13.824 ;
     RECT  16.513 13.824 17.088 13.848 ;
     RECT  16.513 13.848 17.1 13.92 ;
     RECT  16.513 13.92 17.088 13.944 ;
     RECT  16.513 13.944 17.1 14.016 ;
     RECT  16.513 14.016 17.088 14.04 ;
     RECT  16.513 14.04 17.1 14.16 ;
     RECT  16.513 14.16 17.088 14.184 ;
     RECT  16.513 14.184 17.1 14.256 ;
     RECT  16.513 14.256 17.088 14.28 ;
     RECT  16.513 14.28 17.1 14.352 ;
     RECT  16.513 14.352 17.088 14.376 ;
     RECT  16.513 14.376 17.1 14.448 ;
     RECT  16.513 14.448 17.088 14.472 ;
     RECT  16.513 14.472 17.1 14.544 ;
     RECT  16.513 14.544 17.088 14.568 ;
     RECT  16.513 14.568 17.1 14.64 ;
     RECT  16.513 14.64 17.088 14.664 ;
     RECT  16.513 14.664 17.1 14.784 ;
     RECT  16.513 14.784 17.088 14.808 ;
     RECT  16.513 14.808 17.1 14.88 ;
     RECT  16.513 14.88 17.088 14.904 ;
     RECT  16.513 14.904 17.1 14.976 ;
     RECT  16.513 14.976 17.088 15 ;
     RECT  16.513 15 17.1 15.072 ;
     RECT  16.513 15.072 17.088 15.096 ;
     RECT  16.513 15.096 17.1 15.168 ;
     RECT  16.513 15.168 17.088 15.192 ;
     RECT  16.513 15.192 17.1 15.312 ;
     RECT  16.513 15.312 17.088 15.336 ;
     RECT  16.513 15.336 17.1 15.408 ;
     RECT  16.513 15.408 17.088 15.432 ;
     RECT  16.513 15.432 17.1 15.504 ;
     RECT  16.513 15.504 17.088 15.528 ;
     RECT  16.513 15.528 17.1 15.6 ;
     RECT  16.513 15.6 17.088 15.624 ;
     RECT  16.513 15.624 17.1 15.696 ;
     RECT  16.513 15.696 17.088 15.72 ;
     RECT  16.513 15.72 17.1 15.792 ;
     RECT  16.513 15.792 17.088 15.816 ;
     RECT  16.513 15.816 17.1 15.936 ;
     RECT  16.513 15.936 17.088 15.96 ;
     RECT  16.513 15.96 17.1 16.032 ;
     RECT  16.513 16.032 17.088 16.056 ;
     RECT  16.513 16.056 17.1 16.128 ;
     RECT  16.513 16.128 17.088 16.152 ;
     RECT  16.513 16.152 17.1 16.224 ;
     RECT  16.513 16.224 17.088 16.248 ;
     RECT  16.513 16.248 17.1 16.32 ;
     RECT  16.513 16.32 17.088 16.344 ;
     RECT  16.513 16.344 17.1 16.416 ;
     RECT  16.513 16.416 17.088 16.44 ;
     RECT  16.513 16.44 17.1 16.56 ;
     RECT  16.513 16.56 17.088 16.584 ;
     RECT  16.513 16.584 17.1 16.656 ;
     RECT  16.513 16.656 17.088 16.68 ;
     RECT  16.513 16.68 17.1 16.752 ;
     RECT  16.513 16.752 17.088 16.776 ;
     RECT  16.513 16.776 17.1 16.848 ;
     RECT  16.513 16.848 17.088 16.872 ;
     RECT  16.513 16.872 17.1 16.944 ;
     RECT  16.513 16.944 17.088 16.968 ;
     RECT  16.513 16.968 17.1 17.088 ;
     RECT  16.513 17.088 17.088 17.112 ;
     RECT  16.513 17.112 17.1 17.184 ;
     RECT  16.513 17.184 17.088 17.208 ;
     RECT  16.513 17.208 17.1 17.28 ;
     RECT  16.513 17.28 17.088 17.304 ;
     RECT  16.513 17.304 17.1 17.376 ;
     RECT  16.513 17.376 17.088 17.4 ;
     RECT  16.513 17.4 17.1 17.472 ;
     RECT  16.513 17.472 17.088 17.496 ;
     RECT  16.513 17.496 17.1 17.568 ;
     RECT  16.513 17.568 17.088 17.592 ;
     RECT  16.513 17.592 17.1 17.712 ;
     RECT  16.513 17.712 17.088 17.736 ;
     RECT  16.513 17.736 17.1 17.808 ;
     RECT  16.513 17.808 17.088 17.832 ;
     RECT  16.513 17.832 17.1 17.904 ;
     RECT  16.513 17.904 17.088 17.928 ;
     RECT  16.513 17.928 17.1 18 ;
     RECT  16.513 18 17.088 18.024 ;
     RECT  16.513 18.024 17.1 18.096 ;
     RECT  16.513 18.096 17.088 18.12 ;
     RECT  16.513 18.12 17.1 18.192 ;
     RECT  16.513 18.192 17.088 18.216 ;
     RECT  16.513 18.216 17.1 18.336 ;
     RECT  16.513 18.336 17.088 18.36 ;
     RECT  16.513 18.36 17.1 18.432 ;
     RECT  16.513 18.432 17.088 18.456 ;
     RECT  16.513 18.456 17.1 18.528 ;
     RECT  16.513 18.528 17.088 18.552 ;
     RECT  16.513 18.552 17.1 18.624 ;
     RECT  16.513 18.624 17.088 18.648 ;
     RECT  16.513 18.648 17.1 18.72 ;
     RECT  16.513 18.72 17.088 18.744 ;
     RECT  16.513 18.744 17.1 18.864 ;
     RECT  16.513 18.864 17.088 18.888 ;
     RECT  16.513 18.888 17.1 18.96 ;
     RECT  16.513 18.96 17.088 18.984 ;
     RECT  16.513 18.984 17.1 19.056 ;
     RECT  16.513 19.056 17.088 19.08 ;
     RECT  16.513 19.08 17.1 19.152 ;
     RECT  16.513 19.152 17.088 19.176 ;
     RECT  16.513 19.176 17.1 19.248 ;
     RECT  16.513 19.248 17.088 19.272 ;
     RECT  16.513 19.272 17.1 19.344 ;
     RECT  16.513 19.344 17.088 19.368 ;
     RECT  16.513 19.368 17.1 19.488 ;
     RECT  16.513 19.488 17.088 19.512 ;
     RECT  16.513 19.512 17.1 19.584 ;
     RECT  16.513 19.584 17.088 19.608 ;
     RECT  16.513 19.608 17.1 19.68 ;
     RECT  16.513 19.68 17.088 19.704 ;
     RECT  16.513 19.704 17.1 19.776 ;
     RECT  16.513 19.776 17.088 19.8 ;
     RECT  16.513 19.8 17.1 19.872 ;
     RECT  16.513 19.872 17.088 19.896 ;
     RECT  16.513 19.896 17.1 20.016 ;
     RECT  16.513 20.016 17.088 20.04 ;
     RECT  16.513 20.04 17.1 20.112 ;
     RECT  16.513 20.112 17.088 20.136 ;
     RECT  16.513 20.136 17.1 20.208 ;
     RECT  16.513 20.208 17.088 20.232 ;
     RECT  16.513 20.232 17.1 20.304 ;
     RECT  16.513 20.304 17.088 20.328 ;
     RECT  16.513 20.328 17.1 20.4 ;
     RECT  16.513 20.4 17.088 20.424 ;
     RECT  16.513 20.424 17.1 20.496 ;
     RECT  16.513 20.496 17.088 20.52 ;
     RECT  16.513 20.52 17.1 20.64 ;
     RECT  16.513 20.64 17.088 20.664 ;
     RECT  16.513 20.664 17.1 20.736 ;
     RECT  16.513 20.736 17.088 20.76 ;
     RECT  16.513 20.76 17.1 20.832 ;
     RECT  16.513 20.832 17.088 20.856 ;
     RECT  16.513 20.856 17.1 20.928 ;
     RECT  16.513 20.928 17.088 20.952 ;
     RECT  16.513 20.952 17.1 21.024 ;
     RECT  16.513 21.024 17.088 21.048 ;
     RECT  16.513 21.048 17.1 21.12 ;
     RECT  16.513 21.12 17.088 21.144 ;
     RECT  16.513 21.144 17.1 21.264 ;
     RECT  16.513 21.264 17.088 21.288 ;
     RECT  16.513 21.288 17.1 21.36 ;
     RECT  16.513 21.36 17.088 21.384 ;
     RECT  16.513 21.384 17.1 21.456 ;
     RECT  16.513 21.456 17.088 21.48 ;
     RECT  16.513 21.48 17.1 21.552 ;
     RECT  16.513 21.552 17.088 21.576 ;
     RECT  16.513 21.576 17.1 21.648 ;
     RECT  16.513 21.648 17.088 21.672 ;
     RECT  16.513 21.672 17.1 21.792 ;
     RECT  16.513 21.792 17.088 21.816 ;
     RECT  16.513 21.816 17.1 21.888 ;
     RECT  16.513 21.888 17.088 21.912 ;
     RECT  16.513 21.912 17.1 21.984 ;
     RECT  16.513 21.984 17.088 22.008 ;
     RECT  16.513 22.008 17.1 22.08 ;
     RECT  16.513 22.08 17.088 22.104 ;
     RECT  16.513 22.104 17.1 22.176 ;
     RECT  16.513 22.176 17.088 22.2 ;
     RECT  16.513 22.2 17.1 22.272 ;
     RECT  16.513 22.272 17.088 22.296 ;
     RECT  16.513 22.296 17.1 22.416 ;
     RECT  16.513 22.416 17.088 22.44 ;
     RECT  16.513 22.44 17.1 22.512 ;
     RECT  16.513 22.512 17.088 22.536 ;
     RECT  16.513 22.536 17.1 22.608 ;
     RECT  16.513 22.608 17.088 22.632 ;
     RECT  16.513 22.632 17.1 22.704 ;
     RECT  16.513 22.704 17.088 22.728 ;
     RECT  16.513 22.728 17.1 22.8 ;
     RECT  16.513 22.8 17.088 22.824 ;
     RECT  16.513 22.824 17.1 22.896 ;
     RECT  16.513 22.896 17.088 22.92 ;
     RECT  16.513 22.92 17.1 23.04 ;
     RECT  16.513 23.04 17.088 23.064 ;
     RECT  16.513 23.064 17.1 23.136 ;
     RECT  16.513 23.136 17.088 23.16 ;
     RECT  16.513 23.16 17.1 23.232 ;
     RECT  16.513 23.232 17.088 23.256 ;
     RECT  16.513 23.256 17.1 23.328 ;
     RECT  16.513 23.328 17.088 23.352 ;
     RECT  16.513 23.352 17.1 23.424 ;
     RECT  16.513 23.424 17.088 23.448 ;
     RECT  16.513 23.448 17.1 23.568 ;
     RECT  16.513 23.568 17.088 23.592 ;
     RECT  16.513 23.592 17.1 23.664 ;
     RECT  16.513 23.664 17.088 23.688 ;
     RECT  16.513 23.688 17.1 23.76 ;
     RECT  16.513 23.76 17.088 23.784 ;
     RECT  16.513 23.784 17.1 23.856 ;
     RECT  16.513 23.856 17.088 23.88 ;
     RECT  16.513 23.88 17.1 23.952 ;
     RECT  16.513 23.952 17.088 23.976 ;
     RECT  16.513 23.976 17.1 24.048 ;
     RECT  16.513 24.048 17.088 24.072 ;
     RECT  16.513 24.072 17.1 24.192 ;
     RECT  16.513 24.192 17.088 24.216 ;
     RECT  16.513 24.216 17.1 24.288 ;
     RECT  16.513 24.288 17.088 24.312 ;
     RECT  16.513 24.312 17.1 24.384 ;
     RECT  16.513 24.384 17.088 24.408 ;
     RECT  16.513 24.408 17.1 24.48 ;
     RECT  16.513 24.48 17.088 24.504 ;
     RECT  16.513 24.504 17.1 24.576 ;
     RECT  16.513 24.576 17.088 24.6 ;
     RECT  16.513 24.6 17.1 24.672 ;
     RECT  16.513 24.672 17.088 24.696 ;
     RECT  16.513 24.696 17.1 24.816 ;
     RECT  16.513 24.816 17.088 24.84 ;
     RECT  16.513 24.84 17.1 24.912 ;
     RECT  16.513 24.912 17.088 24.936 ;
     RECT  16.513 24.936 17.1 25.008 ;
     RECT  16.513 25.008 17.088 25.032 ;
     RECT  16.513 25.032 17.1 25.104 ;
     RECT  16.513 25.104 17.088 25.128 ;
     RECT  16.513 25.128 17.1 25.2 ;
     RECT  16.513 25.2 17.088 25.224 ;
     RECT  16.513 25.224 17.1 25.344 ;
     RECT  16.513 25.344 17.088 25.368 ;
     RECT  16.513 25.368 17.1 25.44 ;
     RECT  16.513 25.44 17.088 25.464 ;
     RECT  16.513 25.464 17.1 25.536 ;
     RECT  16.513 25.536 17.088 25.56 ;
     RECT  16.513 25.56 17.1 25.632 ;
     RECT  16.513 25.632 17.088 25.656 ;
     RECT  16.513 25.656 17.1 25.728 ;
     RECT  16.513 25.728 17.088 25.752 ;
     RECT  16.513 25.752 17.1 25.824 ;
     RECT  16.513 25.824 17.088 25.848 ;
     RECT  16.513 25.848 17.1 25.968 ;
     RECT  16.513 25.968 17.088 25.992 ;
     RECT  16.513 25.992 17.1 26.064 ;
     RECT  16.513 26.064 17.088 26.088 ;
     RECT  16.513 26.088 17.1 26.16 ;
     RECT  16.513 26.16 17.088 26.184 ;
     RECT  16.513 26.184 17.1 26.256 ;
     RECT  16.513 26.256 17.088 26.28 ;
     RECT  16.513 26.28 17.1 26.352 ;
     RECT  16.513 26.352 17.088 26.376 ;
     RECT  16.513 26.376 17.1 26.448 ;
     RECT  16.513 26.448 17.088 26.472 ;
     RECT  16.513 26.472 17.1 26.592 ;
     RECT  16.513 26.592 17.088 26.616 ;
     RECT  16.513 26.616 17.1 26.688 ;
     RECT  16.513 26.688 17.088 26.712 ;
     RECT  16.513 26.712 17.1 26.784 ;
     RECT  16.513 26.784 17.088 26.808 ;
     RECT  16.513 26.808 17.1 26.88 ;
     RECT  16.513 26.88 17.088 26.904 ;
     RECT  16.513 26.904 17.1 26.976 ;
     RECT  16.513 26.976 17.088 27 ;
     RECT  16.513 27 17.1 27.12 ;
     RECT  16.513 27.12 17.088 27.144 ;
     RECT  16.513 27.144 17.1 27.216 ;
     RECT  16.513 27.216 17.088 27.24 ;
     RECT  16.513 27.24 17.1 27.312 ;
     RECT  16.513 27.312 17.088 27.336 ;
     RECT  16.513 27.336 17.1 27.408 ;
     RECT  16.513 27.408 17.088 27.432 ;
     RECT  16.513 27.432 17.1 27.504 ;
     RECT  16.513 27.504 17.088 27.528 ;
     RECT  16.513 27.528 17.1 27.6 ;
     RECT  16.513 27.6 17.088 27.624 ;
     RECT  16.513 27.624 17.1 27.744 ;
     RECT  16.513 27.744 17.088 27.768 ;
     RECT  16.513 27.768 17.1 27.84 ;
     RECT  16.513 27.84 17.088 27.864 ;
     RECT  16.513 27.864 17.1 27.936 ;
     RECT  16.513 27.936 17.088 27.96 ;
     RECT  16.513 27.96 17.1 28.032 ;
     RECT  16.513 28.032 17.088 28.056 ;
     RECT  16.513 28.056 17.1 28.128 ;
     RECT  16.513 28.128 17.088 28.152 ;
     RECT  16.513 28.152 17.1 28.272 ;
     RECT  16.513 28.272 17.088 28.296 ;
     RECT  16.513 28.296 17.1 28.368 ;
     RECT  16.513 28.368 17.088 28.392 ;
     RECT  16.513 28.392 17.1 28.464 ;
     RECT  16.513 28.464 17.088 28.488 ;
     RECT  16.513 28.488 17.1 28.56 ;
     RECT  16.513 28.56 17.088 28.584 ;
     RECT  16.513 28.584 17.1 28.656 ;
     RECT  16.513 28.656 17.088 28.68 ;
     RECT  16.513 28.68 17.1 28.752 ;
     RECT  16.513 28.752 17.088 28.776 ;
     RECT  16.513 28.776 17.1 28.896 ;
     RECT  16.513 28.896 17.088 28.92 ;
     RECT  16.513 28.92 17.1 28.992 ;
     RECT  16.513 28.992 17.088 29.016 ;
     RECT  16.513 29.016 17.1 29.088 ;
     RECT  16.513 29.088 17.088 29.112 ;
     RECT  16.513 29.112 17.1 29.184 ;
     RECT  16.513 29.184 17.088 29.208 ;
     RECT  16.513 29.208 17.1 29.28 ;
     RECT  16.513 29.28 17.088 29.304 ;
     RECT  16.513 29.304 17.1 29.376 ;
     RECT  16.513 29.376 17.088 29.4 ;
     RECT  16.513 29.4 17.1 29.52 ;
     RECT  16.513 29.52 17.088 29.544 ;
     RECT  16.513 29.544 17.1 29.616 ;
     RECT  16.513 29.616 17.088 29.64 ;
     RECT  16.513 29.64 17.1 29.712 ;
     RECT  16.513 29.712 17.088 29.736 ;
     RECT  16.513 29.736 17.1 29.808 ;
     RECT  16.513 29.808 17.088 29.832 ;
     RECT  16.513 29.832 17.1 29.904 ;
     RECT  16.513 29.904 17.088 29.928 ;
     RECT  16.513 29.928 17.1 30.048 ;
     RECT  16.513 30.048 17.088 30.072 ;
     RECT  16.513 30.072 17.1 30.144 ;
     RECT  16.513 30.144 17.088 30.168 ;
     RECT  16.513 30.168 17.1 30.24 ;
     RECT  16.513 30.24 17.088 30.264 ;
     RECT  16.513 30.264 17.1 30.336 ;
     RECT  16.513 30.336 17.088 30.36 ;
     RECT  16.513 30.36 17.1 30.432 ;
     RECT  16.513 30.432 17.088 30.456 ;
     RECT  16.513 30.456 17.1 30.528 ;
     RECT  16.513 30.528 17.088 30.552 ;
     RECT  16.513 30.552 17.1 30.672 ;
     RECT  16.513 30.672 17.088 30.696 ;
     RECT  16.513 30.696 17.1 30.768 ;
     RECT  16.513 30.768 17.088 30.792 ;
     RECT  16.513 30.792 17.1 30.864 ;
     RECT  16.513 30.864 17.088 30.888 ;
     RECT  16.513 30.888 17.1 30.96 ;
     RECT  16.513 30.96 17.088 30.984 ;
     RECT  16.513 30.984 17.1 31.056 ;
     RECT  16.513 31.056 17.088 31.08 ;
     RECT  16.513 31.08 17.1 31.152 ;
     RECT  16.513 31.152 17.088 31.176 ;
     RECT  16.513 31.176 17.1 31.296 ;
     RECT  16.513 31.296 17.088 31.32 ;
     RECT  16.513 31.32 17.1 31.392 ;
     RECT  16.513 31.392 17.088 31.416 ;
     RECT  16.513 31.416 17.1 31.488 ;
     RECT  16.513 31.488 17.088 31.512 ;
     RECT  16.513 31.512 17.1 31.584 ;
     RECT  16.513 31.584 17.088 31.608 ;
     RECT  16.513 31.608 17.1 31.68 ;
     RECT  16.513 31.68 17.088 31.704 ;
     RECT  16.513 31.704 17.1 31.824 ;
     RECT  16.513 31.824 17.088 31.848 ;
     RECT  16.513 31.848 17.1 31.92 ;
     RECT  16.513 31.92 17.088 31.944 ;
     RECT  16.513 31.944 17.1 32.016 ;
     RECT  16.513 32.016 17.088 32.04 ;
     RECT  16.513 32.04 17.1 32.112 ;
     RECT  16.513 32.112 17.088 32.136 ;
     RECT  16.513 32.136 17.1 32.208 ;
     RECT  16.513 32.208 17.088 32.232 ;
     RECT  16.513 32.232 17.1 32.304 ;
     RECT  16.513 32.304 17.088 32.328 ;
     RECT  16.513 32.328 17.1 32.448 ;
     RECT  16.513 32.448 17.088 32.472 ;
     RECT  16.513 32.472 17.1 32.544 ;
     RECT  16.513 32.544 17.088 32.568 ;
     RECT  16.513 32.568 17.1 32.64 ;
     RECT  16.513 32.64 17.088 32.664 ;
     RECT  16.513 32.664 17.1 32.736 ;
     RECT  16.513 32.736 17.088 32.76 ;
     RECT  16.513 32.76 17.1 32.832 ;
     RECT  16.513 32.832 17.088 32.856 ;
     RECT  16.513 32.856 17.1 32.928 ;
     RECT  16.513 32.928 17.088 32.952 ;
     RECT  16.513 32.952 17.1 33.072 ;
     RECT  16.513 33.072 17.088 33.096 ;
     RECT  16.513 33.096 17.1 33.168 ;
     RECT  16.513 33.168 17.088 33.192 ;
     RECT  16.513 33.192 17.1 33.264 ;
     RECT  16.513 33.264 17.088 33.288 ;
     RECT  16.513 33.288 17.1 33.36 ;
     RECT  16.513 33.36 17.088 33.384 ;
     RECT  16.513 33.384 17.1 33.456 ;
     RECT  16.513 33.456 17.088 33.48 ;
     RECT  16.513 33.48 17.1 33.6 ;
     RECT  16.513 33.6 17.088 33.624 ;
     RECT  16.513 33.624 17.1 33.696 ;
     RECT  16.513 33.696 17.088 33.72 ;
     RECT  16.513 33.72 17.1 33.792 ;
     RECT  16.513 33.792 17.088 33.816 ;
     RECT  16.513 33.816 17.1 33.888 ;
     RECT  16.513 33.888 17.088 33.912 ;
     RECT  16.513 33.912 17.1 33.984 ;
     RECT  16.513 33.984 17.088 34.008 ;
     RECT  16.513 34.008 17.1 34.08 ;
     RECT  16.513 34.08 17.088 34.104 ;
     RECT  16.513 34.104 17.1 34.224 ;
     RECT  16.513 34.224 17.088 34.248 ;
     RECT  16.513 34.248 17.1 34.32 ;
     RECT  16.513 34.32 17.088 34.344 ;
     RECT  16.513 34.344 17.1 34.416 ;
     RECT  16.513 34.416 17.088 34.44 ;
     RECT  16.513 34.44 17.1 34.512 ;
     RECT  16.513 34.512 17.088 34.536 ;
     RECT  16.513 34.536 17.1 34.608 ;
     RECT  16.513 34.608 17.088 34.632 ;
     RECT  16.513 34.632 17.1 34.752 ;
     RECT  16.513 34.752 17.088 34.776 ;
     RECT  16.513 34.776 17.1 34.848 ;
     RECT  16.513 34.848 17.088 34.872 ;
     RECT  16.513 34.872 17.1 34.944 ;
     RECT  16.513 34.944 17.088 34.968 ;
     RECT  16.513 34.968 17.1 35.04 ;
     RECT  16.513 35.04 17.088 35.064 ;
     RECT  16.513 35.064 17.1 35.136 ;
     RECT  16.513 35.136 17.088 35.16 ;
     RECT  16.513 35.16 17.1 35.232 ;
     RECT  16.513 35.232 17.088 35.256 ;
     RECT  16.513 35.256 17.1 35.376 ;
     RECT  16.513 35.376 17.088 35.4 ;
     RECT  16.513 35.4 17.1 35.472 ;
     RECT  16.513 35.472 17.088 35.496 ;
     RECT  16.513 35.496 17.1 35.568 ;
     RECT  16.513 35.568 17.088 35.592 ;
     RECT  16.513 35.592 17.1 35.664 ;
     RECT  16.513 35.664 17.088 35.688 ;
     RECT  16.513 35.688 17.1 35.76 ;
     RECT  16.513 35.76 17.088 35.784 ;
     RECT  16.513 35.784 17.1 35.856 ;
     RECT  16.513 35.856 17.088 35.88 ;
     RECT  16.513 35.88 17.1 36 ;
     RECT  16.513 36 17.088 36.024 ;
     RECT  16.513 36.024 17.1 36.096 ;
     RECT  16.513 36.096 17.088 36.12 ;
     RECT  16.513 36.12 17.1 36.192 ;
     RECT  16.513 36.192 17.088 36.216 ;
     RECT  16.513 36.216 17.1 36.288 ;
     RECT  16.513 36.288 17.088 36.312 ;
     RECT  16.513 36.312 17.1 36.384 ;
     RECT  16.513 36.384 17.088 36.408 ;
     RECT  16.513 36.408 17.1 36.528 ;
     RECT  16.513 36.528 17.088 36.552 ;
     RECT  16.513 36.552 17.1 36.624 ;
     RECT  16.513 36.624 17.088 36.648 ;
     RECT  16.513 36.648 17.1 36.72 ;
     RECT  16.513 36.72 17.088 36.744 ;
     RECT  16.513 36.744 17.1 36.816 ;
     RECT  16.513 36.816 17.088 36.84 ;
     RECT  16.513 36.84 17.1 36.912 ;
     RECT  16.513 36.912 17.088 36.936 ;
     RECT  16.513 36.936 17.1 37.008 ;
     RECT  16.513 37.008 17.088 37.032 ;
     RECT  16.513 37.032 17.1 37.152 ;
     RECT  16.513 37.152 17.088 37.176 ;
     RECT  16.513 37.176 17.1 37.248 ;
     RECT  16.513 37.248 17.088 37.272 ;
     RECT  16.513 37.272 17.1 37.344 ;
     RECT  16.513 37.344 17.088 37.368 ;
     RECT  16.513 37.368 17.1 37.44 ;
     RECT  16.513 37.44 17.088 37.464 ;
     RECT  16.513 37.464 17.1 37.536 ;
     RECT  16.513 37.536 17.088 37.56 ;
     RECT  16.513 37.56 17.1 37.632 ;
     RECT  16.513 37.632 17.088 37.656 ;
     RECT  16.513 37.656 17.1 37.776 ;
     RECT  16.513 37.776 17.088 37.8 ;
     RECT  16.513 37.8 17.1 37.872 ;
     RECT  16.513 37.872 17.088 37.896 ;
     RECT  16.513 37.896 17.1 37.968 ;
     RECT  16.513 37.968 17.088 37.992 ;
     RECT  16.513 37.992 17.1 38.064 ;
     RECT  16.513 38.064 17.088 38.088 ;
     RECT  16.513 38.088 17.1 38.16 ;
     RECT  16.513 38.16 17.088 38.184 ;
     RECT  16.513 38.184 17.1 38.304 ;
     RECT  16.513 38.304 17.088 38.328 ;
     RECT  16.513 38.328 17.1 38.4 ;
     RECT  16.513 38.4 17.088 38.424 ;
     RECT  16.513 38.424 17.1 38.496 ;
     RECT  16.513 38.496 17.088 38.52 ;
     RECT  16.513 38.52 17.1 38.592 ;
     RECT  16.513 38.592 17.088 38.616 ;
     RECT  16.513 38.616 17.1 38.688 ;
     RECT  16.513 38.688 17.088 38.712 ;
     RECT  16.513 38.712 17.1 38.784 ;
     RECT  16.513 38.784 17.088 38.808 ;
     RECT  16.513 38.808 17.1 38.928 ;
     RECT  16.513 38.928 17.088 38.952 ;
     RECT  16.513 38.952 17.1 39.024 ;
     RECT  16.513 39.024 17.088 39.048 ;
     RECT  16.513 39.048 17.1 39.12 ;
     RECT  16.513 39.12 17.088 39.144 ;
     RECT  16.513 39.144 17.1 39.216 ;
     RECT  16.513 39.216 17.088 39.24 ;
     RECT  16.513 39.24 17.1 39.312 ;
     RECT  16.513 39.312 17.088 39.336 ;
     RECT  16.513 39.336 17.1 39.408 ;
     RECT  16.513 39.408 17.088 39.432 ;
     RECT  16.513 39.432 17.1 39.552 ;
     RECT  16.513 39.552 17.088 39.576 ;
     RECT  16.513 39.576 17.1 39.648 ;
     RECT  16.513 39.648 17.088 39.672 ;
     RECT  16.513 39.672 17.1 39.744 ;
     RECT  16.513 39.744 17.088 39.768 ;
     RECT  16.513 39.768 17.1 39.84 ;
     RECT  16.513 39.84 17.088 39.864 ;
     RECT  16.513 39.864 17.1 39.936 ;
     RECT  16.513 39.936 17.088 39.96 ;
     RECT  16.513 39.96 17.1 40.08 ;
     RECT  16.513 40.08 17.088 40.104 ;
     RECT  16.513 40.104 17.1 40.176 ;
     RECT  16.513 40.176 17.088 40.2 ;
     RECT  16.513 40.2 17.1 40.272 ;
     RECT  16.513 40.272 17.088 40.296 ;
     RECT  16.513 40.296 17.1 40.368 ;
     RECT  16.513 40.368 17.088 40.392 ;
     RECT  16.513 40.392 17.1 40.464 ;
     RECT  16.513 40.464 17.088 40.488 ;
     RECT  16.513 40.488 17.1 40.56 ;
     RECT  16.513 40.56 17.088 40.584 ;
     RECT  16.513 40.584 17.1 40.704 ;
     RECT  16.513 40.704 17.088 40.728 ;
     RECT  16.513 40.728 17.1 40.8 ;
     RECT  16.513 40.8 17.088 40.824 ;
     RECT  16.513 40.824 17.1 40.896 ;
     RECT  16.513 40.896 17.088 40.92 ;
     RECT  16.513 40.92 17.1 40.992 ;
     RECT  16.513 40.992 17.088 41.016 ;
     RECT  16.513 41.016 17.1 41.088 ;
     RECT  16.513 41.088 17.088 41.112 ;
     RECT  16.513 41.112 17.1 41.232 ;
     RECT  16.513 41.232 17.088 41.256 ;
     RECT  16.513 41.256 17.1 41.328 ;
     RECT  16.513 41.328 17.088 41.352 ;
     RECT  16.513 41.352 17.1 41.424 ;
     RECT  16.513 41.424 17.088 41.448 ;
     RECT  16.513 41.448 17.1 41.52 ;
     RECT  16.513 41.52 17.088 41.544 ;
     RECT  16.513 41.544 17.1 41.616 ;
     RECT  16.513 41.616 17.088 41.64 ;
     RECT  16.513 41.64 17.1 41.712 ;
     RECT  16.513 41.712 17.088 41.736 ;
     RECT  16.513 41.736 17.1 41.856 ;
     RECT  16.513 41.856 17.088 41.88 ;
     RECT  16.513 41.88 17.1 41.952 ;
     RECT  16.513 41.952 17.088 41.976 ;
     RECT  16.513 41.976 17.1 42.048 ;
     RECT  16.513 42.048 17.088 42.072 ;
     RECT  16.513 42.072 17.1 42.144 ;
     RECT  16.513 42.144 17.088 42.168 ;
     RECT  16.513 42.168 17.1 42.24 ;
     RECT  16.513 42.24 17.088 42.264 ;
     RECT  16.513 42.264 17.1 42.336 ;
     RECT  16.513 42.336 17.088 42.36 ;
     RECT  16.513 42.36 17.1 42.48 ;
     RECT  16.513 42.48 17.088 42.504 ;
     RECT  16.513 42.504 17.1 42.576 ;
     RECT  16.513 42.576 17.088 42.6 ;
     RECT  16.513 42.6 17.1 42.672 ;
     RECT  16.513 42.672 17.088 42.696 ;
     RECT  16.513 42.696 17.1 42.768 ;
     RECT  16.513 42.768 17.088 42.792 ;
     RECT  16.513 42.792 17.1 42.864 ;
     RECT  16.513 42.864 17.088 42.888 ;
     RECT  16.513 42.888 17.1 43.008 ;
     RECT  16.513 43.008 17.088 43.032 ;
     RECT  16.513 43.032 17.1 43.104 ;
     RECT  16.513 43.104 17.088 43.128 ;
     RECT  16.513 43.128 17.1 43.2 ;
     RECT  16.513 43.2 17.088 43.224 ;
     RECT  16.513 43.224 17.1 43.296 ;
     RECT  16.513 43.296 17.088 43.32 ;
     RECT  16.513 43.32 17.1 43.392 ;
     RECT  16.513 43.392 17.088 43.416 ;
     RECT  16.513 43.416 17.1 43.488 ;
     RECT  16.513 43.488 17.088 43.512 ;
     RECT  16.513 43.512 17.1 43.632 ;
     RECT  16.513 43.632 17.088 43.656 ;
     RECT  16.513 43.656 17.1 43.728 ;
     RECT  16.513 43.728 17.088 43.752 ;
     RECT  16.513 43.752 17.1 43.824 ;
     RECT  16.513 43.824 17.088 43.848 ;
     RECT  16.513 43.848 17.1 43.92 ;
     RECT  16.513 43.92 17.088 43.944 ;
     RECT  16.513 43.944 17.1 44.016 ;
     RECT  16.513 44.016 17.088 44.04 ;
     RECT  16.513 44.04 17.1 44.112 ;
     RECT  16.513 44.112 17.088 44.136 ;
     RECT  16.513 44.136 17.1 44.256 ;
     RECT  16.513 44.256 17.088 44.28 ;
     RECT  16.513 44.28 17.1 44.352 ;
     RECT  16.513 44.352 17.088 44.376 ;
     RECT  16.513 44.376 17.1 44.448 ;
     RECT  16.513 44.448 17.088 44.472 ;
     RECT  16.513 44.472 17.1 44.544 ;
     RECT  16.513 44.544 17.088 44.568 ;
     RECT  16.513 44.568 17.1 44.64 ;
     RECT  16.513 44.64 17.088 44.664 ;
     RECT  16.513 44.664 17.1 44.784 ;
     RECT  16.513 44.784 17.088 44.808 ;
     RECT  16.513 44.808 17.1 44.88 ;
     RECT  16.513 44.88 17.088 44.904 ;
     RECT  16.513 44.904 17.1 44.976 ;
     RECT  16.513 44.976 17.088 45 ;
     RECT  16.513 45 17.1 45.072 ;
     RECT  16.513 45.072 17.088 45.096 ;
     RECT  16.513 45.096 17.1 45.168 ;
     RECT  16.513 45.168 17.088 45.192 ;
     RECT  16.513 45.192 17.1 45.264 ;
     RECT  16.513 45.264 17.088 45.288 ;
     RECT  16.513 45.288 17.1 45.408 ;
     RECT  16.513 45.408 17.088 45.432 ;
     RECT  16.513 45.432 17.1 45.504 ;
     RECT  16.513 45.504 17.088 45.528 ;
     RECT  16.513 45.528 17.1 45.6 ;
     RECT  16.513 45.6 17.088 45.624 ;
     RECT  16.513 45.624 17.1 45.696 ;
     RECT  16.513 45.696 17.088 45.72 ;
     RECT  16.513 45.72 17.1 45.792 ;
     RECT  16.513 45.792 17.088 45.816 ;
     RECT  16.513 45.816 17.1 45.936 ;
     RECT  16.513 45.936 17.088 45.96 ;
     RECT  16.513 45.96 17.1 46.032 ;
     RECT  16.513 46.032 17.088 46.056 ;
     RECT  16.513 46.056 17.1 46.128 ;
     RECT  16.513 46.128 17.088 46.152 ;
     RECT  16.513 46.152 17.1 46.224 ;
     RECT  16.513 46.224 17.088 46.248 ;
     RECT  16.513 46.248 17.1 46.32 ;
     RECT  16.513 46.32 17.088 46.344 ;
     RECT  16.513 46.344 17.1 46.416 ;
     RECT  16.513 46.416 17.088 46.44 ;
     RECT  16.513 46.44 17.1 46.56 ;
     RECT  16.513 46.56 17.088 46.584 ;
     RECT  16.513 46.584 17.1 46.656 ;
     RECT  16.513 46.656 17.088 46.68 ;
     RECT  16.513 46.68 17.1 46.752 ;
     RECT  16.513 46.752 17.088 46.776 ;
     RECT  16.513 46.776 17.1 46.848 ;
     RECT  16.513 46.848 17.088 46.872 ;
     RECT  16.513 46.872 17.1 46.944 ;
     RECT  16.513 46.944 17.088 46.968 ;
     RECT  16.513 46.968 17.1 47.04 ;
     RECT  16.513 47.04 17.088 47.064 ;
     RECT  16.513 47.064 17.1 47.184 ;
     RECT  16.513 47.184 17.088 47.208 ;
     RECT  16.513 47.208 17.1 47.28 ;
     RECT  16.513 47.28 17.088 47.304 ;
     RECT  16.513 47.304 17.1 47.376 ;
     RECT  16.513 47.376 17.088 47.4 ;
     RECT  16.513 47.4 17.1 47.472 ;
     RECT  16.513 47.472 17.088 47.496 ;
     RECT  16.513 47.496 17.1 47.568 ;
     RECT  16.513 47.568 17.088 47.592 ;
     RECT  16.513 47.592 17.1 47.712 ;
     RECT  16.513 47.712 17.088 47.736 ;
     RECT  16.513 47.736 17.1 47.808 ;
     RECT  16.513 47.808 17.088 47.832 ;
     RECT  16.513 47.832 17.1 47.904 ;
     RECT  16.513 47.904 17.088 47.928 ;
     RECT  16.513 47.928 17.1 48 ;
     RECT  16.513 48 17.088 48.024 ;
     RECT  16.513 48.024 17.1 48.096 ;
     RECT  16.513 48.096 17.088 48.12 ;
     RECT  16.513 48.12 17.1 48.192 ;
     RECT  16.513 48.192 17.088 48.216 ;
     RECT  16.513 48.216 17.1 48.336 ;
     RECT  16.513 48.336 17.088 48.36 ;
     RECT  16.513 48.36 17.1 48.432 ;
     RECT  16.513 48.432 17.088 48.456 ;
     RECT  16.513 48.456 17.1 48.528 ;
     RECT  16.513 48.528 17.088 48.552 ;
     RECT  16.513 48.552 17.1 48.624 ;
     RECT  16.513 48.624 17.088 48.648 ;
     RECT  16.513 48.648 17.1 48.72 ;
     RECT  16.513 48.72 17.088 48.744 ;
     RECT  16.513 48.744 17.1 48.816 ;
     RECT  16.513 48.816 17.088 48.84 ;
     RECT  16.513 48.84 17.1 48.96 ;
     RECT  16.513 48.96 17.088 48.984 ;
     RECT  16.513 48.984 17.1 49.056 ;
     RECT  16.513 49.056 17.088 49.08 ;
     RECT  16.513 49.08 17.1 49.152 ;
     RECT  16.513 49.152 17.088 49.176 ;
     RECT  16.513 49.176 17.1 49.248 ;
     RECT  16.513 49.248 17.088 49.272 ;
     RECT  16.513 49.272 17.1 49.344 ;
     RECT  16.513 49.344 17.088 49.368 ;
     RECT  16.513 49.368 17.1 49.488 ;
     RECT  16.513 49.488 17.088 49.512 ;
     RECT  16.513 49.512 17.1 49.584 ;
     RECT  16.513 49.584 17.088 49.608 ;
     RECT  16.513 49.608 17.1 49.68 ;
     RECT  16.513 49.68 17.088 49.704 ;
     RECT  16.513 49.704 17.1 49.776 ;
     RECT  16.513 49.776 17.088 49.8 ;
     RECT  16.513 49.8 17.1 49.872 ;
     RECT  16.513 49.872 17.088 49.896 ;
     RECT  16.513 49.896 17.1 49.968 ;
     RECT  16.513 49.968 17.088 49.992 ;
     RECT  16.513 49.992 17.1 50.112 ;
     RECT  16.513 50.112 17.088 50.136 ;
     RECT  16.513 50.136 17.1 50.208 ;
     RECT  16.513 50.208 17.088 50.232 ;
     RECT  16.513 50.232 17.1 50.304 ;
     RECT  16.513 50.304 17.088 50.328 ;
     RECT  16.513 50.328 17.1 50.4 ;
     RECT  16.513 50.4 17.088 50.424 ;
     RECT  16.513 50.424 17.1 50.496 ;
     RECT  16.513 50.496 17.088 50.52 ;
     RECT  16.513 50.52 17.1 50.592 ;
     RECT  16.513 50.592 17.088 50.616 ;
     RECT  16.513 50.616 17.1 50.736 ;
     RECT  16.513 50.736 17.088 50.76 ;
     RECT  16.513 50.76 17.1 50.832 ;
     RECT  16.513 50.832 17.088 50.856 ;
     RECT  16.513 50.856 17.1 50.928 ;
     RECT  16.513 50.928 17.088 50.952 ;
     RECT  16.513 50.952 17.1 51.024 ;
     RECT  16.513 51.024 17.088 51.048 ;
     RECT  16.513 51.048 17.1 51.12 ;
     RECT  16.513 51.12 17.088 51.144 ;
     RECT  16.513 51.144 17.1 51.264 ;
     RECT  16.513 51.264 17.088 51.288 ;
     RECT  16.513 51.288 17.1 51.36 ;
     RECT  16.513 51.36 17.088 51.384 ;
     RECT  16.513 51.384 17.1 51.456 ;
     RECT  16.513 51.456 17.088 51.48 ;
     RECT  16.513 51.48 17.1 51.552 ;
     RECT  16.513 51.552 17.088 51.576 ;
     RECT  16.513 51.576 17.1 51.648 ;
     RECT  16.513 51.648 17.088 51.672 ;
     RECT  16.513 51.672 17.1 51.744 ;
     RECT  16.513 51.744 17.088 51.768 ;
     RECT  16.513 51.768 17.1 51.888 ;
     RECT  16.513 51.888 17.088 51.912 ;
     RECT  16.513 51.912 17.1 51.984 ;
     RECT  16.513 51.984 17.088 52.008 ;
     RECT  16.513 52.008 17.1 52.08 ;
     RECT  16.513 52.08 17.088 52.104 ;
     RECT  16.513 52.104 17.1 52.176 ;
     RECT  16.513 52.176 17.088 52.2 ;
     RECT  16.513 52.2 17.1 52.272 ;
     RECT  16.513 52.272 17.088 52.296 ;
     RECT  16.513 52.296 17.1 52.416 ;
     RECT  16.513 52.416 17.088 52.44 ;
     RECT  16.513 52.44 17.1 52.512 ;
     RECT  16.513 52.512 17.088 52.536 ;
     RECT  16.513 52.536 17.1 52.608 ;
     RECT  16.513 52.608 17.088 52.632 ;
     RECT  16.513 52.632 17.1 52.704 ;
     RECT  16.513 52.704 17.088 52.728 ;
     RECT  16.513 52.728 17.1 52.8 ;
     RECT  16.513 52.8 17.088 52.824 ;
     RECT  16.513 52.824 17.1 52.896 ;
     RECT  16.513 52.896 17.088 52.92 ;
     RECT  16.513 52.92 17.1 53.04 ;
     RECT  16.513 53.04 17.088 53.064 ;
     RECT  16.513 53.064 17.1 53.136 ;
     RECT  16.513 53.136 17.088 53.16 ;
     RECT  16.513 53.16 17.1 53.232 ;
     RECT  16.513 53.232 17.088 53.256 ;
     RECT  16.513 53.256 17.1 53.328 ;
     RECT  16.513 53.328 17.088 53.352 ;
     RECT  16.513 53.352 17.1 53.424 ;
     RECT  16.513 53.424 17.088 53.448 ;
     RECT  16.513 53.448 17.1 53.52 ;
     RECT  16.513 53.52 17.088 53.544 ;
     RECT  16.513 53.544 17.1 53.664 ;
     RECT  16.513 53.664 17.088 53.688 ;
     RECT  16.513 53.688 17.1 53.76 ;
     RECT  16.513 53.76 17.088 53.784 ;
     RECT  16.513 53.784 17.1 53.856 ;
     RECT  16.513 53.856 17.088 53.88 ;
     RECT  16.513 53.88 17.1 53.952 ;
     RECT  16.513 53.952 17.088 53.976 ;
     RECT  16.513 53.976 17.1 54.048 ;
     RECT  16.513 54.048 17.088 54.072 ;
     RECT  16.513 54.072 17.1 54.192 ;
     RECT  16.513 54.192 17.088 54.216 ;
     RECT  16.513 54.216 17.1 54.288 ;
     RECT  16.513 54.288 17.088 54.312 ;
     RECT  16.513 54.312 17.1 54.384 ;
     RECT  16.513 54.384 17.088 54.408 ;
     RECT  16.513 54.408 17.1 54.48 ;
     RECT  16.513 54.48 17.088 54.504 ;
     RECT  16.513 54.504 17.1 54.576 ;
     RECT  16.513 54.576 17.088 54.6 ;
     RECT  16.513 54.6 17.1 54.672 ;
     RECT  16.513 54.672 17.088 54.696 ;
     RECT  16.513 54.696 17.1 54.816 ;
     RECT  16.513 54.816 17.088 54.84 ;
     RECT  16.513 54.84 17.1 54.912 ;
     RECT  16.513 54.912 17.088 54.936 ;
     RECT  16.513 54.936 17.1 55.008 ;
     RECT  16.513 55.008 17.088 55.032 ;
     RECT  16.513 55.032 17.1 55.104 ;
     RECT  16.513 55.104 17.088 55.128 ;
     RECT  16.513 55.128 17.1 55.2 ;
     RECT  16.513 55.2 17.088 55.224 ;
     RECT  16.513 55.224 17.1 55.296 ;
     RECT  16.513 55.296 17.088 55.32 ;
     RECT  16.513 55.32 17.1 55.44 ;
     RECT  16.513 55.44 17.088 55.464 ;
     RECT  16.513 55.464 17.1 55.536 ;
     RECT  16.513 55.536 17.088 55.56 ;
     RECT  16.513 55.56 17.1 55.632 ;
     RECT  16.513 55.632 17.088 55.656 ;
     RECT  16.513 55.656 17.1 55.728 ;
     RECT  16.513 55.728 17.088 55.752 ;
     RECT  16.513 55.752 17.1 55.824 ;
     RECT  16.513 55.824 17.088 55.848 ;
     RECT  16.513 55.848 17.1 55.968 ;
     RECT  16.513 55.968 17.088 55.992 ;
     RECT  16.513 55.992 17.1 56.064 ;
     RECT  16.513 56.064 17.088 56.088 ;
     RECT  16.513 56.088 17.1 56.16 ;
     RECT  16.513 56.16 17.088 56.184 ;
     RECT  16.513 56.184 17.1 56.256 ;
     RECT  16.513 56.256 17.088 56.28 ;
     RECT  16.513 56.28 17.1 56.352 ;
     RECT  16.513 56.352 17.088 56.376 ;
     RECT  16.513 56.376 17.1 56.448 ;
     RECT  16.513 56.448 17.088 56.472 ;
     RECT  16.513 56.472 17.1 56.592 ;
     RECT  16.513 56.592 17.088 56.616 ;
     RECT  16.513 56.616 17.1 56.688 ;
     RECT  16.513 56.688 17.088 56.712 ;
     RECT  16.513 56.712 17.1 56.784 ;
     RECT  16.513 56.784 17.088 56.808 ;
     RECT  16.513 56.808 17.1 56.88 ;
     RECT  16.513 56.88 17.088 56.904 ;
     RECT  16.513 56.904 17.1 56.976 ;
     RECT  16.513 56.976 17.088 57 ;
     RECT  16.513 57 17.1 57.072 ;
     RECT  16.513 57.072 17.088 57.096 ;
     RECT  16.513 57.096 17.1 57.216 ;
     RECT  16.513 57.216 17.088 57.24 ;
     RECT  16.513 57.24 17.1 57.312 ;
     RECT  16.513 57.312 17.088 57.336 ;
     RECT  16.513 57.336 17.1 57.408 ;
     RECT  16.513 57.408 17.088 57.432 ;
     RECT  16.513 57.432 17.1 57.504 ;
     RECT  16.513 57.504 17.088 57.528 ;
     RECT  16.513 57.528 17.1 57.6 ;
     RECT  16.513 57.6 17.088 57.624 ;
     RECT  16.513 57.624 17.1 57.744 ;
     RECT  16.513 57.744 17.088 57.768 ;
     RECT  16.513 57.768 17.1 57.84 ;
     RECT  16.513 57.84 17.088 57.864 ;
     RECT  16.513 57.864 17.1 57.936 ;
     RECT  16.513 57.936 17.088 57.96 ;
     RECT  16.513 57.96 17.1 58.032 ;
     RECT  16.513 58.032 17.088 58.056 ;
     RECT  16.513 58.056 17.1 58.128 ;
     RECT  16.513 58.128 17.088 58.152 ;
     RECT  16.513 58.152 17.1 58.224 ;
     RECT  16.513 58.224 17.088 58.248 ;
     RECT  16.513 58.248 17.1 58.368 ;
     RECT  16.513 58.368 17.088 58.392 ;
     RECT  16.513 58.392 17.1 58.464 ;
     RECT  16.513 58.464 17.088 58.488 ;
     RECT  16.513 58.488 17.1 58.56 ;
     RECT  16.513 58.56 17.088 58.584 ;
     RECT  16.513 58.584 17.1 58.656 ;
     RECT  16.513 58.656 17.088 58.68 ;
     RECT  16.513 58.68 17.1 58.752 ;
     RECT  16.513 58.752 17.088 58.776 ;
     RECT  16.513 58.776 17.1 58.896 ;
     RECT  16.513 58.896 17.088 58.92 ;
     RECT  16.513 58.92 17.1 58.992 ;
     RECT  16.513 58.992 17.088 59.016 ;
     RECT  16.513 59.016 17.1 59.088 ;
     RECT  16.513 59.088 17.088 59.112 ;
     RECT  16.513 59.112 17.1 59.184 ;
     RECT  16.513 59.184 17.088 59.208 ;
     RECT  16.513 59.208 17.1 59.28 ;
     RECT  16.513 59.28 17.088 59.304 ;
     RECT  16.513 59.304 17.1 59.376 ;
     RECT  16.513 59.376 17.088 59.4 ;
     RECT  16.513 59.4 17.1 59.52 ;
     RECT  16.513 59.52 17.088 59.544 ;
     RECT  16.513 59.544 17.1 59.616 ;
     RECT  16.513 59.616 17.088 59.64 ;
     RECT  16.513 59.64 17.1 59.712 ;
     RECT  16.513 59.712 17.088 59.736 ;
     RECT  16.513 59.736 17.1 59.808 ;
     RECT  16.513 59.808 17.088 59.832 ;
     RECT  16.513 59.832 17.1 59.904 ;
     RECT  16.513 59.904 17.088 59.928 ;
     RECT  16.513 59.928 17.1 60 ;
     RECT  16.513 60 17.088 60.024 ;
     RECT  16.513 60.024 17.1 60.144 ;
     RECT  16.513 60.144 17.088 60.168 ;
     RECT  16.513 60.168 17.1 60.24 ;
     RECT  16.513 60.24 17.088 60.264 ;
     RECT  16.513 60.264 17.1 60.336 ;
     RECT  16.513 60.336 17.088 60.36 ;
     RECT  16.513 60.36 17.1 60.432 ;
     RECT  16.513 60.432 17.088 60.456 ;
     RECT  16.513 60.456 17.1 60.528 ;
     RECT  16.513 60.528 17.088 60.552 ;
     RECT  16.513 60.552 17.1 60.672 ;
     RECT  16.513 60.672 17.088 60.696 ;
     RECT  16.513 60.696 17.1 60.768 ;
     RECT  16.513 60.768 17.088 60.792 ;
     RECT  16.513 60.792 17.1 60.864 ;
     RECT  16.513 60.864 17.088 60.888 ;
     RECT  16.513 60.888 17.1 60.96 ;
     RECT  16.513 60.96 17.088 60.984 ;
     RECT  16.513 60.984 17.1 61.056 ;
     RECT  16.513 61.056 17.088 61.08 ;
     RECT  16.513 61.08 17.1 61.152 ;
     RECT  16.513 61.152 17.088 61.176 ;
     RECT  16.513 61.176 17.1 61.296 ;
     RECT  16.513 61.296 17.088 61.32 ;
     RECT  16.513 61.32 17.1 61.392 ;
     RECT  16.513 61.392 17.088 61.416 ;
     RECT  16.513 61.416 17.1 61.488 ;
     RECT  16.513 61.488 17.088 61.512 ;
     RECT  16.513 61.512 17.1 61.584 ;
     RECT  16.513 61.584 17.088 61.608 ;
     RECT  16.513 61.608 17.1 61.68 ;
     RECT  16.513 61.68 17.088 61.704 ;
     RECT  16.513 61.704 17.1 61.776 ;
     RECT  16.513 61.776 17.088 61.8 ;
     RECT  16.513 61.8 17.1 61.92 ;
     RECT  16.513 61.92 17.088 61.944 ;
     RECT  16.513 61.944 17.1 62.016 ;
     RECT  16.513 62.016 17.088 62.04 ;
     RECT  16.513 62.04 17.1 62.112 ;
     RECT  16.513 62.112 17.088 62.136 ;
     RECT  16.513 62.136 17.1 62.208 ;
     RECT  16.513 62.208 17.088 62.232 ;
     RECT  16.513 62.232 17.1 62.304 ;
     RECT  16.513 62.304 17.088 62.328 ;
     RECT  16.513 62.328 17.1 62.448 ;
     RECT  16.513 62.448 17.088 62.472 ;
     RECT  16.513 62.472 17.1 62.544 ;
     RECT  16.513 62.544 17.088 62.568 ;
     RECT  16.513 62.568 17.1 62.64 ;
     RECT  16.513 62.64 17.088 62.664 ;
     RECT  16.513 62.664 17.1 62.736 ;
     RECT  16.513 62.736 17.088 62.76 ;
     RECT  16.513 62.76 17.1 62.832 ;
     RECT  16.513 62.832 17.088 62.856 ;
     RECT  16.513 62.856 17.1 62.928 ;
     RECT  16.513 62.928 17.088 62.952 ;
     RECT  16.513 62.952 17.1 63.072 ;
     RECT  16.513 63.072 17.088 63.096 ;
     RECT  16.513 63.096 17.1 63.168 ;
     RECT  16.513 63.168 17.088 63.192 ;
     RECT  16.513 63.192 17.1 63.264 ;
     RECT  16.513 63.264 17.088 63.288 ;
     RECT  16.513 63.288 17.1 63.36 ;
     RECT  16.513 63.36 17.088 63.384 ;
     RECT  16.513 63.384 17.1 63.456 ;
     RECT  16.513 63.456 17.088 63.48 ;
     RECT  16.513 63.48 17.1 63.552 ;
     RECT  16.513 63.552 17.088 63.576 ;
     RECT  16.513 63.576 17.1 63.696 ;
     RECT  16.513 63.696 17.088 63.72 ;
     RECT  16.513 63.72 17.1 63.792 ;
     RECT  16.513 63.792 17.088 63.816 ;
     RECT  16.513 63.816 17.1 63.888 ;
     RECT  16.513 63.888 17.088 63.912 ;
     RECT  16.513 63.912 17.1 63.984 ;
     RECT  16.513 63.984 17.088 64.008 ;
     RECT  16.513 64.008 17.1 64.08 ;
     RECT  16.513 64.08 17.088 64.104 ;
     RECT  16.513 64.104 17.1 64.224 ;
     RECT  16.513 64.224 17.088 64.248 ;
     RECT  16.513 64.248 17.1 64.32 ;
     RECT  16.513 64.32 17.088 64.344 ;
     RECT  16.513 64.344 17.1 64.416 ;
     RECT  16.513 64.416 17.088 64.44 ;
     RECT  16.513 64.44 17.1 64.512 ;
     RECT  16.513 64.512 17.088 64.536 ;
     RECT  16.513 64.536 17.1 64.608 ;
     RECT  16.513 64.608 17.088 64.632 ;
     RECT  16.513 64.632 17.1 64.704 ;
     RECT  16.513 64.704 17.088 64.728 ;
     RECT  16.513 64.728 17.1 64.848 ;
     RECT  16.513 64.848 17.088 64.872 ;
     RECT  16.513 64.872 17.1 64.944 ;
     RECT  16.513 64.944 17.088 64.968 ;
     RECT  16.513 64.968 17.1 65.04 ;
     RECT  16.513 65.04 17.088 65.064 ;
     RECT  16.513 65.064 17.1 65.136 ;
     RECT  16.513 65.136 17.088 65.16 ;
     RECT  16.513 65.16 17.1 65.232 ;
     RECT  16.513 65.232 17.088 65.256 ;
     RECT  16.513 65.256 17.1 65.328 ;
     RECT  16.513 65.328 17.088 65.352 ;
     RECT  16.513 65.352 17.1 65.472 ;
     RECT  16.513 65.472 17.088 65.496 ;
     RECT  16.513 65.496 17.1 65.568 ;
     RECT  16.513 65.568 17.088 65.592 ;
     RECT  16.513 65.592 17.1 65.664 ;
     RECT  16.513 65.664 17.088 65.688 ;
     RECT  16.513 65.688 17.1 65.76 ;
     RECT  16.513 65.76 17.088 65.784 ;
     RECT  16.513 65.784 17.1 65.856 ;
     RECT  16.513 65.856 17.088 65.88 ;
     RECT  16.513 65.88 17.1 66 ;
     RECT  16.513 66 17.088 66.024 ;
     RECT  16.513 66.024 17.1 66.096 ;
     RECT  16.513 66.096 17.088 66.12 ;
     RECT  16.513 66.12 17.1 66.192 ;
     RECT  16.513 66.192 17.088 66.216 ;
     RECT  16.513 66.216 17.1 66.288 ;
     RECT  16.513 66.288 17.088 66.312 ;
     RECT  16.513 66.312 17.1 66.384 ;
     RECT  16.513 66.384 17.088 66.408 ;
     RECT  16.513 66.408 17.1 66.48 ;
     RECT  16.513 66.48 17.088 66.504 ;
     RECT  16.513 66.504 17.1 66.624 ;
     RECT  16.513 66.624 17.088 66.648 ;
     RECT  16.513 66.648 17.1 66.72 ;
     RECT  16.513 66.72 17.088 66.744 ;
     RECT  16.513 66.744 17.1 66.816 ;
     RECT  16.513 66.816 17.088 66.84 ;
     RECT  16.513 66.84 17.1 66.912 ;
     RECT  16.513 66.912 17.088 66.936 ;
     RECT  16.513 66.936 17.1 67.008 ;
     RECT  16.513 67.008 17.088 67.032 ;
     RECT  16.513 67.032 17.1 67.152 ;
     RECT  16.513 67.152 17.088 67.176 ;
     RECT  16.513 67.176 17.1 67.248 ;
     RECT  16.513 67.248 17.088 67.272 ;
     RECT  16.513 67.272 17.1 67.344 ;
     RECT  16.513 67.344 17.088 67.368 ;
     RECT  16.513 67.368 17.1 67.44 ;
     RECT  16.513 67.44 17.088 67.464 ;
     RECT  16.513 67.464 17.1 67.536 ;
     RECT  16.513 67.536 17.088 67.56 ;
     RECT  16.513 67.56 17.1 67.632 ;
     RECT  16.513 67.632 17.088 67.656 ;
     RECT  16.513 67.656 17.1 67.776 ;
     RECT  16.513 67.776 17.088 67.8 ;
     RECT  16.513 67.8 17.1 67.872 ;
     RECT  16.513 67.872 17.088 67.896 ;
     RECT  16.513 67.896 17.1 67.968 ;
     RECT  16.513 67.968 17.088 67.992 ;
     RECT  16.513 67.992 17.1 68.064 ;
     RECT  16.513 68.064 17.088 68.088 ;
     RECT  16.513 68.088 17.1 68.16 ;
     RECT  16.513 68.16 17.088 68.184 ;
     RECT  16.513 68.184 17.1 68.256 ;
     RECT  16.513 68.256 17.088 68.28 ;
     RECT  16.513 68.28 17.1 68.4 ;
     RECT  16.513 68.4 17.088 68.424 ;
     RECT  16.513 68.424 17.1 68.496 ;
     RECT  16.513 68.496 17.088 68.52 ;
     RECT  16.513 68.52 17.1 68.592 ;
     RECT  16.513 68.592 17.088 68.616 ;
     RECT  16.513 68.616 17.1 68.688 ;
     RECT  16.513 68.688 17.088 68.712 ;
     RECT  16.513 68.712 17.1 68.784 ;
     RECT  16.513 68.784 17.088 68.808 ;
     RECT  16.513 68.808 17.1 68.928 ;
     RECT  16.513 68.928 17.088 68.952 ;
     RECT  16.513 68.952 17.1 69.024 ;
     RECT  16.513 69.024 17.088 69.048 ;
     RECT  16.513 69.048 17.1 69.12 ;
     RECT  16.513 69.12 17.088 69.144 ;
     RECT  16.513 69.144 17.1 69.216 ;
     RECT  16.513 69.216 17.088 69.24 ;
     RECT  16.513 69.24 17.1 69.312 ;
     RECT  16.513 69.312 17.088 69.336 ;
     RECT  16.513 69.336 17.1 69.408 ;
     RECT  16.513 69.408 17.088 69.432 ;
     RECT  16.513 69.432 17.1 69.552 ;
     RECT  16.513 69.552 17.088 69.576 ;
     RECT  16.513 69.576 17.1 69.648 ;
     RECT  16.513 69.648 17.088 69.672 ;
     RECT  16.513 69.672 17.1 69.744 ;
     RECT  16.513 69.744 17.088 69.768 ;
     RECT  16.513 69.768 17.1 69.84 ;
     RECT  16.513 69.84 17.088 69.864 ;
     RECT  16.513 69.864 17.1 69.936 ;
     RECT  16.513 69.936 17.088 69.96 ;
     RECT  16.513 69.96 17.1 70.032 ;
     RECT  16.513 70.032 17.088 70.056 ;
     RECT  16.513 70.056 17.1 70.176 ;
     RECT  16.513 70.176 17.088 70.2 ;
     RECT  16.513 70.2 17.1 70.272 ;
     RECT  16.513 70.272 17.088 70.296 ;
     RECT  16.513 70.296 17.1 70.368 ;
     RECT  16.513 70.368 17.088 70.392 ;
     RECT  16.513 70.392 17.1 70.464 ;
     RECT  16.513 70.464 17.088 70.488 ;
     RECT  16.513 70.488 17.1 70.56 ;
     RECT  16.513 70.56 17.088 70.584 ;
     RECT  16.513 70.584 17.1 70.704 ;
     RECT  16.513 70.704 17.088 70.728 ;
     RECT  16.513 70.728 17.1 70.8 ;
     RECT  16.513 70.8 17.088 70.824 ;
     RECT  16.513 70.824 17.1 70.896 ;
     RECT  16.513 70.896 17.088 70.92 ;
     RECT  16.513 70.92 17.1 70.992 ;
     RECT  16.513 70.992 17.088 71.016 ;
     RECT  16.513 71.016 17.1 71.088 ;
     RECT  16.513 71.088 17.088 71.112 ;
     RECT  16.513 71.112 17.1 71.184 ;
     RECT  16.513 71.184 17.088 71.208 ;
     RECT  16.513 71.208 17.1 71.328 ;
     RECT  16.513 71.328 17.088 71.352 ;
     RECT  16.513 71.352 17.1 71.424 ;
     RECT  16.513 71.424 17.088 71.448 ;
     RECT  16.513 71.448 17.1 71.52 ;
     RECT  16.513 71.52 17.088 71.544 ;
     RECT  16.513 71.544 17.1 71.616 ;
     RECT  16.513 71.616 17.088 71.64 ;
     RECT  16.513 71.64 17.1 71.712 ;
     RECT  16.513 71.712 17.088 71.736 ;
     RECT  16.513 71.736 17.1 71.856 ;
     RECT  16.513 71.856 17.088 71.88 ;
     RECT  16.513 71.88 17.1 71.952 ;
     RECT  16.513 71.952 17.088 71.976 ;
     RECT  16.513 71.976 17.1 72.048 ;
     RECT  16.513 72.048 17.088 72.072 ;
     RECT  16.513 72.072 17.1 72.144 ;
     RECT  16.513 72.144 17.088 72.168 ;
     RECT  16.513 72.168 17.1 72.24 ;
     RECT  16.513 72.24 17.088 72.264 ;
     RECT  16.513 72.264 17.1 72.336 ;
     RECT  16.513 72.336 17.088 72.36 ;
     RECT  16.513 72.36 17.1 72.48 ;
     RECT  16.513 72.48 17.088 72.504 ;
     RECT  16.513 72.504 17.1 72.576 ;
     RECT  16.513 72.576 17.088 72.6 ;
     RECT  16.513 72.6 17.1 72.672 ;
     RECT  16.513 72.672 17.088 72.696 ;
     RECT  16.513 72.696 17.1 72.768 ;
     RECT  16.513 72.768 17.088 72.792 ;
     RECT  16.513 72.792 17.1 72.864 ;
     RECT  16.513 72.864 17.088 72.888 ;
     RECT  16.513 72.888 17.1 72.96 ;
     RECT  16.513 72.96 17.088 72.984 ;
     RECT  16.513 72.984 17.1 73.104 ;
     RECT  16.513 73.104 17.088 73.128 ;
     RECT  16.513 73.128 17.1 73.2 ;
     RECT  16.513 73.2 17.088 73.224 ;
     RECT  16.513 73.224 17.1 73.296 ;
     RECT  16.513 73.296 17.088 73.32 ;
     RECT  16.513 73.32 17.1 73.392 ;
     RECT  16.513 73.392 17.088 73.416 ;
     RECT  17.1 7.92 17.165 7.968 ;
     RECT  17.1 7.992 17.165 8.064 ;
     RECT  17.1 8.088 17.165 8.16 ;
     RECT  17.1 8.184 17.165 8.28 ;
     RECT  17.1 9.888 17.165 9.936 ;
     RECT  17.1 9.96 17.165 10.08 ;
     RECT  17.1 10.104 17.165 10.176 ;
     RECT  17.1 10.2 17.165 10.272 ;
     RECT  17.1 10.296 17.165 10.368 ;
     RECT  17.1 10.392 17.165 10.44 ;
     RECT  17.1 12.192 17.165 12.216 ;
     RECT  17.1 18.816 17.165 18.84 ;
     RECT  17.1 23.088 17.165 23.112 ;
     RECT  17.1 25.152 17.165 25.2 ;
     RECT  17.1 25.224 17.165 25.344 ;
     RECT  17.1 25.368 17.165 25.44 ;
     RECT  17.1 25.464 17.165 25.536 ;
     RECT  17.1 25.56 17.165 25.632 ;
     RECT  17.1 25.656 17.165 25.728 ;
     RECT  17.1 25.752 17.165 25.8 ;
     RECT  17.1 26.832 17.165 26.88 ;
     RECT  17.1 26.904 17.165 26.976 ;
     RECT  17.1 27 17.165 27.12 ;
     RECT  17.1 27.144 17.165 27.192 ;
     RECT  17.1 28.704 17.165 28.728 ;
     RECT  17.1 30.096 17.165 30.12 ;
     RECT  17.1 31.2 17.165 31.296 ;
     RECT  17.1 31.32 17.165 31.392 ;
     RECT  17.1 31.416 17.165 31.488 ;
     RECT  17.1 31.512 17.165 31.584 ;
     RECT  17.1 31.608 17.165 31.656 ;
     RECT  17.1 33.024 17.165 33.072 ;
     RECT  17.1 33.096 17.165 33.168 ;
     RECT  17.1 33.192 17.165 33.264 ;
     RECT  17.1 33.288 17.165 33.36 ;
     RECT  17.1 33.384 17.165 33.432 ;
     RECT  17.1 35.184 17.165 35.232 ;
     RECT  17.1 35.256 17.165 35.376 ;
     RECT  17.1 35.4 17.165 35.472 ;
     RECT  17.1 35.496 17.165 35.568 ;
     RECT  17.1 35.592 17.165 35.664 ;
     RECT  17.1 35.688 17.165 35.76 ;
     RECT  17.1 35.784 17.165 35.832 ;
     RECT  17.1 37.392 17.165 37.416 ;
     RECT  17.1 47.616 17.165 47.64 ;
     RECT  17.1 50.16 17.165 50.208 ;
     RECT  17.1 50.232 17.165 50.304 ;
     RECT  17.1 50.328 17.165 50.4 ;
     RECT  17.1 50.424 17.165 50.496 ;
     RECT  17.1 50.52 17.165 50.592 ;
     RECT  17.1 50.616 17.165 50.736 ;
     RECT  17.1 50.76 17.165 50.832 ;
     RECT  17.1 50.856 17.165 50.928 ;
     RECT  17.1 50.952 17.165 51.024 ;
     RECT  17.1 51.048 17.165 51.096 ;
     RECT  17.1 52.224 17.165 52.272 ;
     RECT  17.1 52.296 17.165 52.416 ;
     RECT  17.1 52.44 17.165 52.488 ;
     RECT  17.1 54.432 17.165 54.48 ;
     RECT  17.1 54.504 17.165 54.576 ;
     RECT  17.1 54.6 17.165 54.672 ;
     RECT  17.1 54.696 17.165 54.816 ;
     RECT  17.1 54.84 17.165 54.912 ;
     RECT  17.1 54.936 17.165 55.008 ;
     RECT  17.1 55.032 17.165 55.104 ;
     RECT  17.1 55.128 17.165 55.2 ;
     RECT  17.1 55.224 17.165 55.296 ;
     RECT  17.1 55.32 17.165 55.44 ;
     RECT  17.1 55.464 17.165 55.536 ;
     RECT  17.1 55.56 17.165 55.632 ;
     RECT  17.1 55.656 17.165 55.728 ;
     RECT  17.1 55.752 17.165 55.824 ;
     RECT  17.1 55.848 17.165 55.968 ;
     RECT  17.1 55.992 17.165 56.04 ;
     RECT  17.1 57.168 17.165 57.192 ;
     RECT  17.1 60.288 17.165 60.336 ;
     RECT  17.1 60.36 17.165 60.432 ;
     RECT  17.1 60.456 17.165 60.528 ;
     RECT  17.1 60.552 17.165 60.672 ;
     RECT  17.1 60.696 17.165 60.768 ;
     RECT  17.1 60.792 17.165 60.864 ;
     RECT  17.1 60.888 17.165 60.96 ;
     RECT  17.1 60.984 17.165 61.056 ;
     RECT  17.1 61.08 17.165 61.128 ;
     RECT  17.1 63.024 17.165 63.048 ;
     RECT  17.1 66.864 17.165 66.888 ;
     RECT  17.1 70.848 17.165 70.896 ;
     RECT  17.1 70.92 17.165 70.992 ;
     RECT  17.1 71.016 17.165 71.088 ;
     RECT  17.1 71.112 17.165 71.184 ;
     RECT  17.1 71.208 17.165 71.328 ;
     RECT  17.1 71.352 17.165 71.424 ;
     RECT  17.1 71.448 17.165 71.496 ;
     RECT  17.1 73.248 17.165 73.272 ;
    LAYER M5 ;
     RECT  2.4 2.137 2.52 2.151 ;
     RECT  5.1 2.137 5.22 2.151 ;
     RECT  7.8 2.137 7.92 2.151 ;
     RECT  10.5 2.137 10.62 2.151 ;
     RECT  13.2 2.137 13.32 2.151 ;
     RECT  6.672 2.245 6.696 4.117 ;
     RECT  6.432 4.117 6.696 4.163 ;
     RECT  14.832 4.165 14.856 4.307 ;
     RECT  7.8 2.151 8.112 5.029 ;
     RECT  0.192 4.885 0.216 5.075 ;
     RECT  7.536 5.029 8.112 5.171 ;
     RECT  7.8 5.171 8.112 5.221 ;
     RECT  7.8 5.221 9.048 6.085 ;
     RECT  7.8 6.085 9.096 6.275 ;
     RECT  10.5 2.151 10.812 6.901 ;
     RECT  10.5 6.901 11.256 7.379 ;
     RECT  2.4 2.151 2.712 7.717 ;
     RECT  2.256 7.717 2.712 7.907 ;
     RECT  7.8 6.275 8.808 8.485 ;
     RECT  10.5 7.379 10.812 9.493 ;
     RECT  7.8 8.485 9.432 10.883 ;
     RECT  10.5 9.493 10.92 10.931 ;
     RECT  7.8 10.883 8.808 12.373 ;
     RECT  7.8 12.373 9.384 12.515 ;
     RECT  1.152 11.749 1.176 13.091 ;
     RECT  7.8 12.515 9.048 14.053 ;
     RECT  1.248 14.101 1.272 14.243 ;
     RECT  10.5 10.931 10.812 14.773 ;
     RECT  7.8 14.053 9.144 14.915 ;
     RECT  10.5 14.773 11.064 14.917 ;
     RECT  10.272 14.917 11.064 15.443 ;
     RECT  12.048 15.493 12.072 15.779 ;
     RECT  2.4 7.907 2.712 16.261 ;
     RECT  7.8 14.915 9.048 16.309 ;
     RECT  2.256 16.261 2.712 16.451 ;
     RECT  7.8 16.309 9.144 16.451 ;
     RECT  6.432 4.163 6.456 16.549 ;
     RECT  6.432 16.549 6.648 16.595 ;
     RECT  10.272 15.443 10.812 16.595 ;
     RECT  7.8 16.451 9.048 17.653 ;
     RECT  7.8 17.653 9.144 18.323 ;
     RECT  7.8 18.323 9.048 19.333 ;
     RECT  10.5 16.595 10.812 19.909 ;
     RECT  7.8 19.333 9.384 20.099 ;
     RECT  9.36 20.099 9.384 20.531 ;
     RECT  7.8 20.099 8.376 20.867 ;
     RECT  6.624 16.595 6.648 21.923 ;
     RECT  9.12 22.021 9.144 22.163 ;
     RECT  2.4 16.451 2.712 22.645 ;
     RECT  10.5 19.909 10.92 22.693 ;
     RECT  2.304 22.645 2.712 22.787 ;
     RECT  9.792 22.693 10.92 23.125 ;
     RECT  9.36 23.125 10.92 23.699 ;
     RECT  7.8 20.867 8.112 24.469 ;
     RECT  6.528 22.213 6.552 24.565 ;
     RECT  7.8 24.469 8.232 24.565 ;
     RECT  6.528 24.565 8.232 24.611 ;
     RECT  7.44 24.611 8.232 25.381 ;
     RECT  9.648 23.699 10.92 25.381 ;
     RECT  7.44 25.381 10.968 25.619 ;
     RECT  7.44 25.619 8.112 26.243 ;
     RECT  7.632 26.243 8.112 26.869 ;
     RECT  9.12 25.619 10.968 26.869 ;
     RECT  7.632 26.869 10.968 27.061 ;
     RECT  7.632 27.061 11.64 27.155 ;
     RECT  9.792 27.155 11.64 27.203 ;
     RECT  9.792 27.203 10.812 30.421 ;
     RECT  9.792 30.421 11.496 30.659 ;
     RECT  7.632 27.155 8.112 30.803 ;
     RECT  7.68 30.803 8.112 31.763 ;
     RECT  9.792 30.659 10.812 31.861 ;
     RECT  9.552 31.861 10.812 32.531 ;
     RECT  7.8 31.763 8.112 33.013 ;
     RECT  0.288 32.869 0.312 33.587 ;
     RECT  7.68 33.013 8.112 34.165 ;
     RECT  7.68 34.165 8.28 35.411 ;
     RECT  7.68 35.411 8.112 36.515 ;
     RECT  0.288 36.613 0.312 36.899 ;
     RECT  14.832 36.853 14.856 36.995 ;
     RECT  9.792 32.531 10.812 36.997 ;
     RECT  7.8 36.515 8.112 37.381 ;
     RECT  9.12 36.997 10.812 37.381 ;
     RECT  13.2 2.151 13.512 37.381 ;
     RECT  7.8 37.381 10.968 37.619 ;
     RECT  13.2 37.381 13.944 37.619 ;
     RECT  7.8 37.619 10.812 37.859 ;
     RECT  9.12 37.859 10.812 38.435 ;
     RECT  9.792 38.435 10.812 38.677 ;
     RECT  5.1 2.151 5.412 38.725 ;
     RECT  6.432 37.573 6.456 38.725 ;
     RECT  9.792 38.677 11.4 38.771 ;
     RECT  9.936 38.771 11.4 39.299 ;
     RECT  5.1 38.725 6.456 40.069 ;
     RECT  14.832 40.117 14.856 40.259 ;
     RECT  1.248 40.069 1.272 40.355 ;
     RECT  4.56 40.069 6.456 40.355 ;
     RECT  0.192 40.645 0.216 40.979 ;
     RECT  7.8 37.859 8.112 41.749 ;
     RECT  9.936 39.299 10.812 41.749 ;
     RECT  7.8 41.749 10.812 41.987 ;
     RECT  7.8 41.987 8.112 42.277 ;
     RECT  9.936 41.987 10.812 42.565 ;
     RECT  5.1 40.355 6.456 43.379 ;
     RECT  13.2 37.619 13.512 43.813 ;
     RECT  13.104 43.813 13.512 44.675 ;
     RECT  9.936 42.565 10.92 44.917 ;
     RECT  5.1 43.379 6.408 45.059 ;
     RECT  9.936 44.917 11.112 47.269 ;
     RECT  9.408 47.269 11.112 47.557 ;
     RECT  9.408 47.557 11.592 47.699 ;
     RECT  9.408 47.699 11.112 47.797 ;
     RECT  13.2 44.675 13.512 48.085 ;
     RECT  7.632 42.277 8.112 48.373 ;
     RECT  9.312 47.797 11.112 48.373 ;
     RECT  13.2 48.085 13.608 48.419 ;
     RECT  7.632 48.373 11.112 49.283 ;
     RECT  7.632 49.283 10.92 49.667 ;
     RECT  5.1 45.059 5.592 49.957 ;
     RECT  7.632 49.667 10.812 50.003 ;
     RECT  12.048 50.005 12.072 50.147 ;
     RECT  5.1 49.957 6.552 50.867 ;
     RECT  7.8 50.003 10.812 51.635 ;
     RECT  2.4 22.787 2.712 51.637 ;
     RECT  2.304 51.637 2.712 51.779 ;
     RECT  9.936 51.635 10.812 52.789 ;
     RECT  6.576 51.253 6.6 53.557 ;
     RECT  7.8 51.635 8.904 53.557 ;
     RECT  6.576 53.557 8.904 53.603 ;
     RECT  6.864 53.603 8.904 53.797 ;
     RECT  9.936 52.789 11.016 53.797 ;
     RECT  6.864 53.797 11.016 54.179 ;
     RECT  2.4 51.779 2.712 54.325 ;
     RECT  13.2 48.419 13.512 54.421 ;
     RECT  2.304 54.325 2.712 54.467 ;
     RECT  6.864 54.179 10.812 54.659 ;
     RECT  12.768 54.421 13.512 54.707 ;
     RECT  12.048 56.005 12.072 56.197 ;
     RECT  13.2 54.707 13.512 56.245 ;
     RECT  12.048 56.197 12.168 56.387 ;
     RECT  13.2 56.245 13.656 56.387 ;
     RECT  9.12 54.659 10.812 56.435 ;
     RECT  9.36 56.435 10.812 56.531 ;
     RECT  10.5 56.531 10.812 56.869 ;
     RECT  10.5 56.869 10.968 57.589 ;
     RECT  2.4 54.467 2.712 58.405 ;
     RECT  10.368 57.589 10.968 58.549 ;
     RECT  2.16 58.405 2.712 58.595 ;
     RECT  13.2 56.387 13.512 58.645 ;
     RECT  10.368 58.549 11.064 59.699 ;
     RECT  14.832 59.653 14.856 59.795 ;
     RECT  6.864 54.659 8.112 60.325 ;
     RECT  6.768 60.325 8.112 60.371 ;
     RECT  10.368 59.699 10.812 60.611 ;
     RECT  12.576 58.645 13.512 61.525 ;
     RECT  10.5 60.611 10.812 61.813 ;
     RECT  10.5 61.813 10.92 62.003 ;
     RECT  12.528 61.525 13.512 62.435 ;
     RECT  2.4 58.595 2.712 62.869 ;
     RECT  2.16 62.869 2.712 63.059 ;
     RECT  13.104 62.435 13.512 63.251 ;
     RECT  7.8 60.371 8.112 64.165 ;
     RECT  9.36 56.531 9.384 64.165 ;
     RECT  7.8 64.165 9.384 64.355 ;
     RECT  10.5 62.003 10.812 65.221 ;
     RECT  10.5 65.221 11.496 65.459 ;
     RECT  7.8 64.355 9.096 65.461 ;
     RECT  10.5 65.459 10.812 65.461 ;
     RECT  7.8 65.461 10.812 66.755 ;
     RECT  13.2 63.251 13.512 66.805 ;
     RECT  13.2 66.805 13.944 67.139 ;
     RECT  10.5 66.755 10.812 67.813 ;
     RECT  10.5 67.813 11.208 67.909 ;
     RECT  10.5 67.909 11.304 68.147 ;
     RECT  7.8 66.755 9.096 69.587 ;
     RECT  10.5 68.147 10.812 69.829 ;
     RECT  11.856 69.445 11.88 69.829 ;
     RECT  10.5 69.829 11.88 70.019 ;
     RECT  7.8 69.587 8.112 70.693 ;
     RECT  7.8 70.693 9.096 70.789 ;
     RECT  7.8 70.789 9.144 71.123 ;
     RECT  6.768 60.371 6.792 71.411 ;
     RECT  13.2 67.139 13.512 72.133 ;
     RECT  12.48 72.133 13.512 72.275 ;
     RECT  12.576 72.275 13.512 72.323 ;
     RECT  14.832 71.941 14.856 72.371 ;
     RECT  7.8 71.123 8.112 72.421 ;
     RECT  10.5 70.019 10.968 72.515 ;
     RECT  7.8 72.421 9.048 72.563 ;
     RECT  5.1 50.867 5.592 72.709 ;
     RECT  5.1 72.709 6.504 73.283 ;
     RECT  2.4 63.059 2.712 73.449 ;
     RECT  7.8 72.563 8.112 73.449 ;
     RECT  10.5 72.515 10.812 73.449 ;
     RECT  13.2 72.323 13.512 73.449 ;
     RECT  2.4 73.449 2.52 73.463 ;
     RECT  5.1 73.283 5.592 73.463 ;
     RECT  7.8 73.449 7.92 73.463 ;
     RECT  10.5 73.449 10.62 73.463 ;
     RECT  13.2 73.449 13.32 73.463 ;
     RECT  5.568 73.463 5.592 74.723 ;
     RECT  5.412 2.245 6.672 4.117 ;
     RECT  6.696 2.245 7.8 4.163 ;
     RECT  5.412 4.117 6.432 16.595 ;
     RECT  6.456 4.163 7.8 5.029 ;
     RECT  13.512 4.165 14.832 4.307 ;
     RECT  6.456 5.029 7.536 5.171 ;
     RECT  6.456 5.171 7.8 16.549 ;
     RECT  9.048 5.221 10.5 6.085 ;
     RECT  9.096 6.085 10.5 6.275 ;
     RECT  9.432 8.485 10.5 10.883 ;
     RECT  8.808 10.883 10.5 12.373 ;
     RECT  1.176 11.749 2.4 13.091 ;
     RECT  9.384 12.373 10.5 12.515 ;
     RECT  9.048 12.515 10.5 14.053 ;
     RECT  1.248 13.091 2.4 14.101 ;
     RECT  9.144 14.053 10.5 14.915 ;
     RECT  1.272 14.101 2.4 14.243 ;
     RECT  9.048 14.915 10.5 14.917 ;
     RECT  9.048 14.917 10.272 16.309 ;
     RECT  10.812 15.443 11.064 15.493 ;
     RECT  10.812 15.493 12.048 15.779 ;
     RECT  12.072 15.493 13.2 15.779 ;
     RECT  9.144 16.309 10.272 16.451 ;
     RECT  9.048 16.451 10.272 16.595 ;
     RECT  6.648 16.549 7.8 21.923 ;
     RECT  5.412 16.595 6.624 21.923 ;
     RECT  9.048 16.595 10.5 17.653 ;
     RECT  9.144 17.653 10.5 18.323 ;
     RECT  9.048 18.323 10.5 19.333 ;
     RECT  9.384 19.333 10.5 20.531 ;
     RECT  8.376 20.099 9.36 20.531 ;
     RECT  8.376 20.531 10.5 20.867 ;
     RECT  8.112 20.867 10.5 22.021 ;
     RECT  5.412 21.923 7.8 22.213 ;
     RECT  8.112 22.021 9.12 22.163 ;
     RECT  9.144 22.021 10.5 22.163 ;
     RECT  8.112 22.163 10.5 22.693 ;
     RECT  5.412 22.213 6.528 24.611 ;
     RECT  6.552 22.213 7.8 24.565 ;
     RECT  8.112 22.693 9.792 23.125 ;
     RECT  8.112 23.125 9.36 23.699 ;
     RECT  8.112 23.699 9.648 24.469 ;
     RECT  8.232 24.469 9.648 25.381 ;
     RECT  8.112 25.619 9.12 26.869 ;
     RECT  7.68 31.763 7.8 33.013 ;
     RECT  8.112 31.861 9.552 32.531 ;
     RECT  8.28 34.165 9.792 35.411 ;
     RECT  7.68 36.515 7.8 37.573 ;
     RECT  13.512 36.853 14.832 36.995 ;
     RECT  13.512 36.995 13.944 37.381 ;
     RECT  8.112 36.997 9.12 37.381 ;
     RECT  5.412 37.573 6.432 38.725 ;
     RECT  6.456 37.573 7.8 42.277 ;
     RECT  10.812 37.619 10.968 38.677 ;
     RECT  8.112 37.859 9.12 38.435 ;
     RECT  1.272 40.069 2.4 40.355 ;
     RECT  13.512 40.117 14.832 40.259 ;
     RECT  6.456 42.277 7.632 43.379 ;
     RECT  6.408 43.379 7.632 45.059 ;
     RECT  8.112 47.269 9.408 47.797 ;
     RECT  8.112 47.797 9.312 48.373 ;
     RECT  10.92 49.283 11.112 49.667 ;
     RECT  10.812 49.667 11.112 50.005 ;
     RECT  6.552 49.957 7.632 50.003 ;
     RECT  6.552 50.003 7.8 50.867 ;
     RECT  10.812 50.005 12.048 50.147 ;
     RECT  12.072 50.005 13.2 50.147 ;
     RECT  5.592 50.867 7.8 51.253 ;
     RECT  5.592 51.253 6.576 53.603 ;
     RECT  6.6 51.253 7.8 53.557 ;
     RECT  8.904 51.635 9.936 53.797 ;
     RECT  5.592 53.603 6.864 60.325 ;
     RECT  8.112 54.659 9.12 56.435 ;
     RECT  12.768 54.707 13.2 56.005 ;
     RECT  10.812 56.005 12.048 56.387 ;
     RECT  12.072 56.005 13.2 56.197 ;
     RECT  12.168 56.197 13.2 56.387 ;
     RECT  10.812 56.387 10.968 56.869 ;
     RECT  8.112 56.435 9.36 64.165 ;
     RECT  9.384 56.531 10.5 57.589 ;
     RECT  9.384 57.589 10.368 60.611 ;
     RECT  11.064 58.645 12.576 59.699 ;
     RECT  13.512 59.653 14.832 59.795 ;
     RECT  5.592 60.325 6.768 71.411 ;
     RECT  6.792 60.371 7.8 71.411 ;
     RECT  9.384 60.611 10.5 64.355 ;
     RECT  9.096 64.355 10.5 65.461 ;
     RECT  9.096 66.755 10.5 69.587 ;
     RECT  10.812 68.147 11.304 69.445 ;
     RECT  10.812 69.445 11.856 69.829 ;
     RECT  11.88 69.445 13.2 70.019 ;
     RECT  8.112 69.587 10.5 70.693 ;
     RECT  9.096 70.693 10.5 70.789 ;
     RECT  9.144 70.789 10.5 71.123 ;
     RECT  8.112 71.123 10.5 72.421 ;
     RECT  5.592 71.411 7.8 72.709 ;
     RECT  13.512 71.941 14.832 72.371 ;
     RECT  10.968 72.133 12.48 72.275 ;
     RECT  9.048 72.421 10.5 72.563 ;
     RECT  6.504 72.709 7.8 73.283 ;
  END
END dsfd_dvrlyh_682_EW
END LIBRARY
